<?xml version="1.0" encoding="UTF-8"?>
<device schemaVersion="1.1" xmlns:xs="http://www.w3.org/2001/XMLSchema-instance" xs:noNamespaceSchemaLocation="CMSIS-SVD_Schema_1_1.xsd">
  <vendor>Freescale Semiconductor, Inc.</vendor>
  <vendorID>Freescale</vendorID>
  <series>Kinetis_L</series>
  <name>MKL46Z4</name>
  <version>1.6</version>
  <description>MKL46Z4 Freescale Microcontroller</description>
  <licenseText>Redistribution and use in source and binary forms, with or without modification,\nare permitted provided that the following conditions are met:\n o Redistributions of source code must retain the above copyright notice, this list\n   of conditions and the following disclaimer.\n o Redistributions in binary form must reproduce the above copyright notice, this\n   list of conditions and the following disclaimer in the documentation and/or\n   other materials provided with the distribution.\n o Neither the name of Freescale Semiconductor, Inc. nor the names of its\n   contributors may be used to endorse or promote products derived from this\n   software without specific prior written permission.\n THIS SOFTWARE IS PROVIDED BY THE COPYRIGHT HOLDERS AND CONTRIBUTORS &quot;AS IS&quot; AND\n ANY EXPRESS OR IMPLIED WARRANTIES, INCLUDING, BUT NOT LIMITED TO, THE IMPLIED\n WARRANTIES OF MERCHANTABILITY AND FITNESS FOR A PARTICULAR PURPOSE ARE\n DISCLAIMED. IN NO EVENT SHALL THE COPYRIGHT HOLDER OR CONTRIBUTORS BE LIABLE FOR\n ANY DIRECT, INDIRECT, INCIDENTAL, SPECIAL, EXEMPLARY, OR CONSEQUENTIAL DAMAGES\n (INCLUDING, BUT NOT LIMITED TO, PROCUREMENT OF SUBSTITUTE GOODS OR SERVICES;\n LOSS OF USE, DATA, OR PROFITS; OR BUSINESS INTERRUPTION) HOWEVER CAUSED AND ON\n ANY THEORY OF LIABILITY, WHETHER IN CONTRACT, STRICT LIABILITY, OR TORT\n (INCLUDING NEGLIGENCE OR OTHERWISE) ARISING IN ANY WAY OUT OF THE USE OF THIS\n SOFTWARE, EVEN IF ADVISED OF THE POSSIBILITY OF SUCH DAMAGE.</licenseText>
  <cpu>
    <name>CM0PLUS</name>
    <revision>r0p0</revision>
    <endian>little</endian>
    <mpuPresent>false</mpuPresent>
    <fpuPresent>false</fpuPresent>
    <mpuPresent>false</mpuPresent>
    <vtorPresent>true</vtorPresent>
    <nvicPrioBits>2</nvicPrioBits>
    <vendorSystickConfig>false</vendorSystickConfig>
  </cpu>
  <addressUnitBits>8</addressUnitBits>
  <width>32</width>
  <peripherals>
    <peripheral>
      <name>FTFA_FlashConfig</name>
      <description>Flash configuration field</description>
      <prependToName>NV_</prependToName>
      <baseAddress>0x400</baseAddress>
      <addressBlock>
        <offset>0</offset>
        <size>0xE</size>
        <usage>registers</usage>
      </addressBlock>
      <registers>
        <register>
          <name>BACKKEY3</name>
          <description>Backdoor Comparison Key 3.</description>
          <addressOffset>0</addressOffset>
          <size>8</size>
          <access>read-only</access>
          <resetValue>0xFF</resetValue>
          <resetMask>0xFF</resetMask>
          <fields>
            <field>
              <name>KEY</name>
              <description>Backdoor Comparison Key.</description>
              <bitOffset>0</bitOffset>
              <bitWidth>8</bitWidth>
              <access>read-only</access>
            </field>
          </fields>
        </register>
        <register>
          <name>BACKKEY2</name>
          <description>Backdoor Comparison Key 2.</description>
          <addressOffset>0x1</addressOffset>
          <size>8</size>
          <access>read-only</access>
          <resetValue>0xFF</resetValue>
          <resetMask>0xFF</resetMask>
          <fields>
            <field>
              <name>KEY</name>
              <description>Backdoor Comparison Key.</description>
              <bitOffset>0</bitOffset>
              <bitWidth>8</bitWidth>
              <access>read-only</access>
            </field>
          </fields>
        </register>
        <register>
          <name>BACKKEY1</name>
          <description>Backdoor Comparison Key 1.</description>
          <addressOffset>0x2</addressOffset>
          <size>8</size>
          <access>read-only</access>
          <resetValue>0xFF</resetValue>
          <resetMask>0xFF</resetMask>
          <fields>
            <field>
              <name>KEY</name>
              <description>Backdoor Comparison Key.</description>
              <bitOffset>0</bitOffset>
              <bitWidth>8</bitWidth>
              <access>read-only</access>
            </field>
          </fields>
        </register>
        <register>
          <name>BACKKEY0</name>
          <description>Backdoor Comparison Key 0.</description>
          <addressOffset>0x3</addressOffset>
          <size>8</size>
          <access>read-only</access>
          <resetValue>0xFF</resetValue>
          <resetMask>0xFF</resetMask>
          <fields>
            <field>
              <name>KEY</name>
              <description>Backdoor Comparison Key.</description>
              <bitOffset>0</bitOffset>
              <bitWidth>8</bitWidth>
              <access>read-only</access>
            </field>
          </fields>
        </register>
        <register>
          <name>BACKKEY7</name>
          <description>Backdoor Comparison Key 7.</description>
          <addressOffset>0x4</addressOffset>
          <size>8</size>
          <access>read-only</access>
          <resetValue>0xFF</resetValue>
          <resetMask>0xFF</resetMask>
          <fields>
            <field>
              <name>KEY</name>
              <description>Backdoor Comparison Key.</description>
              <bitOffset>0</bitOffset>
              <bitWidth>8</bitWidth>
              <access>read-only</access>
            </field>
          </fields>
        </register>
        <register>
          <name>BACKKEY6</name>
          <description>Backdoor Comparison Key 6.</description>
          <addressOffset>0x5</addressOffset>
          <size>8</size>
          <access>read-only</access>
          <resetValue>0xFF</resetValue>
          <resetMask>0xFF</resetMask>
          <fields>
            <field>
              <name>KEY</name>
              <description>Backdoor Comparison Key.</description>
              <bitOffset>0</bitOffset>
              <bitWidth>8</bitWidth>
              <access>read-only</access>
            </field>
          </fields>
        </register>
        <register>
          <name>BACKKEY5</name>
          <description>Backdoor Comparison Key 5.</description>
          <addressOffset>0x6</addressOffset>
          <size>8</size>
          <access>read-only</access>
          <resetValue>0xFF</resetValue>
          <resetMask>0xFF</resetMask>
          <fields>
            <field>
              <name>KEY</name>
              <description>Backdoor Comparison Key.</description>
              <bitOffset>0</bitOffset>
              <bitWidth>8</bitWidth>
              <access>read-only</access>
            </field>
          </fields>
        </register>
        <register>
          <name>BACKKEY4</name>
          <description>Backdoor Comparison Key 4.</description>
          <addressOffset>0x7</addressOffset>
          <size>8</size>
          <access>read-only</access>
          <resetValue>0xFF</resetValue>
          <resetMask>0xFF</resetMask>
          <fields>
            <field>
              <name>KEY</name>
              <description>Backdoor Comparison Key.</description>
              <bitOffset>0</bitOffset>
              <bitWidth>8</bitWidth>
              <access>read-only</access>
            </field>
          </fields>
        </register>
        <register>
          <name>FPROT3</name>
          <description>Non-volatile P-Flash Protection 1 - Low Register</description>
          <addressOffset>0x8</addressOffset>
          <size>8</size>
          <access>read-only</access>
          <resetValue>0xFF</resetValue>
          <resetMask>0xFF</resetMask>
          <fields>
            <field>
              <name>PROT</name>
              <description>P-Flash Region Protect</description>
              <bitOffset>0</bitOffset>
              <bitWidth>8</bitWidth>
              <access>read-only</access>
            </field>
          </fields>
        </register>
        <register>
          <name>FPROT2</name>
          <description>Non-volatile P-Flash Protection 1 - High Register</description>
          <addressOffset>0x9</addressOffset>
          <size>8</size>
          <access>read-only</access>
          <resetValue>0xFF</resetValue>
          <resetMask>0xFF</resetMask>
          <fields>
            <field>
              <name>PROT</name>
              <description>P-Flash Region Protect</description>
              <bitOffset>0</bitOffset>
              <bitWidth>8</bitWidth>
              <access>read-only</access>
            </field>
          </fields>
        </register>
        <register>
          <name>FPROT1</name>
          <description>Non-volatile P-Flash Protection 0 - Low Register</description>
          <addressOffset>0xA</addressOffset>
          <size>8</size>
          <access>read-only</access>
          <resetValue>0xFF</resetValue>
          <resetMask>0xFF</resetMask>
          <fields>
            <field>
              <name>PROT</name>
              <description>P-Flash Region Protect</description>
              <bitOffset>0</bitOffset>
              <bitWidth>8</bitWidth>
              <access>read-only</access>
            </field>
          </fields>
        </register>
        <register>
          <name>FPROT0</name>
          <description>Non-volatile P-Flash Protection 0 - High Register</description>
          <addressOffset>0xB</addressOffset>
          <size>8</size>
          <access>read-only</access>
          <resetValue>0xFF</resetValue>
          <resetMask>0xFF</resetMask>
          <fields>
            <field>
              <name>PROT</name>
              <description>P-Flash Region Protect</description>
              <bitOffset>0</bitOffset>
              <bitWidth>8</bitWidth>
              <access>read-only</access>
            </field>
          </fields>
        </register>
        <register>
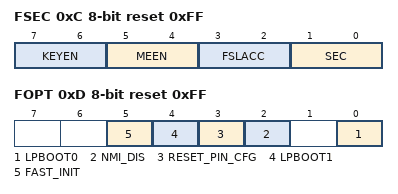
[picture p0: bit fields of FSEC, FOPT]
          <name>FSEC</name>
          <description>Non-volatile Flash Security Register</description>
          <addressOffset>0xC</addressOffset>
          <size>8</size>
          <access>read-only</access>
          <resetValue>0xFF</resetValue>
          <resetMask>0xFF</resetMask>
          <fields>
            <field>
              <name>SEC</name>
              <description>Flash Security</description>
              <bitOffset>0</bitOffset>
              <bitWidth>2</bitWidth>
              <access>read-only</access>
              <enumeratedValues>
                <enumeratedValue>
                  <name>10</name>
                  <description>MCU security status is unsecure</description>
                  <value>#10</value>
                </enumeratedValue>
                <enumeratedValue>
                  <name>11</name>
                  <description>MCU security status is secure</description>
                  <value>#11</value>
                </enumeratedValue>
              </enumeratedValues>
            </field>
            <field>
              <name>FSLACC</name>
              <description>Freescale Failure Analysis Access Code</description>
              <bitOffset>2</bitOffset>
              <bitWidth>2</bitWidth>
              <access>read-only</access>
              <enumeratedValues>
                <enumeratedValue>
                  <name>10</name>
                  <description>Freescale factory access denied</description>
                  <value>#10</value>
                </enumeratedValue>
                <enumeratedValue>
                  <name>11</name>
                  <description>Freescale factory access granted</description>
                  <value>#11</value>
                </enumeratedValue>
              </enumeratedValues>
            </field>
            <field>
              <name>MEEN</name>
              <description>no description available</description>
              <bitOffset>4</bitOffset>
              <bitWidth>2</bitWidth>
              <access>read-only</access>
              <enumeratedValues>
                <enumeratedValue>
                  <name>10</name>
                  <description>Mass erase is disabled</description>
                  <value>#10</value>
                </enumeratedValue>
                <enumeratedValue>
                  <name>11</name>
                  <description>Mass erase is enabled</description>
                  <value>#11</value>
                </enumeratedValue>
              </enumeratedValues>
            </field>
            <field>
              <name>KEYEN</name>
              <description>Backdoor Key Security Enable</description>
              <bitOffset>6</bitOffset>
              <bitWidth>2</bitWidth>
              <access>read-only</access>
              <enumeratedValues>
                <enumeratedValue>
                  <name>10</name>
                  <description>Backdoor key access enabled</description>
                  <value>#10</value>
                </enumeratedValue>
                <enumeratedValue>
                  <name>11</name>
                  <description>Backdoor key access disabled</description>
                  <value>#11</value>
                </enumeratedValue>
              </enumeratedValues>
            </field>
          </fields>
        </register>
        <register>
          <name>FOPT</name>
          <description>Non-volatile Flash Option Register</description>
          <addressOffset>0xD</addressOffset>
          <size>8</size>
          <access>read-only</access>
          <resetValue>0xFF</resetValue>
          <resetMask>0xFF</resetMask>
          <fields>
            <field>
              <name>LPBOOT0</name>
              <description>no description available</description>
              <bitOffset>0</bitOffset>
              <bitWidth>1</bitWidth>
              <access>read-only</access>
              <enumeratedValues>
                <enumeratedValue>
                  <name>00</name>
                  <description>Core and system clock divider (OUTDIV1) is 0x7 (divide by 8) when LPBOOT1=0 or 0x1 (divide by 2) when LPBOOT1=1.</description>
                  <value>#0</value>
                </enumeratedValue>
                <enumeratedValue>
                  <name>01</name>
                  <description>Core and system clock divider (OUTDIV1) is 0x3 (divide by 4) when LPBOOT1=0 or 0x0 (divide by 1) when LPBOOT1=1.</description>
                  <value>#1</value>
                </enumeratedValue>
              </enumeratedValues>
            </field>
            <field>
              <name>NMI_DIS</name>
              <description>no description available</description>
              <bitOffset>2</bitOffset>
              <bitWidth>1</bitWidth>
              <access>read-only</access>
              <enumeratedValues>
                <enumeratedValue>
                  <name>00</name>
                  <description>NMI interrupts are always blocked</description>
                  <value>#0</value>
                </enumeratedValue>
                <enumeratedValue>
                  <name>01</name>
                  <description>NMI_b pin/interrupts reset default to enabled</description>
                  <value>#1</value>
                </enumeratedValue>
              </enumeratedValues>
            </field>
            <field>
              <name>RESET_PIN_CFG</name>
              <description>no description available</description>
              <bitOffset>3</bitOffset>
              <bitWidth>1</bitWidth>
              <access>read-only</access>
              <enumeratedValues>
                <enumeratedValue>
                  <name>00</name>
                  <description>RESET pin is disabled following a POR and cannot be enabled as reset function</description>
                  <value>#0</value>
                </enumeratedValue>
                <enumeratedValue>
                  <name>01</name>
                  <description>RESET_b pin is dedicated</description>
                  <value>#1</value>
                </enumeratedValue>
              </enumeratedValues>
            </field>
            <field>
              <name>LPBOOT1</name>
              <description>no description available</description>
              <bitOffset>4</bitOffset>
              <bitWidth>1</bitWidth>
              <access>read-only</access>
              <enumeratedValues>
                <enumeratedValue>
                  <name>00</name>
                  <description>Core and system clock divider (OUTDIV1) is 0x7 (divide by 8) when LPBOOT0=0 or 0x3 (divide by 4) when LPBOOT0=1.</description>
                  <value>#0</value>
                </enumeratedValue>
                <enumeratedValue>
                  <name>01</name>
                  <description>Core and system clock divider (OUTDIV1) is 0x1 (divide by 2) when LPBOOT0=0 or 0x0 (divide by 1) when LPBOOT0=1.</description>
                  <value>#1</value>
                </enumeratedValue>
              </enumeratedValues>
            </field>
            <field>
              <name>FAST_INIT</name>
              <description>no description available</description>
              <bitOffset>5</bitOffset>
              <bitWidth>1</bitWidth>
              <access>read-only</access>
              <enumeratedValues>
                <enumeratedValue>
                  <name>00</name>
                  <description>Slower initialization</description>
                  <value>#0</value>
                </enumeratedValue>
                <enumeratedValue>
                  <name>01</name>
                  <description>Fast Initialization</description>
                  <value>#1</value>
                </enumeratedValue>
              </enumeratedValues>
            </field>
          </fields>
        </register>
      </registers>
    </peripheral>
    <peripheral>
      <name>DMA</name>
      <description>DMA Controller</description>
      <prependToName>DMA_</prependToName>
      <baseAddress>0x40008000</baseAddress>
      <addressBlock>
        <offset>0x100</offset>
        <size>0x40</size>
        <usage>registers</usage>
      </addressBlock>
      <interrupt>
        <name>DMA0</name>
        <value>0</value>
      </interrupt>
      <interrupt>
        <name>DMA1</name>
        <value>1</value>
      </interrupt>
      <interrupt>
        <name>DMA2</name>
        <value>2</value>
      </interrupt>
      <interrupt>
        <name>DMA3</name>
        <value>3</value>
      </interrupt>
      <registers>
        <register>
          <name>SAR0</name>
          <description>Source Address Register</description>
          <addressOffset>0x100</addressOffset>
          <size>32</size>
          <access>read-write</access>
          <resetValue>0</resetValue>
          <resetMask>0xFFFFFFFF</resetMask>
          <fields>
            <field>
              <name>SAR</name>
              <description>Each SAR contains the byte address used by the DMA controller to read data</description>
              <bitOffset>0</bitOffset>
              <bitWidth>32</bitWidth>
              <access>read-write</access>
            </field>
          </fields>
        </register>
        <register>
          <name>DAR0</name>
          <description>Destination Address Register</description>
          <addressOffset>0x104</addressOffset>
          <size>32</size>
          <access>read-write</access>
          <resetValue>0</resetValue>
          <resetMask>0xFFFFFFFF</resetMask>
          <fields>
            <field>
              <name>DAR</name>
              <description>Each DAR contains the byte address used by the DMA controller to write data</description>
              <bitOffset>0</bitOffset>
              <bitWidth>32</bitWidth>
              <access>read-write</access>
            </field>
          </fields>
        </register>
        <register>
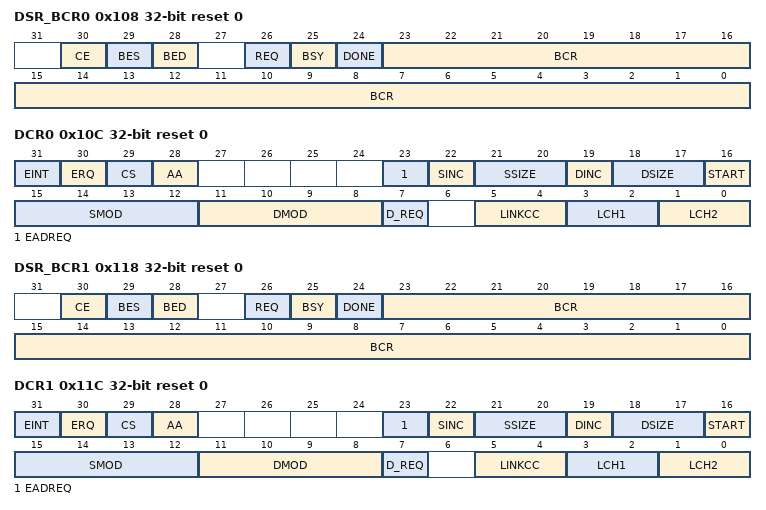
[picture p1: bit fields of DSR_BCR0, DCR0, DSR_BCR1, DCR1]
          <name>DSR_BCR0</name>
          <description>DMA Status Register / Byte Count Register</description>
          <addressOffset>0x108</addressOffset>
          <size>32</size>
          <access>read-write</access>
          <resetValue>0</resetValue>
          <resetMask>0xFFFFFFFF</resetMask>
          <fields>
            <field>
              <name>BCR</name>
              <description>This field contains the number of bytes yet to be transferred for a given block</description>
              <bitOffset>0</bitOffset>
              <bitWidth>24</bitWidth>
              <access>read-write</access>
            </field>
            <field>
              <name>DONE</name>
              <description>Transactions Done</description>
              <bitOffset>24</bitOffset>
              <bitWidth>1</bitWidth>
              <access>read-write</access>
              <enumeratedValues>
                <enumeratedValue>
                  <name>0</name>
                  <description>DMA transfer is not yet complete. Writing a 0 has no effect.</description>
                  <value>#0</value>
                </enumeratedValue>
                <enumeratedValue>
                  <name>1</name>
                  <description>DMA transfer completed. Writing a 1 to this bit clears all DMA status bits and should be used in an interrupt service routine to clear the DMA interrupt and error bits.</description>
                  <value>#1</value>
                </enumeratedValue>
              </enumeratedValues>
            </field>
            <field>
              <name>BSY</name>
              <description>Busy</description>
              <bitOffset>25</bitOffset>
              <bitWidth>1</bitWidth>
              <access>read-only</access>
              <enumeratedValues>
                <enumeratedValue>
                  <name>0</name>
                  <description>DMA channel is inactive. Cleared when the DMA has finished the last transaction.</description>
                  <value>#0</value>
                </enumeratedValue>
                <enumeratedValue>
                  <name>1</name>
                  <description>BSY is set the first time the channel is enabled after a transfer is initiated.</description>
                  <value>#1</value>
                </enumeratedValue>
              </enumeratedValues>
            </field>
            <field>
              <name>REQ</name>
              <description>Request</description>
              <bitOffset>26</bitOffset>
              <bitWidth>1</bitWidth>
              <access>read-only</access>
              <enumeratedValues>
                <enumeratedValue>
                  <name>0</name>
                  <description>No request is pending or the channel is currently active. Cleared when the channel is selected.</description>
                  <value>#0</value>
                </enumeratedValue>
                <enumeratedValue>
                  <name>1</name>
                  <description>The DMA channel has a transfer remaining and the channel is not selected.</description>
                  <value>#1</value>
                </enumeratedValue>
              </enumeratedValues>
            </field>
            <field>
              <name>BED</name>
              <description>Bus Error on Destination</description>
              <bitOffset>28</bitOffset>
              <bitWidth>1</bitWidth>
              <access>read-only</access>
              <enumeratedValues>
                <enumeratedValue>
                  <name>0</name>
                  <description>No bus error occurred.</description>
                  <value>#0</value>
                </enumeratedValue>
                <enumeratedValue>
                  <name>1</name>
                  <description>The DMA channel terminated with a bus error during the write portion of a transfer.</description>
                  <value>#1</value>
                </enumeratedValue>
              </enumeratedValues>
            </field>
            <field>
              <name>BES</name>
              <description>Bus Error on Source</description>
              <bitOffset>29</bitOffset>
              <bitWidth>1</bitWidth>
              <access>read-only</access>
              <enumeratedValues>
                <enumeratedValue>
                  <name>0</name>
                  <description>No bus error occurred.</description>
                  <value>#0</value>
                </enumeratedValue>
                <enumeratedValue>
                  <name>1</name>
                  <description>The DMA channel terminated with a bus error during the read portion of a transfer.</description>
                  <value>#1</value>
                </enumeratedValue>
              </enumeratedValues>
            </field>
            <field>
              <name>CE</name>
              <description>Configuration Error</description>
              <bitOffset>30</bitOffset>
              <bitWidth>1</bitWidth>
              <access>read-only</access>
              <enumeratedValues>
                <enumeratedValue>
                  <name>0</name>
                  <description>No configuration error exists.</description>
                  <value>#0</value>
                </enumeratedValue>
                <enumeratedValue>
                  <name>1</name>
                  <description>A configuration error has occurred.</description>
                  <value>#1</value>
                </enumeratedValue>
              </enumeratedValues>
            </field>
          </fields>
        </register>
        <register>
          <name>DSR0</name>
          <description>DMA_DSR0 register.</description>
          <addressOffset>0x10B</addressOffset>
          <size>8</size>
          <access>read-write</access>
          <resetValue>0</resetValue>
          <resetMask>0xFF</resetMask>
        </register>
        <register>
          <name>DCR0</name>
          <description>DMA Control Register</description>
          <addressOffset>0x10C</addressOffset>
          <size>32</size>
          <access>read-write</access>
          <resetValue>0</resetValue>
          <resetMask>0xFFFFFFFF</resetMask>
          <fields>
            <field>
              <name>LCH2</name>
              <description>Link Channel 2</description>
              <bitOffset>0</bitOffset>
              <bitWidth>2</bitWidth>
              <access>read-write</access>
              <enumeratedValues>
                <enumeratedValue>
                  <name>00</name>
                  <description>DMA Channel 0</description>
                  <value>#00</value>
                </enumeratedValue>
                <enumeratedValue>
                  <name>01</name>
                  <description>DMA Channel 1</description>
                  <value>#01</value>
                </enumeratedValue>
                <enumeratedValue>
                  <name>10</name>
                  <description>DMA Channel 2</description>
                  <value>#10</value>
                </enumeratedValue>
                <enumeratedValue>
                  <name>11</name>
                  <description>DMA Channel 3</description>
                  <value>#11</value>
                </enumeratedValue>
              </enumeratedValues>
            </field>
            <field>
              <name>LCH1</name>
              <description>Link Channel 1</description>
              <bitOffset>2</bitOffset>
              <bitWidth>2</bitWidth>
              <access>read-write</access>
              <enumeratedValues>
                <enumeratedValue>
                  <name>00</name>
                  <description>DMA Channel 0</description>
                  <value>#00</value>
                </enumeratedValue>
                <enumeratedValue>
                  <name>01</name>
                  <description>DMA Channel 1</description>
                  <value>#01</value>
                </enumeratedValue>
                <enumeratedValue>
                  <name>10</name>
                  <description>DMA Channel 2</description>
                  <value>#10</value>
                </enumeratedValue>
                <enumeratedValue>
                  <name>11</name>
                  <description>DMA Channel 3</description>
                  <value>#11</value>
                </enumeratedValue>
              </enumeratedValues>
            </field>
            <field>
              <name>LINKCC</name>
              <description>Link Channel Control</description>
              <bitOffset>4</bitOffset>
              <bitWidth>2</bitWidth>
              <access>read-write</access>
              <enumeratedValues>
                <enumeratedValue>
                  <name>00</name>
                  <description>No channel-to-channel linking</description>
                  <value>#00</value>
                </enumeratedValue>
                <enumeratedValue>
                  <name>01</name>
                  <description>Perform a link to channel LCH1 after each cycle-steal transfer followed by a link to LCH2 after the BCR decrements to 0.</description>
                  <value>#01</value>
                </enumeratedValue>
                <enumeratedValue>
                  <name>10</name>
                  <description>Perform a link to channel LCH1 after each cycle-steal transfer</description>
                  <value>#10</value>
                </enumeratedValue>
                <enumeratedValue>
                  <name>11</name>
                  <description>Perform a link to channel LCH1 after the BCR decrements to 0.</description>
                  <value>#11</value>
                </enumeratedValue>
              </enumeratedValues>
            </field>
            <field>
              <name>D_REQ</name>
              <description>Disable Request</description>
              <bitOffset>7</bitOffset>
              <bitWidth>1</bitWidth>
              <access>read-write</access>
              <enumeratedValues>
                <enumeratedValue>
                  <name>0</name>
                  <description>ERQ bit is not affected.</description>
                  <value>#0</value>
                </enumeratedValue>
                <enumeratedValue>
                  <name>1</name>
                  <description>ERQ bit is cleared when the BCR is exhausted.</description>
                  <value>#1</value>
                </enumeratedValue>
              </enumeratedValues>
            </field>
            <field>
              <name>DMOD</name>
              <description>Destination Address Modulo</description>
              <bitOffset>8</bitOffset>
              <bitWidth>4</bitWidth>
              <access>read-write</access>
              <enumeratedValues>
                <enumeratedValue>
                  <name>0000</name>
                  <description>Buffer disabled</description>
                  <value>#0000</value>
                </enumeratedValue>
                <enumeratedValue>
                  <name>0001</name>
                  <description>Circular buffer size is 16 bytes</description>
                  <value>#0001</value>
                </enumeratedValue>
                <enumeratedValue>
                  <name>0010</name>
                  <description>Circular buffer size is 32 bytes</description>
                  <value>#0010</value>
                </enumeratedValue>
                <enumeratedValue>
                  <name>0011</name>
                  <description>Circular buffer size is 64 bytes</description>
                  <value>#0011</value>
                </enumeratedValue>
                <enumeratedValue>
                  <name>0100</name>
                  <description>Circular buffer size is 128 bytes</description>
                  <value>#0100</value>
                </enumeratedValue>
                <enumeratedValue>
                  <name>0101</name>
                  <description>Circular buffer size is 256 bytes</description>
                  <value>#0101</value>
                </enumeratedValue>
                <enumeratedValue>
                  <name>0110</name>
                  <description>Circular buffer size is 512 bytes</description>
                  <value>#0110</value>
                </enumeratedValue>
                <enumeratedValue>
                  <name>0111</name>
                  <description>Circular buffer size is 1 KB</description>
                  <value>#0111</value>
                </enumeratedValue>
                <enumeratedValue>
                  <name>1000</name>
                  <description>Circular buffer size is 2 KB</description>
                  <value>#1000</value>
                </enumeratedValue>
                <enumeratedValue>
                  <name>1001</name>
                  <description>Circular buffer size is 4 KB</description>
                  <value>#1001</value>
                </enumeratedValue>
                <enumeratedValue>
                  <name>1010</name>
                  <description>Circular buffer size is 8 KB</description>
                  <value>#1010</value>
                </enumeratedValue>
                <enumeratedValue>
                  <name>1011</name>
                  <description>Circular buffer size is 16 KB</description>
                  <value>#1011</value>
                </enumeratedValue>
                <enumeratedValue>
                  <name>1100</name>
                  <description>Circular buffer size is 32 KB</description>
                  <value>#1100</value>
                </enumeratedValue>
                <enumeratedValue>
                  <name>1101</name>
                  <description>Circular buffer size is 64 KB</description>
                  <value>#1101</value>
                </enumeratedValue>
                <enumeratedValue>
                  <name>1110</name>
                  <description>Circular buffer size is 128 KB</description>
                  <value>#1110</value>
                </enumeratedValue>
                <enumeratedValue>
                  <name>1111</name>
                  <description>Circular buffer size is 256 KB</description>
                  <value>#1111</value>
                </enumeratedValue>
              </enumeratedValues>
            </field>
            <field>
              <name>SMOD</name>
              <description>Source Address Modulo</description>
              <bitOffset>12</bitOffset>
              <bitWidth>4</bitWidth>
              <access>read-write</access>
              <enumeratedValues>
                <enumeratedValue>
                  <name>0000</name>
                  <description>Buffer disabled</description>
                  <value>#0000</value>
                </enumeratedValue>
                <enumeratedValue>
                  <name>0001</name>
                  <description>Circular buffer size is 16 bytes.</description>
                  <value>#0001</value>
                </enumeratedValue>
                <enumeratedValue>
                  <name>0010</name>
                  <description>Circular buffer size is 32 bytes.</description>
                  <value>#0010</value>
                </enumeratedValue>
                <enumeratedValue>
                  <name>0011</name>
                  <description>Circular buffer size is 64 bytes.</description>
                  <value>#0011</value>
                </enumeratedValue>
                <enumeratedValue>
                  <name>0100</name>
                  <description>Circular buffer size is 128 bytes.</description>
                  <value>#0100</value>
                </enumeratedValue>
                <enumeratedValue>
                  <name>0101</name>
                  <description>Circular buffer size is 256 bytes.</description>
                  <value>#0101</value>
                </enumeratedValue>
                <enumeratedValue>
                  <name>0110</name>
                  <description>Circular buffer size is 512 bytes.</description>
                  <value>#0110</value>
                </enumeratedValue>
                <enumeratedValue>
                  <name>0111</name>
                  <description>Circular buffer size is 1 KB.</description>
                  <value>#0111</value>
                </enumeratedValue>
                <enumeratedValue>
                  <name>1000</name>
                  <description>Circular buffer size is 2 KB.</description>
                  <value>#1000</value>
                </enumeratedValue>
                <enumeratedValue>
                  <name>1001</name>
                  <description>Circular buffer size is 4 KB.</description>
                  <value>#1001</value>
                </enumeratedValue>
                <enumeratedValue>
                  <name>1010</name>
                  <description>Circular buffer size is 8 KB.</description>
                  <value>#1010</value>
                </enumeratedValue>
                <enumeratedValue>
                  <name>1011</name>
                  <description>Circular buffer size is 16 KB.</description>
                  <value>#1011</value>
                </enumeratedValue>
                <enumeratedValue>
                  <name>1100</name>
                  <description>Circular buffer size is 32 KB.</description>
                  <value>#1100</value>
                </enumeratedValue>
                <enumeratedValue>
                  <name>1101</name>
                  <description>Circular buffer size is 64 KB.</description>
                  <value>#1101</value>
                </enumeratedValue>
                <enumeratedValue>
                  <name>1110</name>
                  <description>Circular buffer size is 128 KB.</description>
                  <value>#1110</value>
                </enumeratedValue>
                <enumeratedValue>
                  <name>1111</name>
                  <description>Circular buffer size is 256 KB.</description>
                  <value>#1111</value>
                </enumeratedValue>
              </enumeratedValues>
            </field>
            <field>
              <name>START</name>
              <description>Start Transfer</description>
              <bitOffset>16</bitOffset>
              <bitWidth>1</bitWidth>
              <access>write-only</access>
              <enumeratedValues>
                <enumeratedValue>
                  <name>0</name>
                  <description>DMA inactive</description>
                  <value>#0</value>
                </enumeratedValue>
                <enumeratedValue>
                  <name>1</name>
                  <description>The DMA begins the transfer in accordance to the values in the TCDn. START is cleared automatically after one module clock and always reads as logic 0.</description>
                  <value>#1</value>
                </enumeratedValue>
              </enumeratedValues>
            </field>
            <field>
              <name>DSIZE</name>
              <description>Destination Size</description>
              <bitOffset>17</bitOffset>
              <bitWidth>2</bitWidth>
              <access>read-write</access>
              <enumeratedValues>
                <enumeratedValue>
                  <name>00</name>
                  <description>32-bit</description>
                  <value>#00</value>
                </enumeratedValue>
                <enumeratedValue>
                  <name>01</name>
                  <description>8-bit</description>
                  <value>#01</value>
                </enumeratedValue>
                <enumeratedValue>
                  <name>10</name>
                  <description>16-bit</description>
                  <value>#10</value>
                </enumeratedValue>
                <enumeratedValue>
                  <name>11</name>
                  <description>Reserved (generates a configuration error (DSRn[CE]) if incorrectly specified at time of channel activation)</description>
                  <value>#11</value>
                </enumeratedValue>
              </enumeratedValues>
            </field>
            <field>
              <name>DINC</name>
              <description>Destination Increment</description>
              <bitOffset>19</bitOffset>
              <bitWidth>1</bitWidth>
              <access>read-write</access>
              <enumeratedValues>
                <enumeratedValue>
                  <name>0</name>
                  <description>No change to the DAR after a successful transfer.</description>
                  <value>#0</value>
                </enumeratedValue>
                <enumeratedValue>
                  <name>1</name>
                  <description>The DAR increments by 1, 2, 4 depending upon the size of the transfer.</description>
                  <value>#1</value>
                </enumeratedValue>
              </enumeratedValues>
            </field>
            <field>
              <name>SSIZE</name>
              <description>Source Size</description>
              <bitOffset>20</bitOffset>
              <bitWidth>2</bitWidth>
              <access>read-write</access>
              <enumeratedValues>
                <enumeratedValue>
                  <name>00</name>
                  <description>32-bit</description>
                  <value>#00</value>
                </enumeratedValue>
                <enumeratedValue>
                  <name>01</name>
                  <description>8-bit</description>
                  <value>#01</value>
                </enumeratedValue>
                <enumeratedValue>
                  <name>10</name>
                  <description>16-bit</description>
                  <value>#10</value>
                </enumeratedValue>
                <enumeratedValue>
                  <name>11</name>
                  <description>Reserved (generates a configuration error (DSRn[CE]) if incorrectly specified at time of channel activation)</description>
                  <value>#11</value>
                </enumeratedValue>
              </enumeratedValues>
            </field>
            <field>
              <name>SINC</name>
              <description>Source Increment</description>
              <bitOffset>22</bitOffset>
              <bitWidth>1</bitWidth>
              <access>read-write</access>
              <enumeratedValues>
                <enumeratedValue>
                  <name>0</name>
                  <description>No change to SAR after a successful transfer.</description>
                  <value>#0</value>
                </enumeratedValue>
                <enumeratedValue>
                  <name>1</name>
                  <description>The SAR increments by 1, 2, 4 as determined by the transfer size.</description>
                  <value>#1</value>
                </enumeratedValue>
              </enumeratedValues>
            </field>
            <field>
              <name>EADREQ</name>
              <description>Enable asynchronous DMA requests</description>
              <bitOffset>23</bitOffset>
              <bitWidth>1</bitWidth>
              <access>read-write</access>
              <enumeratedValues>
                <enumeratedValue>
                  <name>0</name>
                  <description>Disabled</description>
                  <value>#0</value>
                </enumeratedValue>
                <enumeratedValue>
                  <name>1</name>
                  <description>Enabled</description>
                  <value>#1</value>
                </enumeratedValue>
              </enumeratedValues>
            </field>
            <field>
              <name>AA</name>
              <description>Auto-align</description>
              <bitOffset>28</bitOffset>
              <bitWidth>1</bitWidth>
              <access>read-write</access>
              <enumeratedValues>
                <enumeratedValue>
                  <name>0</name>
                  <description>Auto-align disabled</description>
                  <value>#0</value>
                </enumeratedValue>
                <enumeratedValue>
                  <name>1</name>
                  <description>If SSIZE indicates a transfer no smaller than DSIZE, source accesses are auto-aligned; otherwise, destination accesses are auto-aligned. Source alignment takes precedence over destination alignment. If auto-alignment is enabled, the appropriate address register increments, regardless of DINC or SINC.</description>
                  <value>#1</value>
                </enumeratedValue>
              </enumeratedValues>
            </field>
            <field>
              <name>CS</name>
              <description>Cycle Steal</description>
              <bitOffset>29</bitOffset>
              <bitWidth>1</bitWidth>
              <access>read-write</access>
              <enumeratedValues>
                <enumeratedValue>
                  <name>0</name>
                  <description>DMA continuously makes read/write transfers until the BCR decrements to 0.</description>
                  <value>#0</value>
                </enumeratedValue>
                <enumeratedValue>
                  <name>1</name>
                  <description>Forces a single read/write transfer per request.</description>
                  <value>#1</value>
                </enumeratedValue>
              </enumeratedValues>
            </field>
            <field>
              <name>ERQ</name>
              <description>Enable Peripheral Request</description>
              <bitOffset>30</bitOffset>
              <bitWidth>1</bitWidth>
              <access>read-write</access>
              <enumeratedValues>
                <enumeratedValue>
                  <name>0</name>
                  <description>Peripheral request is ignored.</description>
                  <value>#0</value>
                </enumeratedValue>
                <enumeratedValue>
                  <name>1</name>
                  <description>Enables peripheral request to initiate transfer. A software-initiated request (setting START) is always enabled.</description>
                  <value>#1</value>
                </enumeratedValue>
              </enumeratedValues>
            </field>
            <field>
              <name>EINT</name>
              <description>Enable Interrupt on Completion of Transfer</description>
              <bitOffset>31</bitOffset>
              <bitWidth>1</bitWidth>
              <access>read-write</access>
              <enumeratedValues>
                <enumeratedValue>
                  <name>0</name>
                  <description>No interrupt is generated.</description>
                  <value>#0</value>
                </enumeratedValue>
                <enumeratedValue>
                  <name>1</name>
                  <description>Interrupt signal is enabled.</description>
                  <value>#1</value>
                </enumeratedValue>
              </enumeratedValues>
            </field>
          </fields>
        </register>
        <register>
          <name>SAR1</name>
          <description>Source Address Register</description>
          <addressOffset>0x110</addressOffset>
          <size>32</size>
          <access>read-write</access>
          <resetValue>0</resetValue>
          <resetMask>0xFFFFFFFF</resetMask>
          <fields>
            <field>
              <name>SAR</name>
              <description>Each SAR contains the byte address used by the DMA controller to read data</description>
              <bitOffset>0</bitOffset>
              <bitWidth>32</bitWidth>
              <access>read-write</access>
            </field>
          </fields>
        </register>
        <register>
          <name>DAR1</name>
          <description>Destination Address Register</description>
          <addressOffset>0x114</addressOffset>
          <size>32</size>
          <access>read-write</access>
          <resetValue>0</resetValue>
          <resetMask>0xFFFFFFFF</resetMask>
          <fields>
            <field>
              <name>DAR</name>
              <description>Each DAR contains the byte address used by the DMA controller to write data</description>
              <bitOffset>0</bitOffset>
              <bitWidth>32</bitWidth>
              <access>read-write</access>
            </field>
          </fields>
        </register>
        <register>
          <name>DSR_BCR1</name>
          <description>DMA Status Register / Byte Count Register</description>
          <addressOffset>0x118</addressOffset>
          <size>32</size>
          <access>read-write</access>
          <resetValue>0</resetValue>
          <resetMask>0xFFFFFFFF</resetMask>
          <fields>
            <field>
              <name>BCR</name>
              <description>This field contains the number of bytes yet to be transferred for a given block</description>
              <bitOffset>0</bitOffset>
              <bitWidth>24</bitWidth>
              <access>read-write</access>
            </field>
            <field>
              <name>DONE</name>
              <description>Transactions Done</description>
              <bitOffset>24</bitOffset>
              <bitWidth>1</bitWidth>
              <access>read-write</access>
              <enumeratedValues>
                <enumeratedValue>
                  <name>0</name>
                  <description>DMA transfer is not yet complete. Writing a 0 has no effect.</description>
                  <value>#0</value>
                </enumeratedValue>
                <enumeratedValue>
                  <name>1</name>
                  <description>DMA transfer completed. Writing a 1 to this bit clears all DMA status bits and should be used in an interrupt service routine to clear the DMA interrupt and error bits.</description>
                  <value>#1</value>
                </enumeratedValue>
              </enumeratedValues>
            </field>
            <field>
              <name>BSY</name>
              <description>Busy</description>
              <bitOffset>25</bitOffset>
              <bitWidth>1</bitWidth>
              <access>read-only</access>
              <enumeratedValues>
                <enumeratedValue>
                  <name>0</name>
                  <description>DMA channel is inactive. Cleared when the DMA has finished the last transaction.</description>
                  <value>#0</value>
                </enumeratedValue>
                <enumeratedValue>
                  <name>1</name>
                  <description>BSY is set the first time the channel is enabled after a transfer is initiated.</description>
                  <value>#1</value>
                </enumeratedValue>
              </enumeratedValues>
            </field>
            <field>
              <name>REQ</name>
              <description>Request</description>
              <bitOffset>26</bitOffset>
              <bitWidth>1</bitWidth>
              <access>read-only</access>
              <enumeratedValues>
                <enumeratedValue>
                  <name>0</name>
                  <description>No request is pending or the channel is currently active. Cleared when the channel is selected.</description>
                  <value>#0</value>
                </enumeratedValue>
                <enumeratedValue>
                  <name>1</name>
                  <description>The DMA channel has a transfer remaining and the channel is not selected.</description>
                  <value>#1</value>
                </enumeratedValue>
              </enumeratedValues>
            </field>
            <field>
              <name>BED</name>
              <description>Bus Error on Destination</description>
              <bitOffset>28</bitOffset>
              <bitWidth>1</bitWidth>
              <access>read-only</access>
              <enumeratedValues>
                <enumeratedValue>
                  <name>0</name>
                  <description>No bus error occurred.</description>
                  <value>#0</value>
                </enumeratedValue>
                <enumeratedValue>
                  <name>1</name>
                  <description>The DMA channel terminated with a bus error during the write portion of a transfer.</description>
                  <value>#1</value>
                </enumeratedValue>
              </enumeratedValues>
            </field>
            <field>
              <name>BES</name>
              <description>Bus Error on Source</description>
              <bitOffset>29</bitOffset>
              <bitWidth>1</bitWidth>
              <access>read-only</access>
              <enumeratedValues>
                <enumeratedValue>
                  <name>0</name>
                  <description>No bus error occurred.</description>
                  <value>#0</value>
                </enumeratedValue>
                <enumeratedValue>
                  <name>1</name>
                  <description>The DMA channel terminated with a bus error during the read portion of a transfer.</description>
                  <value>#1</value>
                </enumeratedValue>
              </enumeratedValues>
            </field>
            <field>
              <name>CE</name>
              <description>Configuration Error</description>
              <bitOffset>30</bitOffset>
              <bitWidth>1</bitWidth>
              <access>read-only</access>
              <enumeratedValues>
                <enumeratedValue>
                  <name>0</name>
                  <description>No configuration error exists.</description>
                  <value>#0</value>
                </enumeratedValue>
                <enumeratedValue>
                  <name>1</name>
                  <description>A configuration error has occurred.</description>
                  <value>#1</value>
                </enumeratedValue>
              </enumeratedValues>
            </field>
          </fields>
        </register>
        <register>
          <name>DSR1</name>
          <description>DMA_DSR1 register.</description>
          <addressOffset>0x11B</addressOffset>
          <size>8</size>
          <access>read-write</access>
          <resetValue>0</resetValue>
          <resetMask>0xFF</resetMask>
        </register>
        <register>
          <name>DCR1</name>
          <description>DMA Control Register</description>
          <addressOffset>0x11C</addressOffset>
          <size>32</size>
          <access>read-write</access>
          <resetValue>0</resetValue>
          <resetMask>0xFFFFFFFF</resetMask>
          <fields>
            <field>
              <name>LCH2</name>
              <description>Link Channel 2</description>
              <bitOffset>0</bitOffset>
              <bitWidth>2</bitWidth>
              <access>read-write</access>
              <enumeratedValues>
                <enumeratedValue>
                  <name>00</name>
                  <description>DMA Channel 0</description>
                  <value>#00</value>
                </enumeratedValue>
                <enumeratedValue>
                  <name>01</name>
                  <description>DMA Channel 1</description>
                  <value>#01</value>
                </enumeratedValue>
                <enumeratedValue>
                  <name>10</name>
                  <description>DMA Channel 2</description>
                  <value>#10</value>
                </enumeratedValue>
                <enumeratedValue>
                  <name>11</name>
                  <description>DMA Channel 3</description>
                  <value>#11</value>
                </enumeratedValue>
              </enumeratedValues>
            </field>
            <field>
              <name>LCH1</name>
              <description>Link Channel 1</description>
              <bitOffset>2</bitOffset>
              <bitWidth>2</bitWidth>
              <access>read-write</access>
              <enumeratedValues>
                <enumeratedValue>
                  <name>00</name>
                  <description>DMA Channel 0</description>
                  <value>#00</value>
                </enumeratedValue>
                <enumeratedValue>
                  <name>01</name>
                  <description>DMA Channel 1</description>
                  <value>#01</value>
                </enumeratedValue>
                <enumeratedValue>
                  <name>10</name>
                  <description>DMA Channel 2</description>
                  <value>#10</value>
                </enumeratedValue>
                <enumeratedValue>
                  <name>11</name>
                  <description>DMA Channel 3</description>
                  <value>#11</value>
                </enumeratedValue>
              </enumeratedValues>
            </field>
            <field>
              <name>LINKCC</name>
              <description>Link Channel Control</description>
              <bitOffset>4</bitOffset>
              <bitWidth>2</bitWidth>
              <access>read-write</access>
              <enumeratedValues>
                <enumeratedValue>
                  <name>00</name>
                  <description>No channel-to-channel linking</description>
                  <value>#00</value>
                </enumeratedValue>
                <enumeratedValue>
                  <name>01</name>
                  <description>Perform a link to channel LCH1 after each cycle-steal transfer followed by a link to LCH2 after the BCR decrements to 0.</description>
                  <value>#01</value>
                </enumeratedValue>
                <enumeratedValue>
                  <name>10</name>
                  <description>Perform a link to channel LCH1 after each cycle-steal transfer</description>
                  <value>#10</value>
                </enumeratedValue>
                <enumeratedValue>
                  <name>11</name>
                  <description>Perform a link to channel LCH1 after the BCR decrements to 0.</description>
                  <value>#11</value>
                </enumeratedValue>
              </enumeratedValues>
            </field>
            <field>
              <name>D_REQ</name>
              <description>Disable Request</description>
              <bitOffset>7</bitOffset>
              <bitWidth>1</bitWidth>
              <access>read-write</access>
              <enumeratedValues>
                <enumeratedValue>
                  <name>0</name>
                  <description>ERQ bit is not affected.</description>
                  <value>#0</value>
                </enumeratedValue>
                <enumeratedValue>
                  <name>1</name>
                  <description>ERQ bit is cleared when the BCR is exhausted.</description>
                  <value>#1</value>
                </enumeratedValue>
              </enumeratedValues>
            </field>
            <field>
              <name>DMOD</name>
              <description>Destination Address Modulo</description>
              <bitOffset>8</bitOffset>
              <bitWidth>4</bitWidth>
              <access>read-write</access>
              <enumeratedValues>
                <enumeratedValue>
                  <name>0000</name>
                  <description>Buffer disabled</description>
                  <value>#0000</value>
                </enumeratedValue>
                <enumeratedValue>
                  <name>0001</name>
                  <description>Circular buffer size is 16 bytes</description>
                  <value>#0001</value>
                </enumeratedValue>
                <enumeratedValue>
                  <name>0010</name>
                  <description>Circular buffer size is 32 bytes</description>
                  <value>#0010</value>
                </enumeratedValue>
                <enumeratedValue>
                  <name>0011</name>
                  <description>Circular buffer size is 64 bytes</description>
                  <value>#0011</value>
                </enumeratedValue>
                <enumeratedValue>
                  <name>0100</name>
                  <description>Circular buffer size is 128 bytes</description>
                  <value>#0100</value>
                </enumeratedValue>
                <enumeratedValue>
                  <name>0101</name>
                  <description>Circular buffer size is 256 bytes</description>
                  <value>#0101</value>
                </enumeratedValue>
                <enumeratedValue>
                  <name>0110</name>
                  <description>Circular buffer size is 512 bytes</description>
                  <value>#0110</value>
                </enumeratedValue>
                <enumeratedValue>
                  <name>0111</name>
                  <description>Circular buffer size is 1 KB</description>
                  <value>#0111</value>
                </enumeratedValue>
                <enumeratedValue>
                  <name>1000</name>
                  <description>Circular buffer size is 2 KB</description>
                  <value>#1000</value>
                </enumeratedValue>
                <enumeratedValue>
                  <name>1001</name>
                  <description>Circular buffer size is 4 KB</description>
                  <value>#1001</value>
                </enumeratedValue>
                <enumeratedValue>
                  <name>1010</name>
                  <description>Circular buffer size is 8 KB</description>
                  <value>#1010</value>
                </enumeratedValue>
                <enumeratedValue>
                  <name>1011</name>
                  <description>Circular buffer size is 16 KB</description>
                  <value>#1011</value>
                </enumeratedValue>
                <enumeratedValue>
                  <name>1100</name>
                  <description>Circular buffer size is 32 KB</description>
                  <value>#1100</value>
                </enumeratedValue>
                <enumeratedValue>
                  <name>1101</name>
                  <description>Circular buffer size is 64 KB</description>
                  <value>#1101</value>
                </enumeratedValue>
                <enumeratedValue>
                  <name>1110</name>
                  <description>Circular buffer size is 128 KB</description>
                  <value>#1110</value>
                </enumeratedValue>
                <enumeratedValue>
                  <name>1111</name>
                  <description>Circular buffer size is 256 KB</description>
                  <value>#1111</value>
                </enumeratedValue>
              </enumeratedValues>
            </field>
            <field>
              <name>SMOD</name>
              <description>Source Address Modulo</description>
              <bitOffset>12</bitOffset>
              <bitWidth>4</bitWidth>
              <access>read-write</access>
              <enumeratedValues>
                <enumeratedValue>
                  <name>0000</name>
                  <description>Buffer disabled</description>
                  <value>#0000</value>
                </enumeratedValue>
                <enumeratedValue>
                  <name>0001</name>
                  <description>Circular buffer size is 16 bytes.</description>
                  <value>#0001</value>
                </enumeratedValue>
                <enumeratedValue>
                  <name>0010</name>
                  <description>Circular buffer size is 32 bytes.</description>
                  <value>#0010</value>
                </enumeratedValue>
                <enumeratedValue>
                  <name>0011</name>
                  <description>Circular buffer size is 64 bytes.</description>
                  <value>#0011</value>
                </enumeratedValue>
                <enumeratedValue>
                  <name>0100</name>
                  <description>Circular buffer size is 128 bytes.</description>
                  <value>#0100</value>
                </enumeratedValue>
                <enumeratedValue>
                  <name>0101</name>
                  <description>Circular buffer size is 256 bytes.</description>
                  <value>#0101</value>
                </enumeratedValue>
                <enumeratedValue>
                  <name>0110</name>
                  <description>Circular buffer size is 512 bytes.</description>
                  <value>#0110</value>
                </enumeratedValue>
                <enumeratedValue>
                  <name>0111</name>
                  <description>Circular buffer size is 1 KB.</description>
                  <value>#0111</value>
                </enumeratedValue>
                <enumeratedValue>
                  <name>1000</name>
                  <description>Circular buffer size is 2 KB.</description>
                  <value>#1000</value>
                </enumeratedValue>
                <enumeratedValue>
                  <name>1001</name>
                  <description>Circular buffer size is 4 KB.</description>
                  <value>#1001</value>
                </enumeratedValue>
                <enumeratedValue>
                  <name>1010</name>
                  <description>Circular buffer size is 8 KB.</description>
                  <value>#1010</value>
                </enumeratedValue>
                <enumeratedValue>
                  <name>1011</name>
                  <description>Circular buffer size is 16 KB.</description>
                  <value>#1011</value>
                </enumeratedValue>
                <enumeratedValue>
                  <name>1100</name>
                  <description>Circular buffer size is 32 KB.</description>
                  <value>#1100</value>
                </enumeratedValue>
                <enumeratedValue>
                  <name>1101</name>
                  <description>Circular buffer size is 64 KB.</description>
                  <value>#1101</value>
                </enumeratedValue>
                <enumeratedValue>
                  <name>1110</name>
                  <description>Circular buffer size is 128 KB.</description>
                  <value>#1110</value>
                </enumeratedValue>
                <enumeratedValue>
                  <name>1111</name>
                  <description>Circular buffer size is 256 KB.</description>
                  <value>#1111</value>
                </enumeratedValue>
              </enumeratedValues>
            </field>
            <field>
              <name>START</name>
              <description>Start Transfer</description>
              <bitOffset>16</bitOffset>
              <bitWidth>1</bitWidth>
              <access>write-only</access>
              <enumeratedValues>
                <enumeratedValue>
                  <name>0</name>
                  <description>DMA inactive</description>
                  <value>#0</value>
                </enumeratedValue>
                <enumeratedValue>
                  <name>1</name>
                  <description>The DMA begins the transfer in accordance to the values in the TCDn. START is cleared automatically after one module clock and always reads as logic 0.</description>
                  <value>#1</value>
                </enumeratedValue>
              </enumeratedValues>
            </field>
            <field>
              <name>DSIZE</name>
              <description>Destination Size</description>
              <bitOffset>17</bitOffset>
              <bitWidth>2</bitWidth>
              <access>read-write</access>
              <enumeratedValues>
                <enumeratedValue>
                  <name>00</name>
                  <description>32-bit</description>
                  <value>#00</value>
                </enumeratedValue>
                <enumeratedValue>
                  <name>01</name>
                  <description>8-bit</description>
                  <value>#01</value>
                </enumeratedValue>
                <enumeratedValue>
                  <name>10</name>
                  <description>16-bit</description>
                  <value>#10</value>
                </enumeratedValue>
                <enumeratedValue>
                  <name>11</name>
                  <description>Reserved (generates a configuration error (DSRn[CE]) if incorrectly specified at time of channel activation)</description>
                  <value>#11</value>
                </enumeratedValue>
              </enumeratedValues>
            </field>
            <field>
              <name>DINC</name>
              <description>Destination Increment</description>
              <bitOffset>19</bitOffset>
              <bitWidth>1</bitWidth>
              <access>read-write</access>
              <enumeratedValues>
                <enumeratedValue>
                  <name>0</name>
                  <description>No change to the DAR after a successful transfer.</description>
                  <value>#0</value>
                </enumeratedValue>
                <enumeratedValue>
                  <name>1</name>
                  <description>The DAR increments by 1, 2, 4 depending upon the size of the transfer.</description>
                  <value>#1</value>
                </enumeratedValue>
              </enumeratedValues>
            </field>
            <field>
              <name>SSIZE</name>
              <description>Source Size</description>
              <bitOffset>20</bitOffset>
              <bitWidth>2</bitWidth>
              <access>read-write</access>
              <enumeratedValues>
                <enumeratedValue>
                  <name>00</name>
                  <description>32-bit</description>
                  <value>#00</value>
                </enumeratedValue>
                <enumeratedValue>
                  <name>01</name>
                  <description>8-bit</description>
                  <value>#01</value>
                </enumeratedValue>
                <enumeratedValue>
                  <name>10</name>
                  <description>16-bit</description>
                  <value>#10</value>
                </enumeratedValue>
                <enumeratedValue>
                  <name>11</name>
                  <description>Reserved (generates a configuration error (DSRn[CE]) if incorrectly specified at time of channel activation)</description>
                  <value>#11</value>
                </enumeratedValue>
              </enumeratedValues>
            </field>
            <field>
              <name>SINC</name>
              <description>Source Increment</description>
              <bitOffset>22</bitOffset>
              <bitWidth>1</bitWidth>
              <access>read-write</access>
              <enumeratedValues>
                <enumeratedValue>
                  <name>0</name>
                  <description>No change to SAR after a successful transfer.</description>
                  <value>#0</value>
                </enumeratedValue>
                <enumeratedValue>
                  <name>1</name>
                  <description>The SAR increments by 1, 2, 4 as determined by the transfer size.</description>
                  <value>#1</value>
                </enumeratedValue>
              </enumeratedValues>
            </field>
            <field>
              <name>EADREQ</name>
              <description>Enable asynchronous DMA requests</description>
              <bitOffset>23</bitOffset>
              <bitWidth>1</bitWidth>
              <access>read-write</access>
              <enumeratedValues>
                <enumeratedValue>
                  <name>0</name>
                  <description>Disabled</description>
                  <value>#0</value>
                </enumeratedValue>
                <enumeratedValue>
                  <name>1</name>
                  <description>Enabled</description>
                  <value>#1</value>
                </enumeratedValue>
              </enumeratedValues>
            </field>
            <field>
              <name>AA</name>
              <description>Auto-align</description>
              <bitOffset>28</bitOffset>
              <bitWidth>1</bitWidth>
              <access>read-write</access>
              <enumeratedValues>
                <enumeratedValue>
                  <name>0</name>
                  <description>Auto-align disabled</description>
                  <value>#0</value>
                </enumeratedValue>
                <enumeratedValue>
                  <name>1</name>
                  <description>If SSIZE indicates a transfer no smaller than DSIZE, source accesses are auto-aligned; otherwise, destination accesses are auto-aligned. Source alignment takes precedence over destination alignment. If auto-alignment is enabled, the appropriate address register increments, regardless of DINC or SINC.</description>
                  <value>#1</value>
                </enumeratedValue>
              </enumeratedValues>
            </field>
            <field>
              <name>CS</name>
              <description>Cycle Steal</description>
              <bitOffset>29</bitOffset>
              <bitWidth>1</bitWidth>
              <access>read-write</access>
              <enumeratedValues>
                <enumeratedValue>
                  <name>0</name>
                  <description>DMA continuously makes read/write transfers until the BCR decrements to 0.</description>
                  <value>#0</value>
                </enumeratedValue>
                <enumeratedValue>
                  <name>1</name>
                  <description>Forces a single read/write transfer per request.</description>
                  <value>#1</value>
                </enumeratedValue>
              </enumeratedValues>
            </field>
            <field>
              <name>ERQ</name>
              <description>Enable Peripheral Request</description>
              <bitOffset>30</bitOffset>
              <bitWidth>1</bitWidth>
              <access>read-write</access>
              <enumeratedValues>
                <enumeratedValue>
                  <name>0</name>
                  <description>Peripheral request is ignored.</description>
                  <value>#0</value>
                </enumeratedValue>
                <enumeratedValue>
                  <name>1</name>
                  <description>Enables peripheral request to initiate transfer. A software-initiated request (setting START) is always enabled.</description>
                  <value>#1</value>
                </enumeratedValue>
              </enumeratedValues>
            </field>
            <field>
              <name>EINT</name>
              <description>Enable Interrupt on Completion of Transfer</description>
              <bitOffset>31</bitOffset>
              <bitWidth>1</bitWidth>
              <access>read-write</access>
              <enumeratedValues>
                <enumeratedValue>
                  <name>0</name>
                  <description>No interrupt is generated.</description>
                  <value>#0</value>
                </enumeratedValue>
                <enumeratedValue>
                  <name>1</name>
                  <description>Interrupt signal is enabled.</description>
                  <value>#1</value>
                </enumeratedValue>
              </enumeratedValues>
            </field>
          </fields>
        </register>
        <register>
          <name>SAR2</name>
          <description>Source Address Register</description>
          <addressOffset>0x120</addressOffset>
          <size>32</size>
          <access>read-write</access>
          <resetValue>0</resetValue>
          <resetMask>0xFFFFFFFF</resetMask>
          <fields>
            <field>
              <name>SAR</name>
              <description>Each SAR contains the byte address used by the DMA controller to read data</description>
              <bitOffset>0</bitOffset>
              <bitWidth>32</bitWidth>
              <access>read-write</access>
            </field>
          </fields>
        </register>
        <register>
          <name>DAR2</name>
          <description>Destination Address Register</description>
          <addressOffset>0x124</addressOffset>
          <size>32</size>
          <access>read-write</access>
          <resetValue>0</resetValue>
          <resetMask>0xFFFFFFFF</resetMask>
          <fields>
            <field>
              <name>DAR</name>
              <description>Each DAR contains the byte address used by the DMA controller to write data</description>
              <bitOffset>0</bitOffset>
              <bitWidth>32</bitWidth>
              <access>read-write</access>
            </field>
          </fields>
        </register>
        <register>
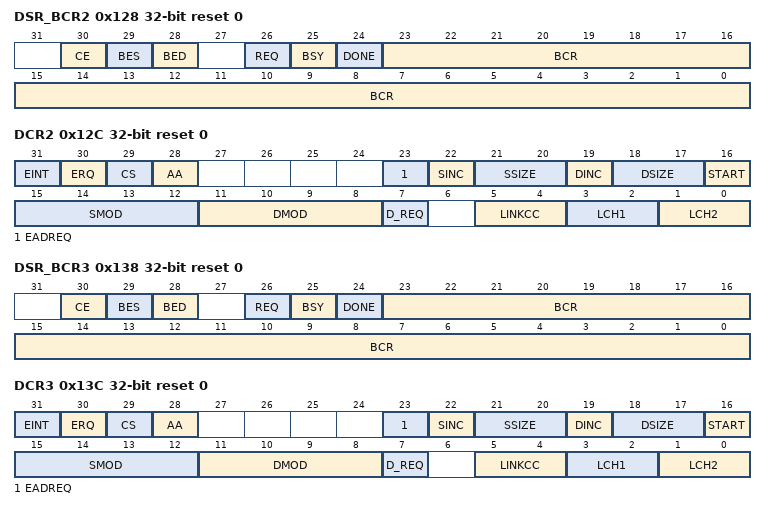
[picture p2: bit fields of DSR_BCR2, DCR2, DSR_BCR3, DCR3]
          <name>DSR_BCR2</name>
          <description>DMA Status Register / Byte Count Register</description>
          <addressOffset>0x128</addressOffset>
          <size>32</size>
          <access>read-write</access>
          <resetValue>0</resetValue>
          <resetMask>0xFFFFFFFF</resetMask>
          <fields>
            <field>
              <name>BCR</name>
              <description>This field contains the number of bytes yet to be transferred for a given block</description>
              <bitOffset>0</bitOffset>
              <bitWidth>24</bitWidth>
              <access>read-write</access>
            </field>
            <field>
              <name>DONE</name>
              <description>Transactions Done</description>
              <bitOffset>24</bitOffset>
              <bitWidth>1</bitWidth>
              <access>read-write</access>
              <enumeratedValues>
                <enumeratedValue>
                  <name>0</name>
                  <description>DMA transfer is not yet complete. Writing a 0 has no effect.</description>
                  <value>#0</value>
                </enumeratedValue>
                <enumeratedValue>
                  <name>1</name>
                  <description>DMA transfer completed. Writing a 1 to this bit clears all DMA status bits and should be used in an interrupt service routine to clear the DMA interrupt and error bits.</description>
                  <value>#1</value>
                </enumeratedValue>
              </enumeratedValues>
            </field>
            <field>
              <name>BSY</name>
              <description>Busy</description>
              <bitOffset>25</bitOffset>
              <bitWidth>1</bitWidth>
              <access>read-only</access>
              <enumeratedValues>
                <enumeratedValue>
                  <name>0</name>
                  <description>DMA channel is inactive. Cleared when the DMA has finished the last transaction.</description>
                  <value>#0</value>
                </enumeratedValue>
                <enumeratedValue>
                  <name>1</name>
                  <description>BSY is set the first time the channel is enabled after a transfer is initiated.</description>
                  <value>#1</value>
                </enumeratedValue>
              </enumeratedValues>
            </field>
            <field>
              <name>REQ</name>
              <description>Request</description>
              <bitOffset>26</bitOffset>
              <bitWidth>1</bitWidth>
              <access>read-only</access>
              <enumeratedValues>
                <enumeratedValue>
                  <name>0</name>
                  <description>No request is pending or the channel is currently active. Cleared when the channel is selected.</description>
                  <value>#0</value>
                </enumeratedValue>
                <enumeratedValue>
                  <name>1</name>
                  <description>The DMA channel has a transfer remaining and the channel is not selected.</description>
                  <value>#1</value>
                </enumeratedValue>
              </enumeratedValues>
            </field>
            <field>
              <name>BED</name>
              <description>Bus Error on Destination</description>
              <bitOffset>28</bitOffset>
              <bitWidth>1</bitWidth>
              <access>read-only</access>
              <enumeratedValues>
                <enumeratedValue>
                  <name>0</name>
                  <description>No bus error occurred.</description>
                  <value>#0</value>
                </enumeratedValue>
                <enumeratedValue>
                  <name>1</name>
                  <description>The DMA channel terminated with a bus error during the write portion of a transfer.</description>
                  <value>#1</value>
                </enumeratedValue>
              </enumeratedValues>
            </field>
            <field>
              <name>BES</name>
              <description>Bus Error on Source</description>
              <bitOffset>29</bitOffset>
              <bitWidth>1</bitWidth>
              <access>read-only</access>
              <enumeratedValues>
                <enumeratedValue>
                  <name>0</name>
                  <description>No bus error occurred.</description>
                  <value>#0</value>
                </enumeratedValue>
                <enumeratedValue>
                  <name>1</name>
                  <description>The DMA channel terminated with a bus error during the read portion of a transfer.</description>
                  <value>#1</value>
                </enumeratedValue>
              </enumeratedValues>
            </field>
            <field>
              <name>CE</name>
              <description>Configuration Error</description>
              <bitOffset>30</bitOffset>
              <bitWidth>1</bitWidth>
              <access>read-only</access>
              <enumeratedValues>
                <enumeratedValue>
                  <name>0</name>
                  <description>No configuration error exists.</description>
                  <value>#0</value>
                </enumeratedValue>
                <enumeratedValue>
                  <name>1</name>
                  <description>A configuration error has occurred.</description>
                  <value>#1</value>
                </enumeratedValue>
              </enumeratedValues>
            </field>
          </fields>
        </register>
        <register>
          <name>DSR2</name>
          <description>DMA_DSR2 register.</description>
          <addressOffset>0x12B</addressOffset>
          <size>8</size>
          <access>read-write</access>
          <resetValue>0</resetValue>
          <resetMask>0xFF</resetMask>
        </register>
        <register>
          <name>DCR2</name>
          <description>DMA Control Register</description>
          <addressOffset>0x12C</addressOffset>
          <size>32</size>
          <access>read-write</access>
          <resetValue>0</resetValue>
          <resetMask>0xFFFFFFFF</resetMask>
          <fields>
            <field>
              <name>LCH2</name>
              <description>Link Channel 2</description>
              <bitOffset>0</bitOffset>
              <bitWidth>2</bitWidth>
              <access>read-write</access>
              <enumeratedValues>
                <enumeratedValue>
                  <name>00</name>
                  <description>DMA Channel 0</description>
                  <value>#00</value>
                </enumeratedValue>
                <enumeratedValue>
                  <name>01</name>
                  <description>DMA Channel 1</description>
                  <value>#01</value>
                </enumeratedValue>
                <enumeratedValue>
                  <name>10</name>
                  <description>DMA Channel 2</description>
                  <value>#10</value>
                </enumeratedValue>
                <enumeratedValue>
                  <name>11</name>
                  <description>DMA Channel 3</description>
                  <value>#11</value>
                </enumeratedValue>
              </enumeratedValues>
            </field>
            <field>
              <name>LCH1</name>
              <description>Link Channel 1</description>
              <bitOffset>2</bitOffset>
              <bitWidth>2</bitWidth>
              <access>read-write</access>
              <enumeratedValues>
                <enumeratedValue>
                  <name>00</name>
                  <description>DMA Channel 0</description>
                  <value>#00</value>
                </enumeratedValue>
                <enumeratedValue>
                  <name>01</name>
                  <description>DMA Channel 1</description>
                  <value>#01</value>
                </enumeratedValue>
                <enumeratedValue>
                  <name>10</name>
                  <description>DMA Channel 2</description>
                  <value>#10</value>
                </enumeratedValue>
                <enumeratedValue>
                  <name>11</name>
                  <description>DMA Channel 3</description>
                  <value>#11</value>
                </enumeratedValue>
              </enumeratedValues>
            </field>
            <field>
              <name>LINKCC</name>
              <description>Link Channel Control</description>
              <bitOffset>4</bitOffset>
              <bitWidth>2</bitWidth>
              <access>read-write</access>
              <enumeratedValues>
                <enumeratedValue>
                  <name>00</name>
                  <description>No channel-to-channel linking</description>
                  <value>#00</value>
                </enumeratedValue>
                <enumeratedValue>
                  <name>01</name>
                  <description>Perform a link to channel LCH1 after each cycle-steal transfer followed by a link to LCH2 after the BCR decrements to 0.</description>
                  <value>#01</value>
                </enumeratedValue>
                <enumeratedValue>
                  <name>10</name>
                  <description>Perform a link to channel LCH1 after each cycle-steal transfer</description>
                  <value>#10</value>
                </enumeratedValue>
                <enumeratedValue>
                  <name>11</name>
                  <description>Perform a link to channel LCH1 after the BCR decrements to 0.</description>
                  <value>#11</value>
                </enumeratedValue>
              </enumeratedValues>
            </field>
            <field>
              <name>D_REQ</name>
              <description>Disable Request</description>
              <bitOffset>7</bitOffset>
              <bitWidth>1</bitWidth>
              <access>read-write</access>
              <enumeratedValues>
                <enumeratedValue>
                  <name>0</name>
                  <description>ERQ bit is not affected.</description>
                  <value>#0</value>
                </enumeratedValue>
                <enumeratedValue>
                  <name>1</name>
                  <description>ERQ bit is cleared when the BCR is exhausted.</description>
                  <value>#1</value>
                </enumeratedValue>
              </enumeratedValues>
            </field>
            <field>
              <name>DMOD</name>
              <description>Destination Address Modulo</description>
              <bitOffset>8</bitOffset>
              <bitWidth>4</bitWidth>
              <access>read-write</access>
              <enumeratedValues>
                <enumeratedValue>
                  <name>0000</name>
                  <description>Buffer disabled</description>
                  <value>#0000</value>
                </enumeratedValue>
                <enumeratedValue>
                  <name>0001</name>
                  <description>Circular buffer size is 16 bytes</description>
                  <value>#0001</value>
                </enumeratedValue>
                <enumeratedValue>
                  <name>0010</name>
                  <description>Circular buffer size is 32 bytes</description>
                  <value>#0010</value>
                </enumeratedValue>
                <enumeratedValue>
                  <name>0011</name>
                  <description>Circular buffer size is 64 bytes</description>
                  <value>#0011</value>
                </enumeratedValue>
                <enumeratedValue>
                  <name>0100</name>
                  <description>Circular buffer size is 128 bytes</description>
                  <value>#0100</value>
                </enumeratedValue>
                <enumeratedValue>
                  <name>0101</name>
                  <description>Circular buffer size is 256 bytes</description>
                  <value>#0101</value>
                </enumeratedValue>
                <enumeratedValue>
                  <name>0110</name>
                  <description>Circular buffer size is 512 bytes</description>
                  <value>#0110</value>
                </enumeratedValue>
                <enumeratedValue>
                  <name>0111</name>
                  <description>Circular buffer size is 1 KB</description>
                  <value>#0111</value>
                </enumeratedValue>
                <enumeratedValue>
                  <name>1000</name>
                  <description>Circular buffer size is 2 KB</description>
                  <value>#1000</value>
                </enumeratedValue>
                <enumeratedValue>
                  <name>1001</name>
                  <description>Circular buffer size is 4 KB</description>
                  <value>#1001</value>
                </enumeratedValue>
                <enumeratedValue>
                  <name>1010</name>
                  <description>Circular buffer size is 8 KB</description>
                  <value>#1010</value>
                </enumeratedValue>
                <enumeratedValue>
                  <name>1011</name>
                  <description>Circular buffer size is 16 KB</description>
                  <value>#1011</value>
                </enumeratedValue>
                <enumeratedValue>
                  <name>1100</name>
                  <description>Circular buffer size is 32 KB</description>
                  <value>#1100</value>
                </enumeratedValue>
                <enumeratedValue>
                  <name>1101</name>
                  <description>Circular buffer size is 64 KB</description>
                  <value>#1101</value>
                </enumeratedValue>
                <enumeratedValue>
                  <name>1110</name>
                  <description>Circular buffer size is 128 KB</description>
                  <value>#1110</value>
                </enumeratedValue>
                <enumeratedValue>
                  <name>1111</name>
                  <description>Circular buffer size is 256 KB</description>
                  <value>#1111</value>
                </enumeratedValue>
              </enumeratedValues>
            </field>
            <field>
              <name>SMOD</name>
              <description>Source Address Modulo</description>
              <bitOffset>12</bitOffset>
              <bitWidth>4</bitWidth>
              <access>read-write</access>
              <enumeratedValues>
                <enumeratedValue>
                  <name>0000</name>
                  <description>Buffer disabled</description>
                  <value>#0000</value>
                </enumeratedValue>
                <enumeratedValue>
                  <name>0001</name>
                  <description>Circular buffer size is 16 bytes.</description>
                  <value>#0001</value>
                </enumeratedValue>
                <enumeratedValue>
                  <name>0010</name>
                  <description>Circular buffer size is 32 bytes.</description>
                  <value>#0010</value>
                </enumeratedValue>
                <enumeratedValue>
                  <name>0011</name>
                  <description>Circular buffer size is 64 bytes.</description>
                  <value>#0011</value>
                </enumeratedValue>
                <enumeratedValue>
                  <name>0100</name>
                  <description>Circular buffer size is 128 bytes.</description>
                  <value>#0100</value>
                </enumeratedValue>
                <enumeratedValue>
                  <name>0101</name>
                  <description>Circular buffer size is 256 bytes.</description>
                  <value>#0101</value>
                </enumeratedValue>
                <enumeratedValue>
                  <name>0110</name>
                  <description>Circular buffer size is 512 bytes.</description>
                  <value>#0110</value>
                </enumeratedValue>
                <enumeratedValue>
                  <name>0111</name>
                  <description>Circular buffer size is 1 KB.</description>
                  <value>#0111</value>
                </enumeratedValue>
                <enumeratedValue>
                  <name>1000</name>
                  <description>Circular buffer size is 2 KB.</description>
                  <value>#1000</value>
                </enumeratedValue>
                <enumeratedValue>
                  <name>1001</name>
                  <description>Circular buffer size is 4 KB.</description>
                  <value>#1001</value>
                </enumeratedValue>
                <enumeratedValue>
                  <name>1010</name>
                  <description>Circular buffer size is 8 KB.</description>
                  <value>#1010</value>
                </enumeratedValue>
                <enumeratedValue>
                  <name>1011</name>
                  <description>Circular buffer size is 16 KB.</description>
                  <value>#1011</value>
                </enumeratedValue>
                <enumeratedValue>
                  <name>1100</name>
                  <description>Circular buffer size is 32 KB.</description>
                  <value>#1100</value>
                </enumeratedValue>
                <enumeratedValue>
                  <name>1101</name>
                  <description>Circular buffer size is 64 KB.</description>
                  <value>#1101</value>
                </enumeratedValue>
                <enumeratedValue>
                  <name>1110</name>
                  <description>Circular buffer size is 128 KB.</description>
                  <value>#1110</value>
                </enumeratedValue>
                <enumeratedValue>
                  <name>1111</name>
                  <description>Circular buffer size is 256 KB.</description>
                  <value>#1111</value>
                </enumeratedValue>
              </enumeratedValues>
            </field>
            <field>
              <name>START</name>
              <description>Start Transfer</description>
              <bitOffset>16</bitOffset>
              <bitWidth>1</bitWidth>
              <access>write-only</access>
              <enumeratedValues>
                <enumeratedValue>
                  <name>0</name>
                  <description>DMA inactive</description>
                  <value>#0</value>
                </enumeratedValue>
                <enumeratedValue>
                  <name>1</name>
                  <description>The DMA begins the transfer in accordance to the values in the TCDn. START is cleared automatically after one module clock and always reads as logic 0.</description>
                  <value>#1</value>
                </enumeratedValue>
              </enumeratedValues>
            </field>
            <field>
              <name>DSIZE</name>
              <description>Destination Size</description>
              <bitOffset>17</bitOffset>
              <bitWidth>2</bitWidth>
              <access>read-write</access>
              <enumeratedValues>
                <enumeratedValue>
                  <name>00</name>
                  <description>32-bit</description>
                  <value>#00</value>
                </enumeratedValue>
                <enumeratedValue>
                  <name>01</name>
                  <description>8-bit</description>
                  <value>#01</value>
                </enumeratedValue>
                <enumeratedValue>
                  <name>10</name>
                  <description>16-bit</description>
                  <value>#10</value>
                </enumeratedValue>
                <enumeratedValue>
                  <name>11</name>
                  <description>Reserved (generates a configuration error (DSRn[CE]) if incorrectly specified at time of channel activation)</description>
                  <value>#11</value>
                </enumeratedValue>
              </enumeratedValues>
            </field>
            <field>
              <name>DINC</name>
              <description>Destination Increment</description>
              <bitOffset>19</bitOffset>
              <bitWidth>1</bitWidth>
              <access>read-write</access>
              <enumeratedValues>
                <enumeratedValue>
                  <name>0</name>
                  <description>No change to the DAR after a successful transfer.</description>
                  <value>#0</value>
                </enumeratedValue>
                <enumeratedValue>
                  <name>1</name>
                  <description>The DAR increments by 1, 2, 4 depending upon the size of the transfer.</description>
                  <value>#1</value>
                </enumeratedValue>
              </enumeratedValues>
            </field>
            <field>
              <name>SSIZE</name>
              <description>Source Size</description>
              <bitOffset>20</bitOffset>
              <bitWidth>2</bitWidth>
              <access>read-write</access>
              <enumeratedValues>
                <enumeratedValue>
                  <name>00</name>
                  <description>32-bit</description>
                  <value>#00</value>
                </enumeratedValue>
                <enumeratedValue>
                  <name>01</name>
                  <description>8-bit</description>
                  <value>#01</value>
                </enumeratedValue>
                <enumeratedValue>
                  <name>10</name>
                  <description>16-bit</description>
                  <value>#10</value>
                </enumeratedValue>
                <enumeratedValue>
                  <name>11</name>
                  <description>Reserved (generates a configuration error (DSRn[CE]) if incorrectly specified at time of channel activation)</description>
                  <value>#11</value>
                </enumeratedValue>
              </enumeratedValues>
            </field>
            <field>
              <name>SINC</name>
              <description>Source Increment</description>
              <bitOffset>22</bitOffset>
              <bitWidth>1</bitWidth>
              <access>read-write</access>
              <enumeratedValues>
                <enumeratedValue>
                  <name>0</name>
                  <description>No change to SAR after a successful transfer.</description>
                  <value>#0</value>
                </enumeratedValue>
                <enumeratedValue>
                  <name>1</name>
                  <description>The SAR increments by 1, 2, 4 as determined by the transfer size.</description>
                  <value>#1</value>
                </enumeratedValue>
              </enumeratedValues>
            </field>
            <field>
              <name>EADREQ</name>
              <description>Enable asynchronous DMA requests</description>
              <bitOffset>23</bitOffset>
              <bitWidth>1</bitWidth>
              <access>read-write</access>
              <enumeratedValues>
                <enumeratedValue>
                  <name>0</name>
                  <description>Disabled</description>
                  <value>#0</value>
                </enumeratedValue>
                <enumeratedValue>
                  <name>1</name>
                  <description>Enabled</description>
                  <value>#1</value>
                </enumeratedValue>
              </enumeratedValues>
            </field>
            <field>
              <name>AA</name>
              <description>Auto-align</description>
              <bitOffset>28</bitOffset>
              <bitWidth>1</bitWidth>
              <access>read-write</access>
              <enumeratedValues>
                <enumeratedValue>
                  <name>0</name>
                  <description>Auto-align disabled</description>
                  <value>#0</value>
                </enumeratedValue>
                <enumeratedValue>
                  <name>1</name>
                  <description>If SSIZE indicates a transfer no smaller than DSIZE, source accesses are auto-aligned; otherwise, destination accesses are auto-aligned. Source alignment takes precedence over destination alignment. If auto-alignment is enabled, the appropriate address register increments, regardless of DINC or SINC.</description>
                  <value>#1</value>
                </enumeratedValue>
              </enumeratedValues>
            </field>
            <field>
              <name>CS</name>
              <description>Cycle Steal</description>
              <bitOffset>29</bitOffset>
              <bitWidth>1</bitWidth>
              <access>read-write</access>
              <enumeratedValues>
                <enumeratedValue>
                  <name>0</name>
                  <description>DMA continuously makes read/write transfers until the BCR decrements to 0.</description>
                  <value>#0</value>
                </enumeratedValue>
                <enumeratedValue>
                  <name>1</name>
                  <description>Forces a single read/write transfer per request.</description>
                  <value>#1</value>
                </enumeratedValue>
              </enumeratedValues>
            </field>
            <field>
              <name>ERQ</name>
              <description>Enable Peripheral Request</description>
              <bitOffset>30</bitOffset>
              <bitWidth>1</bitWidth>
              <access>read-write</access>
              <enumeratedValues>
                <enumeratedValue>
                  <name>0</name>
                  <description>Peripheral request is ignored.</description>
                  <value>#0</value>
                </enumeratedValue>
                <enumeratedValue>
                  <name>1</name>
                  <description>Enables peripheral request to initiate transfer. A software-initiated request (setting START) is always enabled.</description>
                  <value>#1</value>
                </enumeratedValue>
              </enumeratedValues>
            </field>
            <field>
              <name>EINT</name>
              <description>Enable Interrupt on Completion of Transfer</description>
              <bitOffset>31</bitOffset>
              <bitWidth>1</bitWidth>
              <access>read-write</access>
              <enumeratedValues>
                <enumeratedValue>
                  <name>0</name>
                  <description>No interrupt is generated.</description>
                  <value>#0</value>
                </enumeratedValue>
                <enumeratedValue>
                  <name>1</name>
                  <description>Interrupt signal is enabled.</description>
                  <value>#1</value>
                </enumeratedValue>
              </enumeratedValues>
            </field>
          </fields>
        </register>
        <register>
          <name>SAR3</name>
          <description>Source Address Register</description>
          <addressOffset>0x130</addressOffset>
          <size>32</size>
          <access>read-write</access>
          <resetValue>0</resetValue>
          <resetMask>0xFFFFFFFF</resetMask>
          <fields>
            <field>
              <name>SAR</name>
              <description>Each SAR contains the byte address used by the DMA controller to read data</description>
              <bitOffset>0</bitOffset>
              <bitWidth>32</bitWidth>
              <access>read-write</access>
            </field>
          </fields>
        </register>
        <register>
          <name>DAR3</name>
          <description>Destination Address Register</description>
          <addressOffset>0x134</addressOffset>
          <size>32</size>
          <access>read-write</access>
          <resetValue>0</resetValue>
          <resetMask>0xFFFFFFFF</resetMask>
          <fields>
            <field>
              <name>DAR</name>
              <description>Each DAR contains the byte address used by the DMA controller to write data</description>
              <bitOffset>0</bitOffset>
              <bitWidth>32</bitWidth>
              <access>read-write</access>
            </field>
          </fields>
        </register>
        <register>
          <name>DSR_BCR3</name>
          <description>DMA Status Register / Byte Count Register</description>
          <addressOffset>0x138</addressOffset>
          <size>32</size>
          <access>read-write</access>
          <resetValue>0</resetValue>
          <resetMask>0xFFFFFFFF</resetMask>
          <fields>
            <field>
              <name>BCR</name>
              <description>This field contains the number of bytes yet to be transferred for a given block</description>
              <bitOffset>0</bitOffset>
              <bitWidth>24</bitWidth>
              <access>read-write</access>
            </field>
            <field>
              <name>DONE</name>
              <description>Transactions Done</description>
              <bitOffset>24</bitOffset>
              <bitWidth>1</bitWidth>
              <access>read-write</access>
              <enumeratedValues>
                <enumeratedValue>
                  <name>0</name>
                  <description>DMA transfer is not yet complete. Writing a 0 has no effect.</description>
                  <value>#0</value>
                </enumeratedValue>
                <enumeratedValue>
                  <name>1</name>
                  <description>DMA transfer completed. Writing a 1 to this bit clears all DMA status bits and should be used in an interrupt service routine to clear the DMA interrupt and error bits.</description>
                  <value>#1</value>
                </enumeratedValue>
              </enumeratedValues>
            </field>
            <field>
              <name>BSY</name>
              <description>Busy</description>
              <bitOffset>25</bitOffset>
              <bitWidth>1</bitWidth>
              <access>read-only</access>
              <enumeratedValues>
                <enumeratedValue>
                  <name>0</name>
                  <description>DMA channel is inactive. Cleared when the DMA has finished the last transaction.</description>
                  <value>#0</value>
                </enumeratedValue>
                <enumeratedValue>
                  <name>1</name>
                  <description>BSY is set the first time the channel is enabled after a transfer is initiated.</description>
                  <value>#1</value>
                </enumeratedValue>
              </enumeratedValues>
            </field>
            <field>
              <name>REQ</name>
              <description>Request</description>
              <bitOffset>26</bitOffset>
              <bitWidth>1</bitWidth>
              <access>read-only</access>
              <enumeratedValues>
                <enumeratedValue>
                  <name>0</name>
                  <description>No request is pending or the channel is currently active. Cleared when the channel is selected.</description>
                  <value>#0</value>
                </enumeratedValue>
                <enumeratedValue>
                  <name>1</name>
                  <description>The DMA channel has a transfer remaining and the channel is not selected.</description>
                  <value>#1</value>
                </enumeratedValue>
              </enumeratedValues>
            </field>
            <field>
              <name>BED</name>
              <description>Bus Error on Destination</description>
              <bitOffset>28</bitOffset>
              <bitWidth>1</bitWidth>
              <access>read-only</access>
              <enumeratedValues>
                <enumeratedValue>
                  <name>0</name>
                  <description>No bus error occurred.</description>
                  <value>#0</value>
                </enumeratedValue>
                <enumeratedValue>
                  <name>1</name>
                  <description>The DMA channel terminated with a bus error during the write portion of a transfer.</description>
                  <value>#1</value>
                </enumeratedValue>
              </enumeratedValues>
            </field>
            <field>
              <name>BES</name>
              <description>Bus Error on Source</description>
              <bitOffset>29</bitOffset>
              <bitWidth>1</bitWidth>
              <access>read-only</access>
              <enumeratedValues>
                <enumeratedValue>
                  <name>0</name>
                  <description>No bus error occurred.</description>
                  <value>#0</value>
                </enumeratedValue>
                <enumeratedValue>
                  <name>1</name>
                  <description>The DMA channel terminated with a bus error during the read portion of a transfer.</description>
                  <value>#1</value>
                </enumeratedValue>
              </enumeratedValues>
            </field>
            <field>
              <name>CE</name>
              <description>Configuration Error</description>
              <bitOffset>30</bitOffset>
              <bitWidth>1</bitWidth>
              <access>read-only</access>
              <enumeratedValues>
                <enumeratedValue>
                  <name>0</name>
                  <description>No configuration error exists.</description>
                  <value>#0</value>
                </enumeratedValue>
                <enumeratedValue>
                  <name>1</name>
                  <description>A configuration error has occurred.</description>
                  <value>#1</value>
                </enumeratedValue>
              </enumeratedValues>
            </field>
          </fields>
        </register>
        <register>
          <name>DSR3</name>
          <description>DMA_DSR3 register.</description>
          <addressOffset>0x13B</addressOffset>
          <size>8</size>
          <access>read-write</access>
          <resetValue>0</resetValue>
          <resetMask>0xFF</resetMask>
        </register>
        <register>
          <name>DCR3</name>
          <description>DMA Control Register</description>
          <addressOffset>0x13C</addressOffset>
          <size>32</size>
          <access>read-write</access>
          <resetValue>0</resetValue>
          <resetMask>0xFFFFFFFF</resetMask>
          <fields>
            <field>
              <name>LCH2</name>
              <description>Link Channel 2</description>
              <bitOffset>0</bitOffset>
              <bitWidth>2</bitWidth>
              <access>read-write</access>
              <enumeratedValues>
                <enumeratedValue>
                  <name>00</name>
                  <description>DMA Channel 0</description>
                  <value>#00</value>
                </enumeratedValue>
                <enumeratedValue>
                  <name>01</name>
                  <description>DMA Channel 1</description>
                  <value>#01</value>
                </enumeratedValue>
                <enumeratedValue>
                  <name>10</name>
                  <description>DMA Channel 2</description>
                  <value>#10</value>
                </enumeratedValue>
                <enumeratedValue>
                  <name>11</name>
                  <description>DMA Channel 3</description>
                  <value>#11</value>
                </enumeratedValue>
              </enumeratedValues>
            </field>
            <field>
              <name>LCH1</name>
              <description>Link Channel 1</description>
              <bitOffset>2</bitOffset>
              <bitWidth>2</bitWidth>
              <access>read-write</access>
              <enumeratedValues>
                <enumeratedValue>
                  <name>00</name>
                  <description>DMA Channel 0</description>
                  <value>#00</value>
                </enumeratedValue>
                <enumeratedValue>
                  <name>01</name>
                  <description>DMA Channel 1</description>
                  <value>#01</value>
                </enumeratedValue>
                <enumeratedValue>
                  <name>10</name>
                  <description>DMA Channel 2</description>
                  <value>#10</value>
                </enumeratedValue>
                <enumeratedValue>
                  <name>11</name>
                  <description>DMA Channel 3</description>
                  <value>#11</value>
                </enumeratedValue>
              </enumeratedValues>
            </field>
            <field>
              <name>LINKCC</name>
              <description>Link Channel Control</description>
              <bitOffset>4</bitOffset>
              <bitWidth>2</bitWidth>
              <access>read-write</access>
              <enumeratedValues>
                <enumeratedValue>
                  <name>00</name>
                  <description>No channel-to-channel linking</description>
                  <value>#00</value>
                </enumeratedValue>
                <enumeratedValue>
                  <name>01</name>
                  <description>Perform a link to channel LCH1 after each cycle-steal transfer followed by a link to LCH2 after the BCR decrements to 0.</description>
                  <value>#01</value>
                </enumeratedValue>
                <enumeratedValue>
                  <name>10</name>
                  <description>Perform a link to channel LCH1 after each cycle-steal transfer</description>
                  <value>#10</value>
                </enumeratedValue>
                <enumeratedValue>
                  <name>11</name>
                  <description>Perform a link to channel LCH1 after the BCR decrements to 0.</description>
                  <value>#11</value>
                </enumeratedValue>
              </enumeratedValues>
            </field>
            <field>
              <name>D_REQ</name>
              <description>Disable Request</description>
              <bitOffset>7</bitOffset>
              <bitWidth>1</bitWidth>
              <access>read-write</access>
              <enumeratedValues>
                <enumeratedValue>
                  <name>0</name>
                  <description>ERQ bit is not affected.</description>
                  <value>#0</value>
                </enumeratedValue>
                <enumeratedValue>
                  <name>1</name>
                  <description>ERQ bit is cleared when the BCR is exhausted.</description>
                  <value>#1</value>
                </enumeratedValue>
              </enumeratedValues>
            </field>
            <field>
              <name>DMOD</name>
              <description>Destination Address Modulo</description>
              <bitOffset>8</bitOffset>
              <bitWidth>4</bitWidth>
              <access>read-write</access>
              <enumeratedValues>
                <enumeratedValue>
                  <name>0000</name>
                  <description>Buffer disabled</description>
                  <value>#0000</value>
                </enumeratedValue>
                <enumeratedValue>
                  <name>0001</name>
                  <description>Circular buffer size is 16 bytes</description>
                  <value>#0001</value>
                </enumeratedValue>
                <enumeratedValue>
                  <name>0010</name>
                  <description>Circular buffer size is 32 bytes</description>
                  <value>#0010</value>
                </enumeratedValue>
                <enumeratedValue>
                  <name>0011</name>
                  <description>Circular buffer size is 64 bytes</description>
                  <value>#0011</value>
                </enumeratedValue>
                <enumeratedValue>
                  <name>0100</name>
                  <description>Circular buffer size is 128 bytes</description>
                  <value>#0100</value>
                </enumeratedValue>
                <enumeratedValue>
                  <name>0101</name>
                  <description>Circular buffer size is 256 bytes</description>
                  <value>#0101</value>
                </enumeratedValue>
                <enumeratedValue>
                  <name>0110</name>
                  <description>Circular buffer size is 512 bytes</description>
                  <value>#0110</value>
                </enumeratedValue>
                <enumeratedValue>
                  <name>0111</name>
                  <description>Circular buffer size is 1 KB</description>
                  <value>#0111</value>
                </enumeratedValue>
                <enumeratedValue>
                  <name>1000</name>
                  <description>Circular buffer size is 2 KB</description>
                  <value>#1000</value>
                </enumeratedValue>
                <enumeratedValue>
                  <name>1001</name>
                  <description>Circular buffer size is 4 KB</description>
                  <value>#1001</value>
                </enumeratedValue>
                <enumeratedValue>
                  <name>1010</name>
                  <description>Circular buffer size is 8 KB</description>
                  <value>#1010</value>
                </enumeratedValue>
                <enumeratedValue>
                  <name>1011</name>
                  <description>Circular buffer size is 16 KB</description>
                  <value>#1011</value>
                </enumeratedValue>
                <enumeratedValue>
                  <name>1100</name>
                  <description>Circular buffer size is 32 KB</description>
                  <value>#1100</value>
                </enumeratedValue>
                <enumeratedValue>
                  <name>1101</name>
                  <description>Circular buffer size is 64 KB</description>
                  <value>#1101</value>
                </enumeratedValue>
                <enumeratedValue>
                  <name>1110</name>
                  <description>Circular buffer size is 128 KB</description>
                  <value>#1110</value>
                </enumeratedValue>
                <enumeratedValue>
                  <name>1111</name>
                  <description>Circular buffer size is 256 KB</description>
                  <value>#1111</value>
                </enumeratedValue>
              </enumeratedValues>
            </field>
            <field>
              <name>SMOD</name>
              <description>Source Address Modulo</description>
              <bitOffset>12</bitOffset>
              <bitWidth>4</bitWidth>
              <access>read-write</access>
              <enumeratedValues>
                <enumeratedValue>
                  <name>0000</name>
                  <description>Buffer disabled</description>
                  <value>#0000</value>
                </enumeratedValue>
                <enumeratedValue>
                  <name>0001</name>
                  <description>Circular buffer size is 16 bytes.</description>
                  <value>#0001</value>
                </enumeratedValue>
                <enumeratedValue>
                  <name>0010</name>
                  <description>Circular buffer size is 32 bytes.</description>
                  <value>#0010</value>
                </enumeratedValue>
                <enumeratedValue>
                  <name>0011</name>
                  <description>Circular buffer size is 64 bytes.</description>
                  <value>#0011</value>
                </enumeratedValue>
                <enumeratedValue>
                  <name>0100</name>
                  <description>Circular buffer size is 128 bytes.</description>
                  <value>#0100</value>
                </enumeratedValue>
                <enumeratedValue>
                  <name>0101</name>
                  <description>Circular buffer size is 256 bytes.</description>
                  <value>#0101</value>
                </enumeratedValue>
                <enumeratedValue>
                  <name>0110</name>
                  <description>Circular buffer size is 512 bytes.</description>
                  <value>#0110</value>
                </enumeratedValue>
                <enumeratedValue>
                  <name>0111</name>
                  <description>Circular buffer size is 1 KB.</description>
                  <value>#0111</value>
                </enumeratedValue>
                <enumeratedValue>
                  <name>1000</name>
                  <description>Circular buffer size is 2 KB.</description>
                  <value>#1000</value>
                </enumeratedValue>
                <enumeratedValue>
                  <name>1001</name>
                  <description>Circular buffer size is 4 KB.</description>
                  <value>#1001</value>
                </enumeratedValue>
                <enumeratedValue>
                  <name>1010</name>
                  <description>Circular buffer size is 8 KB.</description>
                  <value>#1010</value>
                </enumeratedValue>
                <enumeratedValue>
                  <name>1011</name>
                  <description>Circular buffer size is 16 KB.</description>
                  <value>#1011</value>
                </enumeratedValue>
                <enumeratedValue>
                  <name>1100</name>
                  <description>Circular buffer size is 32 KB.</description>
                  <value>#1100</value>
                </enumeratedValue>
                <enumeratedValue>
                  <name>1101</name>
                  <description>Circular buffer size is 64 KB.</description>
                  <value>#1101</value>
                </enumeratedValue>
                <enumeratedValue>
                  <name>1110</name>
                  <description>Circular buffer size is 128 KB.</description>
                  <value>#1110</value>
                </enumeratedValue>
                <enumeratedValue>
                  <name>1111</name>
                  <description>Circular buffer size is 256 KB.</description>
                  <value>#1111</value>
                </enumeratedValue>
              </enumeratedValues>
            </field>
            <field>
              <name>START</name>
              <description>Start Transfer</description>
              <bitOffset>16</bitOffset>
              <bitWidth>1</bitWidth>
              <access>write-only</access>
              <enumeratedValues>
                <enumeratedValue>
                  <name>0</name>
                  <description>DMA inactive</description>
                  <value>#0</value>
                </enumeratedValue>
                <enumeratedValue>
                  <name>1</name>
                  <description>The DMA begins the transfer in accordance to the values in the TCDn. START is cleared automatically after one module clock and always reads as logic 0.</description>
                  <value>#1</value>
                </enumeratedValue>
              </enumeratedValues>
            </field>
            <field>
              <name>DSIZE</name>
              <description>Destination Size</description>
              <bitOffset>17</bitOffset>
              <bitWidth>2</bitWidth>
              <access>read-write</access>
              <enumeratedValues>
                <enumeratedValue>
                  <name>00</name>
                  <description>32-bit</description>
                  <value>#00</value>
                </enumeratedValue>
                <enumeratedValue>
                  <name>01</name>
                  <description>8-bit</description>
                  <value>#01</value>
                </enumeratedValue>
                <enumeratedValue>
                  <name>10</name>
                  <description>16-bit</description>
                  <value>#10</value>
                </enumeratedValue>
                <enumeratedValue>
                  <name>11</name>
                  <description>Reserved (generates a configuration error (DSRn[CE]) if incorrectly specified at time of channel activation)</description>
                  <value>#11</value>
                </enumeratedValue>
              </enumeratedValues>
            </field>
            <field>
              <name>DINC</name>
              <description>Destination Increment</description>
              <bitOffset>19</bitOffset>
              <bitWidth>1</bitWidth>
              <access>read-write</access>
              <enumeratedValues>
                <enumeratedValue>
                  <name>0</name>
                  <description>No change to the DAR after a successful transfer.</description>
                  <value>#0</value>
                </enumeratedValue>
                <enumeratedValue>
                  <name>1</name>
                  <description>The DAR increments by 1, 2, 4 depending upon the size of the transfer.</description>
                  <value>#1</value>
                </enumeratedValue>
              </enumeratedValues>
            </field>
            <field>
              <name>SSIZE</name>
              <description>Source Size</description>
              <bitOffset>20</bitOffset>
              <bitWidth>2</bitWidth>
              <access>read-write</access>
              <enumeratedValues>
                <enumeratedValue>
                  <name>00</name>
                  <description>32-bit</description>
                  <value>#00</value>
                </enumeratedValue>
                <enumeratedValue>
                  <name>01</name>
                  <description>8-bit</description>
                  <value>#01</value>
                </enumeratedValue>
                <enumeratedValue>
                  <name>10</name>
                  <description>16-bit</description>
                  <value>#10</value>
                </enumeratedValue>
                <enumeratedValue>
                  <name>11</name>
                  <description>Reserved (generates a configuration error (DSRn[CE]) if incorrectly specified at time of channel activation)</description>
                  <value>#11</value>
                </enumeratedValue>
              </enumeratedValues>
            </field>
            <field>
              <name>SINC</name>
              <description>Source Increment</description>
              <bitOffset>22</bitOffset>
              <bitWidth>1</bitWidth>
              <access>read-write</access>
              <enumeratedValues>
                <enumeratedValue>
                  <name>0</name>
                  <description>No change to SAR after a successful transfer.</description>
                  <value>#0</value>
                </enumeratedValue>
                <enumeratedValue>
                  <name>1</name>
                  <description>The SAR increments by 1, 2, 4 as determined by the transfer size.</description>
                  <value>#1</value>
                </enumeratedValue>
              </enumeratedValues>
            </field>
            <field>
              <name>EADREQ</name>
              <description>Enable asynchronous DMA requests</description>
              <bitOffset>23</bitOffset>
              <bitWidth>1</bitWidth>
              <access>read-write</access>
              <enumeratedValues>
                <enumeratedValue>
                  <name>0</name>
                  <description>Disabled</description>
                  <value>#0</value>
                </enumeratedValue>
                <enumeratedValue>
                  <name>1</name>
                  <description>Enabled</description>
                  <value>#1</value>
                </enumeratedValue>
              </enumeratedValues>
            </field>
            <field>
              <name>AA</name>
              <description>Auto-align</description>
              <bitOffset>28</bitOffset>
              <bitWidth>1</bitWidth>
              <access>read-write</access>
              <enumeratedValues>
                <enumeratedValue>
                  <name>0</name>
                  <description>Auto-align disabled</description>
                  <value>#0</value>
                </enumeratedValue>
                <enumeratedValue>
                  <name>1</name>
                  <description>If SSIZE indicates a transfer no smaller than DSIZE, source accesses are auto-aligned; otherwise, destination accesses are auto-aligned. Source alignment takes precedence over destination alignment. If auto-alignment is enabled, the appropriate address register increments, regardless of DINC or SINC.</description>
                  <value>#1</value>
                </enumeratedValue>
              </enumeratedValues>
            </field>
            <field>
              <name>CS</name>
              <description>Cycle Steal</description>
              <bitOffset>29</bitOffset>
              <bitWidth>1</bitWidth>
              <access>read-write</access>
              <enumeratedValues>
                <enumeratedValue>
                  <name>0</name>
                  <description>DMA continuously makes read/write transfers until the BCR decrements to 0.</description>
                  <value>#0</value>
                </enumeratedValue>
                <enumeratedValue>
                  <name>1</name>
                  <description>Forces a single read/write transfer per request.</description>
                  <value>#1</value>
                </enumeratedValue>
              </enumeratedValues>
            </field>
            <field>
              <name>ERQ</name>
              <description>Enable Peripheral Request</description>
              <bitOffset>30</bitOffset>
              <bitWidth>1</bitWidth>
              <access>read-write</access>
              <enumeratedValues>
                <enumeratedValue>
                  <name>0</name>
                  <description>Peripheral request is ignored.</description>
                  <value>#0</value>
                </enumeratedValue>
                <enumeratedValue>
                  <name>1</name>
                  <description>Enables peripheral request to initiate transfer. A software-initiated request (setting START) is always enabled.</description>
                  <value>#1</value>
                </enumeratedValue>
              </enumeratedValues>
            </field>
            <field>
              <name>EINT</name>
              <description>Enable Interrupt on Completion of Transfer</description>
              <bitOffset>31</bitOffset>
              <bitWidth>1</bitWidth>
              <access>read-write</access>
              <enumeratedValues>
                <enumeratedValue>
                  <name>0</name>
                  <description>No interrupt is generated.</description>
                  <value>#0</value>
                </enumeratedValue>
                <enumeratedValue>
                  <name>1</name>
                  <description>Interrupt signal is enabled.</description>
                  <value>#1</value>
                </enumeratedValue>
              </enumeratedValues>
            </field>
          </fields>
        </register>
      </registers>
    </peripheral>
    <peripheral>
      <name>FTFA</name>
      <description>Flash Memory Interface</description>
      <prependToName>FTFA_</prependToName>
      <baseAddress>0x40020000</baseAddress>
      <addressBlock>
        <offset>0</offset>
        <size>0x14</size>
        <usage>registers</usage>
      </addressBlock>
      <interrupt>
        <name>FTFA</name>
        <value>5</value>
      </interrupt>
      <registers>
        <register>
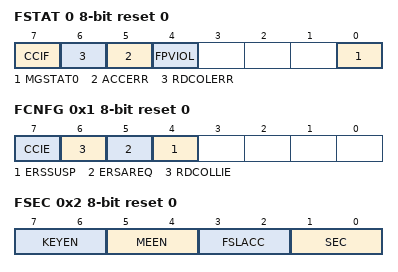
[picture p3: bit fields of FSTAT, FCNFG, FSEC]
          <name>FSTAT</name>
          <description>Flash Status Register</description>
          <addressOffset>0</addressOffset>
          <size>8</size>
          <access>read-write</access>
          <resetValue>0</resetValue>
          <resetMask>0xFF</resetMask>
          <fields>
            <field>
              <name>MGSTAT0</name>
              <description>Memory Controller Command Completion Status Flag</description>
              <bitOffset>0</bitOffset>
              <bitWidth>1</bitWidth>
              <access>read-only</access>
            </field>
            <field>
              <name>FPVIOL</name>
              <description>Flash Protection Violation Flag</description>
              <bitOffset>4</bitOffset>
              <bitWidth>1</bitWidth>
              <access>read-write</access>
              <enumeratedValues>
                <enumeratedValue>
                  <name>0</name>
                  <description>No protection violation detected</description>
                  <value>#0</value>
                </enumeratedValue>
                <enumeratedValue>
                  <name>1</name>
                  <description>Protection violation detected</description>
                  <value>#1</value>
                </enumeratedValue>
              </enumeratedValues>
            </field>
            <field>
              <name>ACCERR</name>
              <description>Flash Access Error Flag</description>
              <bitOffset>5</bitOffset>
              <bitWidth>1</bitWidth>
              <access>read-write</access>
              <enumeratedValues>
                <enumeratedValue>
                  <name>0</name>
                  <description>No access error detected</description>
                  <value>#0</value>
                </enumeratedValue>
                <enumeratedValue>
                  <name>1</name>
                  <description>Access error detected</description>
                  <value>#1</value>
                </enumeratedValue>
              </enumeratedValues>
            </field>
            <field>
              <name>RDCOLERR</name>
              <description>Flash Read Collision Error Flag</description>
              <bitOffset>6</bitOffset>
              <bitWidth>1</bitWidth>
              <access>read-write</access>
              <enumeratedValues>
                <enumeratedValue>
                  <name>0</name>
                  <description>No collision error detected</description>
                  <value>#0</value>
                </enumeratedValue>
                <enumeratedValue>
                  <name>1</name>
                  <description>Collision error detected</description>
                  <value>#1</value>
                </enumeratedValue>
              </enumeratedValues>
            </field>
            <field>
              <name>CCIF</name>
              <description>Command Complete Interrupt Flag</description>
              <bitOffset>7</bitOffset>
              <bitWidth>1</bitWidth>
              <access>read-write</access>
              <enumeratedValues>
                <enumeratedValue>
                  <name>0</name>
                  <description>Flash command in progress</description>
                  <value>#0</value>
                </enumeratedValue>
                <enumeratedValue>
                  <name>1</name>
                  <description>Flash command has completed</description>
                  <value>#1</value>
                </enumeratedValue>
              </enumeratedValues>
            </field>
          </fields>
        </register>
        <register>
          <name>FCNFG</name>
          <description>Flash Configuration Register</description>
          <addressOffset>0x1</addressOffset>
          <size>8</size>
          <access>read-write</access>
          <resetValue>0</resetValue>
          <resetMask>0xFF</resetMask>
          <fields>
            <field>
              <name>ERSSUSP</name>
              <description>Erase Suspend</description>
              <bitOffset>4</bitOffset>
              <bitWidth>1</bitWidth>
              <access>read-write</access>
              <enumeratedValues>
                <enumeratedValue>
                  <name>0</name>
                  <description>No suspend requested</description>
                  <value>#0</value>
                </enumeratedValue>
                <enumeratedValue>
                  <name>1</name>
                  <description>Suspend the current Erase Flash Sector command execution.</description>
                  <value>#1</value>
                </enumeratedValue>
              </enumeratedValues>
            </field>
            <field>
              <name>ERSAREQ</name>
              <description>Erase All Request</description>
              <bitOffset>5</bitOffset>
              <bitWidth>1</bitWidth>
              <access>read-only</access>
              <enumeratedValues>
                <enumeratedValue>
                  <name>0</name>
                  <description>No request or request complete</description>
                  <value>#0</value>
                </enumeratedValue>
                <enumeratedValue>
                  <name>1</name>
                  <description>Request to: run the Erase All Blocks command, verify the erased state, program the security byte in the Flash Configuration Field to the unsecure state, and release MCU security by setting the FSEC[SEC] field to the unsecure state.</description>
                  <value>#1</value>
                </enumeratedValue>
              </enumeratedValues>
            </field>
            <field>
              <name>RDCOLLIE</name>
              <description>Read Collision Error Interrupt Enable</description>
              <bitOffset>6</bitOffset>
              <bitWidth>1</bitWidth>
              <access>read-write</access>
              <enumeratedValues>
                <enumeratedValue>
                  <name>0</name>
                  <description>Read collision error interrupt disabled</description>
                  <value>#0</value>
                </enumeratedValue>
                <enumeratedValue>
                  <name>1</name>
                  <description>Read collision error interrupt enabled. An interrupt request is generated whenever a flash memory read collision error is detected (see the description of FSTAT[RDCOLERR]).</description>
                  <value>#1</value>
                </enumeratedValue>
              </enumeratedValues>
            </field>
            <field>
              <name>CCIE</name>
              <description>Command Complete Interrupt Enable</description>
              <bitOffset>7</bitOffset>
              <bitWidth>1</bitWidth>
              <access>read-write</access>
              <enumeratedValues>
                <enumeratedValue>
                  <name>0</name>
                  <description>Command complete interrupt disabled</description>
                  <value>#0</value>
                </enumeratedValue>
                <enumeratedValue>
                  <name>1</name>
                  <description>Command complete interrupt enabled. An interrupt request is generated whenever the FSTAT[CCIF] flag is set.</description>
                  <value>#1</value>
                </enumeratedValue>
              </enumeratedValues>
            </field>
          </fields>
        </register>
        <register>
          <name>FSEC</name>
          <description>Flash Security Register</description>
          <addressOffset>0x2</addressOffset>
          <size>8</size>
          <access>read-only</access>
          <resetValue>0</resetValue>
          <resetMask>0</resetMask>
          <fields>
            <field>
              <name>SEC</name>
              <description>Flash Security</description>
              <bitOffset>0</bitOffset>
              <bitWidth>2</bitWidth>
              <access>read-only</access>
              <enumeratedValues>
                <enumeratedValue>
                  <name>00</name>
                  <description>MCU security status is secure.</description>
                  <value>#00</value>
                </enumeratedValue>
                <enumeratedValue>
                  <name>01</name>
                  <description>MCU security status is secure.</description>
                  <value>#01</value>
                </enumeratedValue>
                <enumeratedValue>
                  <name>10</name>
                  <description>MCU security status is unsecure. (The standard shipping condition of the flash memory module is unsecure.)</description>
                  <value>#10</value>
                </enumeratedValue>
                <enumeratedValue>
                  <name>11</name>
                  <description>MCU security status is secure.</description>
                  <value>#11</value>
                </enumeratedValue>
              </enumeratedValues>
            </field>
            <field>
              <name>FSLACC</name>
              <description>Freescale Failure Analysis Access Code</description>
              <bitOffset>2</bitOffset>
              <bitWidth>2</bitWidth>
              <access>read-only</access>
              <enumeratedValues>
                <enumeratedValue>
                  <name>00</name>
                  <description>Freescale factory access granted</description>
                  <value>#00</value>
                </enumeratedValue>
                <enumeratedValue>
                  <name>01</name>
                  <description>Freescale factory access denied</description>
                  <value>#01</value>
                </enumeratedValue>
                <enumeratedValue>
                  <name>10</name>
                  <description>Freescale factory access denied</description>
                  <value>#10</value>
                </enumeratedValue>
                <enumeratedValue>
                  <name>11</name>
                  <description>Freescale factory access granted</description>
                  <value>#11</value>
                </enumeratedValue>
              </enumeratedValues>
            </field>
            <field>
              <name>MEEN</name>
              <description>Mass Erase Enable Bits</description>
              <bitOffset>4</bitOffset>
              <bitWidth>2</bitWidth>
              <access>read-only</access>
              <enumeratedValues>
                <enumeratedValue>
                  <name>00</name>
                  <description>Mass erase is enabled</description>
                  <value>#00</value>
                </enumeratedValue>
                <enumeratedValue>
                  <name>01</name>
                  <description>Mass erase is enabled</description>
                  <value>#01</value>
                </enumeratedValue>
                <enumeratedValue>
                  <name>10</name>
                  <description>Mass erase is disabled</description>
                  <value>#10</value>
                </enumeratedValue>
                <enumeratedValue>
                  <name>11</name>
                  <description>Mass erase is enabled</description>
                  <value>#11</value>
                </enumeratedValue>
              </enumeratedValues>
            </field>
            <field>
              <name>KEYEN</name>
              <description>Backdoor Key Security Enable</description>
              <bitOffset>6</bitOffset>
              <bitWidth>2</bitWidth>
              <access>read-only</access>
              <enumeratedValues>
                <enumeratedValue>
                  <name>00</name>
                  <description>Backdoor key access disabled</description>
                  <value>#00</value>
                </enumeratedValue>
                <enumeratedValue>
                  <name>01</name>
                  <description>Backdoor key access disabled (preferred KEYEN state to disable backdoor key access)</description>
                  <value>#01</value>
                </enumeratedValue>
                <enumeratedValue>
                  <name>10</name>
                  <description>Backdoor key access enabled</description>
                  <value>#10</value>
                </enumeratedValue>
                <enumeratedValue>
                  <name>11</name>
                  <description>Backdoor key access disabled</description>
                  <value>#11</value>
                </enumeratedValue>
              </enumeratedValues>
            </field>
          </fields>
        </register>
        <register>
          <name>FOPT</name>
          <description>Flash Option Register</description>
          <addressOffset>0x3</addressOffset>
          <size>8</size>
          <access>read-only</access>
          <resetValue>0</resetValue>
          <resetMask>0</resetMask>
          <fields>
            <field>
              <name>OPT</name>
              <description>Nonvolatile Option</description>
              <bitOffset>0</bitOffset>
              <bitWidth>8</bitWidth>
              <access>read-only</access>
            </field>
          </fields>
        </register>
        <register>
          <dim>12</dim>
          <dimIncrement>0x1</dimIncrement>
          <dimIndex>3,2,1,0,7,6,5,4,B,A,9,8</dimIndex>
          <name>FCCOB%s</name>
          <description>Flash Common Command Object Registers</description>
          <addressOffset>0x4</addressOffset>
          <size>8</size>
          <access>read-write</access>
          <resetValue>0</resetValue>
          <resetMask>0xFF</resetMask>
          <fields>
            <field>
              <name>CCOBn</name>
              <description>The FCCOB register provides a command code and relevant parameters to the memory controller</description>
              <bitOffset>0</bitOffset>
              <bitWidth>8</bitWidth>
              <access>read-write</access>
            </field>
          </fields>
        </register>
        <register>
          <dim>4</dim>
          <dimIncrement>0x1</dimIncrement>
          <dimIndex>3,2,1,0</dimIndex>
          <name>FPROT%s</name>
          <description>Program Flash Protection Registers</description>
          <addressOffset>0x10</addressOffset>
          <size>8</size>
          <access>read-write</access>
          <resetValue>0</resetValue>
          <resetMask>0</resetMask>
          <fields>
            <field>
              <name>PROT</name>
              <description>Program Flash Region Protect</description>
              <bitOffset>0</bitOffset>
              <bitWidth>8</bitWidth>
              <access>read-write</access>
              <enumeratedValues>
                <enumeratedValue>
                  <name>0</name>
                  <description>Program flash region is protected.</description>
                  <value>#0</value>
                </enumeratedValue>
                <enumeratedValue>
                  <name>1</name>
                  <description>Program flash region is not protected</description>
                  <value>#1</value>
                </enumeratedValue>
              </enumeratedValues>
            </field>
          </fields>
        </register>
      </registers>
    </peripheral>
    <peripheral>
      <name>DMAMUX0</name>
      <description>DMA channel multiplexor</description>
      <prependToName>DMAMUX0_</prependToName>
      <baseAddress>0x40021000</baseAddress>
      <addressBlock>
        <offset>0</offset>
        <size>0x4</size>
        <usage>registers</usage>
      </addressBlock>
      <registers>
        <register>
          <dim>4</dim>
          <dimIncrement>0x1</dimIncrement>
          <dimIndex>0,1,2,3</dimIndex>
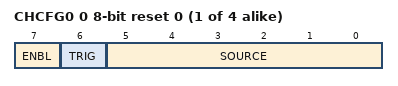
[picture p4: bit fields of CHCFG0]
          <name>CHCFG%s</name>
          <description>Channel Configuration register</description>
          <addressOffset>0</addressOffset>
          <size>8</size>
          <access>read-write</access>
          <resetValue>0</resetValue>
          <resetMask>0xFF</resetMask>
          <fields>
            <field>
              <name>SOURCE</name>
              <description>DMA Channel Source (Slot)</description>
              <bitOffset>0</bitOffset>
              <bitWidth>6</bitWidth>
              <access>read-write</access>
            </field>
            <field>
              <name>TRIG</name>
              <description>DMA Channel Trigger Enable</description>
              <bitOffset>6</bitOffset>
              <bitWidth>1</bitWidth>
              <access>read-write</access>
              <enumeratedValues>
                <enumeratedValue>
                  <name>0</name>
                  <description>Triggering is disabled. If triggering is disabled and ENBL is set, the DMA Channel will simply route the specified source to the DMA channel. (Normal mode)</description>
                  <value>#0</value>
                </enumeratedValue>
                <enumeratedValue>
                  <name>1</name>
                  <description>Triggering is enabled. If triggering is enabled and ENBL is set, the DMAMUX is in Periodic Trigger mode.</description>
                  <value>#1</value>
                </enumeratedValue>
              </enumeratedValues>
            </field>
            <field>
              <name>ENBL</name>
              <description>DMA Channel Enable</description>
              <bitOffset>7</bitOffset>
              <bitWidth>1</bitWidth>
              <access>read-write</access>
              <enumeratedValues>
                <enumeratedValue>
                  <name>0</name>
                  <description>DMA channel is disabled. This mode is primarily used during configuration of the DMAMux. The DMA has separate channel enables/disables, which should be used to disable or reconfigure a DMA channel.</description>
                  <value>#0</value>
                </enumeratedValue>
                <enumeratedValue>
                  <name>1</name>
                  <description>DMA channel is enabled</description>
                  <value>#1</value>
                </enumeratedValue>
              </enumeratedValues>
            </field>
          </fields>
        </register>
      </registers>
    </peripheral>
    <peripheral>
      <name>I2S0</name>
      <description>Inter-IC Sound / Synchronous Audio Interface</description>
      <prependToName>I2S0_</prependToName>
      <baseAddress>0x4002F000</baseAddress>
      <addressBlock>
        <offset>0</offset>
        <size>0x108</size>
        <usage>registers</usage>
      </addressBlock>
      <interrupt>
        <name>I2S0</name>
        <value>23</value>
      </interrupt>
      <registers>
        <register>
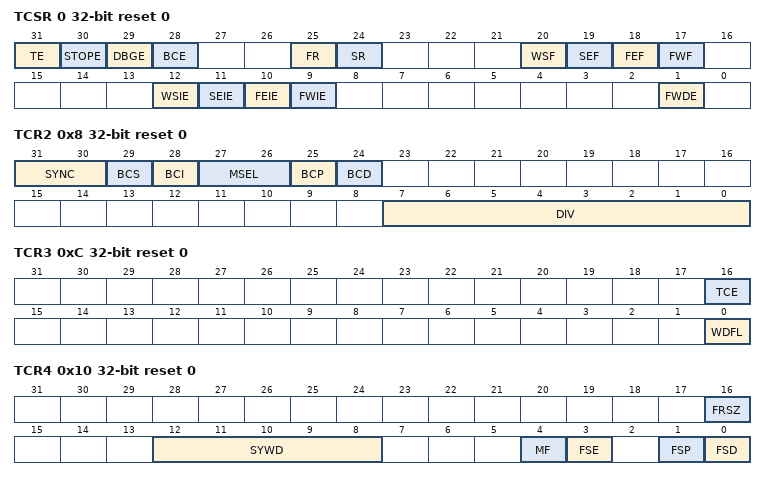
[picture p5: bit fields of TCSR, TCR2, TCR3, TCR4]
          <name>TCSR</name>
          <description>SAI Transmit Control Register</description>
          <addressOffset>0</addressOffset>
          <size>32</size>
          <access>read-write</access>
          <resetValue>0</resetValue>
          <resetMask>0xFFFFFFFF</resetMask>
          <fields>
            <field>
              <name>FWDE</name>
              <description>FIFO Warning DMA Enable</description>
              <bitOffset>1</bitOffset>
              <bitWidth>1</bitWidth>
              <access>read-write</access>
              <enumeratedValues>
                <enumeratedValue>
                  <name>0</name>
                  <description>Disables the DMA request.</description>
                  <value>#0</value>
                </enumeratedValue>
                <enumeratedValue>
                  <name>1</name>
                  <description>Enables the DMA request.</description>
                  <value>#1</value>
                </enumeratedValue>
              </enumeratedValues>
            </field>
            <field>
              <name>FWIE</name>
              <description>FIFO Warning Interrupt Enable</description>
              <bitOffset>9</bitOffset>
              <bitWidth>1</bitWidth>
              <access>read-write</access>
              <enumeratedValues>
                <enumeratedValue>
                  <name>0</name>
                  <description>Disables the interrupt.</description>
                  <value>#0</value>
                </enumeratedValue>
                <enumeratedValue>
                  <name>1</name>
                  <description>Enables the interrupt.</description>
                  <value>#1</value>
                </enumeratedValue>
              </enumeratedValues>
            </field>
            <field>
              <name>FEIE</name>
              <description>FIFO Error Interrupt Enable</description>
              <bitOffset>10</bitOffset>
              <bitWidth>1</bitWidth>
              <access>read-write</access>
              <enumeratedValues>
                <enumeratedValue>
                  <name>0</name>
                  <description>Disables the interrupt.</description>
                  <value>#0</value>
                </enumeratedValue>
                <enumeratedValue>
                  <name>1</name>
                  <description>Enables the interrupt.</description>
                  <value>#1</value>
                </enumeratedValue>
              </enumeratedValues>
            </field>
            <field>
              <name>SEIE</name>
              <description>Sync Error Interrupt Enable</description>
              <bitOffset>11</bitOffset>
              <bitWidth>1</bitWidth>
              <access>read-write</access>
              <enumeratedValues>
                <enumeratedValue>
                  <name>0</name>
                  <description>Disables interrupt.</description>
                  <value>#0</value>
                </enumeratedValue>
                <enumeratedValue>
                  <name>1</name>
                  <description>Enables interrupt.</description>
                  <value>#1</value>
                </enumeratedValue>
              </enumeratedValues>
            </field>
            <field>
              <name>WSIE</name>
              <description>Word Start Interrupt Enable</description>
              <bitOffset>12</bitOffset>
              <bitWidth>1</bitWidth>
              <access>read-write</access>
              <enumeratedValues>
                <enumeratedValue>
                  <name>0</name>
                  <description>Disables interrupt.</description>
                  <value>#0</value>
                </enumeratedValue>
                <enumeratedValue>
                  <name>1</name>
                  <description>Enables interrupt.</description>
                  <value>#1</value>
                </enumeratedValue>
              </enumeratedValues>
            </field>
            <field>
              <name>FWF</name>
              <description>FIFO Warning Flag</description>
              <bitOffset>17</bitOffset>
              <bitWidth>1</bitWidth>
              <access>read-only</access>
              <enumeratedValues>
                <enumeratedValue>
                  <name>0</name>
                  <description>No enabled transmit FIFO is empty.</description>
                  <value>#0</value>
                </enumeratedValue>
                <enumeratedValue>
                  <name>1</name>
                  <description>Enabled transmit FIFO is empty.</description>
                  <value>#1</value>
                </enumeratedValue>
              </enumeratedValues>
            </field>
            <field>
              <name>FEF</name>
              <description>FIFO Error Flag</description>
              <bitOffset>18</bitOffset>
              <bitWidth>1</bitWidth>
              <access>read-write</access>
              <enumeratedValues>
                <enumeratedValue>
                  <name>0</name>
                  <description>Transmit underrun not detected.</description>
                  <value>#0</value>
                </enumeratedValue>
                <enumeratedValue>
                  <name>1</name>
                  <description>Transmit underrun detected.</description>
                  <value>#1</value>
                </enumeratedValue>
              </enumeratedValues>
            </field>
            <field>
              <name>SEF</name>
              <description>Sync Error Flag</description>
              <bitOffset>19</bitOffset>
              <bitWidth>1</bitWidth>
              <access>read-write</access>
              <enumeratedValues>
                <enumeratedValue>
                  <name>0</name>
                  <description>Sync error not detected.</description>
                  <value>#0</value>
                </enumeratedValue>
                <enumeratedValue>
                  <name>1</name>
                  <description>Frame sync error detected.</description>
                  <value>#1</value>
                </enumeratedValue>
              </enumeratedValues>
            </field>
            <field>
              <name>WSF</name>
              <description>Word Start Flag</description>
              <bitOffset>20</bitOffset>
              <bitWidth>1</bitWidth>
              <access>read-write</access>
              <enumeratedValues>
                <enumeratedValue>
                  <name>0</name>
                  <description>Start of word not detected.</description>
                  <value>#0</value>
                </enumeratedValue>
                <enumeratedValue>
                  <name>1</name>
                  <description>Start of word detected.</description>
                  <value>#1</value>
                </enumeratedValue>
              </enumeratedValues>
            </field>
            <field>
              <name>SR</name>
              <description>Software Reset</description>
              <bitOffset>24</bitOffset>
              <bitWidth>1</bitWidth>
              <access>read-write</access>
              <enumeratedValues>
                <enumeratedValue>
                  <name>0</name>
                  <description>No effect.</description>
                  <value>#0</value>
                </enumeratedValue>
                <enumeratedValue>
                  <name>1</name>
                  <description>Software reset.</description>
                  <value>#1</value>
                </enumeratedValue>
              </enumeratedValues>
            </field>
            <field>
              <name>FR</name>
              <description>FIFO Reset</description>
              <bitOffset>25</bitOffset>
              <bitWidth>1</bitWidth>
              <access>write-only</access>
              <enumeratedValues>
                <enumeratedValue>
                  <name>0</name>
                  <description>No effect.</description>
                  <value>#0</value>
                </enumeratedValue>
                <enumeratedValue>
                  <name>1</name>
                  <description>FIFO reset.</description>
                  <value>#1</value>
                </enumeratedValue>
              </enumeratedValues>
            </field>
            <field>
              <name>BCE</name>
              <description>Bit Clock Enable</description>
              <bitOffset>28</bitOffset>
              <bitWidth>1</bitWidth>
              <access>read-write</access>
              <enumeratedValues>
                <enumeratedValue>
                  <name>0</name>
                  <description>Transmit bit clock is disabled.</description>
                  <value>#0</value>
                </enumeratedValue>
                <enumeratedValue>
                  <name>1</name>
                  <description>Transmit bit clock is enabled.</description>
                  <value>#1</value>
                </enumeratedValue>
              </enumeratedValues>
            </field>
            <field>
              <name>DBGE</name>
              <description>Debug Enable</description>
              <bitOffset>29</bitOffset>
              <bitWidth>1</bitWidth>
              <access>read-write</access>
              <enumeratedValues>
                <enumeratedValue>
                  <name>0</name>
                  <description>Transmitter is disabled in Debug mode, after completing the current frame.</description>
                  <value>#0</value>
                </enumeratedValue>
                <enumeratedValue>
                  <name>1</name>
                  <description>Transmitter is enabled in Debug mode.</description>
                  <value>#1</value>
                </enumeratedValue>
              </enumeratedValues>
            </field>
            <field>
              <name>STOPE</name>
              <description>Stop Enable</description>
              <bitOffset>30</bitOffset>
              <bitWidth>1</bitWidth>
              <access>read-write</access>
              <enumeratedValues>
                <enumeratedValue>
                  <name>0</name>
                  <description>Transmitter disabled in Stop mode.</description>
                  <value>#0</value>
                </enumeratedValue>
                <enumeratedValue>
                  <name>1</name>
                  <description>Transmitter enabled in Stop mode.</description>
                  <value>#1</value>
                </enumeratedValue>
              </enumeratedValues>
            </field>
            <field>
              <name>TE</name>
              <description>Transmitter Enable</description>
              <bitOffset>31</bitOffset>
              <bitWidth>1</bitWidth>
              <access>read-write</access>
              <enumeratedValues>
                <enumeratedValue>
                  <name>0</name>
                  <description>Transmitter is disabled.</description>
                  <value>#0</value>
                </enumeratedValue>
                <enumeratedValue>
                  <name>1</name>
                  <description>Transmitter is enabled, or transmitter has been disabled and has not yet reached end of frame.</description>
                  <value>#1</value>
                </enumeratedValue>
              </enumeratedValues>
            </field>
          </fields>
        </register>
        <register>
          <name>TCR2</name>
          <description>SAI Transmit Configuration 2 Register</description>
          <addressOffset>0x8</addressOffset>
          <size>32</size>
          <access>read-write</access>
          <resetValue>0</resetValue>
          <resetMask>0xFFFFFFFF</resetMask>
          <fields>
            <field>
              <name>DIV</name>
              <description>Bit Clock Divide</description>
              <bitOffset>0</bitOffset>
              <bitWidth>8</bitWidth>
              <access>read-write</access>
            </field>
            <field>
              <name>BCD</name>
              <description>Bit Clock Direction</description>
              <bitOffset>24</bitOffset>
              <bitWidth>1</bitWidth>
              <access>read-write</access>
              <enumeratedValues>
                <enumeratedValue>
                  <name>0</name>
                  <description>Bit clock is generated externally in Slave mode.</description>
                  <value>#0</value>
                </enumeratedValue>
                <enumeratedValue>
                  <name>1</name>
                  <description>Bit clock is generated internally in Master mode.</description>
                  <value>#1</value>
                </enumeratedValue>
              </enumeratedValues>
            </field>
            <field>
              <name>BCP</name>
              <description>Bit Clock Polarity</description>
              <bitOffset>25</bitOffset>
              <bitWidth>1</bitWidth>
              <access>read-write</access>
              <enumeratedValues>
                <enumeratedValue>
                  <name>0</name>
                  <description>Bit clock is active high with drive outputs on rising edge and sample inputs on falling edge.</description>
                  <value>#0</value>
                </enumeratedValue>
                <enumeratedValue>
                  <name>1</name>
                  <description>Bit clock is active low with drive outputs on falling edge and sample inputs on rising edge.</description>
                  <value>#1</value>
                </enumeratedValue>
              </enumeratedValues>
            </field>
            <field>
              <name>MSEL</name>
              <description>MCLK Select</description>
              <bitOffset>26</bitOffset>
              <bitWidth>2</bitWidth>
              <access>read-write</access>
              <enumeratedValues>
                <enumeratedValue>
                  <name>00</name>
                  <description>Bus Clock selected.</description>
                  <value>#00</value>
                </enumeratedValue>
                <enumeratedValue>
                  <name>01</name>
                  <description>Master Clock (MCLK) 1 option selected.</description>
                  <value>#01</value>
                </enumeratedValue>
                <enumeratedValue>
                  <name>10</name>
                  <description>Master Clock (MCLK) 2 option selected.</description>
                  <value>#10</value>
                </enumeratedValue>
                <enumeratedValue>
                  <name>11</name>
                  <description>Master Clock (MCLK) 3 option selected.</description>
                  <value>#11</value>
                </enumeratedValue>
              </enumeratedValues>
            </field>
            <field>
              <name>BCI</name>
              <description>Bit Clock Input</description>
              <bitOffset>28</bitOffset>
              <bitWidth>1</bitWidth>
              <access>read-write</access>
              <enumeratedValues>
                <enumeratedValue>
                  <name>0</name>
                  <description>No effect.</description>
                  <value>#0</value>
                </enumeratedValue>
                <enumeratedValue>
                  <name>1</name>
                  <description>Internal logic is clocked as if bit clock was externally generated.</description>
                  <value>#1</value>
                </enumeratedValue>
              </enumeratedValues>
            </field>
            <field>
              <name>BCS</name>
              <description>Bit Clock Swap</description>
              <bitOffset>29</bitOffset>
              <bitWidth>1</bitWidth>
              <access>read-write</access>
              <enumeratedValues>
                <enumeratedValue>
                  <name>0</name>
                  <description>Use the normal bit clock source.</description>
                  <value>#0</value>
                </enumeratedValue>
                <enumeratedValue>
                  <name>1</name>
                  <description>Swap the bit clock source.</description>
                  <value>#1</value>
                </enumeratedValue>
              </enumeratedValues>
            </field>
            <field>
              <name>SYNC</name>
              <description>Synchronous Mode</description>
              <bitOffset>30</bitOffset>
              <bitWidth>2</bitWidth>
              <access>read-write</access>
              <enumeratedValues>
                <enumeratedValue>
                  <name>00</name>
                  <description>Asynchronous mode.</description>
                  <value>#00</value>
                </enumeratedValue>
                <enumeratedValue>
                  <name>01</name>
                  <description>Synchronous with receiver.</description>
                  <value>#01</value>
                </enumeratedValue>
                <enumeratedValue>
                  <name>10</name>
                  <description>Synchronous with another SAI transmitter.</description>
                  <value>#10</value>
                </enumeratedValue>
                <enumeratedValue>
                  <name>11</name>
                  <description>Synchronous with another SAI receiver.</description>
                  <value>#11</value>
                </enumeratedValue>
              </enumeratedValues>
            </field>
          </fields>
        </register>
        <register>
          <name>TCR3</name>
          <description>SAI Transmit Configuration 3 Register</description>
          <addressOffset>0xC</addressOffset>
          <size>32</size>
          <access>read-write</access>
          <resetValue>0</resetValue>
          <resetMask>0xFFFFFFFF</resetMask>
          <fields>
            <field>
              <name>WDFL</name>
              <description>Word Flag Configuration</description>
              <bitOffset>0</bitOffset>
              <bitWidth>1</bitWidth>
              <access>read-write</access>
            </field>
            <field>
              <name>TCE</name>
              <description>Transmit Channel Enable</description>
              <bitOffset>16</bitOffset>
              <bitWidth>1</bitWidth>
              <access>read-write</access>
              <enumeratedValues>
                <enumeratedValue>
                  <name>0</name>
                  <description>Transmit data channel N is disabled.</description>
                  <value>#0</value>
                </enumeratedValue>
                <enumeratedValue>
                  <name>1</name>
                  <description>Transmit data channel N is enabled.</description>
                  <value>#1</value>
                </enumeratedValue>
              </enumeratedValues>
            </field>
          </fields>
        </register>
        <register>
          <name>TCR4</name>
          <description>SAI Transmit Configuration 4 Register</description>
          <addressOffset>0x10</addressOffset>
          <size>32</size>
          <access>read-write</access>
          <resetValue>0</resetValue>
          <resetMask>0xFFFFFFFF</resetMask>
          <fields>
            <field>
              <name>FSD</name>
              <description>Frame Sync Direction</description>
              <bitOffset>0</bitOffset>
              <bitWidth>1</bitWidth>
              <access>read-write</access>
              <enumeratedValues>
                <enumeratedValue>
                  <name>0</name>
                  <description>Frame sync is generated externally in Slave mode.</description>
                  <value>#0</value>
                </enumeratedValue>
                <enumeratedValue>
                  <name>1</name>
                  <description>Frame sync is generated internally in Master mode.</description>
                  <value>#1</value>
                </enumeratedValue>
              </enumeratedValues>
            </field>
            <field>
              <name>FSP</name>
              <description>Frame Sync Polarity</description>
              <bitOffset>1</bitOffset>
              <bitWidth>1</bitWidth>
              <access>read-write</access>
              <enumeratedValues>
                <enumeratedValue>
                  <name>0</name>
                  <description>Frame sync is active high.</description>
                  <value>#0</value>
                </enumeratedValue>
                <enumeratedValue>
                  <name>1</name>
                  <description>Frame sync is active low.</description>
                  <value>#1</value>
                </enumeratedValue>
              </enumeratedValues>
            </field>
            <field>
              <name>FSE</name>
              <description>Frame Sync Early</description>
              <bitOffset>3</bitOffset>
              <bitWidth>1</bitWidth>
              <access>read-write</access>
              <enumeratedValues>
                <enumeratedValue>
                  <name>0</name>
                  <description>Frame sync asserts with the first bit of the frame.</description>
                  <value>#0</value>
                </enumeratedValue>
                <enumeratedValue>
                  <name>1</name>
                  <description>Frame sync asserts one bit before the first bit of the frame.</description>
                  <value>#1</value>
                </enumeratedValue>
              </enumeratedValues>
            </field>
            <field>
              <name>MF</name>
              <description>MSB First</description>
              <bitOffset>4</bitOffset>
              <bitWidth>1</bitWidth>
              <access>read-write</access>
              <enumeratedValues>
                <enumeratedValue>
                  <name>0</name>
                  <description>LSB is transmitted first.</description>
                  <value>#0</value>
                </enumeratedValue>
                <enumeratedValue>
                  <name>1</name>
                  <description>MSB is transmitted first.</description>
                  <value>#1</value>
                </enumeratedValue>
              </enumeratedValues>
            </field>
            <field>
              <name>SYWD</name>
              <description>Sync Width</description>
              <bitOffset>8</bitOffset>
              <bitWidth>5</bitWidth>
              <access>read-write</access>
            </field>
            <field>
              <name>FRSZ</name>
              <description>Frame size</description>
              <bitOffset>16</bitOffset>
              <bitWidth>1</bitWidth>
              <access>read-write</access>
            </field>
          </fields>
        </register>
        <register>
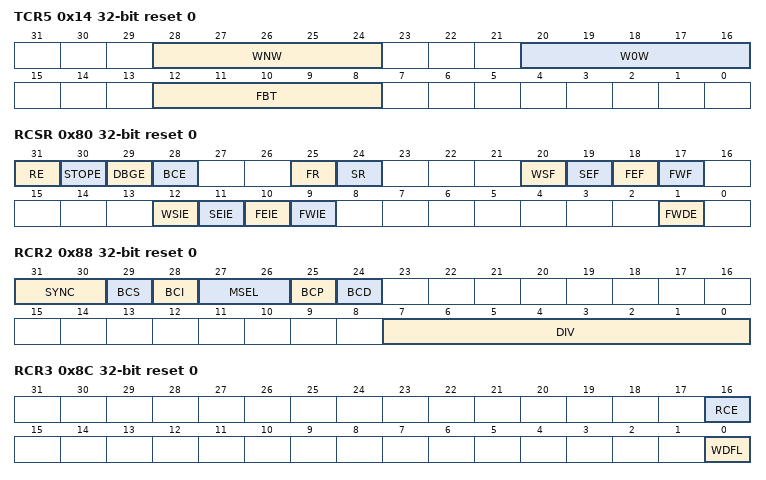
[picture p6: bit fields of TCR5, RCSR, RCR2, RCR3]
          <name>TCR5</name>
          <description>SAI Transmit Configuration 5 Register</description>
          <addressOffset>0x14</addressOffset>
          <size>32</size>
          <access>read-write</access>
          <resetValue>0</resetValue>
          <resetMask>0xFFFFFFFF</resetMask>
          <fields>
            <field>
              <name>FBT</name>
              <description>First Bit Shifted</description>
              <bitOffset>8</bitOffset>
              <bitWidth>5</bitWidth>
              <access>read-write</access>
            </field>
            <field>
              <name>W0W</name>
              <description>Word 0 Width</description>
              <bitOffset>16</bitOffset>
              <bitWidth>5</bitWidth>
              <access>read-write</access>
            </field>
            <field>
              <name>WNW</name>
              <description>Word N Width</description>
              <bitOffset>24</bitOffset>
              <bitWidth>5</bitWidth>
              <access>read-write</access>
            </field>
          </fields>
        </register>
        <register>
          <name>TDR</name>
          <description>SAI Transmit Data Register</description>
          <addressOffset>0x20</addressOffset>
          <size>32</size>
          <access>write-only</access>
          <resetValue>0</resetValue>
          <resetMask>0xFFFFFFFF</resetMask>
          <fields>
            <field>
              <name>TDR</name>
              <description>Transmit Data Register</description>
              <bitOffset>0</bitOffset>
              <bitWidth>32</bitWidth>
              <access>write-only</access>
            </field>
          </fields>
        </register>
        <register>
          <name>TMR</name>
          <description>SAI Transmit Mask Register</description>
          <addressOffset>0x60</addressOffset>
          <size>32</size>
          <access>read-write</access>
          <resetValue>0</resetValue>
          <resetMask>0xFFFFFFFF</resetMask>
          <fields>
            <field>
              <name>TWM</name>
              <description>Transmit Word Mask</description>
              <bitOffset>0</bitOffset>
              <bitWidth>2</bitWidth>
              <access>read-write</access>
              <enumeratedValues>
                <enumeratedValue>
                  <name>0</name>
                  <description>Word N is enabled.</description>
                  <value>#00</value>
                </enumeratedValue>
                <enumeratedValue>
                  <name>1</name>
                  <description>Word N is masked. The transmit data pins are tri-stated when masked.</description>
                  <value>#01</value>
                </enumeratedValue>
              </enumeratedValues>
            </field>
          </fields>
        </register>
        <register>
          <name>RCSR</name>
          <description>SAI Receive Control Register</description>
          <addressOffset>0x80</addressOffset>
          <size>32</size>
          <access>read-write</access>
          <resetValue>0</resetValue>
          <resetMask>0xFFFFFFFF</resetMask>
          <fields>
            <field>
              <name>FWDE</name>
              <description>FIFO Warning DMA Enable</description>
              <bitOffset>1</bitOffset>
              <bitWidth>1</bitWidth>
              <access>read-write</access>
              <enumeratedValues>
                <enumeratedValue>
                  <name>0</name>
                  <description>Disables the DMA request.</description>
                  <value>#0</value>
                </enumeratedValue>
                <enumeratedValue>
                  <name>1</name>
                  <description>Enables the DMA request.</description>
                  <value>#1</value>
                </enumeratedValue>
              </enumeratedValues>
            </field>
            <field>
              <name>FWIE</name>
              <description>FIFO Warning Interrupt Enable</description>
              <bitOffset>9</bitOffset>
              <bitWidth>1</bitWidth>
              <access>read-write</access>
              <enumeratedValues>
                <enumeratedValue>
                  <name>0</name>
                  <description>Disables the interrupt.</description>
                  <value>#0</value>
                </enumeratedValue>
                <enumeratedValue>
                  <name>1</name>
                  <description>Enables the interrupt.</description>
                  <value>#1</value>
                </enumeratedValue>
              </enumeratedValues>
            </field>
            <field>
              <name>FEIE</name>
              <description>FIFO Error Interrupt Enable</description>
              <bitOffset>10</bitOffset>
              <bitWidth>1</bitWidth>
              <access>read-write</access>
              <enumeratedValues>
                <enumeratedValue>
                  <name>0</name>
                  <description>Disables the interrupt.</description>
                  <value>#0</value>
                </enumeratedValue>
                <enumeratedValue>
                  <name>1</name>
                  <description>Enables the interrupt.</description>
                  <value>#1</value>
                </enumeratedValue>
              </enumeratedValues>
            </field>
            <field>
              <name>SEIE</name>
              <description>Sync Error Interrupt Enable</description>
              <bitOffset>11</bitOffset>
              <bitWidth>1</bitWidth>
              <access>read-write</access>
              <enumeratedValues>
                <enumeratedValue>
                  <name>0</name>
                  <description>Disables interrupt.</description>
                  <value>#0</value>
                </enumeratedValue>
                <enumeratedValue>
                  <name>1</name>
                  <description>Enables interrupt.</description>
                  <value>#1</value>
                </enumeratedValue>
              </enumeratedValues>
            </field>
            <field>
              <name>WSIE</name>
              <description>Word Start Interrupt Enable</description>
              <bitOffset>12</bitOffset>
              <bitWidth>1</bitWidth>
              <access>read-write</access>
              <enumeratedValues>
                <enumeratedValue>
                  <name>0</name>
                  <description>Disables interrupt.</description>
                  <value>#0</value>
                </enumeratedValue>
                <enumeratedValue>
                  <name>1</name>
                  <description>Enables interrupt.</description>
                  <value>#1</value>
                </enumeratedValue>
              </enumeratedValues>
            </field>
            <field>
              <name>FWF</name>
              <description>FIFO Warning Flag</description>
              <bitOffset>17</bitOffset>
              <bitWidth>1</bitWidth>
              <access>read-only</access>
              <enumeratedValues>
                <enumeratedValue>
                  <name>0</name>
                  <description>No enabled receive FIFO is full.</description>
                  <value>#0</value>
                </enumeratedValue>
                <enumeratedValue>
                  <name>1</name>
                  <description>Enabled receive FIFO is full.</description>
                  <value>#1</value>
                </enumeratedValue>
              </enumeratedValues>
            </field>
            <field>
              <name>FEF</name>
              <description>FIFO Error Flag</description>
              <bitOffset>18</bitOffset>
              <bitWidth>1</bitWidth>
              <access>read-write</access>
              <enumeratedValues>
                <enumeratedValue>
                  <name>0</name>
                  <description>Receive overflow not detected.</description>
                  <value>#0</value>
                </enumeratedValue>
                <enumeratedValue>
                  <name>1</name>
                  <description>Receive overflow detected.</description>
                  <value>#1</value>
                </enumeratedValue>
              </enumeratedValues>
            </field>
            <field>
              <name>SEF</name>
              <description>Sync Error Flag</description>
              <bitOffset>19</bitOffset>
              <bitWidth>1</bitWidth>
              <access>read-write</access>
              <enumeratedValues>
                <enumeratedValue>
                  <name>0</name>
                  <description>Sync error not detected.</description>
                  <value>#0</value>
                </enumeratedValue>
                <enumeratedValue>
                  <name>1</name>
                  <description>Frame sync error detected.</description>
                  <value>#1</value>
                </enumeratedValue>
              </enumeratedValues>
            </field>
            <field>
              <name>WSF</name>
              <description>Word Start Flag</description>
              <bitOffset>20</bitOffset>
              <bitWidth>1</bitWidth>
              <access>read-write</access>
              <enumeratedValues>
                <enumeratedValue>
                  <name>0</name>
                  <description>Start of word not detected.</description>
                  <value>#0</value>
                </enumeratedValue>
                <enumeratedValue>
                  <name>1</name>
                  <description>Start of word detected.</description>
                  <value>#1</value>
                </enumeratedValue>
              </enumeratedValues>
            </field>
            <field>
              <name>SR</name>
              <description>Software Reset</description>
              <bitOffset>24</bitOffset>
              <bitWidth>1</bitWidth>
              <access>read-write</access>
              <enumeratedValues>
                <enumeratedValue>
                  <name>0</name>
                  <description>No effect.</description>
                  <value>#0</value>
                </enumeratedValue>
                <enumeratedValue>
                  <name>1</name>
                  <description>Software reset.</description>
                  <value>#1</value>
                </enumeratedValue>
              </enumeratedValues>
            </field>
            <field>
              <name>FR</name>
              <description>FIFO Reset</description>
              <bitOffset>25</bitOffset>
              <bitWidth>1</bitWidth>
              <access>write-only</access>
              <enumeratedValues>
                <enumeratedValue>
                  <name>0</name>
                  <description>No effect.</description>
                  <value>#0</value>
                </enumeratedValue>
                <enumeratedValue>
                  <name>1</name>
                  <description>FIFO reset.</description>
                  <value>#1</value>
                </enumeratedValue>
              </enumeratedValues>
            </field>
            <field>
              <name>BCE</name>
              <description>Bit Clock Enable</description>
              <bitOffset>28</bitOffset>
              <bitWidth>1</bitWidth>
              <access>read-write</access>
              <enumeratedValues>
                <enumeratedValue>
                  <name>0</name>
                  <description>Receive bit clock is disabled.</description>
                  <value>#0</value>
                </enumeratedValue>
                <enumeratedValue>
                  <name>1</name>
                  <description>Receive bit clock is enabled.</description>
                  <value>#1</value>
                </enumeratedValue>
              </enumeratedValues>
            </field>
            <field>
              <name>DBGE</name>
              <description>Debug Enable</description>
              <bitOffset>29</bitOffset>
              <bitWidth>1</bitWidth>
              <access>read-write</access>
              <enumeratedValues>
                <enumeratedValue>
                  <name>0</name>
                  <description>Receiver is disabled in Debug mode, after completing the current frame.</description>
                  <value>#0</value>
                </enumeratedValue>
                <enumeratedValue>
                  <name>1</name>
                  <description>Receiver is enabled in Debug mode.</description>
                  <value>#1</value>
                </enumeratedValue>
              </enumeratedValues>
            </field>
            <field>
              <name>STOPE</name>
              <description>Stop Enable</description>
              <bitOffset>30</bitOffset>
              <bitWidth>1</bitWidth>
              <access>read-write</access>
              <enumeratedValues>
                <enumeratedValue>
                  <name>0</name>
                  <description>Receiver disabled in Stop mode.</description>
                  <value>#0</value>
                </enumeratedValue>
                <enumeratedValue>
                  <name>1</name>
                  <description>Receiver enabled in Stop mode.</description>
                  <value>#1</value>
                </enumeratedValue>
              </enumeratedValues>
            </field>
            <field>
              <name>RE</name>
              <description>Receiver Enable</description>
              <bitOffset>31</bitOffset>
              <bitWidth>1</bitWidth>
              <access>read-write</access>
              <enumeratedValues>
                <enumeratedValue>
                  <name>0</name>
                  <description>Receiver is disabled.</description>
                  <value>#0</value>
                </enumeratedValue>
                <enumeratedValue>
                  <name>1</name>
                  <description>Receiver is enabled, or receiver has been disabled and has not yet reached end of frame.</description>
                  <value>#1</value>
                </enumeratedValue>
              </enumeratedValues>
            </field>
          </fields>
        </register>
        <register>
          <name>RCR2</name>
          <description>SAI Receive Configuration 2 Register</description>
          <addressOffset>0x88</addressOffset>
          <size>32</size>
          <access>read-write</access>
          <resetValue>0</resetValue>
          <resetMask>0xFFFFFFFF</resetMask>
          <fields>
            <field>
              <name>DIV</name>
              <description>Bit Clock Divide</description>
              <bitOffset>0</bitOffset>
              <bitWidth>8</bitWidth>
              <access>read-write</access>
            </field>
            <field>
              <name>BCD</name>
              <description>Bit Clock Direction</description>
              <bitOffset>24</bitOffset>
              <bitWidth>1</bitWidth>
              <access>read-write</access>
              <enumeratedValues>
                <enumeratedValue>
                  <name>0</name>
                  <description>Bit clock is generated externally in Slave mode.</description>
                  <value>#0</value>
                </enumeratedValue>
                <enumeratedValue>
                  <name>1</name>
                  <description>Bit clock is generated internally in Master mode.</description>
                  <value>#1</value>
                </enumeratedValue>
              </enumeratedValues>
            </field>
            <field>
              <name>BCP</name>
              <description>Bit Clock Polarity</description>
              <bitOffset>25</bitOffset>
              <bitWidth>1</bitWidth>
              <access>read-write</access>
              <enumeratedValues>
                <enumeratedValue>
                  <name>0</name>
                  <description>Bit Clock is active high with drive outputs on rising edge and sample inputs on falling edge.</description>
                  <value>#0</value>
                </enumeratedValue>
                <enumeratedValue>
                  <name>1</name>
                  <description>Bit Clock is active low with drive outputs on falling edge and sample inputs on rising edge.</description>
                  <value>#1</value>
                </enumeratedValue>
              </enumeratedValues>
            </field>
            <field>
              <name>MSEL</name>
              <description>MCLK Select</description>
              <bitOffset>26</bitOffset>
              <bitWidth>2</bitWidth>
              <access>read-write</access>
              <enumeratedValues>
                <enumeratedValue>
                  <name>00</name>
                  <description>Bus Clock selected.</description>
                  <value>#00</value>
                </enumeratedValue>
                <enumeratedValue>
                  <name>01</name>
                  <description>Master Clock (MCLK) 1 option selected.</description>
                  <value>#01</value>
                </enumeratedValue>
                <enumeratedValue>
                  <name>10</name>
                  <description>Master Clock (MCLK) 2 option selected.</description>
                  <value>#10</value>
                </enumeratedValue>
                <enumeratedValue>
                  <name>11</name>
                  <description>Master Clock (MCLK) 3 option selected.</description>
                  <value>#11</value>
                </enumeratedValue>
              </enumeratedValues>
            </field>
            <field>
              <name>BCI</name>
              <description>Bit Clock Input</description>
              <bitOffset>28</bitOffset>
              <bitWidth>1</bitWidth>
              <access>read-write</access>
              <enumeratedValues>
                <enumeratedValue>
                  <name>0</name>
                  <description>No effect.</description>
                  <value>#0</value>
                </enumeratedValue>
                <enumeratedValue>
                  <name>1</name>
                  <description>Internal logic is clocked as if bit clock was externally generated.</description>
                  <value>#1</value>
                </enumeratedValue>
              </enumeratedValues>
            </field>
            <field>
              <name>BCS</name>
              <description>Bit Clock Swap</description>
              <bitOffset>29</bitOffset>
              <bitWidth>1</bitWidth>
              <access>read-write</access>
              <enumeratedValues>
                <enumeratedValue>
                  <name>0</name>
                  <description>Use the normal bit clock source.</description>
                  <value>#0</value>
                </enumeratedValue>
                <enumeratedValue>
                  <name>1</name>
                  <description>Swap the bit clock source.</description>
                  <value>#1</value>
                </enumeratedValue>
              </enumeratedValues>
            </field>
            <field>
              <name>SYNC</name>
              <description>Synchronous Mode</description>
              <bitOffset>30</bitOffset>
              <bitWidth>2</bitWidth>
              <access>read-write</access>
              <enumeratedValues>
                <enumeratedValue>
                  <name>00</name>
                  <description>Asynchronous mode.</description>
                  <value>#00</value>
                </enumeratedValue>
                <enumeratedValue>
                  <name>01</name>
                  <description>Synchronous with transmitter.</description>
                  <value>#01</value>
                </enumeratedValue>
                <enumeratedValue>
                  <name>10</name>
                  <description>Synchronous with another SAI receiver.</description>
                  <value>#10</value>
                </enumeratedValue>
                <enumeratedValue>
                  <name>11</name>
                  <description>Synchronous with another SAI transmitter.</description>
                  <value>#11</value>
                </enumeratedValue>
              </enumeratedValues>
            </field>
          </fields>
        </register>
        <register>
          <name>RCR3</name>
          <description>SAI Receive Configuration 3 Register</description>
          <addressOffset>0x8C</addressOffset>
          <size>32</size>
          <access>read-write</access>
          <resetValue>0</resetValue>
          <resetMask>0xFFFFFFFF</resetMask>
          <fields>
            <field>
              <name>WDFL</name>
              <description>Word Flag Configuration</description>
              <bitOffset>0</bitOffset>
              <bitWidth>1</bitWidth>
              <access>read-write</access>
            </field>
            <field>
              <name>RCE</name>
              <description>Receive Channel Enable</description>
              <bitOffset>16</bitOffset>
              <bitWidth>1</bitWidth>
              <access>read-write</access>
              <enumeratedValues>
                <enumeratedValue>
                  <name>0</name>
                  <description>Receive data channel N is disabled.</description>
                  <value>#0</value>
                </enumeratedValue>
                <enumeratedValue>
                  <name>1</name>
                  <description>Receive data channel N is enabled.</description>
                  <value>#1</value>
                </enumeratedValue>
              </enumeratedValues>
            </field>
          </fields>
        </register>
        <register>
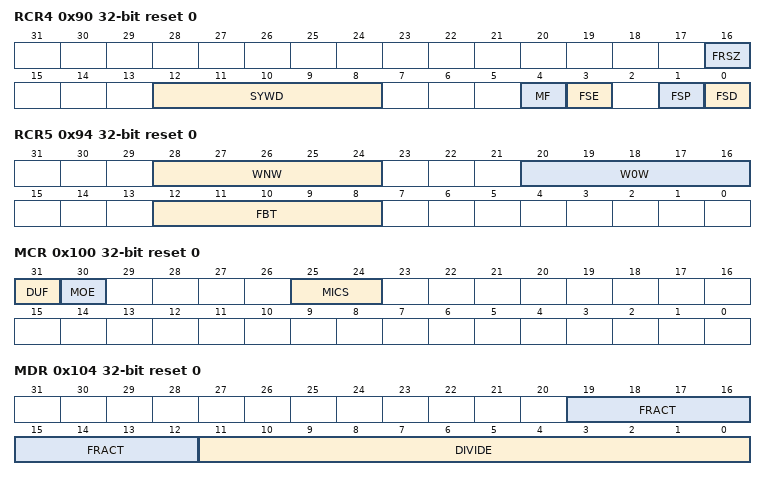
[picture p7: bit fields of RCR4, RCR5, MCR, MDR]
          <name>RCR4</name>
          <description>SAI Receive Configuration 4 Register</description>
          <addressOffset>0x90</addressOffset>
          <size>32</size>
          <access>read-write</access>
          <resetValue>0</resetValue>
          <resetMask>0xFFFFFFFF</resetMask>
          <fields>
            <field>
              <name>FSD</name>
              <description>Frame Sync Direction</description>
              <bitOffset>0</bitOffset>
              <bitWidth>1</bitWidth>
              <access>read-write</access>
              <enumeratedValues>
                <enumeratedValue>
                  <name>0</name>
                  <description>Frame Sync is generated externally in Slave mode.</description>
                  <value>#0</value>
                </enumeratedValue>
                <enumeratedValue>
                  <name>1</name>
                  <description>Frame Sync is generated internally in Master mode.</description>
                  <value>#1</value>
                </enumeratedValue>
              </enumeratedValues>
            </field>
            <field>
              <name>FSP</name>
              <description>Frame Sync Polarity</description>
              <bitOffset>1</bitOffset>
              <bitWidth>1</bitWidth>
              <access>read-write</access>
              <enumeratedValues>
                <enumeratedValue>
                  <name>0</name>
                  <description>Frame sync is active high.</description>
                  <value>#0</value>
                </enumeratedValue>
                <enumeratedValue>
                  <name>1</name>
                  <description>Frame sync is active low.</description>
                  <value>#1</value>
                </enumeratedValue>
              </enumeratedValues>
            </field>
            <field>
              <name>FSE</name>
              <description>Frame Sync Early</description>
              <bitOffset>3</bitOffset>
              <bitWidth>1</bitWidth>
              <access>read-write</access>
              <enumeratedValues>
                <enumeratedValue>
                  <name>0</name>
                  <description>Frame sync asserts with the first bit of the frame.</description>
                  <value>#0</value>
                </enumeratedValue>
                <enumeratedValue>
                  <name>1</name>
                  <description>Frame sync asserts one bit before the first bit of the frame.</description>
                  <value>#1</value>
                </enumeratedValue>
              </enumeratedValues>
            </field>
            <field>
              <name>MF</name>
              <description>MSB First</description>
              <bitOffset>4</bitOffset>
              <bitWidth>1</bitWidth>
              <access>read-write</access>
              <enumeratedValues>
                <enumeratedValue>
                  <name>0</name>
                  <description>LSB is received first.</description>
                  <value>#0</value>
                </enumeratedValue>
                <enumeratedValue>
                  <name>1</name>
                  <description>MSB is received first.</description>
                  <value>#1</value>
                </enumeratedValue>
              </enumeratedValues>
            </field>
            <field>
              <name>SYWD</name>
              <description>Sync Width</description>
              <bitOffset>8</bitOffset>
              <bitWidth>5</bitWidth>
              <access>read-write</access>
            </field>
            <field>
              <name>FRSZ</name>
              <description>Frame Size</description>
              <bitOffset>16</bitOffset>
              <bitWidth>1</bitWidth>
              <access>read-write</access>
            </field>
          </fields>
        </register>
        <register>
          <name>RCR5</name>
          <description>SAI Receive Configuration 5 Register</description>
          <addressOffset>0x94</addressOffset>
          <size>32</size>
          <access>read-write</access>
          <resetValue>0</resetValue>
          <resetMask>0xFFFFFFFF</resetMask>
          <fields>
            <field>
              <name>FBT</name>
              <description>First Bit Shifted</description>
              <bitOffset>8</bitOffset>
              <bitWidth>5</bitWidth>
              <access>read-write</access>
            </field>
            <field>
              <name>W0W</name>
              <description>Word 0 Width</description>
              <bitOffset>16</bitOffset>
              <bitWidth>5</bitWidth>
              <access>read-write</access>
            </field>
            <field>
              <name>WNW</name>
              <description>Word N Width</description>
              <bitOffset>24</bitOffset>
              <bitWidth>5</bitWidth>
              <access>read-write</access>
            </field>
          </fields>
        </register>
        <register>
          <name>RDR</name>
          <description>SAI Receive Data Register</description>
          <addressOffset>0xA0</addressOffset>
          <size>32</size>
          <access>read-only</access>
          <resetValue>0</resetValue>
          <resetMask>0xFFFFFFFF</resetMask>
          <fields>
            <field>
              <name>RDR</name>
              <description>Receive Data Register</description>
              <bitOffset>0</bitOffset>
              <bitWidth>32</bitWidth>
              <access>read-only</access>
            </field>
          </fields>
        </register>
        <register>
          <name>RMR</name>
          <description>SAI Receive Mask Register</description>
          <addressOffset>0xE0</addressOffset>
          <size>32</size>
          <access>read-write</access>
          <resetValue>0</resetValue>
          <resetMask>0xFFFFFFFF</resetMask>
          <fields>
            <field>
              <name>RWM</name>
              <description>Receive Word Mask</description>
              <bitOffset>0</bitOffset>
              <bitWidth>2</bitWidth>
              <access>read-write</access>
              <enumeratedValues>
                <enumeratedValue>
                  <name>0</name>
                  <description>Word N is enabled.</description>
                  <value>#00</value>
                </enumeratedValue>
                <enumeratedValue>
                  <name>1</name>
                  <description>Word N is masked.</description>
                  <value>#01</value>
                </enumeratedValue>
              </enumeratedValues>
            </field>
          </fields>
        </register>
        <register>
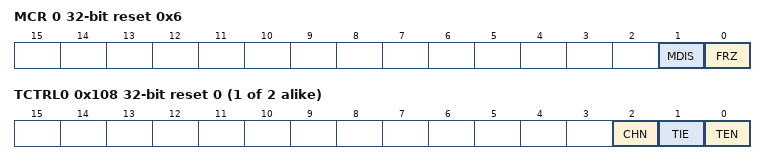
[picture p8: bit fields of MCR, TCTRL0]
          <name>MCR</name>
          <description>SAI MCLK Control Register</description>
          <addressOffset>0x100</addressOffset>
          <size>32</size>
          <access>read-write</access>
          <resetValue>0</resetValue>
          <resetMask>0xFFFFFFFF</resetMask>
          <fields>
            <field>
              <name>MICS</name>
              <description>MCLK Input Clock Select</description>
              <bitOffset>24</bitOffset>
              <bitWidth>2</bitWidth>
              <access>read-write</access>
              <enumeratedValues>
                <enumeratedValue>
                  <name>00</name>
                  <description>MCLK divider input clock 0 selected.</description>
                  <value>#00</value>
                </enumeratedValue>
                <enumeratedValue>
                  <name>01</name>
                  <description>MCLK divider input clock 1 selected.</description>
                  <value>#01</value>
                </enumeratedValue>
                <enumeratedValue>
                  <name>10</name>
                  <description>MCLK divider input clock 2 selected.</description>
                  <value>#10</value>
                </enumeratedValue>
                <enumeratedValue>
                  <name>11</name>
                  <description>MCLK divider input clock 3 selected.</description>
                  <value>#11</value>
                </enumeratedValue>
              </enumeratedValues>
            </field>
            <field>
              <name>MOE</name>
              <description>MCLK Output Enable</description>
              <bitOffset>30</bitOffset>
              <bitWidth>1</bitWidth>
              <access>read-write</access>
              <enumeratedValues>
                <enumeratedValue>
                  <name>0</name>
                  <description>MCLK signal pin is configured as an input that bypasses the MCLK divider.</description>
                  <value>#0</value>
                </enumeratedValue>
                <enumeratedValue>
                  <name>1</name>
                  <description>MCLK signal pin is configured as an output from the MCLK divider and the MCLK divider is enabled.</description>
                  <value>#1</value>
                </enumeratedValue>
              </enumeratedValues>
            </field>
            <field>
              <name>DUF</name>
              <description>Divider Update Flag</description>
              <bitOffset>31</bitOffset>
              <bitWidth>1</bitWidth>
              <access>read-only</access>
              <enumeratedValues>
                <enumeratedValue>
                  <name>0</name>
                  <description>MCLK divider ratio is not being updated currently.</description>
                  <value>#0</value>
                </enumeratedValue>
                <enumeratedValue>
                  <name>1</name>
                  <description>MCLK divider ratio is updating on-the-fly. Further updates to the MCLK divider ratio are blocked while this flag remains set.</description>
                  <value>#1</value>
                </enumeratedValue>
              </enumeratedValues>
            </field>
          </fields>
        </register>
        <register>
          <name>MDR</name>
          <description>SAI MCLK Divide Register</description>
          <addressOffset>0x104</addressOffset>
          <size>32</size>
          <access>read-write</access>
          <resetValue>0</resetValue>
          <resetMask>0xFFFFFFFF</resetMask>
          <fields>
            <field>
              <name>DIVIDE</name>
              <description>MCLK Divide</description>
              <bitOffset>0</bitOffset>
              <bitWidth>12</bitWidth>
              <access>read-write</access>
            </field>
            <field>
              <name>FRACT</name>
              <description>MCLK Fraction</description>
              <bitOffset>12</bitOffset>
              <bitWidth>8</bitWidth>
              <access>read-write</access>
            </field>
          </fields>
        </register>
      </registers>
    </peripheral>
    <peripheral>
      <name>PIT</name>
      <description>Periodic Interrupt Timer</description>
      <prependToName>PIT_</prependToName>
      <baseAddress>0x40037000</baseAddress>
      <addressBlock>
        <offset>0</offset>
        <size>0x120</size>
        <usage>registers</usage>
      </addressBlock>
      <interrupt>
        <name>PIT</name>
        <value>22</value>
      </interrupt>
      <registers>
        <register>
          <name>MCR</name>
          <description>PIT Module Control Register</description>
          <addressOffset>0</addressOffset>
          <size>32</size>
          <access>read-write</access>
          <resetValue>0x6</resetValue>
          <resetMask>0xFFFFFFFF</resetMask>
          <fields>
            <field>
              <name>FRZ</name>
              <description>Freeze</description>
              <bitOffset>0</bitOffset>
              <bitWidth>1</bitWidth>
              <access>read-write</access>
              <enumeratedValues>
                <enumeratedValue>
                  <name>0</name>
                  <description>Timers continue to run in Debug mode.</description>
                  <value>#0</value>
                </enumeratedValue>
                <enumeratedValue>
                  <name>1</name>
                  <description>Timers are stopped in Debug mode.</description>
                  <value>#1</value>
                </enumeratedValue>
              </enumeratedValues>
            </field>
            <field>
              <name>MDIS</name>
              <description>Module Disable - (PIT section)</description>
              <bitOffset>1</bitOffset>
              <bitWidth>1</bitWidth>
              <access>read-write</access>
              <enumeratedValues>
                <enumeratedValue>
                  <name>0</name>
                  <description>Clock for standard PIT timers is enabled.</description>
                  <value>#0</value>
                </enumeratedValue>
                <enumeratedValue>
                  <name>1</name>
                  <description>Clock for standard PIT timers is disabled.</description>
                  <value>#1</value>
                </enumeratedValue>
              </enumeratedValues>
            </field>
          </fields>
        </register>
        <register>
          <name>LTMR64H</name>
          <description>PIT Upper Lifetime Timer Register</description>
          <addressOffset>0xE0</addressOffset>
          <size>32</size>
          <access>read-only</access>
          <resetValue>0</resetValue>
          <resetMask>0xFFFFFFFF</resetMask>
          <fields>
            <field>
              <name>LTH</name>
              <description>Life Timer value</description>
              <bitOffset>0</bitOffset>
              <bitWidth>32</bitWidth>
              <access>read-only</access>
            </field>
          </fields>
        </register>
        <register>
          <name>LTMR64L</name>
          <description>PIT Lower Lifetime Timer Register</description>
          <addressOffset>0xE4</addressOffset>
          <size>32</size>
          <access>read-only</access>
          <resetValue>0</resetValue>
          <resetMask>0xFFFFFFFF</resetMask>
          <fields>
            <field>
              <name>LTL</name>
              <description>Life Timer value</description>
              <bitOffset>0</bitOffset>
              <bitWidth>32</bitWidth>
              <access>read-only</access>
            </field>
          </fields>
        </register>
        <register>
          <dim>2</dim>
          <dimIncrement>0x10</dimIncrement>
          <dimIndex>0,1</dimIndex>
          <name>LDVAL%s</name>
          <description>Timer Load Value Register</description>
          <addressOffset>0x100</addressOffset>
          <size>32</size>
          <access>read-write</access>
          <resetValue>0</resetValue>
          <resetMask>0xFFFFFFFF</resetMask>
          <fields>
            <field>
              <name>TSV</name>
              <description>Timer Start Value</description>
              <bitOffset>0</bitOffset>
              <bitWidth>32</bitWidth>
              <access>read-write</access>
            </field>
          </fields>
        </register>
        <register>
          <dim>2</dim>
          <dimIncrement>0x10</dimIncrement>
          <dimIndex>0,1</dimIndex>
          <name>CVAL%s</name>
          <description>Current Timer Value Register</description>
          <addressOffset>0x104</addressOffset>
          <size>32</size>
          <access>read-only</access>
          <resetValue>0</resetValue>
          <resetMask>0xFFFFFFFF</resetMask>
          <fields>
            <field>
              <name>TVL</name>
              <description>Current Timer Value</description>
              <bitOffset>0</bitOffset>
              <bitWidth>32</bitWidth>
              <access>read-only</access>
            </field>
          </fields>
        </register>
        <register>
          <dim>2</dim>
          <dimIncrement>0x10</dimIncrement>
          <dimIndex>0,1</dimIndex>
          <name>TCTRL%s</name>
          <description>Timer Control Register</description>
          <addressOffset>0x108</addressOffset>
          <size>32</size>
          <access>read-write</access>
          <resetValue>0</resetValue>
          <resetMask>0xFFFFFFFF</resetMask>
          <fields>
            <field>
              <name>TEN</name>
              <description>Timer Enable</description>
              <bitOffset>0</bitOffset>
              <bitWidth>1</bitWidth>
              <access>read-write</access>
              <enumeratedValues>
                <enumeratedValue>
                  <name>0</name>
                  <description>Timer n is disabled.</description>
                  <value>#0</value>
                </enumeratedValue>
                <enumeratedValue>
                  <name>1</name>
                  <description>Timer n is enabled.</description>
                  <value>#1</value>
                </enumeratedValue>
              </enumeratedValues>
            </field>
            <field>
              <name>TIE</name>
              <description>Timer Interrupt Enable</description>
              <bitOffset>1</bitOffset>
              <bitWidth>1</bitWidth>
              <access>read-write</access>
              <enumeratedValues>
                <enumeratedValue>
                  <name>0</name>
                  <description>Interrupt requests from Timer n are disabled.</description>
                  <value>#0</value>
                </enumeratedValue>
                <enumeratedValue>
                  <name>1</name>
                  <description>Interrupt will be requested whenever TIF is set.</description>
                  <value>#1</value>
                </enumeratedValue>
              </enumeratedValues>
            </field>
            <field>
              <name>CHN</name>
              <description>Chain Mode</description>
              <bitOffset>2</bitOffset>
              <bitWidth>1</bitWidth>
              <access>read-write</access>
              <enumeratedValues>
                <enumeratedValue>
                  <name>0</name>
                  <description>Timer is not chained.</description>
                  <value>#0</value>
                </enumeratedValue>
                <enumeratedValue>
                  <name>1</name>
                  <description>Timer is chained to previous timer. For example, for Channel 2, if this field is set, Timer 2 is chained to Timer 1.</description>
                  <value>#1</value>
                </enumeratedValue>
              </enumeratedValues>
            </field>
          </fields>
        </register>
        <register>
          <dim>2</dim>
          <dimIncrement>0x10</dimIncrement>
          <dimIndex>0,1</dimIndex>
          <name>TFLG%s</name>
          <description>Timer Flag Register</description>
          <addressOffset>0x10C</addressOffset>
          <size>32</size>
          <access>read-write</access>
          <resetValue>0</resetValue>
          <resetMask>0xFFFFFFFF</resetMask>
          <fields>
            <field>
              <name>TIF</name>
              <description>Timer Interrupt Flag</description>
              <bitOffset>0</bitOffset>
              <bitWidth>1</bitWidth>
              <access>read-write</access>
              <enumeratedValues>
                <enumeratedValue>
                  <name>0</name>
                  <description>Timeout has not yet occurred.</description>
                  <value>#0</value>
                </enumeratedValue>
                <enumeratedValue>
                  <name>1</name>
                  <description>Timeout has occurred.</description>
                  <value>#1</value>
                </enumeratedValue>
              </enumeratedValues>
            </field>
          </fields>
        </register>
      </registers>
    </peripheral>
    <peripheral>
      <name>TPM0</name>
      <description>Timer/PWM Module</description>
      <groupName>TPM</groupName>
      <prependToName>TPM0_</prependToName>
      <baseAddress>0x40038000</baseAddress>
      <addressBlock>
        <offset>0</offset>
        <size>0x88</size>
        <usage>registers</usage>
      </addressBlock>
      <interrupt>
        <name>TPM0</name>
        <value>17</value>
      </interrupt>
      <registers>
        <register>
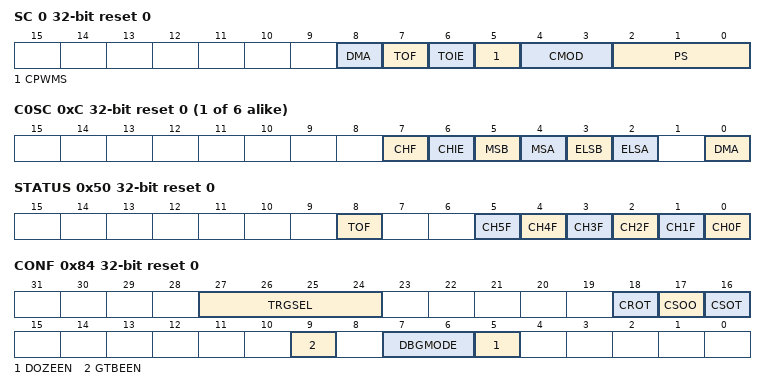
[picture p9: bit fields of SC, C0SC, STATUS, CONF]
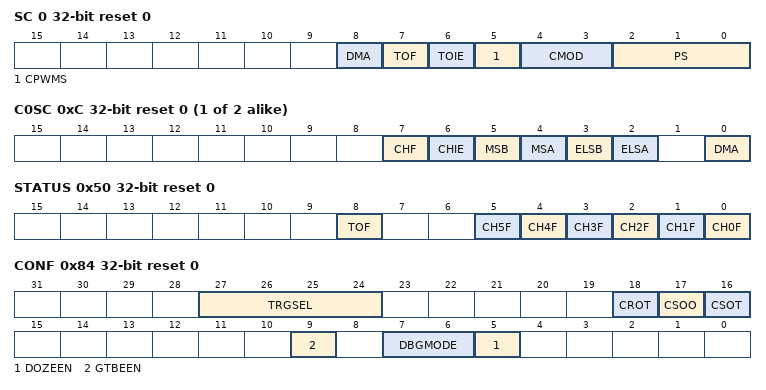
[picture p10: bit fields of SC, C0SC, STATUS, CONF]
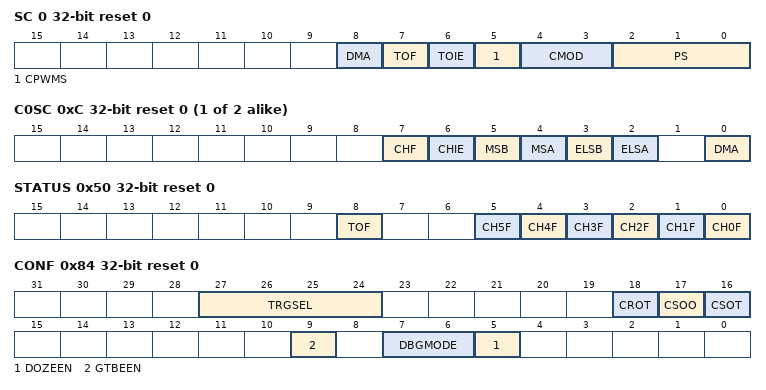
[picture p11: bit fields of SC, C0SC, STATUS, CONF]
          <name>SC</name>
          <description>Status and Control</description>
          <addressOffset>0</addressOffset>
          <size>32</size>
          <access>read-write</access>
          <resetValue>0</resetValue>
          <resetMask>0xFFFFFFFF</resetMask>
          <fields>
            <field>
              <name>PS</name>
              <description>Prescale Factor Selection</description>
              <bitOffset>0</bitOffset>
              <bitWidth>3</bitWidth>
              <access>read-write</access>
              <enumeratedValues>
                <enumeratedValue>
                  <name>000</name>
                  <description>Divide by 1</description>
                  <value>#000</value>
                </enumeratedValue>
                <enumeratedValue>
                  <name>001</name>
                  <description>Divide by 2</description>
                  <value>#001</value>
                </enumeratedValue>
                <enumeratedValue>
                  <name>010</name>
                  <description>Divide by 4</description>
                  <value>#010</value>
                </enumeratedValue>
                <enumeratedValue>
                  <name>011</name>
                  <description>Divide by 8</description>
                  <value>#011</value>
                </enumeratedValue>
                <enumeratedValue>
                  <name>100</name>
                  <description>Divide by 16</description>
                  <value>#100</value>
                </enumeratedValue>
                <enumeratedValue>
                  <name>101</name>
                  <description>Divide by 32</description>
                  <value>#101</value>
                </enumeratedValue>
                <enumeratedValue>
                  <name>110</name>
                  <description>Divide by 64</description>
                  <value>#110</value>
                </enumeratedValue>
                <enumeratedValue>
                  <name>111</name>
                  <description>Divide by 128</description>
                  <value>#111</value>
                </enumeratedValue>
              </enumeratedValues>
            </field>
            <field>
              <name>CMOD</name>
              <description>Clock Mode Selection</description>
              <bitOffset>3</bitOffset>
              <bitWidth>2</bitWidth>
              <access>read-write</access>
              <enumeratedValues>
                <enumeratedValue>
                  <name>00</name>
                  <description>TPM counter is disabled</description>
                  <value>#00</value>
                </enumeratedValue>
                <enumeratedValue>
                  <name>01</name>
                  <description>TPM counter increments on every TPM counter clock</description>
                  <value>#01</value>
                </enumeratedValue>
                <enumeratedValue>
                  <name>10</name>
                  <description>TPM counter increments on rising edge of TPM_EXTCLK synchronized to the TPM counter clock</description>
                  <value>#10</value>
                </enumeratedValue>
              </enumeratedValues>
            </field>
            <field>
              <name>CPWMS</name>
              <description>Center-Aligned PWM Select</description>
              <bitOffset>5</bitOffset>
              <bitWidth>1</bitWidth>
              <access>read-write</access>
              <enumeratedValues>
                <enumeratedValue>
                  <name>0</name>
                  <description>TPM counter operates in up counting mode.</description>
                  <value>#0</value>
                </enumeratedValue>
                <enumeratedValue>
                  <name>1</name>
                  <description>TPM counter operates in up-down counting mode.</description>
                  <value>#1</value>
                </enumeratedValue>
              </enumeratedValues>
            </field>
            <field>
              <name>TOIE</name>
              <description>Timer Overflow Interrupt Enable</description>
              <bitOffset>6</bitOffset>
              <bitWidth>1</bitWidth>
              <access>read-write</access>
              <enumeratedValues>
                <enumeratedValue>
                  <name>0</name>
                  <description>Disable TOF interrupts. Use software polling or DMA request.</description>
                  <value>#0</value>
                </enumeratedValue>
                <enumeratedValue>
                  <name>1</name>
                  <description>Enable TOF interrupts. An interrupt is generated when TOF equals one.</description>
                  <value>#1</value>
                </enumeratedValue>
              </enumeratedValues>
            </field>
            <field>
              <name>TOF</name>
              <description>Timer Overflow Flag</description>
              <bitOffset>7</bitOffset>
              <bitWidth>1</bitWidth>
              <access>read-write</access>
              <enumeratedValues>
                <enumeratedValue>
                  <name>0</name>
                  <description>TPM counter has not overflowed.</description>
                  <value>#0</value>
                </enumeratedValue>
                <enumeratedValue>
                  <name>1</name>
                  <description>TPM counter has overflowed.</description>
                  <value>#1</value>
                </enumeratedValue>
              </enumeratedValues>
            </field>
            <field>
              <name>DMA</name>
              <description>DMA Enable</description>
              <bitOffset>8</bitOffset>
              <bitWidth>1</bitWidth>
              <access>read-write</access>
              <enumeratedValues>
                <enumeratedValue>
                  <name>0</name>
                  <description>Disables DMA transfers.</description>
                  <value>#0</value>
                </enumeratedValue>
                <enumeratedValue>
                  <name>1</name>
                  <description>Enables DMA transfers.</description>
                  <value>#1</value>
                </enumeratedValue>
              </enumeratedValues>
            </field>
          </fields>
        </register>
        <register>
          <name>CNT</name>
          <description>Counter</description>
          <addressOffset>0x4</addressOffset>
          <size>32</size>
          <access>read-write</access>
          <resetValue>0</resetValue>
          <resetMask>0xFFFFFFFF</resetMask>
          <fields>
            <field>
              <name>COUNT</name>
              <description>Counter value</description>
              <bitOffset>0</bitOffset>
              <bitWidth>16</bitWidth>
              <access>read-write</access>
            </field>
          </fields>
        </register>
        <register>
          <name>MOD</name>
          <description>Modulo</description>
          <addressOffset>0x8</addressOffset>
          <size>32</size>
          <access>read-write</access>
          <resetValue>0xFFFF</resetValue>
          <resetMask>0xFFFFFFFF</resetMask>
          <fields>
            <field>
              <name>MOD</name>
              <description>Modulo value</description>
              <bitOffset>0</bitOffset>
              <bitWidth>16</bitWidth>
              <access>read-write</access>
            </field>
          </fields>
        </register>
        <register>
          <dim>6</dim>
          <dimIncrement>0x8</dimIncrement>
          <dimIndex>0,1,2,3,4,5</dimIndex>
          <name>C%sSC</name>
          <description>Channel (n) Status and Control</description>
          <addressOffset>0xC</addressOffset>
          <size>32</size>
          <access>read-write</access>
          <resetValue>0</resetValue>
          <resetMask>0xFFFFFFFF</resetMask>
          <fields>
            <field>
              <name>DMA</name>
              <description>DMA Enable</description>
              <bitOffset>0</bitOffset>
              <bitWidth>1</bitWidth>
              <access>read-write</access>
              <enumeratedValues>
                <enumeratedValue>
                  <name>0</name>
                  <description>Disable DMA transfers.</description>
                  <value>#0</value>
                </enumeratedValue>
                <enumeratedValue>
                  <name>1</name>
                  <description>Enable DMA transfers.</description>
                  <value>#1</value>
                </enumeratedValue>
              </enumeratedValues>
            </field>
            <field>
              <name>ELSA</name>
              <description>Edge or Level Select</description>
              <bitOffset>2</bitOffset>
              <bitWidth>1</bitWidth>
              <access>read-write</access>
            </field>
            <field>
              <name>ELSB</name>
              <description>Edge or Level Select</description>
              <bitOffset>3</bitOffset>
              <bitWidth>1</bitWidth>
              <access>read-write</access>
            </field>
            <field>
              <name>MSA</name>
              <description>Channel Mode Select</description>
              <bitOffset>4</bitOffset>
              <bitWidth>1</bitWidth>
              <access>read-write</access>
            </field>
            <field>
              <name>MSB</name>
              <description>Channel Mode Select</description>
              <bitOffset>5</bitOffset>
              <bitWidth>1</bitWidth>
              <access>read-write</access>
            </field>
            <field>
              <name>CHIE</name>
              <description>Channel Interrupt Enable</description>
              <bitOffset>6</bitOffset>
              <bitWidth>1</bitWidth>
              <access>read-write</access>
              <enumeratedValues>
                <enumeratedValue>
                  <name>0</name>
                  <description>Disable channel interrupts.</description>
                  <value>#0</value>
                </enumeratedValue>
                <enumeratedValue>
                  <name>1</name>
                  <description>Enable channel interrupts.</description>
                  <value>#1</value>
                </enumeratedValue>
              </enumeratedValues>
            </field>
            <field>
              <name>CHF</name>
              <description>Channel Flag</description>
              <bitOffset>7</bitOffset>
              <bitWidth>1</bitWidth>
              <access>read-write</access>
              <enumeratedValues>
                <enumeratedValue>
                  <name>0</name>
                  <description>No channel event has occurred.</description>
                  <value>#0</value>
                </enumeratedValue>
                <enumeratedValue>
                  <name>1</name>
                  <description>A channel event has occurred.</description>
                  <value>#1</value>
                </enumeratedValue>
              </enumeratedValues>
            </field>
          </fields>
        </register>
        <register>
          <dim>6</dim>
          <dimIncrement>0x8</dimIncrement>
          <dimIndex>0,1,2,3,4,5</dimIndex>
          <name>C%sV</name>
          <description>Channel (n) Value</description>
          <addressOffset>0x10</addressOffset>
          <size>32</size>
          <access>read-write</access>
          <resetValue>0</resetValue>
          <resetMask>0xFFFFFFFF</resetMask>
          <fields>
            <field>
              <name>VAL</name>
              <description>Channel Value</description>
              <bitOffset>0</bitOffset>
              <bitWidth>16</bitWidth>
              <access>read-write</access>
            </field>
          </fields>
        </register>
        <register>
          <name>STATUS</name>
          <description>Capture and Compare Status</description>
          <addressOffset>0x50</addressOffset>
          <size>32</size>
          <access>read-write</access>
          <resetValue>0</resetValue>
          <resetMask>0xFFFFFFFF</resetMask>
          <fields>
            <field>
              <name>CH0F</name>
              <description>Channel 0 Flag</description>
              <bitOffset>0</bitOffset>
              <bitWidth>1</bitWidth>
              <access>read-write</access>
              <enumeratedValues>
                <enumeratedValue>
                  <name>0</name>
                  <description>No channel event has occurred.</description>
                  <value>#0</value>
                </enumeratedValue>
                <enumeratedValue>
                  <name>1</name>
                  <description>A channel event has occurred.</description>
                  <value>#1</value>
                </enumeratedValue>
              </enumeratedValues>
            </field>
            <field>
              <name>CH1F</name>
              <description>Channel 1 Flag</description>
              <bitOffset>1</bitOffset>
              <bitWidth>1</bitWidth>
              <access>read-write</access>
              <enumeratedValues>
                <enumeratedValue>
                  <name>0</name>
                  <description>No channel event has occurred.</description>
                  <value>#0</value>
                </enumeratedValue>
                <enumeratedValue>
                  <name>1</name>
                  <description>A channel event has occurred.</description>
                  <value>#1</value>
                </enumeratedValue>
              </enumeratedValues>
            </field>
            <field>
              <name>CH2F</name>
              <description>Channel 2 Flag</description>
              <bitOffset>2</bitOffset>
              <bitWidth>1</bitWidth>
              <access>read-write</access>
              <enumeratedValues>
                <enumeratedValue>
                  <name>0</name>
                  <description>No channel event has occurred.</description>
                  <value>#0</value>
                </enumeratedValue>
                <enumeratedValue>
                  <name>1</name>
                  <description>A channel event has occurred.</description>
                  <value>#1</value>
                </enumeratedValue>
              </enumeratedValues>
            </field>
            <field>
              <name>CH3F</name>
              <description>Channel 3 Flag</description>
              <bitOffset>3</bitOffset>
              <bitWidth>1</bitWidth>
              <access>read-write</access>
              <enumeratedValues>
                <enumeratedValue>
                  <name>0</name>
                  <description>No channel event has occurred.</description>
                  <value>#0</value>
                </enumeratedValue>
                <enumeratedValue>
                  <name>1</name>
                  <description>A channel event has occurred.</description>
                  <value>#1</value>
                </enumeratedValue>
              </enumeratedValues>
            </field>
            <field>
              <name>CH4F</name>
              <description>Channel 4 Flag</description>
              <bitOffset>4</bitOffset>
              <bitWidth>1</bitWidth>
              <access>read-write</access>
              <enumeratedValues>
                <enumeratedValue>
                  <name>0</name>
                  <description>No channel event has occurred.</description>
                  <value>#0</value>
                </enumeratedValue>
                <enumeratedValue>
                  <name>1</name>
                  <description>A channel event has occurred.</description>
                  <value>#1</value>
                </enumeratedValue>
              </enumeratedValues>
            </field>
            <field>
              <name>CH5F</name>
              <description>Channel 5 Flag</description>
              <bitOffset>5</bitOffset>
              <bitWidth>1</bitWidth>
              <access>read-write</access>
              <enumeratedValues>
                <enumeratedValue>
                  <name>0</name>
                  <description>No channel event has occurred.</description>
                  <value>#0</value>
                </enumeratedValue>
                <enumeratedValue>
                  <name>1</name>
                  <description>A channel event has occurred.</description>
                  <value>#1</value>
                </enumeratedValue>
              </enumeratedValues>
            </field>
            <field>
              <name>TOF</name>
              <description>Timer Overflow Flag</description>
              <bitOffset>8</bitOffset>
              <bitWidth>1</bitWidth>
              <access>read-write</access>
              <enumeratedValues>
                <enumeratedValue>
                  <name>0</name>
                  <description>TPM counter has not overflowed.</description>
                  <value>#0</value>
                </enumeratedValue>
                <enumeratedValue>
                  <name>1</name>
                  <description>TPM counter has overflowed.</description>
                  <value>#1</value>
                </enumeratedValue>
              </enumeratedValues>
            </field>
          </fields>
        </register>
        <register>
          <name>CONF</name>
          <description>Configuration</description>
          <addressOffset>0x84</addressOffset>
          <size>32</size>
          <access>read-write</access>
          <resetValue>0</resetValue>
          <resetMask>0xFFFFFFFF</resetMask>
          <fields>
            <field>
              <name>DOZEEN</name>
              <description>Doze Enable</description>
              <bitOffset>5</bitOffset>
              <bitWidth>1</bitWidth>
              <access>read-write</access>
              <enumeratedValues>
                <enumeratedValue>
                  <name>0</name>
                  <description>Internal TPM counter continues in Doze mode.</description>
                  <value>#0</value>
                </enumeratedValue>
                <enumeratedValue>
                  <name>1</name>
                  <description>Internal TPM counter is paused and does not increment during Doze mode. Trigger inputs and input capture events are also ignored.</description>
                  <value>#1</value>
                </enumeratedValue>
              </enumeratedValues>
            </field>
            <field>
              <name>DBGMODE</name>
              <description>Debug Mode</description>
              <bitOffset>6</bitOffset>
              <bitWidth>2</bitWidth>
              <access>read-write</access>
              <enumeratedValues>
                <enumeratedValue>
                  <name>00</name>
                  <description>TPM counter is paused and does not increment during debug mode. Trigger inputs and input capture events are also ignored.</description>
                  <value>#00</value>
                </enumeratedValue>
                <enumeratedValue>
                  <name>11</name>
                  <description>TPM counter continues in debug mode.</description>
                  <value>#11</value>
                </enumeratedValue>
              </enumeratedValues>
            </field>
            <field>
              <name>GTBEEN</name>
              <description>Global time base enable</description>
              <bitOffset>9</bitOffset>
              <bitWidth>1</bitWidth>
              <access>read-write</access>
              <enumeratedValues>
                <enumeratedValue>
                  <name>0</name>
                  <description>All channels use the internally generated TPM counter as their timebase</description>
                  <value>#0</value>
                </enumeratedValue>
                <enumeratedValue>
                  <name>1</name>
                  <description>All channels use an externally generated global timebase as their timebase</description>
                  <value>#1</value>
                </enumeratedValue>
              </enumeratedValues>
            </field>
            <field>
              <name>CSOT</name>
              <description>Counter Start on Trigger</description>
              <bitOffset>16</bitOffset>
              <bitWidth>1</bitWidth>
              <access>read-write</access>
              <enumeratedValues>
                <enumeratedValue>
                  <name>0</name>
                  <description>TPM counter starts to increment immediately, once it is enabled.</description>
                  <value>#0</value>
                </enumeratedValue>
                <enumeratedValue>
                  <name>1</name>
                  <description>TPM counter only starts to increment when it a rising edge on the selected input trigger is detected, after it has been enabled or after it has stopped due to overflow.</description>
                  <value>#1</value>
                </enumeratedValue>
              </enumeratedValues>
            </field>
            <field>
              <name>CSOO</name>
              <description>Counter Stop On Overflow</description>
              <bitOffset>17</bitOffset>
              <bitWidth>1</bitWidth>
              <access>read-write</access>
              <enumeratedValues>
                <enumeratedValue>
                  <name>0</name>
                  <description>TPM counter continues incrementing or decrementing after overflow</description>
                  <value>#0</value>
                </enumeratedValue>
                <enumeratedValue>
                  <name>1</name>
                  <description>TPM counter stops incrementing or decrementing after overflow.</description>
                  <value>#1</value>
                </enumeratedValue>
              </enumeratedValues>
            </field>
            <field>
              <name>CROT</name>
              <description>Counter Reload On Trigger</description>
              <bitOffset>18</bitOffset>
              <bitWidth>1</bitWidth>
              <access>read-write</access>
              <enumeratedValues>
                <enumeratedValue>
                  <name>0</name>
                  <description>Counter is not reloaded due to a rising edge on the selected input trigger</description>
                  <value>#0</value>
                </enumeratedValue>
                <enumeratedValue>
                  <name>1</name>
                  <description>Counter is reloaded when a rising edge is detected on the selected input trigger</description>
                  <value>#1</value>
                </enumeratedValue>
              </enumeratedValues>
            </field>
            <field>
              <name>TRGSEL</name>
              <description>Trigger Select</description>
              <bitOffset>24</bitOffset>
              <bitWidth>4</bitWidth>
              <access>read-write</access>
            </field>
          </fields>
        </register>
      </registers>
    </peripheral>
    <peripheral>
      <name>TPM1</name>
      <description>Timer/PWM Module</description>
      <groupName>TPM</groupName>
      <prependToName>TPM1_</prependToName>
      <baseAddress>0x40039000</baseAddress>
      <addressBlock>
        <offset>0</offset>
        <size>0x88</size>
        <usage>registers</usage>
      </addressBlock>
      <interrupt>
        <name>TPM1</name>
        <value>18</value>
      </interrupt>
      <registers>
        <register>
          <name>SC</name>
          <description>Status and Control</description>
          <addressOffset>0</addressOffset>
          <size>32</size>
          <access>read-write</access>
          <resetValue>0</resetValue>
          <resetMask>0xFFFFFFFF</resetMask>
          <fields>
            <field>
              <name>PS</name>
              <description>Prescale Factor Selection</description>
              <bitOffset>0</bitOffset>
              <bitWidth>3</bitWidth>
              <access>read-write</access>
              <enumeratedValues>
                <enumeratedValue>
                  <name>000</name>
                  <description>Divide by 1</description>
                  <value>#000</value>
                </enumeratedValue>
                <enumeratedValue>
                  <name>001</name>
                  <description>Divide by 2</description>
                  <value>#001</value>
                </enumeratedValue>
                <enumeratedValue>
                  <name>010</name>
                  <description>Divide by 4</description>
                  <value>#010</value>
                </enumeratedValue>
                <enumeratedValue>
                  <name>011</name>
                  <description>Divide by 8</description>
                  <value>#011</value>
                </enumeratedValue>
                <enumeratedValue>
                  <name>100</name>
                  <description>Divide by 16</description>
                  <value>#100</value>
                </enumeratedValue>
                <enumeratedValue>
                  <name>101</name>
                  <description>Divide by 32</description>
                  <value>#101</value>
                </enumeratedValue>
                <enumeratedValue>
                  <name>110</name>
                  <description>Divide by 64</description>
                  <value>#110</value>
                </enumeratedValue>
                <enumeratedValue>
                  <name>111</name>
                  <description>Divide by 128</description>
                  <value>#111</value>
                </enumeratedValue>
              </enumeratedValues>
            </field>
            <field>
              <name>CMOD</name>
              <description>Clock Mode Selection</description>
              <bitOffset>3</bitOffset>
              <bitWidth>2</bitWidth>
              <access>read-write</access>
              <enumeratedValues>
                <enumeratedValue>
                  <name>00</name>
                  <description>TPM counter is disabled</description>
                  <value>#00</value>
                </enumeratedValue>
                <enumeratedValue>
                  <name>01</name>
                  <description>TPM counter increments on every TPM counter clock</description>
                  <value>#01</value>
                </enumeratedValue>
                <enumeratedValue>
                  <name>10</name>
                  <description>TPM counter increments on rising edge of TPM_EXTCLK synchronized to the TPM counter clock</description>
                  <value>#10</value>
                </enumeratedValue>
              </enumeratedValues>
            </field>
            <field>
              <name>CPWMS</name>
              <description>Center-Aligned PWM Select</description>
              <bitOffset>5</bitOffset>
              <bitWidth>1</bitWidth>
              <access>read-write</access>
              <enumeratedValues>
                <enumeratedValue>
                  <name>0</name>
                  <description>TPM counter operates in up counting mode.</description>
                  <value>#0</value>
                </enumeratedValue>
                <enumeratedValue>
                  <name>1</name>
                  <description>TPM counter operates in up-down counting mode.</description>
                  <value>#1</value>
                </enumeratedValue>
              </enumeratedValues>
            </field>
            <field>
              <name>TOIE</name>
              <description>Timer Overflow Interrupt Enable</description>
              <bitOffset>6</bitOffset>
              <bitWidth>1</bitWidth>
              <access>read-write</access>
              <enumeratedValues>
                <enumeratedValue>
                  <name>0</name>
                  <description>Disable TOF interrupts. Use software polling or DMA request.</description>
                  <value>#0</value>
                </enumeratedValue>
                <enumeratedValue>
                  <name>1</name>
                  <description>Enable TOF interrupts. An interrupt is generated when TOF equals one.</description>
                  <value>#1</value>
                </enumeratedValue>
              </enumeratedValues>
            </field>
            <field>
              <name>TOF</name>
              <description>Timer Overflow Flag</description>
              <bitOffset>7</bitOffset>
              <bitWidth>1</bitWidth>
              <access>read-write</access>
              <enumeratedValues>
                <enumeratedValue>
                  <name>0</name>
                  <description>TPM counter has not overflowed.</description>
                  <value>#0</value>
                </enumeratedValue>
                <enumeratedValue>
                  <name>1</name>
                  <description>TPM counter has overflowed.</description>
                  <value>#1</value>
                </enumeratedValue>
              </enumeratedValues>
            </field>
            <field>
              <name>DMA</name>
              <description>DMA Enable</description>
              <bitOffset>8</bitOffset>
              <bitWidth>1</bitWidth>
              <access>read-write</access>
              <enumeratedValues>
                <enumeratedValue>
                  <name>0</name>
                  <description>Disables DMA transfers.</description>
                  <value>#0</value>
                </enumeratedValue>
                <enumeratedValue>
                  <name>1</name>
                  <description>Enables DMA transfers.</description>
                  <value>#1</value>
                </enumeratedValue>
              </enumeratedValues>
            </field>
          </fields>
        </register>
        <register>
          <name>CNT</name>
          <description>Counter</description>
          <addressOffset>0x4</addressOffset>
          <size>32</size>
          <access>read-write</access>
          <resetValue>0</resetValue>
          <resetMask>0xFFFFFFFF</resetMask>
          <fields>
            <field>
              <name>COUNT</name>
              <description>Counter value</description>
              <bitOffset>0</bitOffset>
              <bitWidth>16</bitWidth>
              <access>read-write</access>
            </field>
          </fields>
        </register>
        <register>
          <name>MOD</name>
          <description>Modulo</description>
          <addressOffset>0x8</addressOffset>
          <size>32</size>
          <access>read-write</access>
          <resetValue>0xFFFF</resetValue>
          <resetMask>0xFFFFFFFF</resetMask>
          <fields>
            <field>
              <name>MOD</name>
              <description>Modulo value</description>
              <bitOffset>0</bitOffset>
              <bitWidth>16</bitWidth>
              <access>read-write</access>
            </field>
          </fields>
        </register>
        <register>
          <dim>2</dim>
          <dimIncrement>0x8</dimIncrement>
          <dimIndex>0,1</dimIndex>
          <name>C%sSC</name>
          <description>Channel (n) Status and Control</description>
          <addressOffset>0xC</addressOffset>
          <size>32</size>
          <access>read-write</access>
          <resetValue>0</resetValue>
          <resetMask>0xFFFFFFFF</resetMask>
          <fields>
            <field>
              <name>DMA</name>
              <description>DMA Enable</description>
              <bitOffset>0</bitOffset>
              <bitWidth>1</bitWidth>
              <access>read-write</access>
              <enumeratedValues>
                <enumeratedValue>
                  <name>0</name>
                  <description>Disable DMA transfers.</description>
                  <value>#0</value>
                </enumeratedValue>
                <enumeratedValue>
                  <name>1</name>
                  <description>Enable DMA transfers.</description>
                  <value>#1</value>
                </enumeratedValue>
              </enumeratedValues>
            </field>
            <field>
              <name>ELSA</name>
              <description>Edge or Level Select</description>
              <bitOffset>2</bitOffset>
              <bitWidth>1</bitWidth>
              <access>read-write</access>
            </field>
            <field>
              <name>ELSB</name>
              <description>Edge or Level Select</description>
              <bitOffset>3</bitOffset>
              <bitWidth>1</bitWidth>
              <access>read-write</access>
            </field>
            <field>
              <name>MSA</name>
              <description>Channel Mode Select</description>
              <bitOffset>4</bitOffset>
              <bitWidth>1</bitWidth>
              <access>read-write</access>
            </field>
            <field>
              <name>MSB</name>
              <description>Channel Mode Select</description>
              <bitOffset>5</bitOffset>
              <bitWidth>1</bitWidth>
              <access>read-write</access>
            </field>
            <field>
              <name>CHIE</name>
              <description>Channel Interrupt Enable</description>
              <bitOffset>6</bitOffset>
              <bitWidth>1</bitWidth>
              <access>read-write</access>
              <enumeratedValues>
                <enumeratedValue>
                  <name>0</name>
                  <description>Disable channel interrupts.</description>
                  <value>#0</value>
                </enumeratedValue>
                <enumeratedValue>
                  <name>1</name>
                  <description>Enable channel interrupts.</description>
                  <value>#1</value>
                </enumeratedValue>
              </enumeratedValues>
            </field>
            <field>
              <name>CHF</name>
              <description>Channel Flag</description>
              <bitOffset>7</bitOffset>
              <bitWidth>1</bitWidth>
              <access>read-write</access>
              <enumeratedValues>
                <enumeratedValue>
                  <name>0</name>
                  <description>No channel event has occurred.</description>
                  <value>#0</value>
                </enumeratedValue>
                <enumeratedValue>
                  <name>1</name>
                  <description>A channel event has occurred.</description>
                  <value>#1</value>
                </enumeratedValue>
              </enumeratedValues>
            </field>
          </fields>
        </register>
        <register>
          <dim>2</dim>
          <dimIncrement>0x8</dimIncrement>
          <dimIndex>0,1</dimIndex>
          <name>C%sV</name>
          <description>Channel (n) Value</description>
          <addressOffset>0x10</addressOffset>
          <size>32</size>
          <access>read-write</access>
          <resetValue>0</resetValue>
          <resetMask>0xFFFFFFFF</resetMask>
          <fields>
            <field>
              <name>VAL</name>
              <description>Channel Value</description>
              <bitOffset>0</bitOffset>
              <bitWidth>16</bitWidth>
              <access>read-write</access>
            </field>
          </fields>
        </register>
        <register>
          <name>STATUS</name>
          <description>Capture and Compare Status</description>
          <addressOffset>0x50</addressOffset>
          <size>32</size>
          <access>read-write</access>
          <resetValue>0</resetValue>
          <resetMask>0xFFFFFFFF</resetMask>
          <fields>
            <field>
              <name>CH0F</name>
              <description>Channel 0 Flag</description>
              <bitOffset>0</bitOffset>
              <bitWidth>1</bitWidth>
              <access>read-write</access>
              <enumeratedValues>
                <enumeratedValue>
                  <name>0</name>
                  <description>No channel event has occurred.</description>
                  <value>#0</value>
                </enumeratedValue>
                <enumeratedValue>
                  <name>1</name>
                  <description>A channel event has occurred.</description>
                  <value>#1</value>
                </enumeratedValue>
              </enumeratedValues>
            </field>
            <field>
              <name>CH1F</name>
              <description>Channel 1 Flag</description>
              <bitOffset>1</bitOffset>
              <bitWidth>1</bitWidth>
              <access>read-write</access>
              <enumeratedValues>
                <enumeratedValue>
                  <name>0</name>
                  <description>No channel event has occurred.</description>
                  <value>#0</value>
                </enumeratedValue>
                <enumeratedValue>
                  <name>1</name>
                  <description>A channel event has occurred.</description>
                  <value>#1</value>
                </enumeratedValue>
              </enumeratedValues>
            </field>
            <field>
              <name>CH2F</name>
              <description>Channel 2 Flag</description>
              <bitOffset>2</bitOffset>
              <bitWidth>1</bitWidth>
              <access>read-write</access>
              <enumeratedValues>
                <enumeratedValue>
                  <name>0</name>
                  <description>No channel event has occurred.</description>
                  <value>#0</value>
                </enumeratedValue>
                <enumeratedValue>
                  <name>1</name>
                  <description>A channel event has occurred.</description>
                  <value>#1</value>
                </enumeratedValue>
              </enumeratedValues>
            </field>
            <field>
              <name>CH3F</name>
              <description>Channel 3 Flag</description>
              <bitOffset>3</bitOffset>
              <bitWidth>1</bitWidth>
              <access>read-write</access>
              <enumeratedValues>
                <enumeratedValue>
                  <name>0</name>
                  <description>No channel event has occurred.</description>
                  <value>#0</value>
                </enumeratedValue>
                <enumeratedValue>
                  <name>1</name>
                  <description>A channel event has occurred.</description>
                  <value>#1</value>
                </enumeratedValue>
              </enumeratedValues>
            </field>
            <field>
              <name>CH4F</name>
              <description>Channel 4 Flag</description>
              <bitOffset>4</bitOffset>
              <bitWidth>1</bitWidth>
              <access>read-write</access>
              <enumeratedValues>
                <enumeratedValue>
                  <name>0</name>
                  <description>No channel event has occurred.</description>
                  <value>#0</value>
                </enumeratedValue>
                <enumeratedValue>
                  <name>1</name>
                  <description>A channel event has occurred.</description>
                  <value>#1</value>
                </enumeratedValue>
              </enumeratedValues>
            </field>
            <field>
              <name>CH5F</name>
              <description>Channel 5 Flag</description>
              <bitOffset>5</bitOffset>
              <bitWidth>1</bitWidth>
              <access>read-write</access>
              <enumeratedValues>
                <enumeratedValue>
                  <name>0</name>
                  <description>No channel event has occurred.</description>
                  <value>#0</value>
                </enumeratedValue>
                <enumeratedValue>
                  <name>1</name>
                  <description>A channel event has occurred.</description>
                  <value>#1</value>
                </enumeratedValue>
              </enumeratedValues>
            </field>
            <field>
              <name>TOF</name>
              <description>Timer Overflow Flag</description>
              <bitOffset>8</bitOffset>
              <bitWidth>1</bitWidth>
              <access>read-write</access>
              <enumeratedValues>
                <enumeratedValue>
                  <name>0</name>
                  <description>TPM counter has not overflowed.</description>
                  <value>#0</value>
                </enumeratedValue>
                <enumeratedValue>
                  <name>1</name>
                  <description>TPM counter has overflowed.</description>
                  <value>#1</value>
                </enumeratedValue>
              </enumeratedValues>
            </field>
          </fields>
        </register>
        <register>
          <name>CONF</name>
          <description>Configuration</description>
          <addressOffset>0x84</addressOffset>
          <size>32</size>
          <access>read-write</access>
          <resetValue>0</resetValue>
          <resetMask>0xFFFFFFFF</resetMask>
          <fields>
            <field>
              <name>DOZEEN</name>
              <description>Doze Enable</description>
              <bitOffset>5</bitOffset>
              <bitWidth>1</bitWidth>
              <access>read-write</access>
              <enumeratedValues>
                <enumeratedValue>
                  <name>0</name>
                  <description>Internal TPM counter continues in Doze mode.</description>
                  <value>#0</value>
                </enumeratedValue>
                <enumeratedValue>
                  <name>1</name>
                  <description>Internal TPM counter is paused and does not increment during Doze mode. Trigger inputs and input capture events are also ignored.</description>
                  <value>#1</value>
                </enumeratedValue>
              </enumeratedValues>
            </field>
            <field>
              <name>DBGMODE</name>
              <description>Debug Mode</description>
              <bitOffset>6</bitOffset>
              <bitWidth>2</bitWidth>
              <access>read-write</access>
              <enumeratedValues>
                <enumeratedValue>
                  <name>00</name>
                  <description>TPM counter is paused and does not increment during debug mode. Trigger inputs and input capture events are also ignored.</description>
                  <value>#00</value>
                </enumeratedValue>
                <enumeratedValue>
                  <name>11</name>
                  <description>TPM counter continues in debug mode.</description>
                  <value>#11</value>
                </enumeratedValue>
              </enumeratedValues>
            </field>
            <field>
              <name>GTBEEN</name>
              <description>Global time base enable</description>
              <bitOffset>9</bitOffset>
              <bitWidth>1</bitWidth>
              <access>read-write</access>
              <enumeratedValues>
                <enumeratedValue>
                  <name>0</name>
                  <description>All channels use the internally generated TPM counter as their timebase</description>
                  <value>#0</value>
                </enumeratedValue>
                <enumeratedValue>
                  <name>1</name>
                  <description>All channels use an externally generated global timebase as their timebase</description>
                  <value>#1</value>
                </enumeratedValue>
              </enumeratedValues>
            </field>
            <field>
              <name>CSOT</name>
              <description>Counter Start on Trigger</description>
              <bitOffset>16</bitOffset>
              <bitWidth>1</bitWidth>
              <access>read-write</access>
              <enumeratedValues>
                <enumeratedValue>
                  <name>0</name>
                  <description>TPM counter starts to increment immediately, once it is enabled.</description>
                  <value>#0</value>
                </enumeratedValue>
                <enumeratedValue>
                  <name>1</name>
                  <description>TPM counter only starts to increment when it a rising edge on the selected input trigger is detected, after it has been enabled or after it has stopped due to overflow.</description>
                  <value>#1</value>
                </enumeratedValue>
              </enumeratedValues>
            </field>
            <field>
              <name>CSOO</name>
              <description>Counter Stop On Overflow</description>
              <bitOffset>17</bitOffset>
              <bitWidth>1</bitWidth>
              <access>read-write</access>
              <enumeratedValues>
                <enumeratedValue>
                  <name>0</name>
                  <description>TPM counter continues incrementing or decrementing after overflow</description>
                  <value>#0</value>
                </enumeratedValue>
                <enumeratedValue>
                  <name>1</name>
                  <description>TPM counter stops incrementing or decrementing after overflow.</description>
                  <value>#1</value>
                </enumeratedValue>
              </enumeratedValues>
            </field>
            <field>
              <name>CROT</name>
              <description>Counter Reload On Trigger</description>
              <bitOffset>18</bitOffset>
              <bitWidth>1</bitWidth>
              <access>read-write</access>
              <enumeratedValues>
                <enumeratedValue>
                  <name>0</name>
                  <description>Counter is not reloaded due to a rising edge on the selected input trigger</description>
                  <value>#0</value>
                </enumeratedValue>
                <enumeratedValue>
                  <name>1</name>
                  <description>Counter is reloaded when a rising edge is detected on the selected input trigger</description>
                  <value>#1</value>
                </enumeratedValue>
              </enumeratedValues>
            </field>
            <field>
              <name>TRGSEL</name>
              <description>Trigger Select</description>
              <bitOffset>24</bitOffset>
              <bitWidth>4</bitWidth>
              <access>read-write</access>
            </field>
          </fields>
        </register>
      </registers>
    </peripheral>
    <peripheral>
      <name>TPM2</name>
      <description>Timer/PWM Module</description>
      <groupName>TPM</groupName>
      <prependToName>TPM2_</prependToName>
      <baseAddress>0x4003A000</baseAddress>
      <addressBlock>
        <offset>0</offset>
        <size>0x88</size>
        <usage>registers</usage>
      </addressBlock>
      <interrupt>
        <name>TPM2</name>
        <value>19</value>
      </interrupt>
      <registers>
        <register>
          <name>SC</name>
          <description>Status and Control</description>
          <addressOffset>0</addressOffset>
          <size>32</size>
          <access>read-write</access>
          <resetValue>0</resetValue>
          <resetMask>0xFFFFFFFF</resetMask>
          <fields>
            <field>
              <name>PS</name>
              <description>Prescale Factor Selection</description>
              <bitOffset>0</bitOffset>
              <bitWidth>3</bitWidth>
              <access>read-write</access>
              <enumeratedValues>
                <enumeratedValue>
                  <name>000</name>
                  <description>Divide by 1</description>
                  <value>#000</value>
                </enumeratedValue>
                <enumeratedValue>
                  <name>001</name>
                  <description>Divide by 2</description>
                  <value>#001</value>
                </enumeratedValue>
                <enumeratedValue>
                  <name>010</name>
                  <description>Divide by 4</description>
                  <value>#010</value>
                </enumeratedValue>
                <enumeratedValue>
                  <name>011</name>
                  <description>Divide by 8</description>
                  <value>#011</value>
                </enumeratedValue>
                <enumeratedValue>
                  <name>100</name>
                  <description>Divide by 16</description>
                  <value>#100</value>
                </enumeratedValue>
                <enumeratedValue>
                  <name>101</name>
                  <description>Divide by 32</description>
                  <value>#101</value>
                </enumeratedValue>
                <enumeratedValue>
                  <name>110</name>
                  <description>Divide by 64</description>
                  <value>#110</value>
                </enumeratedValue>
                <enumeratedValue>
                  <name>111</name>
                  <description>Divide by 128</description>
                  <value>#111</value>
                </enumeratedValue>
              </enumeratedValues>
            </field>
            <field>
              <name>CMOD</name>
              <description>Clock Mode Selection</description>
              <bitOffset>3</bitOffset>
              <bitWidth>2</bitWidth>
              <access>read-write</access>
              <enumeratedValues>
                <enumeratedValue>
                  <name>00</name>
                  <description>TPM counter is disabled</description>
                  <value>#00</value>
                </enumeratedValue>
                <enumeratedValue>
                  <name>01</name>
                  <description>TPM counter increments on every TPM counter clock</description>
                  <value>#01</value>
                </enumeratedValue>
                <enumeratedValue>
                  <name>10</name>
                  <description>TPM counter increments on rising edge of TPM_EXTCLK synchronized to the TPM counter clock</description>
                  <value>#10</value>
                </enumeratedValue>
              </enumeratedValues>
            </field>
            <field>
              <name>CPWMS</name>
              <description>Center-Aligned PWM Select</description>
              <bitOffset>5</bitOffset>
              <bitWidth>1</bitWidth>
              <access>read-write</access>
              <enumeratedValues>
                <enumeratedValue>
                  <name>0</name>
                  <description>TPM counter operates in up counting mode.</description>
                  <value>#0</value>
                </enumeratedValue>
                <enumeratedValue>
                  <name>1</name>
                  <description>TPM counter operates in up-down counting mode.</description>
                  <value>#1</value>
                </enumeratedValue>
              </enumeratedValues>
            </field>
            <field>
              <name>TOIE</name>
              <description>Timer Overflow Interrupt Enable</description>
              <bitOffset>6</bitOffset>
              <bitWidth>1</bitWidth>
              <access>read-write</access>
              <enumeratedValues>
                <enumeratedValue>
                  <name>0</name>
                  <description>Disable TOF interrupts. Use software polling or DMA request.</description>
                  <value>#0</value>
                </enumeratedValue>
                <enumeratedValue>
                  <name>1</name>
                  <description>Enable TOF interrupts. An interrupt is generated when TOF equals one.</description>
                  <value>#1</value>
                </enumeratedValue>
              </enumeratedValues>
            </field>
            <field>
              <name>TOF</name>
              <description>Timer Overflow Flag</description>
              <bitOffset>7</bitOffset>
              <bitWidth>1</bitWidth>
              <access>read-write</access>
              <enumeratedValues>
                <enumeratedValue>
                  <name>0</name>
                  <description>TPM counter has not overflowed.</description>
                  <value>#0</value>
                </enumeratedValue>
                <enumeratedValue>
                  <name>1</name>
                  <description>TPM counter has overflowed.</description>
                  <value>#1</value>
                </enumeratedValue>
              </enumeratedValues>
            </field>
            <field>
              <name>DMA</name>
              <description>DMA Enable</description>
              <bitOffset>8</bitOffset>
              <bitWidth>1</bitWidth>
              <access>read-write</access>
              <enumeratedValues>
                <enumeratedValue>
                  <name>0</name>
                  <description>Disables DMA transfers.</description>
                  <value>#0</value>
                </enumeratedValue>
                <enumeratedValue>
                  <name>1</name>
                  <description>Enables DMA transfers.</description>
                  <value>#1</value>
                </enumeratedValue>
              </enumeratedValues>
            </field>
          </fields>
        </register>
        <register>
          <name>CNT</name>
          <description>Counter</description>
          <addressOffset>0x4</addressOffset>
          <size>32</size>
          <access>read-write</access>
          <resetValue>0</resetValue>
          <resetMask>0xFFFFFFFF</resetMask>
          <fields>
            <field>
              <name>COUNT</name>
              <description>Counter value</description>
              <bitOffset>0</bitOffset>
              <bitWidth>16</bitWidth>
              <access>read-write</access>
            </field>
          </fields>
        </register>
        <register>
          <name>MOD</name>
          <description>Modulo</description>
          <addressOffset>0x8</addressOffset>
          <size>32</size>
          <access>read-write</access>
          <resetValue>0xFFFF</resetValue>
          <resetMask>0xFFFFFFFF</resetMask>
          <fields>
            <field>
              <name>MOD</name>
              <description>Modulo value</description>
              <bitOffset>0</bitOffset>
              <bitWidth>16</bitWidth>
              <access>read-write</access>
            </field>
          </fields>
        </register>
        <register>
          <dim>2</dim>
          <dimIncrement>0x8</dimIncrement>
          <dimIndex>0,1</dimIndex>
          <name>C%sSC</name>
          <description>Channel (n) Status and Control</description>
          <addressOffset>0xC</addressOffset>
          <size>32</size>
          <access>read-write</access>
          <resetValue>0</resetValue>
          <resetMask>0xFFFFFFFF</resetMask>
          <fields>
            <field>
              <name>DMA</name>
              <description>DMA Enable</description>
              <bitOffset>0</bitOffset>
              <bitWidth>1</bitWidth>
              <access>read-write</access>
              <enumeratedValues>
                <enumeratedValue>
                  <name>0</name>
                  <description>Disable DMA transfers.</description>
                  <value>#0</value>
                </enumeratedValue>
                <enumeratedValue>
                  <name>1</name>
                  <description>Enable DMA transfers.</description>
                  <value>#1</value>
                </enumeratedValue>
              </enumeratedValues>
            </field>
            <field>
              <name>ELSA</name>
              <description>Edge or Level Select</description>
              <bitOffset>2</bitOffset>
              <bitWidth>1</bitWidth>
              <access>read-write</access>
            </field>
            <field>
              <name>ELSB</name>
              <description>Edge or Level Select</description>
              <bitOffset>3</bitOffset>
              <bitWidth>1</bitWidth>
              <access>read-write</access>
            </field>
            <field>
              <name>MSA</name>
              <description>Channel Mode Select</description>
              <bitOffset>4</bitOffset>
              <bitWidth>1</bitWidth>
              <access>read-write</access>
            </field>
            <field>
              <name>MSB</name>
              <description>Channel Mode Select</description>
              <bitOffset>5</bitOffset>
              <bitWidth>1</bitWidth>
              <access>read-write</access>
            </field>
            <field>
              <name>CHIE</name>
              <description>Channel Interrupt Enable</description>
              <bitOffset>6</bitOffset>
              <bitWidth>1</bitWidth>
              <access>read-write</access>
              <enumeratedValues>
                <enumeratedValue>
                  <name>0</name>
                  <description>Disable channel interrupts.</description>
                  <value>#0</value>
                </enumeratedValue>
                <enumeratedValue>
                  <name>1</name>
                  <description>Enable channel interrupts.</description>
                  <value>#1</value>
                </enumeratedValue>
              </enumeratedValues>
            </field>
            <field>
              <name>CHF</name>
              <description>Channel Flag</description>
              <bitOffset>7</bitOffset>
              <bitWidth>1</bitWidth>
              <access>read-write</access>
              <enumeratedValues>
                <enumeratedValue>
                  <name>0</name>
                  <description>No channel event has occurred.</description>
                  <value>#0</value>
                </enumeratedValue>
                <enumeratedValue>
                  <name>1</name>
                  <description>A channel event has occurred.</description>
                  <value>#1</value>
                </enumeratedValue>
              </enumeratedValues>
            </field>
          </fields>
        </register>
        <register>
          <dim>2</dim>
          <dimIncrement>0x8</dimIncrement>
          <dimIndex>0,1</dimIndex>
          <name>C%sV</name>
          <description>Channel (n) Value</description>
          <addressOffset>0x10</addressOffset>
          <size>32</size>
          <access>read-write</access>
          <resetValue>0</resetValue>
          <resetMask>0xFFFFFFFF</resetMask>
          <fields>
            <field>
              <name>VAL</name>
              <description>Channel Value</description>
              <bitOffset>0</bitOffset>
              <bitWidth>16</bitWidth>
              <access>read-write</access>
            </field>
          </fields>
        </register>
        <register>
          <name>STATUS</name>
          <description>Capture and Compare Status</description>
          <addressOffset>0x50</addressOffset>
          <size>32</size>
          <access>read-write</access>
          <resetValue>0</resetValue>
          <resetMask>0xFFFFFFFF</resetMask>
          <fields>
            <field>
              <name>CH0F</name>
              <description>Channel 0 Flag</description>
              <bitOffset>0</bitOffset>
              <bitWidth>1</bitWidth>
              <access>read-write</access>
              <enumeratedValues>
                <enumeratedValue>
                  <name>0</name>
                  <description>No channel event has occurred.</description>
                  <value>#0</value>
                </enumeratedValue>
                <enumeratedValue>
                  <name>1</name>
                  <description>A channel event has occurred.</description>
                  <value>#1</value>
                </enumeratedValue>
              </enumeratedValues>
            </field>
            <field>
              <name>CH1F</name>
              <description>Channel 1 Flag</description>
              <bitOffset>1</bitOffset>
              <bitWidth>1</bitWidth>
              <access>read-write</access>
              <enumeratedValues>
                <enumeratedValue>
                  <name>0</name>
                  <description>No channel event has occurred.</description>
                  <value>#0</value>
                </enumeratedValue>
                <enumeratedValue>
                  <name>1</name>
                  <description>A channel event has occurred.</description>
                  <value>#1</value>
                </enumeratedValue>
              </enumeratedValues>
            </field>
            <field>
              <name>CH2F</name>
              <description>Channel 2 Flag</description>
              <bitOffset>2</bitOffset>
              <bitWidth>1</bitWidth>
              <access>read-write</access>
              <enumeratedValues>
                <enumeratedValue>
                  <name>0</name>
                  <description>No channel event has occurred.</description>
                  <value>#0</value>
                </enumeratedValue>
                <enumeratedValue>
                  <name>1</name>
                  <description>A channel event has occurred.</description>
                  <value>#1</value>
                </enumeratedValue>
              </enumeratedValues>
            </field>
            <field>
              <name>CH3F</name>
              <description>Channel 3 Flag</description>
              <bitOffset>3</bitOffset>
              <bitWidth>1</bitWidth>
              <access>read-write</access>
              <enumeratedValues>
                <enumeratedValue>
                  <name>0</name>
                  <description>No channel event has occurred.</description>
                  <value>#0</value>
                </enumeratedValue>
                <enumeratedValue>
                  <name>1</name>
                  <description>A channel event has occurred.</description>
                  <value>#1</value>
                </enumeratedValue>
              </enumeratedValues>
            </field>
            <field>
              <name>CH4F</name>
              <description>Channel 4 Flag</description>
              <bitOffset>4</bitOffset>
              <bitWidth>1</bitWidth>
              <access>read-write</access>
              <enumeratedValues>
                <enumeratedValue>
                  <name>0</name>
                  <description>No channel event has occurred.</description>
                  <value>#0</value>
                </enumeratedValue>
                <enumeratedValue>
                  <name>1</name>
                  <description>A channel event has occurred.</description>
                  <value>#1</value>
                </enumeratedValue>
              </enumeratedValues>
            </field>
            <field>
              <name>CH5F</name>
              <description>Channel 5 Flag</description>
              <bitOffset>5</bitOffset>
              <bitWidth>1</bitWidth>
              <access>read-write</access>
              <enumeratedValues>
                <enumeratedValue>
                  <name>0</name>
                  <description>No channel event has occurred.</description>
                  <value>#0</value>
                </enumeratedValue>
                <enumeratedValue>
                  <name>1</name>
                  <description>A channel event has occurred.</description>
                  <value>#1</value>
                </enumeratedValue>
              </enumeratedValues>
            </field>
            <field>
              <name>TOF</name>
              <description>Timer Overflow Flag</description>
              <bitOffset>8</bitOffset>
              <bitWidth>1</bitWidth>
              <access>read-write</access>
              <enumeratedValues>
                <enumeratedValue>
                  <name>0</name>
                  <description>TPM counter has not overflowed.</description>
                  <value>#0</value>
                </enumeratedValue>
                <enumeratedValue>
                  <name>1</name>
                  <description>TPM counter has overflowed.</description>
                  <value>#1</value>
                </enumeratedValue>
              </enumeratedValues>
            </field>
          </fields>
        </register>
        <register>
          <name>CONF</name>
          <description>Configuration</description>
          <addressOffset>0x84</addressOffset>
          <size>32</size>
          <access>read-write</access>
          <resetValue>0</resetValue>
          <resetMask>0xFFFFFFFF</resetMask>
          <fields>
            <field>
              <name>DOZEEN</name>
              <description>Doze Enable</description>
              <bitOffset>5</bitOffset>
              <bitWidth>1</bitWidth>
              <access>read-write</access>
              <enumeratedValues>
                <enumeratedValue>
                  <name>0</name>
                  <description>Internal TPM counter continues in Doze mode.</description>
                  <value>#0</value>
                </enumeratedValue>
                <enumeratedValue>
                  <name>1</name>
                  <description>Internal TPM counter is paused and does not increment during Doze mode. Trigger inputs and input capture events are also ignored.</description>
                  <value>#1</value>
                </enumeratedValue>
              </enumeratedValues>
            </field>
            <field>
              <name>DBGMODE</name>
              <description>Debug Mode</description>
              <bitOffset>6</bitOffset>
              <bitWidth>2</bitWidth>
              <access>read-write</access>
              <enumeratedValues>
                <enumeratedValue>
                  <name>00</name>
                  <description>TPM counter is paused and does not increment during debug mode. Trigger inputs and input capture events are also ignored.</description>
                  <value>#00</value>
                </enumeratedValue>
                <enumeratedValue>
                  <name>11</name>
                  <description>TPM counter continues in debug mode.</description>
                  <value>#11</value>
                </enumeratedValue>
              </enumeratedValues>
            </field>
            <field>
              <name>GTBEEN</name>
              <description>Global time base enable</description>
              <bitOffset>9</bitOffset>
              <bitWidth>1</bitWidth>
              <access>read-write</access>
              <enumeratedValues>
                <enumeratedValue>
                  <name>0</name>
                  <description>All channels use the internally generated TPM counter as their timebase</description>
                  <value>#0</value>
                </enumeratedValue>
                <enumeratedValue>
                  <name>1</name>
                  <description>All channels use an externally generated global timebase as their timebase</description>
                  <value>#1</value>
                </enumeratedValue>
              </enumeratedValues>
            </field>
            <field>
              <name>CSOT</name>
              <description>Counter Start on Trigger</description>
              <bitOffset>16</bitOffset>
              <bitWidth>1</bitWidth>
              <access>read-write</access>
              <enumeratedValues>
                <enumeratedValue>
                  <name>0</name>
                  <description>TPM counter starts to increment immediately, once it is enabled.</description>
                  <value>#0</value>
                </enumeratedValue>
                <enumeratedValue>
                  <name>1</name>
                  <description>TPM counter only starts to increment when it a rising edge on the selected input trigger is detected, after it has been enabled or after it has stopped due to overflow.</description>
                  <value>#1</value>
                </enumeratedValue>
              </enumeratedValues>
            </field>
            <field>
              <name>CSOO</name>
              <description>Counter Stop On Overflow</description>
              <bitOffset>17</bitOffset>
              <bitWidth>1</bitWidth>
              <access>read-write</access>
              <enumeratedValues>
                <enumeratedValue>
                  <name>0</name>
                  <description>TPM counter continues incrementing or decrementing after overflow</description>
                  <value>#0</value>
                </enumeratedValue>
                <enumeratedValue>
                  <name>1</name>
                  <description>TPM counter stops incrementing or decrementing after overflow.</description>
                  <value>#1</value>
                </enumeratedValue>
              </enumeratedValues>
            </field>
            <field>
              <name>CROT</name>
              <description>Counter Reload On Trigger</description>
              <bitOffset>18</bitOffset>
              <bitWidth>1</bitWidth>
              <access>read-write</access>
              <enumeratedValues>
                <enumeratedValue>
                  <name>0</name>
                  <description>Counter is not reloaded due to a rising edge on the selected input trigger</description>
                  <value>#0</value>
                </enumeratedValue>
                <enumeratedValue>
                  <name>1</name>
                  <description>Counter is reloaded when a rising edge is detected on the selected input trigger</description>
                  <value>#1</value>
                </enumeratedValue>
              </enumeratedValues>
            </field>
            <field>
              <name>TRGSEL</name>
              <description>Trigger Select</description>
              <bitOffset>24</bitOffset>
              <bitWidth>4</bitWidth>
              <access>read-write</access>
            </field>
          </fields>
        </register>
      </registers>
    </peripheral>
    <peripheral>
      <name>ADC0</name>
      <description>Analog-to-Digital Converter</description>
      <prependToName>ADC0_</prependToName>
      <baseAddress>0x4003B000</baseAddress>
      <addressBlock>
        <offset>0</offset>
        <size>0x70</size>
        <usage>registers</usage>
      </addressBlock>
      <interrupt>
        <name>ADC0</name>
        <value>15</value>
      </interrupt>
      <registers>
        <register>
          <dim>2</dim>
          <dimIncrement>0x4</dimIncrement>
          <dimIndex>A,B</dimIndex>
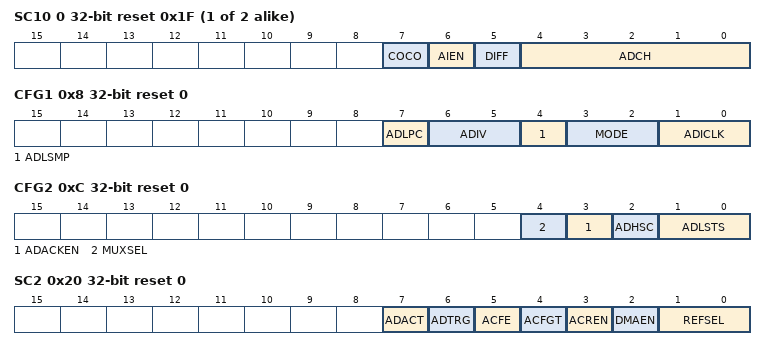
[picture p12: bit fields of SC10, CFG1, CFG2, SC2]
          <name>SC1%s</name>
          <description>ADC Status and Control Registers 1</description>
          <addressOffset>0</addressOffset>
          <size>32</size>
          <access>read-write</access>
          <resetValue>0x1F</resetValue>
          <resetMask>0xFFFFFFFF</resetMask>
          <fields>
            <field>
              <name>ADCH</name>
              <description>Input channel select</description>
              <bitOffset>0</bitOffset>
              <bitWidth>5</bitWidth>
              <access>read-write</access>
              <enumeratedValues>
                <enumeratedValue>
                  <name>00000</name>
                  <description>When DIFF=0, DADP0 is selected as input; when DIFF=1, DAD0 is selected as input.</description>
                  <value>#00000</value>
                </enumeratedValue>
                <enumeratedValue>
                  <name>00001</name>
                  <description>When DIFF=0, DADP1 is selected as input; when DIFF=1, DAD1 is selected as input.</description>
                  <value>#00001</value>
                </enumeratedValue>
                <enumeratedValue>
                  <name>00010</name>
                  <description>When DIFF=0, DADP2 is selected as input; when DIFF=1, DAD2 is selected as input.</description>
                  <value>#00010</value>
                </enumeratedValue>
                <enumeratedValue>
                  <name>00011</name>
                  <description>When DIFF=0, DADP3 is selected as input; when DIFF=1, DAD3 is selected as input.</description>
                  <value>#00011</value>
                </enumeratedValue>
                <enumeratedValue>
                  <name>00100</name>
                  <description>When DIFF=0, AD4 is selected as input; when DIFF=1, it is reserved.</description>
                  <value>#00100</value>
                </enumeratedValue>
                <enumeratedValue>
                  <name>00101</name>
                  <description>When DIFF=0, AD5 is selected as input; when DIFF=1, it is reserved.</description>
                  <value>#00101</value>
                </enumeratedValue>
                <enumeratedValue>
                  <name>00110</name>
                  <description>When DIFF=0, AD6 is selected as input; when DIFF=1, it is reserved.</description>
                  <value>#00110</value>
                </enumeratedValue>
                <enumeratedValue>
                  <name>00111</name>
                  <description>When DIFF=0, AD7 is selected as input; when DIFF=1, it is reserved.</description>
                  <value>#00111</value>
                </enumeratedValue>
                <enumeratedValue>
                  <name>01000</name>
                  <description>When DIFF=0, AD8 is selected as input; when DIFF=1, it is reserved.</description>
                  <value>#01000</value>
                </enumeratedValue>
                <enumeratedValue>
                  <name>01001</name>
                  <description>When DIFF=0, AD9 is selected as input; when DIFF=1, it is reserved.</description>
                  <value>#01001</value>
                </enumeratedValue>
                <enumeratedValue>
                  <name>01010</name>
                  <description>When DIFF=0, AD10 is selected as input; when DIFF=1, it is reserved.</description>
                  <value>#01010</value>
                </enumeratedValue>
                <enumeratedValue>
                  <name>01011</name>
                  <description>When DIFF=0, AD11 is selected as input; when DIFF=1, it is reserved.</description>
                  <value>#01011</value>
                </enumeratedValue>
                <enumeratedValue>
                  <name>01100</name>
                  <description>When DIFF=0, AD12 is selected as input; when DIFF=1, it is reserved.</description>
                  <value>#01100</value>
                </enumeratedValue>
                <enumeratedValue>
                  <name>01101</name>
                  <description>When DIFF=0, AD13 is selected as input; when DIFF=1, it is reserved.</description>
                  <value>#01101</value>
                </enumeratedValue>
                <enumeratedValue>
                  <name>01110</name>
                  <description>When DIFF=0, AD14 is selected as input; when DIFF=1, it is reserved.</description>
                  <value>#01110</value>
                </enumeratedValue>
                <enumeratedValue>
                  <name>01111</name>
                  <description>When DIFF=0, AD15 is selected as input; when DIFF=1, it is reserved.</description>
                  <value>#01111</value>
                </enumeratedValue>
                <enumeratedValue>
                  <name>10000</name>
                  <description>When DIFF=0, AD16 is selected as input; when DIFF=1, it is reserved.</description>
                  <value>#10000</value>
                </enumeratedValue>
                <enumeratedValue>
                  <name>10001</name>
                  <description>When DIFF=0, AD17 is selected as input; when DIFF=1, it is reserved.</description>
                  <value>#10001</value>
                </enumeratedValue>
                <enumeratedValue>
                  <name>10010</name>
                  <description>When DIFF=0, AD18 is selected as input; when DIFF=1, it is reserved.</description>
                  <value>#10010</value>
                </enumeratedValue>
                <enumeratedValue>
                  <name>10011</name>
                  <description>When DIFF=0, AD19 is selected as input; when DIFF=1, it is reserved.</description>
                  <value>#10011</value>
                </enumeratedValue>
                <enumeratedValue>
                  <name>10100</name>
                  <description>When DIFF=0, AD20 is selected as input; when DIFF=1, it is reserved.</description>
                  <value>#10100</value>
                </enumeratedValue>
                <enumeratedValue>
                  <name>10101</name>
                  <description>When DIFF=0, AD21 is selected as input; when DIFF=1, it is reserved.</description>
                  <value>#10101</value>
                </enumeratedValue>
                <enumeratedValue>
                  <name>10110</name>
                  <description>When DIFF=0, AD22 is selected as input; when DIFF=1, it is reserved.</description>
                  <value>#10110</value>
                </enumeratedValue>
                <enumeratedValue>
                  <name>10111</name>
                  <description>When DIFF=0, AD23 is selected as input; when DIFF=1, it is reserved.</description>
                  <value>#10111</value>
                </enumeratedValue>
                <enumeratedValue>
                  <name>11010</name>
                  <description>When DIFF=0, Temp Sensor (single-ended) is selected as input; when DIFF=1, Temp Sensor (differential) is selected as input.</description>
                  <value>#11010</value>
                </enumeratedValue>
                <enumeratedValue>
                  <name>11011</name>
                  <description>When DIFF=0, Bandgap (single-ended) is selected as input; when DIFF=1, Bandgap (differential) is selected as input.</description>
                  <value>#11011</value>
                </enumeratedValue>
                <enumeratedValue>
                  <name>11101</name>
                  <description>When DIFF=0,VREFSH is selected as input; when DIFF=1, -VREFSH (differential) is selected as input. Voltage reference selected is determined by SC2[REFSEL].</description>
                  <value>#11101</value>
                </enumeratedValue>
                <enumeratedValue>
                  <name>11110</name>
                  <description>When DIFF=0,VREFSL is selected as input; when DIFF=1, it is reserved. Voltage reference selected is determined by SC2[REFSEL].</description>
                  <value>#11110</value>
                </enumeratedValue>
                <enumeratedValue>
                  <name>11111</name>
                  <description>Module is disabled.</description>
                  <value>#11111</value>
                </enumeratedValue>
              </enumeratedValues>
            </field>
            <field>
              <name>DIFF</name>
              <description>Differential Mode Enable</description>
              <bitOffset>5</bitOffset>
              <bitWidth>1</bitWidth>
              <access>read-write</access>
              <enumeratedValues>
                <enumeratedValue>
                  <name>0</name>
                  <description>Single-ended conversions and input channels are selected.</description>
                  <value>#0</value>
                </enumeratedValue>
                <enumeratedValue>
                  <name>1</name>
                  <description>Differential conversions and input channels are selected.</description>
                  <value>#1</value>
                </enumeratedValue>
              </enumeratedValues>
            </field>
            <field>
              <name>AIEN</name>
              <description>Interrupt Enable</description>
              <bitOffset>6</bitOffset>
              <bitWidth>1</bitWidth>
              <access>read-write</access>
              <enumeratedValues>
                <enumeratedValue>
                  <name>0</name>
                  <description>Conversion complete interrupt is disabled.</description>
                  <value>#0</value>
                </enumeratedValue>
                <enumeratedValue>
                  <name>1</name>
                  <description>Conversion complete interrupt is enabled.</description>
                  <value>#1</value>
                </enumeratedValue>
              </enumeratedValues>
            </field>
            <field>
              <name>COCO</name>
              <description>Conversion Complete Flag</description>
              <bitOffset>7</bitOffset>
              <bitWidth>1</bitWidth>
              <access>read-only</access>
              <enumeratedValues>
                <enumeratedValue>
                  <name>0</name>
                  <description>Conversion is not completed.</description>
                  <value>#0</value>
                </enumeratedValue>
                <enumeratedValue>
                  <name>1</name>
                  <description>Conversion is completed.</description>
                  <value>#1</value>
                </enumeratedValue>
              </enumeratedValues>
            </field>
          </fields>
        </register>
        <register>
          <name>CFG1</name>
          <description>ADC Configuration Register 1</description>
          <addressOffset>0x8</addressOffset>
          <size>32</size>
          <access>read-write</access>
          <resetValue>0</resetValue>
          <resetMask>0xFFFFFFFF</resetMask>
          <fields>
            <field>
              <name>ADICLK</name>
              <description>Input Clock Select</description>
              <bitOffset>0</bitOffset>
              <bitWidth>2</bitWidth>
              <access>read-write</access>
              <enumeratedValues>
                <enumeratedValue>
                  <name>00</name>
                  <description>Bus clock</description>
                  <value>#00</value>
                </enumeratedValue>
                <enumeratedValue>
                  <name>01</name>
                  <description>Alternate clock 2 (ALTCLK2)</description>
                  <value>#01</value>
                </enumeratedValue>
                <enumeratedValue>
                  <name>10</name>
                  <description>Alternate clock (ALTCLK)</description>
                  <value>#10</value>
                </enumeratedValue>
                <enumeratedValue>
                  <name>11</name>
                  <description>Asynchronous clock (ADACK)</description>
                  <value>#11</value>
                </enumeratedValue>
              </enumeratedValues>
            </field>
            <field>
              <name>MODE</name>
              <description>Conversion mode selection</description>
              <bitOffset>2</bitOffset>
              <bitWidth>2</bitWidth>
              <access>read-write</access>
              <enumeratedValues>
                <enumeratedValue>
                  <name>00</name>
                  <description>When DIFF=0:It is single-ended 8-bit conversion; when DIFF=1, it is differential 9-bit conversion with 2&apos;s complement output.</description>
                  <value>#00</value>
                </enumeratedValue>
                <enumeratedValue>
                  <name>01</name>
                  <description>When DIFF=0:It is single-ended 12-bit conversion ; when DIFF=1, it is differential 13-bit conversion with 2&apos;s complement output.</description>
                  <value>#01</value>
                </enumeratedValue>
                <enumeratedValue>
                  <name>10</name>
                  <description>When DIFF=0:It is single-ended 10-bit conversion. ; when DIFF=1, it is differential 11-bit conversion with 2&apos;s complement output</description>
                  <value>#10</value>
                </enumeratedValue>
                <enumeratedValue>
                  <name>11</name>
                  <description>When DIFF=0:It is single-ended 16-bit conversion..; when DIFF=1, it is differential 16-bit conversion with 2&apos;s complement output</description>
                  <value>#11</value>
                </enumeratedValue>
              </enumeratedValues>
            </field>
            <field>
              <name>ADLSMP</name>
              <description>Sample Time Configuration</description>
              <bitOffset>4</bitOffset>
              <bitWidth>1</bitWidth>
              <access>read-write</access>
              <enumeratedValues>
                <enumeratedValue>
                  <name>0</name>
                  <description>Short sample time.</description>
                  <value>#0</value>
                </enumeratedValue>
                <enumeratedValue>
                  <name>1</name>
                  <description>Long sample time.</description>
                  <value>#1</value>
                </enumeratedValue>
              </enumeratedValues>
            </field>
            <field>
              <name>ADIV</name>
              <description>Clock Divide Select</description>
              <bitOffset>5</bitOffset>
              <bitWidth>2</bitWidth>
              <access>read-write</access>
              <enumeratedValues>
                <enumeratedValue>
                  <name>00</name>
                  <description>The divide ratio is 1 and the clock rate is input clock.</description>
                  <value>#00</value>
                </enumeratedValue>
                <enumeratedValue>
                  <name>01</name>
                  <description>The divide ratio is 2 and the clock rate is (input clock)/2.</description>
                  <value>#01</value>
                </enumeratedValue>
                <enumeratedValue>
                  <name>10</name>
                  <description>The divide ratio is 4 and the clock rate is (input clock)/4.</description>
                  <value>#10</value>
                </enumeratedValue>
                <enumeratedValue>
                  <name>11</name>
                  <description>The divide ratio is 8 and the clock rate is (input clock)/8.</description>
                  <value>#11</value>
                </enumeratedValue>
              </enumeratedValues>
            </field>
            <field>
              <name>ADLPC</name>
              <description>Low-Power Configuration</description>
              <bitOffset>7</bitOffset>
              <bitWidth>1</bitWidth>
              <access>read-write</access>
              <enumeratedValues>
                <enumeratedValue>
                  <name>0</name>
                  <description>Normal power configuration.</description>
                  <value>#0</value>
                </enumeratedValue>
                <enumeratedValue>
                  <name>1</name>
                  <description>Low-power configuration. The power is reduced at the expense of maximum clock speed.</description>
                  <value>#1</value>
                </enumeratedValue>
              </enumeratedValues>
            </field>
          </fields>
        </register>
        <register>
          <name>CFG2</name>
          <description>ADC Configuration Register 2</description>
          <addressOffset>0xC</addressOffset>
          <size>32</size>
          <access>read-write</access>
          <resetValue>0</resetValue>
          <resetMask>0xFFFFFFFF</resetMask>
          <fields>
            <field>
              <name>ADLSTS</name>
              <description>Long Sample Time Select</description>
              <bitOffset>0</bitOffset>
              <bitWidth>2</bitWidth>
              <access>read-write</access>
              <enumeratedValues>
                <enumeratedValue>
                  <name>00</name>
                  <description>Default longest sample time; 20 extra ADCK cycles; 24 ADCK cycles total.</description>
                  <value>#00</value>
                </enumeratedValue>
                <enumeratedValue>
                  <name>01</name>
                  <description>12 extra ADCK cycles; 16 ADCK cycles total sample time.</description>
                  <value>#01</value>
                </enumeratedValue>
                <enumeratedValue>
                  <name>10</name>
                  <description>6 extra ADCK cycles; 10 ADCK cycles total sample time.</description>
                  <value>#10</value>
                </enumeratedValue>
                <enumeratedValue>
                  <name>11</name>
                  <description>2 extra ADCK cycles; 6 ADCK cycles total sample time.</description>
                  <value>#11</value>
                </enumeratedValue>
              </enumeratedValues>
            </field>
            <field>
              <name>ADHSC</name>
              <description>High-Speed Configuration</description>
              <bitOffset>2</bitOffset>
              <bitWidth>1</bitWidth>
              <access>read-write</access>
              <enumeratedValues>
                <enumeratedValue>
                  <name>0</name>
                  <description>Normal conversion sequence selected.</description>
                  <value>#0</value>
                </enumeratedValue>
                <enumeratedValue>
                  <name>1</name>
                  <description>High-speed conversion sequence selected with 2 additional ADCK cycles to total conversion time.</description>
                  <value>#1</value>
                </enumeratedValue>
              </enumeratedValues>
            </field>
            <field>
              <name>ADACKEN</name>
              <description>Asynchronous Clock Output Enable</description>
              <bitOffset>3</bitOffset>
              <bitWidth>1</bitWidth>
              <access>read-write</access>
              <enumeratedValues>
                <enumeratedValue>
                  <name>0</name>
                  <description>Asynchronous clock output disabled; Asynchronous clock is enabled only if selected by ADICLK and a conversion is active.</description>
                  <value>#0</value>
                </enumeratedValue>
                <enumeratedValue>
                  <name>1</name>
                  <description>Asynchronous clock and clock output is enabled regardless of the state of the ADC.</description>
                  <value>#1</value>
                </enumeratedValue>
              </enumeratedValues>
            </field>
            <field>
              <name>MUXSEL</name>
              <description>ADC Mux Select</description>
              <bitOffset>4</bitOffset>
              <bitWidth>1</bitWidth>
              <access>read-write</access>
              <enumeratedValues>
                <enumeratedValue>
                  <name>0</name>
                  <description>ADxxa channels are selected.</description>
                  <value>#0</value>
                </enumeratedValue>
                <enumeratedValue>
                  <name>1</name>
                  <description>ADxxb channels are selected.</description>
                  <value>#1</value>
                </enumeratedValue>
              </enumeratedValues>
            </field>
          </fields>
        </register>
        <register>
          <dim>2</dim>
          <dimIncrement>0x4</dimIncrement>
          <dimIndex>A,B</dimIndex>
          <name>R%s</name>
          <description>ADC Data Result Register</description>
          <addressOffset>0x10</addressOffset>
          <size>32</size>
          <access>read-only</access>
          <resetValue>0</resetValue>
          <resetMask>0xFFFFFFFF</resetMask>
          <fields>
            <field>
              <name>D</name>
              <description>Data result</description>
              <bitOffset>0</bitOffset>
              <bitWidth>16</bitWidth>
              <access>read-only</access>
            </field>
          </fields>
        </register>
        <register>
          <dim>2</dim>
          <dimIncrement>0x4</dimIncrement>
          <dimIndex>1,2</dimIndex>
          <name>CV%s</name>
          <description>Compare Value Registers</description>
          <addressOffset>0x18</addressOffset>
          <size>32</size>
          <access>read-write</access>
          <resetValue>0</resetValue>
          <resetMask>0xFFFFFFFF</resetMask>
          <fields>
            <field>
              <name>CV</name>
              <description>Compare Value.</description>
              <bitOffset>0</bitOffset>
              <bitWidth>16</bitWidth>
              <access>read-write</access>
            </field>
          </fields>
        </register>
        <register>
          <name>SC2</name>
          <description>Status and Control Register 2</description>
          <addressOffset>0x20</addressOffset>
          <size>32</size>
          <access>read-write</access>
          <resetValue>0</resetValue>
          <resetMask>0xFFFFFFFF</resetMask>
          <fields>
            <field>
              <name>REFSEL</name>
              <description>Voltage Reference Selection</description>
              <bitOffset>0</bitOffset>
              <bitWidth>2</bitWidth>
              <access>read-write</access>
              <enumeratedValues>
                <enumeratedValue>
                  <name>00</name>
                  <description>Default voltage reference pin pair, that is, external pins VREFH and VREFL</description>
                  <value>#00</value>
                </enumeratedValue>
                <enumeratedValue>
                  <name>01</name>
                  <description>Alternate reference pair, that is, VALTH and VALTL . This pair may be additional external pins or internal sources depending on the MCU configuration. See the chip configuration information for details specific to this MCU</description>
                  <value>#01</value>
                </enumeratedValue>
              </enumeratedValues>
            </field>
            <field>
              <name>DMAEN</name>
              <description>DMA Enable</description>
              <bitOffset>2</bitOffset>
              <bitWidth>1</bitWidth>
              <access>read-write</access>
              <enumeratedValues>
                <enumeratedValue>
                  <name>0</name>
                  <description>DMA is disabled.</description>
                  <value>#0</value>
                </enumeratedValue>
                <enumeratedValue>
                  <name>1</name>
                  <description>DMA is enabled and will assert the ADC DMA request during an ADC conversion complete event noted when any of the SC1n[COCO] flags is asserted.</description>
                  <value>#1</value>
                </enumeratedValue>
              </enumeratedValues>
            </field>
            <field>
              <name>ACREN</name>
              <description>Compare Function Range Enable</description>
              <bitOffset>3</bitOffset>
              <bitWidth>1</bitWidth>
              <access>read-write</access>
              <enumeratedValues>
                <enumeratedValue>
                  <name>0</name>
                  <description>Range function disabled. Only CV1 is compared.</description>
                  <value>#0</value>
                </enumeratedValue>
                <enumeratedValue>
                  <name>1</name>
                  <description>Range function enabled. Both CV1 and CV2 are compared.</description>
                  <value>#1</value>
                </enumeratedValue>
              </enumeratedValues>
            </field>
            <field>
              <name>ACFGT</name>
              <description>Compare Function Greater Than Enable</description>
              <bitOffset>4</bitOffset>
              <bitWidth>1</bitWidth>
              <access>read-write</access>
              <enumeratedValues>
                <enumeratedValue>
                  <name>0</name>
                  <description>Configures less than threshold, outside range not inclusive and inside range not inclusive; functionality based on the values placed in CV1 and CV2.</description>
                  <value>#0</value>
                </enumeratedValue>
                <enumeratedValue>
                  <name>1</name>
                  <description>Configures greater than or equal to threshold, outside and inside ranges inclusive; functionality based on the values placed in CV1 and CV2.</description>
                  <value>#1</value>
                </enumeratedValue>
              </enumeratedValues>
            </field>
            <field>
              <name>ACFE</name>
              <description>Compare Function Enable</description>
              <bitOffset>5</bitOffset>
              <bitWidth>1</bitWidth>
              <access>read-write</access>
              <enumeratedValues>
                <enumeratedValue>
                  <name>0</name>
                  <description>Compare function disabled.</description>
                  <value>#0</value>
                </enumeratedValue>
                <enumeratedValue>
                  <name>1</name>
                  <description>Compare function enabled.</description>
                  <value>#1</value>
                </enumeratedValue>
              </enumeratedValues>
            </field>
            <field>
              <name>ADTRG</name>
              <description>Conversion Trigger Select</description>
              <bitOffset>6</bitOffset>
              <bitWidth>1</bitWidth>
              <access>read-write</access>
              <enumeratedValues>
                <enumeratedValue>
                  <name>0</name>
                  <description>Software trigger selected.</description>
                  <value>#0</value>
                </enumeratedValue>
                <enumeratedValue>
                  <name>1</name>
                  <description>Hardware trigger selected.</description>
                  <value>#1</value>
                </enumeratedValue>
              </enumeratedValues>
            </field>
            <field>
              <name>ADACT</name>
              <description>Conversion Active</description>
              <bitOffset>7</bitOffset>
              <bitWidth>1</bitWidth>
              <access>read-only</access>
              <enumeratedValues>
                <enumeratedValue>
                  <name>0</name>
                  <description>Conversion not in progress.</description>
                  <value>#0</value>
                </enumeratedValue>
                <enumeratedValue>
                  <name>1</name>
                  <description>Conversion in progress.</description>
                  <value>#1</value>
                </enumeratedValue>
              </enumeratedValues>
            </field>
          </fields>
        </register>
        <register>
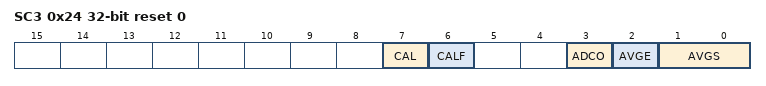
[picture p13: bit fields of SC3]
          <name>SC3</name>
          <description>Status and Control Register 3</description>
          <addressOffset>0x24</addressOffset>
          <size>32</size>
          <access>read-write</access>
          <resetValue>0</resetValue>
          <resetMask>0xFFFFFFFF</resetMask>
          <fields>
            <field>
              <name>AVGS</name>
              <description>Hardware Average Select</description>
              <bitOffset>0</bitOffset>
              <bitWidth>2</bitWidth>
              <access>read-write</access>
              <enumeratedValues>
                <enumeratedValue>
                  <name>00</name>
                  <description>4 samples averaged.</description>
                  <value>#00</value>
                </enumeratedValue>
                <enumeratedValue>
                  <name>01</name>
                  <description>8 samples averaged.</description>
                  <value>#01</value>
                </enumeratedValue>
                <enumeratedValue>
                  <name>10</name>
                  <description>16 samples averaged.</description>
                  <value>#10</value>
                </enumeratedValue>
                <enumeratedValue>
                  <name>11</name>
                  <description>32 samples averaged.</description>
                  <value>#11</value>
                </enumeratedValue>
              </enumeratedValues>
            </field>
            <field>
              <name>AVGE</name>
              <description>Hardware Average Enable</description>
              <bitOffset>2</bitOffset>
              <bitWidth>1</bitWidth>
              <access>read-write</access>
              <enumeratedValues>
                <enumeratedValue>
                  <name>0</name>
                  <description>Hardware average function disabled.</description>
                  <value>#0</value>
                </enumeratedValue>
                <enumeratedValue>
                  <name>1</name>
                  <description>Hardware average function enabled.</description>
                  <value>#1</value>
                </enumeratedValue>
              </enumeratedValues>
            </field>
            <field>
              <name>ADCO</name>
              <description>Continuous Conversion Enable</description>
              <bitOffset>3</bitOffset>
              <bitWidth>1</bitWidth>
              <access>read-write</access>
              <enumeratedValues>
                <enumeratedValue>
                  <name>0</name>
                  <description>One conversion or one set of conversions if the hardware average function is enabled, that is, AVGE=1, after initiating a conversion.</description>
                  <value>#0</value>
                </enumeratedValue>
                <enumeratedValue>
                  <name>1</name>
                  <description>Continuous conversions or sets of conversions if the hardware average function is enabled, that is, AVGE=1, after initiating a conversion.</description>
                  <value>#1</value>
                </enumeratedValue>
              </enumeratedValues>
            </field>
            <field>
              <name>CALF</name>
              <description>Calibration Failed Flag</description>
              <bitOffset>6</bitOffset>
              <bitWidth>1</bitWidth>
              <access>read-write</access>
              <enumeratedValues>
                <enumeratedValue>
                  <name>0</name>
                  <description>Calibration completed normally.</description>
                  <value>#0</value>
                </enumeratedValue>
                <enumeratedValue>
                  <name>1</name>
                  <description>Calibration failed. ADC accuracy specifications are not guaranteed.</description>
                  <value>#1</value>
                </enumeratedValue>
              </enumeratedValues>
            </field>
            <field>
              <name>CAL</name>
              <description>Calibration</description>
              <bitOffset>7</bitOffset>
              <bitWidth>1</bitWidth>
              <access>read-write</access>
            </field>
          </fields>
        </register>
        <register>
          <name>OFS</name>
          <description>ADC Offset Correction Register</description>
          <addressOffset>0x28</addressOffset>
          <size>32</size>
          <access>read-write</access>
          <resetValue>0x4</resetValue>
          <resetMask>0xFFFFFFFF</resetMask>
          <fields>
            <field>
              <name>OFS</name>
              <description>Offset Error Correction Value</description>
              <bitOffset>0</bitOffset>
              <bitWidth>16</bitWidth>
              <access>read-write</access>
            </field>
          </fields>
        </register>
        <register>
          <name>PG</name>
          <description>ADC Plus-Side Gain Register</description>
          <addressOffset>0x2C</addressOffset>
          <size>32</size>
          <access>read-write</access>
          <resetValue>0x8200</resetValue>
          <resetMask>0xFFFFFFFF</resetMask>
          <fields>
            <field>
              <name>PG</name>
              <description>Plus-Side Gain</description>
              <bitOffset>0</bitOffset>
              <bitWidth>16</bitWidth>
              <access>read-write</access>
            </field>
          </fields>
        </register>
        <register>
          <name>MG</name>
          <description>ADC Minus-Side Gain Register</description>
          <addressOffset>0x30</addressOffset>
          <size>32</size>
          <access>read-write</access>
          <resetValue>0x8200</resetValue>
          <resetMask>0xFFFFFFFF</resetMask>
          <fields>
            <field>
              <name>MG</name>
              <description>Minus-Side Gain</description>
              <bitOffset>0</bitOffset>
              <bitWidth>16</bitWidth>
              <access>read-write</access>
            </field>
          </fields>
        </register>
        <register>
          <name>CLPD</name>
          <description>ADC Plus-Side General Calibration Value Register</description>
          <addressOffset>0x34</addressOffset>
          <size>32</size>
          <access>read-write</access>
          <resetValue>0xA</resetValue>
          <resetMask>0xFFFFFFFF</resetMask>
          <fields>
            <field>
              <name>CLPD</name>
              <description>Calibration Value</description>
              <bitOffset>0</bitOffset>
              <bitWidth>6</bitWidth>
              <access>read-write</access>
            </field>
          </fields>
        </register>
        <register>
          <name>CLPS</name>
          <description>ADC Plus-Side General Calibration Value Register</description>
          <addressOffset>0x38</addressOffset>
          <size>32</size>
          <access>read-write</access>
          <resetValue>0x20</resetValue>
          <resetMask>0xFFFFFFFF</resetMask>
          <fields>
            <field>
              <name>CLPS</name>
              <description>Calibration Value</description>
              <bitOffset>0</bitOffset>
              <bitWidth>6</bitWidth>
              <access>read-write</access>
            </field>
          </fields>
        </register>
        <register>
          <name>CLP4</name>
          <description>ADC Plus-Side General Calibration Value Register</description>
          <addressOffset>0x3C</addressOffset>
          <size>32</size>
          <access>read-write</access>
          <resetValue>0x200</resetValue>
          <resetMask>0xFFFFFFFF</resetMask>
          <fields>
            <field>
              <name>CLP4</name>
              <description>Calibration Value</description>
              <bitOffset>0</bitOffset>
              <bitWidth>10</bitWidth>
              <access>read-write</access>
            </field>
          </fields>
        </register>
        <register>
          <name>CLP3</name>
          <description>ADC Plus-Side General Calibration Value Register</description>
          <addressOffset>0x40</addressOffset>
          <size>32</size>
          <access>read-write</access>
          <resetValue>0x100</resetValue>
          <resetMask>0xFFFFFFFF</resetMask>
          <fields>
            <field>
              <name>CLP3</name>
              <description>Calibration Value</description>
              <bitOffset>0</bitOffset>
              <bitWidth>9</bitWidth>
              <access>read-write</access>
            </field>
          </fields>
        </register>
        <register>
          <name>CLP2</name>
          <description>ADC Plus-Side General Calibration Value Register</description>
          <addressOffset>0x44</addressOffset>
          <size>32</size>
          <access>read-write</access>
          <resetValue>0x80</resetValue>
          <resetMask>0xFFFFFFFF</resetMask>
          <fields>
            <field>
              <name>CLP2</name>
              <description>Calibration Value</description>
              <bitOffset>0</bitOffset>
              <bitWidth>8</bitWidth>
              <access>read-write</access>
            </field>
          </fields>
        </register>
        <register>
          <name>CLP1</name>
          <description>ADC Plus-Side General Calibration Value Register</description>
          <addressOffset>0x48</addressOffset>
          <size>32</size>
          <access>read-write</access>
          <resetValue>0x40</resetValue>
          <resetMask>0xFFFFFFFF</resetMask>
          <fields>
            <field>
              <name>CLP1</name>
              <description>Calibration Value</description>
              <bitOffset>0</bitOffset>
              <bitWidth>7</bitWidth>
              <access>read-write</access>
            </field>
          </fields>
        </register>
        <register>
          <name>CLP0</name>
          <description>ADC Plus-Side General Calibration Value Register</description>
          <addressOffset>0x4C</addressOffset>
          <size>32</size>
          <access>read-write</access>
          <resetValue>0x20</resetValue>
          <resetMask>0xFFFFFFFF</resetMask>
          <fields>
            <field>
              <name>CLP0</name>
              <description>Calibration Value</description>
              <bitOffset>0</bitOffset>
              <bitWidth>6</bitWidth>
              <access>read-write</access>
            </field>
          </fields>
        </register>
        <register>
          <name>CLMD</name>
          <description>ADC Minus-Side General Calibration Value Register</description>
          <addressOffset>0x54</addressOffset>
          <size>32</size>
          <access>read-write</access>
          <resetValue>0xA</resetValue>
          <resetMask>0xFFFFFFFF</resetMask>
          <fields>
            <field>
              <name>CLMD</name>
              <description>Calibration Value</description>
              <bitOffset>0</bitOffset>
              <bitWidth>6</bitWidth>
              <access>read-write</access>
            </field>
          </fields>
        </register>
        <register>
          <name>CLMS</name>
          <description>ADC Minus-Side General Calibration Value Register</description>
          <addressOffset>0x58</addressOffset>
          <size>32</size>
          <access>read-write</access>
          <resetValue>0x20</resetValue>
          <resetMask>0xFFFFFFFF</resetMask>
          <fields>
            <field>
              <name>CLMS</name>
              <description>Calibration Value</description>
              <bitOffset>0</bitOffset>
              <bitWidth>6</bitWidth>
              <access>read-write</access>
            </field>
          </fields>
        </register>
        <register>
          <name>CLM4</name>
          <description>ADC Minus-Side General Calibration Value Register</description>
          <addressOffset>0x5C</addressOffset>
          <size>32</size>
          <access>read-write</access>
          <resetValue>0x200</resetValue>
          <resetMask>0xFFFFFFFF</resetMask>
          <fields>
            <field>
              <name>CLM4</name>
              <description>Calibration Value</description>
              <bitOffset>0</bitOffset>
              <bitWidth>10</bitWidth>
              <access>read-write</access>
            </field>
          </fields>
        </register>
        <register>
          <name>CLM3</name>
          <description>ADC Minus-Side General Calibration Value Register</description>
          <addressOffset>0x60</addressOffset>
          <size>32</size>
          <access>read-write</access>
          <resetValue>0x100</resetValue>
          <resetMask>0xFFFFFFFF</resetMask>
          <fields>
            <field>
              <name>CLM3</name>
              <description>Calibration Value</description>
              <bitOffset>0</bitOffset>
              <bitWidth>9</bitWidth>
              <access>read-write</access>
            </field>
          </fields>
        </register>
        <register>
          <name>CLM2</name>
          <description>ADC Minus-Side General Calibration Value Register</description>
          <addressOffset>0x64</addressOffset>
          <size>32</size>
          <access>read-write</access>
          <resetValue>0x80</resetValue>
          <resetMask>0xFFFFFFFF</resetMask>
          <fields>
            <field>
              <name>CLM2</name>
              <description>Calibration Value</description>
              <bitOffset>0</bitOffset>
              <bitWidth>8</bitWidth>
              <access>read-write</access>
            </field>
          </fields>
        </register>
        <register>
          <name>CLM1</name>
          <description>ADC Minus-Side General Calibration Value Register</description>
          <addressOffset>0x68</addressOffset>
          <size>32</size>
          <access>read-write</access>
          <resetValue>0x40</resetValue>
          <resetMask>0xFFFFFFFF</resetMask>
          <fields>
            <field>
              <name>CLM1</name>
              <description>Calibration Value</description>
              <bitOffset>0</bitOffset>
              <bitWidth>7</bitWidth>
              <access>read-write</access>
            </field>
          </fields>
        </register>
        <register>
          <name>CLM0</name>
          <description>ADC Minus-Side General Calibration Value Register</description>
          <addressOffset>0x6C</addressOffset>
          <size>32</size>
          <access>read-write</access>
          <resetValue>0x20</resetValue>
          <resetMask>0xFFFFFFFF</resetMask>
          <fields>
            <field>
              <name>CLM0</name>
              <description>Calibration Value</description>
              <bitOffset>0</bitOffset>
              <bitWidth>6</bitWidth>
              <access>read-write</access>
            </field>
          </fields>
        </register>
      </registers>
    </peripheral>
    <peripheral>
      <name>RTC</name>
      <description>Secure Real Time Clock</description>
      <prependToName>RTC_</prependToName>
      <baseAddress>0x4003D000</baseAddress>
      <addressBlock>
        <offset>0</offset>
        <size>0x20</size>
        <usage>registers</usage>
      </addressBlock>
      <interrupt>
        <name>RTC</name>
        <value>20</value>
      </interrupt>
      <interrupt>
        <name>RTC_Seconds</name>
        <value>21</value>
      </interrupt>
      <registers>
        <register>
          <name>TSR</name>
          <description>RTC Time Seconds Register</description>
          <addressOffset>0</addressOffset>
          <size>32</size>
          <access>read-write</access>
          <resetValue>0</resetValue>
          <resetMask>0xFFFFFFFF</resetMask>
          <fields>
            <field>
              <name>TSR</name>
              <description>Time Seconds Register</description>
              <bitOffset>0</bitOffset>
              <bitWidth>32</bitWidth>
              <access>read-write</access>
            </field>
          </fields>
        </register>
        <register>
          <name>TPR</name>
          <description>RTC Time Prescaler Register</description>
          <addressOffset>0x4</addressOffset>
          <size>32</size>
          <access>read-write</access>
          <resetValue>0</resetValue>
          <resetMask>0xFFFFFFFF</resetMask>
          <fields>
            <field>
              <name>TPR</name>
              <description>Time Prescaler Register</description>
              <bitOffset>0</bitOffset>
              <bitWidth>16</bitWidth>
              <access>read-write</access>
            </field>
          </fields>
        </register>
        <register>
          <name>TAR</name>
          <description>RTC Time Alarm Register</description>
          <addressOffset>0x8</addressOffset>
          <size>32</size>
          <access>read-write</access>
          <resetValue>0</resetValue>
          <resetMask>0xFFFFFFFF</resetMask>
          <fields>
            <field>
              <name>TAR</name>
              <description>Time Alarm Register</description>
              <bitOffset>0</bitOffset>
              <bitWidth>32</bitWidth>
              <access>read-write</access>
            </field>
          </fields>
        </register>
        <register>
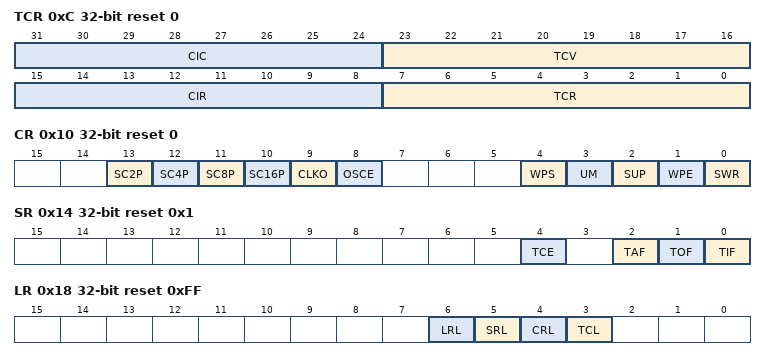
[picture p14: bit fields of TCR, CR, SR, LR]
          <name>TCR</name>
          <description>RTC Time Compensation Register</description>
          <addressOffset>0xC</addressOffset>
          <size>32</size>
          <access>read-write</access>
          <resetValue>0</resetValue>
          <resetMask>0xFFFFFFFF</resetMask>
          <fields>
            <field>
              <name>TCR</name>
              <description>Time Compensation Register</description>
              <bitOffset>0</bitOffset>
              <bitWidth>8</bitWidth>
              <access>read-write</access>
              <enumeratedValues>
                <enumeratedValue>
                  <name>10000000</name>
                  <description>Time Prescaler Register overflows every 32896 clock cycles.</description>
                  <value>#10000000</value>
                </enumeratedValue>
                <enumeratedValue>
                  <name>11111111</name>
                  <description>Time Prescaler Register overflows every 32769 clock cycles.</description>
                  <value>#11111111</value>
                </enumeratedValue>
                <enumeratedValue>
                  <name>0</name>
                  <description>Time Prescaler Register overflows every 32768 clock cycles.</description>
                  <value>#0</value>
                </enumeratedValue>
                <enumeratedValue>
                  <name>1</name>
                  <description>Time Prescaler Register overflows every 32767 clock cycles.</description>
                  <value>#1</value>
                </enumeratedValue>
                <enumeratedValue>
                  <name>1111111</name>
                  <description>Time Prescaler Register overflows every 32641 clock cycles.</description>
                  <value>#1111111</value>
                </enumeratedValue>
              </enumeratedValues>
            </field>
            <field>
              <name>CIR</name>
              <description>Compensation Interval Register</description>
              <bitOffset>8</bitOffset>
              <bitWidth>8</bitWidth>
              <access>read-write</access>
            </field>
            <field>
              <name>TCV</name>
              <description>Time Compensation Value</description>
              <bitOffset>16</bitOffset>
              <bitWidth>8</bitWidth>
              <access>read-only</access>
            </field>
            <field>
              <name>CIC</name>
              <description>Compensation Interval Counter</description>
              <bitOffset>24</bitOffset>
              <bitWidth>8</bitWidth>
              <access>read-only</access>
            </field>
          </fields>
        </register>
        <register>
          <name>CR</name>
          <description>RTC Control Register</description>
          <addressOffset>0x10</addressOffset>
          <size>32</size>
          <access>read-write</access>
          <resetValue>0</resetValue>
          <resetMask>0xFFFFFFFF</resetMask>
          <fields>
            <field>
              <name>SWR</name>
              <description>Software Reset</description>
              <bitOffset>0</bitOffset>
              <bitWidth>1</bitWidth>
              <access>read-write</access>
              <enumeratedValues>
                <enumeratedValue>
                  <name>0</name>
                  <description>No effect.</description>
                  <value>#0</value>
                </enumeratedValue>
                <enumeratedValue>
                  <name>1</name>
                  <description>Resets all RTC registers except for the SWR bit . The SWR bit is cleared by POR and by software explicitly clearing it.</description>
                  <value>#1</value>
                </enumeratedValue>
              </enumeratedValues>
            </field>
            <field>
              <name>WPE</name>
              <description>Wakeup Pin Enable</description>
              <bitOffset>1</bitOffset>
              <bitWidth>1</bitWidth>
              <access>read-write</access>
              <enumeratedValues>
                <enumeratedValue>
                  <name>0</name>
                  <description>Wakeup pin is disabled.</description>
                  <value>#0</value>
                </enumeratedValue>
                <enumeratedValue>
                  <name>1</name>
                  <description>Wakeup pin is enabled and wakeup pin asserts if the RTC interrupt asserts or the wakeup pin is turned on.</description>
                  <value>#1</value>
                </enumeratedValue>
              </enumeratedValues>
            </field>
            <field>
              <name>SUP</name>
              <description>Supervisor Access</description>
              <bitOffset>2</bitOffset>
              <bitWidth>1</bitWidth>
              <access>read-write</access>
              <enumeratedValues>
                <enumeratedValue>
                  <name>0</name>
                  <description>Non-supervisor mode write accesses are not supported and generate a bus error.</description>
                  <value>#0</value>
                </enumeratedValue>
                <enumeratedValue>
                  <name>1</name>
                  <description>Non-supervisor mode write accesses are supported.</description>
                  <value>#1</value>
                </enumeratedValue>
              </enumeratedValues>
            </field>
            <field>
              <name>UM</name>
              <description>Update Mode</description>
              <bitOffset>3</bitOffset>
              <bitWidth>1</bitWidth>
              <access>read-write</access>
              <enumeratedValues>
                <enumeratedValue>
                  <name>0</name>
                  <description>Registers cannot be written when locked.</description>
                  <value>#0</value>
                </enumeratedValue>
                <enumeratedValue>
                  <name>1</name>
                  <description>Registers can be written when locked under limited conditions.</description>
                  <value>#1</value>
                </enumeratedValue>
              </enumeratedValues>
            </field>
            <field>
              <name>WPS</name>
              <description>Wakeup Pin Select</description>
              <bitOffset>4</bitOffset>
              <bitWidth>1</bitWidth>
              <access>read-write</access>
              <enumeratedValues>
                <enumeratedValue>
                  <name>0</name>
                  <description>Wakeup pin asserts (active low, open drain) if the RTC interrupt asserts or the wakeup pin is turned on.</description>
                  <value>#0</value>
                </enumeratedValue>
                <enumeratedValue>
                  <name>1</name>
                  <description>Wakeup pin instead outputs the RTC 32kHz clock, provided the wakeup pin is turned on and the 32kHz clock is output to other peripherals.</description>
                  <value>#1</value>
                </enumeratedValue>
              </enumeratedValues>
            </field>
            <field>
              <name>OSCE</name>
              <description>Oscillator Enable</description>
              <bitOffset>8</bitOffset>
              <bitWidth>1</bitWidth>
              <access>read-write</access>
              <enumeratedValues>
                <enumeratedValue>
                  <name>0</name>
                  <description>32.768 kHz oscillator is disabled.</description>
                  <value>#0</value>
                </enumeratedValue>
                <enumeratedValue>
                  <name>1</name>
                  <description>32.768 kHz oscillator is enabled. After setting this bit, wait the oscillator startup time before enabling the time counter to allow the 32.768 kHz clock time to stabilize.</description>
                  <value>#1</value>
                </enumeratedValue>
              </enumeratedValues>
            </field>
            <field>
              <name>CLKO</name>
              <description>Clock Output</description>
              <bitOffset>9</bitOffset>
              <bitWidth>1</bitWidth>
              <access>read-write</access>
              <enumeratedValues>
                <enumeratedValue>
                  <name>0</name>
                  <description>The 32 kHz clock is output to other peripherals.</description>
                  <value>#0</value>
                </enumeratedValue>
                <enumeratedValue>
                  <name>1</name>
                  <description>The 32 kHz clock is not output to other peripherals.</description>
                  <value>#1</value>
                </enumeratedValue>
              </enumeratedValues>
            </field>
            <field>
              <name>SC16P</name>
              <description>Oscillator 16pF Load Configure</description>
              <bitOffset>10</bitOffset>
              <bitWidth>1</bitWidth>
              <access>read-write</access>
              <enumeratedValues>
                <enumeratedValue>
                  <name>0</name>
                  <description>Disable the load.</description>
                  <value>#0</value>
                </enumeratedValue>
                <enumeratedValue>
                  <name>1</name>
                  <description>Enable the additional load.</description>
                  <value>#1</value>
                </enumeratedValue>
              </enumeratedValues>
            </field>
            <field>
              <name>SC8P</name>
              <description>Oscillator 8pF Load Configure</description>
              <bitOffset>11</bitOffset>
              <bitWidth>1</bitWidth>
              <access>read-write</access>
              <enumeratedValues>
                <enumeratedValue>
                  <name>0</name>
                  <description>Disable the load.</description>
                  <value>#0</value>
                </enumeratedValue>
                <enumeratedValue>
                  <name>1</name>
                  <description>Enable the additional load.</description>
                  <value>#1</value>
                </enumeratedValue>
              </enumeratedValues>
            </field>
            <field>
              <name>SC4P</name>
              <description>Oscillator 4pF Load Configure</description>
              <bitOffset>12</bitOffset>
              <bitWidth>1</bitWidth>
              <access>read-write</access>
              <enumeratedValues>
                <enumeratedValue>
                  <name>0</name>
                  <description>Disable the load.</description>
                  <value>#0</value>
                </enumeratedValue>
                <enumeratedValue>
                  <name>1</name>
                  <description>Enable the additional load.</description>
                  <value>#1</value>
                </enumeratedValue>
              </enumeratedValues>
            </field>
            <field>
              <name>SC2P</name>
              <description>Oscillator 2pF Load Configure</description>
              <bitOffset>13</bitOffset>
              <bitWidth>1</bitWidth>
              <access>read-write</access>
              <enumeratedValues>
                <enumeratedValue>
                  <name>0</name>
                  <description>Disable the load.</description>
                  <value>#0</value>
                </enumeratedValue>
                <enumeratedValue>
                  <name>1</name>
                  <description>Enable the additional load.</description>
                  <value>#1</value>
                </enumeratedValue>
              </enumeratedValues>
            </field>
          </fields>
        </register>
        <register>
          <name>SR</name>
          <description>RTC Status Register</description>
          <addressOffset>0x14</addressOffset>
          <size>32</size>
          <access>read-write</access>
          <resetValue>0x1</resetValue>
          <resetMask>0xFFFFFFFF</resetMask>
          <fields>
            <field>
              <name>TIF</name>
              <description>Time Invalid Flag</description>
              <bitOffset>0</bitOffset>
              <bitWidth>1</bitWidth>
              <access>read-only</access>
              <enumeratedValues>
                <enumeratedValue>
                  <name>0</name>
                  <description>Time is valid.</description>
                  <value>#0</value>
                </enumeratedValue>
                <enumeratedValue>
                  <name>1</name>
                  <description>Time is invalid and time counter is read as zero.</description>
                  <value>#1</value>
                </enumeratedValue>
              </enumeratedValues>
            </field>
            <field>
              <name>TOF</name>
              <description>Time Overflow Flag</description>
              <bitOffset>1</bitOffset>
              <bitWidth>1</bitWidth>
              <access>read-only</access>
              <enumeratedValues>
                <enumeratedValue>
                  <name>0</name>
                  <description>Time overflow has not occurred.</description>
                  <value>#0</value>
                </enumeratedValue>
                <enumeratedValue>
                  <name>1</name>
                  <description>Time overflow has occurred and time counter is read as zero.</description>
                  <value>#1</value>
                </enumeratedValue>
              </enumeratedValues>
            </field>
            <field>
              <name>TAF</name>
              <description>Time Alarm Flag</description>
              <bitOffset>2</bitOffset>
              <bitWidth>1</bitWidth>
              <access>read-only</access>
              <enumeratedValues>
                <enumeratedValue>
                  <name>0</name>
                  <description>Time alarm has not occurred.</description>
                  <value>#0</value>
                </enumeratedValue>
                <enumeratedValue>
                  <name>1</name>
                  <description>Time alarm has occurred.</description>
                  <value>#1</value>
                </enumeratedValue>
              </enumeratedValues>
            </field>
            <field>
              <name>TCE</name>
              <description>Time Counter Enable</description>
              <bitOffset>4</bitOffset>
              <bitWidth>1</bitWidth>
              <access>read-write</access>
              <enumeratedValues>
                <enumeratedValue>
                  <name>0</name>
                  <description>Time counter is disabled.</description>
                  <value>#0</value>
                </enumeratedValue>
                <enumeratedValue>
                  <name>1</name>
                  <description>Time counter is enabled.</description>
                  <value>#1</value>
                </enumeratedValue>
              </enumeratedValues>
            </field>
          </fields>
        </register>
        <register>
          <name>LR</name>
          <description>RTC Lock Register</description>
          <addressOffset>0x18</addressOffset>
          <size>32</size>
          <access>read-write</access>
          <resetValue>0xFF</resetValue>
          <resetMask>0xFFFFFFFF</resetMask>
          <fields>
            <field>
              <name>TCL</name>
              <description>Time Compensation Lock</description>
              <bitOffset>3</bitOffset>
              <bitWidth>1</bitWidth>
              <access>read-write</access>
              <enumeratedValues>
                <enumeratedValue>
                  <name>0</name>
                  <description>Time Compensation Register is locked and writes are ignored.</description>
                  <value>#0</value>
                </enumeratedValue>
                <enumeratedValue>
                  <name>1</name>
                  <description>Time Compensation Register is not locked and writes complete as normal.</description>
                  <value>#1</value>
                </enumeratedValue>
              </enumeratedValues>
            </field>
            <field>
              <name>CRL</name>
              <description>Control Register Lock</description>
              <bitOffset>4</bitOffset>
              <bitWidth>1</bitWidth>
              <access>read-write</access>
              <enumeratedValues>
                <enumeratedValue>
                  <name>0</name>
                  <description>Control Register is locked and writes are ignored.</description>
                  <value>#0</value>
                </enumeratedValue>
                <enumeratedValue>
                  <name>1</name>
                  <description>Control Register is not locked and writes complete as normal.</description>
                  <value>#1</value>
                </enumeratedValue>
              </enumeratedValues>
            </field>
            <field>
              <name>SRL</name>
              <description>Status Register Lock</description>
              <bitOffset>5</bitOffset>
              <bitWidth>1</bitWidth>
              <access>read-write</access>
              <enumeratedValues>
                <enumeratedValue>
                  <name>0</name>
                  <description>Status Register is locked and writes are ignored.</description>
                  <value>#0</value>
                </enumeratedValue>
                <enumeratedValue>
                  <name>1</name>
                  <description>Status Register is not locked and writes complete as normal.</description>
                  <value>#1</value>
                </enumeratedValue>
              </enumeratedValues>
            </field>
            <field>
              <name>LRL</name>
              <description>Lock Register Lock</description>
              <bitOffset>6</bitOffset>
              <bitWidth>1</bitWidth>
              <access>read-write</access>
              <enumeratedValues>
                <enumeratedValue>
                  <name>0</name>
                  <description>Lock Register is locked and writes are ignored.</description>
                  <value>#0</value>
                </enumeratedValue>
                <enumeratedValue>
                  <name>1</name>
                  <description>Lock Register is not locked and writes complete as normal.</description>
                  <value>#1</value>
                </enumeratedValue>
              </enumeratedValues>
            </field>
          </fields>
        </register>
        <register>
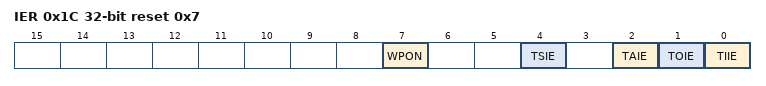
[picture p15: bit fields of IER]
          <name>IER</name>
          <description>RTC Interrupt Enable Register</description>
          <addressOffset>0x1C</addressOffset>
          <size>32</size>
          <access>read-write</access>
          <resetValue>0x7</resetValue>
          <resetMask>0xFFFFFFFF</resetMask>
          <fields>
            <field>
              <name>TIIE</name>
              <description>Time Invalid Interrupt Enable</description>
              <bitOffset>0</bitOffset>
              <bitWidth>1</bitWidth>
              <access>read-write</access>
              <enumeratedValues>
                <enumeratedValue>
                  <name>0</name>
                  <description>Time invalid flag does not generate an interrupt.</description>
                  <value>#0</value>
                </enumeratedValue>
                <enumeratedValue>
                  <name>1</name>
                  <description>Time invalid flag does generate an interrupt.</description>
                  <value>#1</value>
                </enumeratedValue>
              </enumeratedValues>
            </field>
            <field>
              <name>TOIE</name>
              <description>Time Overflow Interrupt Enable</description>
              <bitOffset>1</bitOffset>
              <bitWidth>1</bitWidth>
              <access>read-write</access>
              <enumeratedValues>
                <enumeratedValue>
                  <name>0</name>
                  <description>Time overflow flag does not generate an interrupt.</description>
                  <value>#0</value>
                </enumeratedValue>
                <enumeratedValue>
                  <name>1</name>
                  <description>Time overflow flag does generate an interrupt.</description>
                  <value>#1</value>
                </enumeratedValue>
              </enumeratedValues>
            </field>
            <field>
              <name>TAIE</name>
              <description>Time Alarm Interrupt Enable</description>
              <bitOffset>2</bitOffset>
              <bitWidth>1</bitWidth>
              <access>read-write</access>
              <enumeratedValues>
                <enumeratedValue>
                  <name>0</name>
                  <description>Time alarm flag does not generate an interrupt.</description>
                  <value>#0</value>
                </enumeratedValue>
                <enumeratedValue>
                  <name>1</name>
                  <description>Time alarm flag does generate an interrupt.</description>
                  <value>#1</value>
                </enumeratedValue>
              </enumeratedValues>
            </field>
            <field>
              <name>TSIE</name>
              <description>Time Seconds Interrupt Enable</description>
              <bitOffset>4</bitOffset>
              <bitWidth>1</bitWidth>
              <access>read-write</access>
              <enumeratedValues>
                <enumeratedValue>
                  <name>0</name>
                  <description>Seconds interrupt is disabled.</description>
                  <value>#0</value>
                </enumeratedValue>
                <enumeratedValue>
                  <name>1</name>
                  <description>Seconds interrupt is enabled.</description>
                  <value>#1</value>
                </enumeratedValue>
              </enumeratedValues>
            </field>
            <field>
              <name>WPON</name>
              <description>Wakeup Pin On</description>
              <bitOffset>7</bitOffset>
              <bitWidth>1</bitWidth>
              <access>read-write</access>
              <enumeratedValues>
                <enumeratedValue>
                  <name>0</name>
                  <description>No effect.</description>
                  <value>#0</value>
                </enumeratedValue>
                <enumeratedValue>
                  <name>1</name>
                  <description>If the wakeup pin is enabled, then the wakeup pin will assert.</description>
                  <value>#1</value>
                </enumeratedValue>
              </enumeratedValues>
            </field>
          </fields>
        </register>
      </registers>
    </peripheral>
    <peripheral>
      <name>DAC0</name>
      <description>12-Bit Digital-to-Analog Converter</description>
      <prependToName>DAC0_</prependToName>
      <baseAddress>0x4003F000</baseAddress>
      <addressBlock>
        <offset>0</offset>
        <size>0x24</size>
        <usage>registers</usage>
      </addressBlock>
      <interrupt>
        <name>DAC0</name>
        <value>25</value>
      </interrupt>
      <registers>
        <register>
          <dim>2</dim>
          <dimIncrement>0x2</dimIncrement>
          <dimIndex>0,1</dimIndex>
          <name>DAT%sL</name>
          <description>DAC Data Low Register</description>
          <addressOffset>0</addressOffset>
          <size>8</size>
          <access>read-write</access>
          <resetValue>0</resetValue>
          <resetMask>0xFF</resetMask>
          <fields>
            <field>
              <name>DATA0</name>
              <description>When the DAC buffer is not enabled, DATA[11:0] controls the output voltage based on the following formula: V out = V in * (1 + DACDAT0[11:0])/4096 When the DAC buffer is enabled, DATA is mapped to the 16-word buffer</description>
              <bitOffset>0</bitOffset>
              <bitWidth>8</bitWidth>
              <access>read-write</access>
            </field>
          </fields>
        </register>
        <register>
          <dim>2</dim>
          <dimIncrement>0x2</dimIncrement>
          <dimIndex>0,1</dimIndex>
          <name>DAT%sH</name>
          <description>DAC Data High Register</description>
          <addressOffset>0x1</addressOffset>
          <size>8</size>
          <access>read-write</access>
          <resetValue>0</resetValue>
          <resetMask>0xFF</resetMask>
          <fields>
            <field>
              <name>DATA1</name>
              <description>When the DAC Buffer is not enabled, DATA[11:0] controls the output voltage based on the following formula</description>
              <bitOffset>0</bitOffset>
              <bitWidth>4</bitWidth>
              <access>read-write</access>
            </field>
          </fields>
        </register>
        <register>
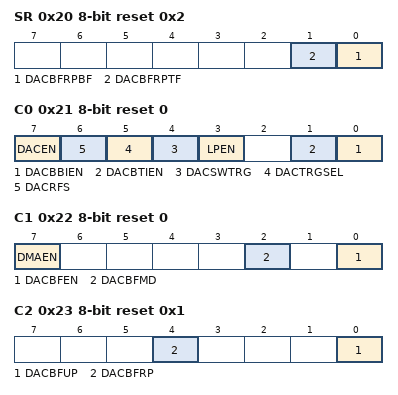
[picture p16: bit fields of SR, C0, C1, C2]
          <name>SR</name>
          <description>DAC Status Register</description>
          <addressOffset>0x20</addressOffset>
          <size>8</size>
          <access>read-write</access>
          <resetValue>0x2</resetValue>
          <resetMask>0xFF</resetMask>
          <fields>
            <field>
              <name>DACBFRPBF</name>
              <description>DAC Buffer Read Pointer Bottom Position Flag</description>
              <bitOffset>0</bitOffset>
              <bitWidth>1</bitWidth>
              <access>read-write</access>
              <enumeratedValues>
                <enumeratedValue>
                  <name>0</name>
                  <description>The DAC buffer read pointer is not equal to C2[DACBFUP].</description>
                  <value>#0</value>
                </enumeratedValue>
                <enumeratedValue>
                  <name>1</name>
                  <description>The DAC buffer read pointer is equal to C2[DACBFUP].</description>
                  <value>#1</value>
                </enumeratedValue>
              </enumeratedValues>
            </field>
            <field>
              <name>DACBFRPTF</name>
              <description>DAC Buffer Read Pointer Top Position Flag</description>
              <bitOffset>1</bitOffset>
              <bitWidth>1</bitWidth>
              <access>read-write</access>
              <enumeratedValues>
                <enumeratedValue>
                  <name>0</name>
                  <description>The DAC buffer read pointer is not zero.</description>
                  <value>#0</value>
                </enumeratedValue>
                <enumeratedValue>
                  <name>1</name>
                  <description>The DAC buffer read pointer is zero.</description>
                  <value>#1</value>
                </enumeratedValue>
              </enumeratedValues>
            </field>
          </fields>
        </register>
        <register>
          <name>C0</name>
          <description>DAC Control Register</description>
          <addressOffset>0x21</addressOffset>
          <size>8</size>
          <access>read-write</access>
          <resetValue>0</resetValue>
          <resetMask>0xFF</resetMask>
          <fields>
            <field>
              <name>DACBBIEN</name>
              <description>DAC Buffer Read Pointer Bottom Flag Interrupt Enable</description>
              <bitOffset>0</bitOffset>
              <bitWidth>1</bitWidth>
              <access>read-write</access>
              <enumeratedValues>
                <enumeratedValue>
                  <name>0</name>
                  <description>The DAC buffer read pointer bottom flag interrupt is disabled.</description>
                  <value>#0</value>
                </enumeratedValue>
                <enumeratedValue>
                  <name>1</name>
                  <description>The DAC buffer read pointer bottom flag interrupt is enabled.</description>
                  <value>#1</value>
                </enumeratedValue>
              </enumeratedValues>
            </field>
            <field>
              <name>DACBTIEN</name>
              <description>DAC Buffer Read Pointer Top Flag Interrupt Enable</description>
              <bitOffset>1</bitOffset>
              <bitWidth>1</bitWidth>
              <access>read-write</access>
              <enumeratedValues>
                <enumeratedValue>
                  <name>0</name>
                  <description>The DAC buffer read pointer top flag interrupt is disabled.</description>
                  <value>#0</value>
                </enumeratedValue>
                <enumeratedValue>
                  <name>1</name>
                  <description>The DAC buffer read pointer top flag interrupt is enabled.</description>
                  <value>#1</value>
                </enumeratedValue>
              </enumeratedValues>
            </field>
            <field>
              <name>LPEN</name>
              <description>DAC Low Power Control</description>
              <bitOffset>3</bitOffset>
              <bitWidth>1</bitWidth>
              <access>read-write</access>
              <enumeratedValues>
                <enumeratedValue>
                  <name>0</name>
                  <description>High-Power mode</description>
                  <value>#0</value>
                </enumeratedValue>
                <enumeratedValue>
                  <name>1</name>
                  <description>Low-Power mode</description>
                  <value>#1</value>
                </enumeratedValue>
              </enumeratedValues>
            </field>
            <field>
              <name>DACSWTRG</name>
              <description>DAC Software Trigger</description>
              <bitOffset>4</bitOffset>
              <bitWidth>1</bitWidth>
              <access>write-only</access>
              <enumeratedValues>
                <enumeratedValue>
                  <name>0</name>
                  <description>The DAC soft trigger is not valid.</description>
                  <value>#0</value>
                </enumeratedValue>
                <enumeratedValue>
                  <name>1</name>
                  <description>The DAC soft trigger is valid.</description>
                  <value>#1</value>
                </enumeratedValue>
              </enumeratedValues>
            </field>
            <field>
              <name>DACTRGSEL</name>
              <description>DAC Trigger Select</description>
              <bitOffset>5</bitOffset>
              <bitWidth>1</bitWidth>
              <access>read-write</access>
              <enumeratedValues>
                <enumeratedValue>
                  <name>0</name>
                  <description>The DAC hardware trigger is selected.</description>
                  <value>#0</value>
                </enumeratedValue>
                <enumeratedValue>
                  <name>1</name>
                  <description>The DAC software trigger is selected.</description>
                  <value>#1</value>
                </enumeratedValue>
              </enumeratedValues>
            </field>
            <field>
              <name>DACRFS</name>
              <description>DAC Reference Select</description>
              <bitOffset>6</bitOffset>
              <bitWidth>1</bitWidth>
              <access>read-write</access>
              <enumeratedValues>
                <enumeratedValue>
                  <name>0</name>
                  <description>The DAC selects DACREF_1 as the reference voltage.</description>
                  <value>#0</value>
                </enumeratedValue>
                <enumeratedValue>
                  <name>1</name>
                  <description>The DAC selects DACREF_2 as the reference voltage.</description>
                  <value>#1</value>
                </enumeratedValue>
              </enumeratedValues>
            </field>
            <field>
              <name>DACEN</name>
              <description>DAC Enable</description>
              <bitOffset>7</bitOffset>
              <bitWidth>1</bitWidth>
              <access>read-write</access>
              <enumeratedValues>
                <enumeratedValue>
                  <name>0</name>
                  <description>The DAC system is disabled.</description>
                  <value>#0</value>
                </enumeratedValue>
                <enumeratedValue>
                  <name>1</name>
                  <description>The DAC system is enabled.</description>
                  <value>#1</value>
                </enumeratedValue>
              </enumeratedValues>
            </field>
          </fields>
        </register>
        <register>
          <name>C1</name>
          <description>DAC Control Register 1</description>
          <addressOffset>0x22</addressOffset>
          <size>8</size>
          <access>read-write</access>
          <resetValue>0</resetValue>
          <resetMask>0xFF</resetMask>
          <fields>
            <field>
              <name>DACBFEN</name>
              <description>DAC Buffer Enable</description>
              <bitOffset>0</bitOffset>
              <bitWidth>1</bitWidth>
              <access>read-write</access>
              <enumeratedValues>
                <enumeratedValue>
                  <name>0</name>
                  <description>Buffer read pointer is disabled. The converted data is always the first word of the buffer.</description>
                  <value>#0</value>
                </enumeratedValue>
                <enumeratedValue>
                  <name>1</name>
                  <description>Buffer read pointer is enabled. The converted data is the word that the read pointer points to. It means converted data can be from any word of the buffer.</description>
                  <value>#1</value>
                </enumeratedValue>
              </enumeratedValues>
            </field>
            <field>
              <name>DACBFMD</name>
              <description>DAC Buffer Work Mode Select</description>
              <bitOffset>2</bitOffset>
              <bitWidth>1</bitWidth>
              <access>read-write</access>
              <enumeratedValues>
                <enumeratedValue>
                  <name>0</name>
                  <description>Normal mode</description>
                  <value>#0</value>
                </enumeratedValue>
                <enumeratedValue>
                  <name>1</name>
                  <description>One-Time Scan mode</description>
                  <value>#1</value>
                </enumeratedValue>
              </enumeratedValues>
            </field>
            <field>
              <name>DMAEN</name>
              <description>DMA Enable Select</description>
              <bitOffset>7</bitOffset>
              <bitWidth>1</bitWidth>
              <access>read-write</access>
              <enumeratedValues>
                <enumeratedValue>
                  <name>0</name>
                  <description>DMA is disabled.</description>
                  <value>#0</value>
                </enumeratedValue>
                <enumeratedValue>
                  <name>1</name>
                  <description>DMA is enabled. When DMA is enabled, the DMA request will be generated by original interrupts. The interrupts will not be presented on this module at the same time.</description>
                  <value>#1</value>
                </enumeratedValue>
              </enumeratedValues>
            </field>
          </fields>
        </register>
        <register>
          <name>C2</name>
          <description>DAC Control Register 2</description>
          <addressOffset>0x23</addressOffset>
          <size>8</size>
          <access>read-write</access>
          <resetValue>0x1</resetValue>
          <resetMask>0xFF</resetMask>
          <fields>
            <field>
              <name>DACBFUP</name>
              <description>DAC Buffer Upper Limit</description>
              <bitOffset>0</bitOffset>
              <bitWidth>1</bitWidth>
              <access>read-write</access>
            </field>
            <field>
              <name>DACBFRP</name>
              <description>DAC Buffer Read Pointer</description>
              <bitOffset>4</bitOffset>
              <bitWidth>1</bitWidth>
              <access>read-write</access>
            </field>
          </fields>
        </register>
      </registers>
    </peripheral>
    <peripheral>
      <name>LPTMR0</name>
      <description>Low Power Timer</description>
      <prependToName>LPTMR0_</prependToName>
      <baseAddress>0x40040000</baseAddress>
      <addressBlock>
        <offset>0</offset>
        <size>0x10</size>
        <usage>registers</usage>
      </addressBlock>
      <interrupt>
        <name>LPTMR0</name>
        <value>28</value>
      </interrupt>
      <registers>
        <register>
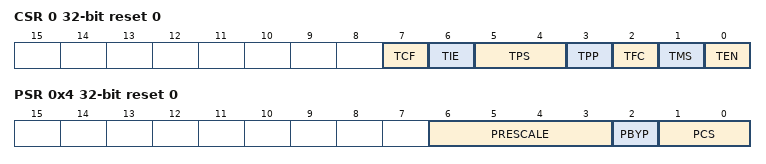
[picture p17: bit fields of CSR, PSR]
          <name>CSR</name>
          <description>Low Power Timer Control Status Register</description>
          <addressOffset>0</addressOffset>
          <size>32</size>
          <access>read-write</access>
          <resetValue>0</resetValue>
          <resetMask>0xFFFFFFFF</resetMask>
          <fields>
            <field>
              <name>TEN</name>
              <description>Timer Enable</description>
              <bitOffset>0</bitOffset>
              <bitWidth>1</bitWidth>
              <access>read-write</access>
              <enumeratedValues>
                <enumeratedValue>
                  <name>0</name>
                  <description>LPTMR is disabled and internal logic is reset.</description>
                  <value>#0</value>
                </enumeratedValue>
                <enumeratedValue>
                  <name>1</name>
                  <description>LPTMR is enabled.</description>
                  <value>#1</value>
                </enumeratedValue>
              </enumeratedValues>
            </field>
            <field>
              <name>TMS</name>
              <description>Timer Mode Select</description>
              <bitOffset>1</bitOffset>
              <bitWidth>1</bitWidth>
              <access>read-write</access>
              <enumeratedValues>
                <enumeratedValue>
                  <name>0</name>
                  <description>Time Counter mode.</description>
                  <value>#0</value>
                </enumeratedValue>
                <enumeratedValue>
                  <name>1</name>
                  <description>Pulse Counter mode.</description>
                  <value>#1</value>
                </enumeratedValue>
              </enumeratedValues>
            </field>
            <field>
              <name>TFC</name>
              <description>Timer Free-Running Counter</description>
              <bitOffset>2</bitOffset>
              <bitWidth>1</bitWidth>
              <access>read-write</access>
              <enumeratedValues>
                <enumeratedValue>
                  <name>0</name>
                  <description>CNR is reset whenever TCF is set.</description>
                  <value>#0</value>
                </enumeratedValue>
                <enumeratedValue>
                  <name>1</name>
                  <description>CNR is reset on overflow.</description>
                  <value>#1</value>
                </enumeratedValue>
              </enumeratedValues>
            </field>
            <field>
              <name>TPP</name>
              <description>Timer Pin Polarity</description>
              <bitOffset>3</bitOffset>
              <bitWidth>1</bitWidth>
              <access>read-write</access>
              <enumeratedValues>
                <enumeratedValue>
                  <name>0</name>
                  <description>Pulse Counter input source is active-high, and the CNR will increment on the rising-edge.</description>
                  <value>#0</value>
                </enumeratedValue>
                <enumeratedValue>
                  <name>1</name>
                  <description>Pulse Counter input source is active-low, and the CNR will increment on the falling-edge.</description>
                  <value>#1</value>
                </enumeratedValue>
              </enumeratedValues>
            </field>
            <field>
              <name>TPS</name>
              <description>Timer Pin Select</description>
              <bitOffset>4</bitOffset>
              <bitWidth>2</bitWidth>
              <access>read-write</access>
              <enumeratedValues>
                <enumeratedValue>
                  <name>00</name>
                  <description>Pulse counter input 0 is selected.</description>
                  <value>#00</value>
                </enumeratedValue>
                <enumeratedValue>
                  <name>01</name>
                  <description>Pulse counter input 1 is selected.</description>
                  <value>#01</value>
                </enumeratedValue>
                <enumeratedValue>
                  <name>10</name>
                  <description>Pulse counter input 2 is selected.</description>
                  <value>#10</value>
                </enumeratedValue>
                <enumeratedValue>
                  <name>11</name>
                  <description>Pulse counter input 3 is selected.</description>
                  <value>#11</value>
                </enumeratedValue>
              </enumeratedValues>
            </field>
            <field>
              <name>TIE</name>
              <description>Timer Interrupt Enable</description>
              <bitOffset>6</bitOffset>
              <bitWidth>1</bitWidth>
              <access>read-write</access>
              <enumeratedValues>
                <enumeratedValue>
                  <name>0</name>
                  <description>Timer interrupt disabled.</description>
                  <value>#0</value>
                </enumeratedValue>
                <enumeratedValue>
                  <name>1</name>
                  <description>Timer interrupt enabled.</description>
                  <value>#1</value>
                </enumeratedValue>
              </enumeratedValues>
            </field>
            <field>
              <name>TCF</name>
              <description>Timer Compare Flag</description>
              <bitOffset>7</bitOffset>
              <bitWidth>1</bitWidth>
              <access>read-write</access>
              <enumeratedValues>
                <enumeratedValue>
                  <name>0</name>
                  <description>The value of CNR is not equal to CMR and increments.</description>
                  <value>#0</value>
                </enumeratedValue>
                <enumeratedValue>
                  <name>1</name>
                  <description>The value of CNR is equal to CMR and increments.</description>
                  <value>#1</value>
                </enumeratedValue>
              </enumeratedValues>
            </field>
          </fields>
        </register>
        <register>
          <name>PSR</name>
          <description>Low Power Timer Prescale Register</description>
          <addressOffset>0x4</addressOffset>
          <size>32</size>
          <access>read-write</access>
          <resetValue>0</resetValue>
          <resetMask>0xFFFFFFFF</resetMask>
          <fields>
            <field>
              <name>PCS</name>
              <description>Prescaler Clock Select</description>
              <bitOffset>0</bitOffset>
              <bitWidth>2</bitWidth>
              <access>read-write</access>
              <enumeratedValues>
                <enumeratedValue>
                  <name>00</name>
                  <description>Prescaler/glitch filter clock 0 selected.</description>
                  <value>#00</value>
                </enumeratedValue>
                <enumeratedValue>
                  <name>01</name>
                  <description>Prescaler/glitch filter clock 1 selected.</description>
                  <value>#01</value>
                </enumeratedValue>
                <enumeratedValue>
                  <name>10</name>
                  <description>Prescaler/glitch filter clock 2 selected.</description>
                  <value>#10</value>
                </enumeratedValue>
                <enumeratedValue>
                  <name>11</name>
                  <description>Prescaler/glitch filter clock 3 selected.</description>
                  <value>#11</value>
                </enumeratedValue>
              </enumeratedValues>
            </field>
            <field>
              <name>PBYP</name>
              <description>Prescaler Bypass</description>
              <bitOffset>2</bitOffset>
              <bitWidth>1</bitWidth>
              <access>read-write</access>
              <enumeratedValues>
                <enumeratedValue>
                  <name>0</name>
                  <description>Prescaler/glitch filter is enabled.</description>
                  <value>#0</value>
                </enumeratedValue>
                <enumeratedValue>
                  <name>1</name>
                  <description>Prescaler/glitch filter is bypassed.</description>
                  <value>#1</value>
                </enumeratedValue>
              </enumeratedValues>
            </field>
            <field>
              <name>PRESCALE</name>
              <description>Prescale Value</description>
              <bitOffset>3</bitOffset>
              <bitWidth>4</bitWidth>
              <access>read-write</access>
              <enumeratedValues>
                <enumeratedValue>
                  <name>0000</name>
                  <description>Prescaler divides the prescaler clock by 2; glitch filter does not support this configuration.</description>
                  <value>#0000</value>
                </enumeratedValue>
                <enumeratedValue>
                  <name>0001</name>
                  <description>Prescaler divides the prescaler clock by 4; glitch filter recognizes change on input pin after 2 rising clock edges.</description>
                  <value>#0001</value>
                </enumeratedValue>
                <enumeratedValue>
                  <name>0010</name>
                  <description>Prescaler divides the prescaler clock by 8; glitch filter recognizes change on input pin after 4 rising clock edges.</description>
                  <value>#0010</value>
                </enumeratedValue>
                <enumeratedValue>
                  <name>0011</name>
                  <description>Prescaler divides the prescaler clock by 16; glitch filter recognizes change on input pin after 8 rising clock edges.</description>
                  <value>#0011</value>
                </enumeratedValue>
                <enumeratedValue>
                  <name>0100</name>
                  <description>Prescaler divides the prescaler clock by 32; glitch filter recognizes change on input pin after 16 rising clock edges.</description>
                  <value>#0100</value>
                </enumeratedValue>
                <enumeratedValue>
                  <name>0101</name>
                  <description>Prescaler divides the prescaler clock by 64; glitch filter recognizes change on input pin after 32 rising clock edges.</description>
                  <value>#0101</value>
                </enumeratedValue>
                <enumeratedValue>
                  <name>0110</name>
                  <description>Prescaler divides the prescaler clock by 128; glitch filter recognizes change on input pin after 64 rising clock edges.</description>
                  <value>#0110</value>
                </enumeratedValue>
                <enumeratedValue>
                  <name>0111</name>
                  <description>Prescaler divides the prescaler clock by 256; glitch filter recognizes change on input pin after 128 rising clock edges.</description>
                  <value>#0111</value>
                </enumeratedValue>
                <enumeratedValue>
                  <name>1000</name>
                  <description>Prescaler divides the prescaler clock by 512; glitch filter recognizes change on input pin after 256 rising clock edges.</description>
                  <value>#1000</value>
                </enumeratedValue>
                <enumeratedValue>
                  <name>1001</name>
                  <description>Prescaler divides the prescaler clock by 1024; glitch filter recognizes change on input pin after 512 rising clock edges.</description>
                  <value>#1001</value>
                </enumeratedValue>
                <enumeratedValue>
                  <name>1010</name>
                  <description>Prescaler divides the prescaler clock by 2048; glitch filter recognizes change on input pin after 1024 rising clock edges.</description>
                  <value>#1010</value>
                </enumeratedValue>
                <enumeratedValue>
                  <name>1011</name>
                  <description>Prescaler divides the prescaler clock by 4096; glitch filter recognizes change on input pin after 2048 rising clock edges.</description>
                  <value>#1011</value>
                </enumeratedValue>
                <enumeratedValue>
                  <name>1100</name>
                  <description>Prescaler divides the prescaler clock by 8192; glitch filter recognizes change on input pin after 4096 rising clock edges.</description>
                  <value>#1100</value>
                </enumeratedValue>
                <enumeratedValue>
                  <name>1101</name>
                  <description>Prescaler divides the prescaler clock by 16,384; glitch filter recognizes change on input pin after 8192 rising clock edges.</description>
                  <value>#1101</value>
                </enumeratedValue>
                <enumeratedValue>
                  <name>1110</name>
                  <description>Prescaler divides the prescaler clock by 32,768; glitch filter recognizes change on input pin after 16,384 rising clock edges.</description>
                  <value>#1110</value>
                </enumeratedValue>
                <enumeratedValue>
                  <name>1111</name>
                  <description>Prescaler divides the prescaler clock by 65,536; glitch filter recognizes change on input pin after 32,768 rising clock edges.</description>
                  <value>#1111</value>
                </enumeratedValue>
              </enumeratedValues>
            </field>
          </fields>
        </register>
        <register>
          <name>CMR</name>
          <description>Low Power Timer Compare Register</description>
          <addressOffset>0x8</addressOffset>
          <size>32</size>
          <access>read-write</access>
          <resetValue>0</resetValue>
          <resetMask>0xFFFFFFFF</resetMask>
          <fields>
            <field>
              <name>COMPARE</name>
              <description>Compare Value</description>
              <bitOffset>0</bitOffset>
              <bitWidth>16</bitWidth>
              <access>read-write</access>
            </field>
          </fields>
        </register>
        <register>
          <name>CNR</name>
          <description>Low Power Timer Counter Register</description>
          <addressOffset>0xC</addressOffset>
          <size>32</size>
          <access>read-write</access>
          <resetValue>0</resetValue>
          <resetMask>0xFFFFFFFF</resetMask>
          <fields>
            <field>
              <name>COUNTER</name>
              <description>Counter Value</description>
              <bitOffset>0</bitOffset>
              <bitWidth>16</bitWidth>
              <access>read-write</access>
            </field>
          </fields>
        </register>
      </registers>
    </peripheral>
    <peripheral>
      <name>TSI0</name>
      <description>Touch sense input</description>
      <prependToName>TSI0_</prependToName>
      <baseAddress>0x40045000</baseAddress>
      <addressBlock>
        <offset>0</offset>
        <size>0xC</size>
        <usage>registers</usage>
      </addressBlock>
      <interrupt>
        <name>TSI0</name>
        <value>26</value>
      </interrupt>
      <registers>
        <register>
          <name>GENCS</name>
          <description>TSI General Control and Status Register</description>
          <addressOffset>0</addressOffset>
          <size>32</size>
          <access>read-write</access>
          <resetValue>0</resetValue>
          <resetMask>0xFFFFFFFF</resetMask>
          <fields>
            <field>
              <name>CURSW</name>
              <description>CURSW</description>
              <bitOffset>1</bitOffset>
              <bitWidth>1</bitWidth>
              <access>read-write</access>
              <enumeratedValues>
                <enumeratedValue>
                  <name>0</name>
                  <description>The current source pair are not swapped.</description>
                  <value>#0</value>
                </enumeratedValue>
                <enumeratedValue>
                  <name>1</name>
                  <description>The current source pair are swapped.</description>
                  <value>#1</value>
                </enumeratedValue>
              </enumeratedValues>
            </field>
            <field>
              <name>EOSF</name>
              <description>End of Scan Flag</description>
              <bitOffset>2</bitOffset>
              <bitWidth>1</bitWidth>
              <access>read-write</access>
              <enumeratedValues>
                <enumeratedValue>
                  <name>0</name>
                  <description>Scan not complete.</description>
                  <value>#0</value>
                </enumeratedValue>
                <enumeratedValue>
                  <name>1</name>
                  <description>Scan complete.</description>
                  <value>#1</value>
                </enumeratedValue>
              </enumeratedValues>
            </field>
            <field>
              <name>SCNIP</name>
              <description>Scan In Progress Status</description>
              <bitOffset>3</bitOffset>
              <bitWidth>1</bitWidth>
              <access>read-only</access>
              <enumeratedValues>
                <enumeratedValue>
                  <name>0</name>
                  <description>No scan in progress.</description>
                  <value>#0</value>
                </enumeratedValue>
                <enumeratedValue>
                  <name>1</name>
                  <description>Scan in progress.</description>
                  <value>#1</value>
                </enumeratedValue>
              </enumeratedValues>
            </field>
            <field>
              <name>STM</name>
              <description>Scan Trigger Mode</description>
              <bitOffset>4</bitOffset>
              <bitWidth>1</bitWidth>
              <access>read-write</access>
              <enumeratedValues>
                <enumeratedValue>
                  <name>0</name>
                  <description>Software trigger scan.</description>
                  <value>#0</value>
                </enumeratedValue>
                <enumeratedValue>
                  <name>1</name>
                  <description>Hardware trigger scan.</description>
                  <value>#1</value>
                </enumeratedValue>
              </enumeratedValues>
            </field>
            <field>
              <name>STPE</name>
              <description>TSI STOP Enable</description>
              <bitOffset>5</bitOffset>
              <bitWidth>1</bitWidth>
              <access>read-write</access>
              <enumeratedValues>
                <enumeratedValue>
                  <name>0</name>
                  <description>TSI is disabled when MCU goes into low power mode.</description>
                  <value>#0</value>
                </enumeratedValue>
                <enumeratedValue>
                  <name>1</name>
                  <description>Allows TSI to continue running in all low power modes.</description>
                  <value>#1</value>
                </enumeratedValue>
              </enumeratedValues>
            </field>
            <field>
              <name>TSIIEN</name>
              <description>Touch Sensing Input Interrupt Enable</description>
              <bitOffset>6</bitOffset>
              <bitWidth>1</bitWidth>
              <access>read-write</access>
              <enumeratedValues>
                <enumeratedValue>
                  <name>0</name>
                  <description>TSI interrupt is disabled.</description>
                  <value>#0</value>
                </enumeratedValue>
                <enumeratedValue>
                  <name>1</name>
                  <description>TSI interrupt is enabled.</description>
                  <value>#1</value>
                </enumeratedValue>
              </enumeratedValues>
            </field>
            <field>
              <name>TSIEN</name>
              <description>Touch Sensing Input Module Enable</description>
              <bitOffset>7</bitOffset>
              <bitWidth>1</bitWidth>
              <access>read-write</access>
              <enumeratedValues>
                <enumeratedValue>
                  <name>0</name>
                  <description>TSI module disabled.</description>
                  <value>#0</value>
                </enumeratedValue>
                <enumeratedValue>
                  <name>1</name>
                  <description>TSI module enabled.</description>
                  <value>#1</value>
                </enumeratedValue>
              </enumeratedValues>
            </field>
            <field>
              <name>NSCN</name>
              <description>NSCN</description>
              <bitOffset>8</bitOffset>
              <bitWidth>5</bitWidth>
              <access>read-write</access>
              <enumeratedValues>
                <enumeratedValue>
                  <name>00000</name>
                  <description>Once per electrode</description>
                  <value>#00000</value>
                </enumeratedValue>
                <enumeratedValue>
                  <name>00001</name>
                  <description>Twice per electrode</description>
                  <value>#00001</value>
                </enumeratedValue>
                <enumeratedValue>
                  <name>00010</name>
                  <description>3 times per electrode</description>
                  <value>#00010</value>
                </enumeratedValue>
                <enumeratedValue>
                  <name>00011</name>
                  <description>4 times per electrode</description>
                  <value>#00011</value>
                </enumeratedValue>
                <enumeratedValue>
                  <name>00100</name>
                  <description>5 times per electrode</description>
                  <value>#00100</value>
                </enumeratedValue>
                <enumeratedValue>
                  <name>00101</name>
                  <description>6 times per electrode</description>
                  <value>#00101</value>
                </enumeratedValue>
                <enumeratedValue>
                  <name>00110</name>
                  <description>7 times per electrode</description>
                  <value>#00110</value>
                </enumeratedValue>
                <enumeratedValue>
                  <name>00111</name>
                  <description>8 times per electrode</description>
                  <value>#00111</value>
                </enumeratedValue>
                <enumeratedValue>
                  <name>01000</name>
                  <description>9 times per electrode</description>
                  <value>#01000</value>
                </enumeratedValue>
                <enumeratedValue>
                  <name>01001</name>
                  <description>10 times per electrode</description>
                  <value>#01001</value>
                </enumeratedValue>
                <enumeratedValue>
                  <name>01010</name>
                  <description>11 times per electrode</description>
                  <value>#01010</value>
                </enumeratedValue>
                <enumeratedValue>
                  <name>01011</name>
                  <description>12 times per electrode</description>
                  <value>#01011</value>
                </enumeratedValue>
                <enumeratedValue>
                  <name>01100</name>
                  <description>13 times per electrode</description>
                  <value>#01100</value>
                </enumeratedValue>
                <enumeratedValue>
                  <name>01101</name>
                  <description>14 times per electrode</description>
                  <value>#01101</value>
                </enumeratedValue>
                <enumeratedValue>
                  <name>01110</name>
                  <description>15 times per electrode</description>
                  <value>#01110</value>
                </enumeratedValue>
                <enumeratedValue>
                  <name>01111</name>
                  <description>16 times per electrode</description>
                  <value>#01111</value>
                </enumeratedValue>
                <enumeratedValue>
                  <name>10000</name>
                  <description>17 times per electrode</description>
                  <value>#10000</value>
                </enumeratedValue>
                <enumeratedValue>
                  <name>10001</name>
                  <description>18 times per electrode</description>
                  <value>#10001</value>
                </enumeratedValue>
                <enumeratedValue>
                  <name>10010</name>
                  <description>19 times per electrode</description>
                  <value>#10010</value>
                </enumeratedValue>
                <enumeratedValue>
                  <name>10011</name>
                  <description>20 times per electrode</description>
                  <value>#10011</value>
                </enumeratedValue>
                <enumeratedValue>
                  <name>10100</name>
                  <description>21 times per electrode</description>
                  <value>#10100</value>
                </enumeratedValue>
                <enumeratedValue>
                  <name>10101</name>
                  <description>22 times per electrode</description>
                  <value>#10101</value>
                </enumeratedValue>
                <enumeratedValue>
                  <name>10110</name>
                  <description>23 times per electrode</description>
                  <value>#10110</value>
                </enumeratedValue>
                <enumeratedValue>
                  <name>10111</name>
                  <description>24 times per electrode</description>
                  <value>#10111</value>
                </enumeratedValue>
                <enumeratedValue>
                  <name>11000</name>
                  <description>25 times per electrode</description>
                  <value>#11000</value>
                </enumeratedValue>
                <enumeratedValue>
                  <name>11001</name>
                  <description>26 times per electrode</description>
                  <value>#11001</value>
                </enumeratedValue>
                <enumeratedValue>
                  <name>11010</name>
                  <description>27 times per electrode</description>
                  <value>#11010</value>
                </enumeratedValue>
                <enumeratedValue>
                  <name>11011</name>
                  <description>28 times per electrode</description>
                  <value>#11011</value>
                </enumeratedValue>
                <enumeratedValue>
                  <name>11100</name>
                  <description>29 times per electrode</description>
                  <value>#11100</value>
                </enumeratedValue>
                <enumeratedValue>
                  <name>11101</name>
                  <description>30 times per electrode</description>
                  <value>#11101</value>
                </enumeratedValue>
                <enumeratedValue>
                  <name>11110</name>
                  <description>31 times per electrode</description>
                  <value>#11110</value>
                </enumeratedValue>
                <enumeratedValue>
                  <name>11111</name>
                  <description>32 times per electrode</description>
                  <value>#11111</value>
                </enumeratedValue>
              </enumeratedValues>
            </field>
            <field>
              <name>PS</name>
              <description>PS</description>
              <bitOffset>13</bitOffset>
              <bitWidth>3</bitWidth>
              <access>read-write</access>
              <enumeratedValues>
                <enumeratedValue>
                  <name>000</name>
                  <description>Electrode Oscillator Frequency divided by 1</description>
                  <value>#000</value>
                </enumeratedValue>
                <enumeratedValue>
                  <name>001</name>
                  <description>Electrode Oscillator Frequency divided by 2</description>
                  <value>#001</value>
                </enumeratedValue>
                <enumeratedValue>
                  <name>010</name>
                  <description>Electrode Oscillator Frequency divided by 4</description>
                  <value>#010</value>
                </enumeratedValue>
                <enumeratedValue>
                  <name>011</name>
                  <description>Electrode Oscillator Frequency divided by 8</description>
                  <value>#011</value>
                </enumeratedValue>
                <enumeratedValue>
                  <name>100</name>
                  <description>Electrode Oscillator Frequency divided by 16</description>
                  <value>#100</value>
                </enumeratedValue>
                <enumeratedValue>
                  <name>101</name>
                  <description>Electrode Oscillator Frequency divided by 32</description>
                  <value>#101</value>
                </enumeratedValue>
                <enumeratedValue>
                  <name>110</name>
                  <description>Electrode Oscillator Frequency divided by 64</description>
                  <value>#110</value>
                </enumeratedValue>
                <enumeratedValue>
                  <name>111</name>
                  <description>Electrode Oscillator Frequency divided by 128</description>
                  <value>#111</value>
                </enumeratedValue>
              </enumeratedValues>
            </field>
            <field>
              <name>EXTCHRG</name>
              <description>EXTCHRG</description>
              <bitOffset>16</bitOffset>
              <bitWidth>3</bitWidth>
              <access>read-write</access>
              <enumeratedValues>
                <enumeratedValue>
                  <name>000</name>
                  <description>500 nA.</description>
                  <value>#000</value>
                </enumeratedValue>
                <enumeratedValue>
                  <name>001</name>
                  <description>1 uA.</description>
                  <value>#001</value>
                </enumeratedValue>
                <enumeratedValue>
                  <name>010</name>
                  <description>2 uA.</description>
                  <value>#010</value>
                </enumeratedValue>
                <enumeratedValue>
                  <name>011</name>
                  <description>4 uA.</description>
                  <value>#011</value>
                </enumeratedValue>
                <enumeratedValue>
                  <name>100</name>
                  <description>8 uA.</description>
                  <value>#100</value>
                </enumeratedValue>
                <enumeratedValue>
                  <name>101</name>
                  <description>16 uA.</description>
                  <value>#101</value>
                </enumeratedValue>
                <enumeratedValue>
                  <name>110</name>
                  <description>32 uA.</description>
                  <value>#110</value>
                </enumeratedValue>
                <enumeratedValue>
                  <name>111</name>
                  <description>64 uA.</description>
                  <value>#111</value>
                </enumeratedValue>
              </enumeratedValues>
            </field>
            <field>
              <name>DVOLT</name>
              <description>DVOLT</description>
              <bitOffset>19</bitOffset>
              <bitWidth>2</bitWidth>
              <access>read-write</access>
              <enumeratedValues>
                <enumeratedValue>
                  <name>00</name>
                  <description>DV = 1.03 V; VP = 1.33 V; Vm = 0.30 V.</description>
                  <value>#00</value>
                </enumeratedValue>
                <enumeratedValue>
                  <name>01</name>
                  <description>DV = 0.73 V; VP = 1.18 V; Vm = 0.45 V.</description>
                  <value>#01</value>
                </enumeratedValue>
                <enumeratedValue>
                  <name>10</name>
                  <description>DV = 0.43 V; VP = 1.03 V; Vm = 0.60 V.</description>
                  <value>#10</value>
                </enumeratedValue>
                <enumeratedValue>
                  <name>11</name>
                  <description>DV = 0.29 V; VP = 0.95 V; Vm = 0.67 V.</description>
                  <value>#11</value>
                </enumeratedValue>
              </enumeratedValues>
            </field>
            <field>
              <name>REFCHRG</name>
              <description>REFCHRG</description>
              <bitOffset>21</bitOffset>
              <bitWidth>3</bitWidth>
              <access>read-write</access>
              <enumeratedValues>
                <enumeratedValue>
                  <name>000</name>
                  <description>500 nA.</description>
                  <value>#000</value>
                </enumeratedValue>
                <enumeratedValue>
                  <name>001</name>
                  <description>1 uA.</description>
                  <value>#001</value>
                </enumeratedValue>
                <enumeratedValue>
                  <name>010</name>
                  <description>2 uA.</description>
                  <value>#010</value>
                </enumeratedValue>
                <enumeratedValue>
                  <name>011</name>
                  <description>4 uA.</description>
                  <value>#011</value>
                </enumeratedValue>
                <enumeratedValue>
                  <name>100</name>
                  <description>8 uA.</description>
                  <value>#100</value>
                </enumeratedValue>
                <enumeratedValue>
                  <name>101</name>
                  <description>16 uA.</description>
                  <value>#101</value>
                </enumeratedValue>
                <enumeratedValue>
                  <name>110</name>
                  <description>32 uA.</description>
                  <value>#110</value>
                </enumeratedValue>
                <enumeratedValue>
                  <name>111</name>
                  <description>64 uA.</description>
                  <value>#111</value>
                </enumeratedValue>
              </enumeratedValues>
            </field>
            <field>
              <name>MODE</name>
              <description>TSI analog modes setup and status bits.</description>
              <bitOffset>24</bitOffset>
              <bitWidth>4</bitWidth>
              <access>read-write</access>
              <enumeratedValues>
                <enumeratedValue>
                  <name>0000</name>
                  <description>Set TSI in capacitive sensing(non-noise detection) mode.</description>
                  <value>#0000</value>
                </enumeratedValue>
                <enumeratedValue>
                  <name>0100</name>
                  <description>Set TSI analog to work in single threshold noise detection mode and the frequency limitation circuit is disabled.</description>
                  <value>#0100</value>
                </enumeratedValue>
                <enumeratedValue>
                  <name>1000</name>
                  <description>Set TSI analog to work in single threshold noise detection mode and the frequency limitation circuit is enabled to work in higher frequencies operations.</description>
                  <value>#1000</value>
                </enumeratedValue>
                <enumeratedValue>
                  <name>1100</name>
                  <description>Set TSI analog to work in automatic noise detection mode.</description>
                  <value>#1100</value>
                </enumeratedValue>
              </enumeratedValues>
            </field>
            <field>
              <name>ESOR</name>
              <description>End-of-scan or Out-of-Range Interrupt Selection</description>
              <bitOffset>28</bitOffset>
              <bitWidth>1</bitWidth>
              <access>read-write</access>
              <enumeratedValues>
                <enumeratedValue>
                  <name>0</name>
                  <description>Out-of-range interrupt is allowed.</description>
                  <value>#0</value>
                </enumeratedValue>
                <enumeratedValue>
                  <name>1</name>
                  <description>End-of-scan interrupt is allowed.</description>
                  <value>#1</value>
                </enumeratedValue>
              </enumeratedValues>
            </field>
            <field>
              <name>OUTRGF</name>
              <description>Out of Range Flag.</description>
              <bitOffset>31</bitOffset>
              <bitWidth>1</bitWidth>
              <access>read-write</access>
            </field>
          </fields>
        </register>
        <register>
          <name>DATA</name>
          <description>TSI DATA Register</description>
          <addressOffset>0x4</addressOffset>
          <size>32</size>
          <access>read-write</access>
          <resetValue>0</resetValue>
          <resetMask>0xFFFFFFFF</resetMask>
          <fields>
            <field>
              <name>TSICNT</name>
              <description>TSI Conversion Counter Value</description>
              <bitOffset>0</bitOffset>
              <bitWidth>16</bitWidth>
              <access>read-only</access>
            </field>
            <field>
              <name>SWTS</name>
              <description>Software Trigger Start</description>
              <bitOffset>22</bitOffset>
              <bitWidth>1</bitWidth>
              <access>write-only</access>
              <enumeratedValues>
                <enumeratedValue>
                  <name>0</name>
                  <description>No effect.</description>
                  <value>#0</value>
                </enumeratedValue>
                <enumeratedValue>
                  <name>1</name>
                  <description>Start a scan to determine which channel is specified by TSI_DATA[TSICH].</description>
                  <value>#1</value>
                </enumeratedValue>
              </enumeratedValues>
            </field>
            <field>
              <name>DMAEN</name>
              <description>DMA Transfer Enabled</description>
              <bitOffset>23</bitOffset>
              <bitWidth>1</bitWidth>
              <access>read-write</access>
              <enumeratedValues>
                <enumeratedValue>
                  <name>0</name>
                  <description>Interrupt is selected when the interrupt enable bit is set and the corresponding TSI events assert.</description>
                  <value>#0</value>
                </enumeratedValue>
                <enumeratedValue>
                  <name>1</name>
                  <description>DMA transfer request is selected when the interrupt enable bit is set and the corresponding TSI events assert.</description>
                  <value>#1</value>
                </enumeratedValue>
              </enumeratedValues>
            </field>
            <field>
              <name>TSICH</name>
              <description>TSICH</description>
              <bitOffset>28</bitOffset>
              <bitWidth>4</bitWidth>
              <access>read-write</access>
              <enumeratedValues>
                <enumeratedValue>
                  <name>0000</name>
                  <description>Channel 0.</description>
                  <value>#0000</value>
                </enumeratedValue>
                <enumeratedValue>
                  <name>0001</name>
                  <description>Channel 1.</description>
                  <value>#0001</value>
                </enumeratedValue>
                <enumeratedValue>
                  <name>0010</name>
                  <description>Channel 2.</description>
                  <value>#0010</value>
                </enumeratedValue>
                <enumeratedValue>
                  <name>0011</name>
                  <description>Channel 3.</description>
                  <value>#0011</value>
                </enumeratedValue>
                <enumeratedValue>
                  <name>0100</name>
                  <description>Channel 4.</description>
                  <value>#0100</value>
                </enumeratedValue>
                <enumeratedValue>
                  <name>0101</name>
                  <description>Channel 5.</description>
                  <value>#0101</value>
                </enumeratedValue>
                <enumeratedValue>
                  <name>0110</name>
                  <description>Channel 6.</description>
                  <value>#0110</value>
                </enumeratedValue>
                <enumeratedValue>
                  <name>0111</name>
                  <description>Channel 7.</description>
                  <value>#0111</value>
                </enumeratedValue>
                <enumeratedValue>
                  <name>1000</name>
                  <description>Channel 8.</description>
                  <value>#1000</value>
                </enumeratedValue>
                <enumeratedValue>
                  <name>1001</name>
                  <description>Channel 9.</description>
                  <value>#1001</value>
                </enumeratedValue>
                <enumeratedValue>
                  <name>1010</name>
                  <description>Channel 10.</description>
                  <value>#1010</value>
                </enumeratedValue>
                <enumeratedValue>
                  <name>1011</name>
                  <description>Channel 11.</description>
                  <value>#1011</value>
                </enumeratedValue>
                <enumeratedValue>
                  <name>1100</name>
                  <description>Channel 12.</description>
                  <value>#1100</value>
                </enumeratedValue>
                <enumeratedValue>
                  <name>1101</name>
                  <description>Channel 13.</description>
                  <value>#1101</value>
                </enumeratedValue>
                <enumeratedValue>
                  <name>1110</name>
                  <description>Channel 14.</description>
                  <value>#1110</value>
                </enumeratedValue>
                <enumeratedValue>
                  <name>1111</name>
                  <description>Channel 15.</description>
                  <value>#1111</value>
                </enumeratedValue>
              </enumeratedValues>
            </field>
          </fields>
        </register>
        <register>
          <name>TSHD</name>
          <description>TSI Threshold Register</description>
          <addressOffset>0x8</addressOffset>
          <size>32</size>
          <access>read-write</access>
          <resetValue>0</resetValue>
          <resetMask>0xFFFFFFFF</resetMask>
          <fields>
            <field>
              <name>THRESL</name>
              <description>TSI Wakeup Channel Low-threshold</description>
              <bitOffset>0</bitOffset>
              <bitWidth>16</bitWidth>
              <access>read-write</access>
            </field>
            <field>
              <name>THRESH</name>
              <description>TSI Wakeup Channel High-threshold</description>
              <bitOffset>16</bitOffset>
              <bitWidth>16</bitWidth>
              <access>read-write</access>
            </field>
          </fields>
        </register>
      </registers>
    </peripheral>
    <peripheral>
      <name>SIM</name>
      <description>System Integration Module</description>
      <prependToName>SIM_</prependToName>
      <baseAddress>0x40047000</baseAddress>
      <addressBlock>
        <offset>0</offset>
        <size>0x1108</size>
        <usage>registers</usage>
      </addressBlock>
      <registers>
        <register>
          <name>SOPT1</name>
          <description>System Options Register 1</description>
          <addressOffset>0</addressOffset>
          <size>32</size>
          <access>read-write</access>
          <resetValue>0x80000000</resetValue>
          <resetMask>0xFFFFFFFF</resetMask>
          <fields>
            <field>
              <name>OSC32KSEL</name>
              <description>32K Oscillator Clock Select</description>
              <bitOffset>18</bitOffset>
              <bitWidth>2</bitWidth>
              <access>read-write</access>
              <enumeratedValues>
                <enumeratedValue>
                  <name>00</name>
                  <description>System oscillator (OSC32KCLK)</description>
                  <value>#00</value>
                </enumeratedValue>
                <enumeratedValue>
                  <name>10</name>
                  <description>RTC_CLKIN</description>
                  <value>#10</value>
                </enumeratedValue>
                <enumeratedValue>
                  <name>11</name>
                  <description>LPO 1kHz</description>
                  <value>#11</value>
                </enumeratedValue>
              </enumeratedValues>
            </field>
            <field>
              <name>USBVSTBY</name>
              <description>USB voltage regulator in standby mode during VLPR and VLPW modes</description>
              <bitOffset>29</bitOffset>
              <bitWidth>1</bitWidth>
              <access>read-write</access>
              <enumeratedValues>
                <enumeratedValue>
                  <name>0</name>
                  <description>USB voltage regulator not in standby during VLPR and VLPW modes.</description>
                  <value>#0</value>
                </enumeratedValue>
                <enumeratedValue>
                  <name>1</name>
                  <description>USB voltage regulator in standby during VLPR and VLPW modes.</description>
                  <value>#1</value>
                </enumeratedValue>
              </enumeratedValues>
            </field>
            <field>
              <name>USBSSTBY</name>
              <description>USB voltage regulator in standby mode during Stop, VLPS, LLS and VLLS modes.</description>
              <bitOffset>30</bitOffset>
              <bitWidth>1</bitWidth>
              <access>read-write</access>
              <enumeratedValues>
                <enumeratedValue>
                  <name>0</name>
                  <description>USB voltage regulator not in standby during Stop, VLPS, LLS and VLLS modes.</description>
                  <value>#0</value>
                </enumeratedValue>
                <enumeratedValue>
                  <name>1</name>
                  <description>USB voltage regulator in standby during Stop, VLPS, LLS and VLLS modes.</description>
                  <value>#1</value>
                </enumeratedValue>
              </enumeratedValues>
            </field>
            <field>
              <name>USBREGEN</name>
              <description>USB voltage regulator enable</description>
              <bitOffset>31</bitOffset>
              <bitWidth>1</bitWidth>
              <access>read-write</access>
              <enumeratedValues>
                <enumeratedValue>
                  <name>0</name>
                  <description>USB voltage regulator is disabled.</description>
                  <value>#0</value>
                </enumeratedValue>
                <enumeratedValue>
                  <name>1</name>
                  <description>USB voltage regulator is enabled.</description>
                  <value>#1</value>
                </enumeratedValue>
              </enumeratedValues>
            </field>
          </fields>
        </register>
        <register>
          <name>SOPT1CFG</name>
          <description>SOPT1 Configuration Register</description>
          <addressOffset>0x4</addressOffset>
          <size>32</size>
          <access>read-write</access>
          <resetValue>0</resetValue>
          <resetMask>0xFFFFFFFF</resetMask>
          <fields>
            <field>
              <name>URWE</name>
              <description>USB voltage regulator enable write enable</description>
              <bitOffset>24</bitOffset>
              <bitWidth>1</bitWidth>
              <access>read-write</access>
              <enumeratedValues>
                <enumeratedValue>
                  <name>0</name>
                  <description>SOPT1 USBREGEN cannot be written.</description>
                  <value>#0</value>
                </enumeratedValue>
                <enumeratedValue>
                  <name>1</name>
                  <description>SOPT1 USBREGEN can be written.</description>
                  <value>#1</value>
                </enumeratedValue>
              </enumeratedValues>
            </field>
            <field>
              <name>UVSWE</name>
              <description>USB voltage regulator VLP standby write enable</description>
              <bitOffset>25</bitOffset>
              <bitWidth>1</bitWidth>
              <access>read-write</access>
              <enumeratedValues>
                <enumeratedValue>
                  <name>0</name>
                  <description>SOPT1 USBVSTB cannot be written.</description>
                  <value>#0</value>
                </enumeratedValue>
                <enumeratedValue>
                  <name>1</name>
                  <description>SOPT1 USBVSTB can be written.</description>
                  <value>#1</value>
                </enumeratedValue>
              </enumeratedValues>
            </field>
            <field>
              <name>USSWE</name>
              <description>USB voltage regulator stop standby write enable</description>
              <bitOffset>26</bitOffset>
              <bitWidth>1</bitWidth>
              <access>read-write</access>
              <enumeratedValues>
                <enumeratedValue>
                  <name>0</name>
                  <description>SOPT1 USBSSTB cannot be written.</description>
                  <value>#0</value>
                </enumeratedValue>
                <enumeratedValue>
                  <name>1</name>
                  <description>SOPT1 USBSSTB can be written.</description>
                  <value>#1</value>
                </enumeratedValue>
              </enumeratedValues>
            </field>
          </fields>
        </register>
        <register>
          <name>SOPT2</name>
          <description>System Options Register 2</description>
          <addressOffset>0x1004</addressOffset>
          <size>32</size>
          <access>read-write</access>
          <resetValue>0</resetValue>
          <resetMask>0xFFFFFFFF</resetMask>
          <fields>
            <field>
              <name>RTCCLKOUTSEL</name>
              <description>RTC Clock Out Select</description>
              <bitOffset>4</bitOffset>
              <bitWidth>1</bitWidth>
              <access>read-write</access>
              <enumeratedValues>
                <enumeratedValue>
                  <name>0</name>
                  <description>RTC 1 Hz clock is output on the RTC_CLKOUT pin.</description>
                  <value>#0</value>
                </enumeratedValue>
                <enumeratedValue>
                  <name>1</name>
                  <description>OSCERCLK clock is output on the RTC_CLKOUT pin.</description>
                  <value>#1</value>
                </enumeratedValue>
              </enumeratedValues>
            </field>
            <field>
              <name>CLKOUTSEL</name>
              <description>CLKOUT select</description>
              <bitOffset>5</bitOffset>
              <bitWidth>3</bitWidth>
              <access>read-write</access>
              <enumeratedValues>
                <enumeratedValue>
                  <name>010</name>
                  <description>Bus clock</description>
                  <value>#010</value>
                </enumeratedValue>
                <enumeratedValue>
                  <name>011</name>
                  <description>LPO clock (1 kHz)</description>
                  <value>#011</value>
                </enumeratedValue>
                <enumeratedValue>
                  <name>100</name>
                  <description>MCGIRCLK</description>
                  <value>#100</value>
                </enumeratedValue>
                <enumeratedValue>
                  <name>110</name>
                  <description>OSCERCLK</description>
                  <value>#110</value>
                </enumeratedValue>
              </enumeratedValues>
            </field>
            <field>
              <name>PLLFLLSEL</name>
              <description>PLL/FLL clock select</description>
              <bitOffset>16</bitOffset>
              <bitWidth>1</bitWidth>
              <access>read-write</access>
              <enumeratedValues>
                <enumeratedValue>
                  <name>0</name>
                  <description>MCGFLLCLK clock</description>
                  <value>#0</value>
                </enumeratedValue>
                <enumeratedValue>
                  <name>1</name>
                  <description>MCGPLLCLK clock with fixed divide by 2</description>
                  <value>#1</value>
                </enumeratedValue>
              </enumeratedValues>
            </field>
            <field>
              <name>USBSRC</name>
              <description>USB clock source select</description>
              <bitOffset>18</bitOffset>
              <bitWidth>1</bitWidth>
              <access>read-write</access>
              <enumeratedValues>
                <enumeratedValue>
                  <name>0</name>
                  <description>External bypass clock (USB_CLKIN).</description>
                  <value>#0</value>
                </enumeratedValue>
                <enumeratedValue>
                  <name>1</name>
                  <description>MCGFLLCLK clock , or MCGPLLCLK/2 clock</description>
                  <value>#1</value>
                </enumeratedValue>
              </enumeratedValues>
            </field>
            <field>
              <name>TPMSRC</name>
              <description>TPM Clock Source Select</description>
              <bitOffset>24</bitOffset>
              <bitWidth>2</bitWidth>
              <access>read-write</access>
              <enumeratedValues>
                <enumeratedValue>
                  <name>00</name>
                  <description>Clock disabled</description>
                  <value>#00</value>
                </enumeratedValue>
                <enumeratedValue>
                  <name>01</name>
                  <description>MCGFLLCLK clock , or MCGPLLCLK/2</description>
                  <value>#01</value>
                </enumeratedValue>
                <enumeratedValue>
                  <name>10</name>
                  <description>OSCERCLK clock</description>
                  <value>#10</value>
                </enumeratedValue>
                <enumeratedValue>
                  <name>11</name>
                  <description>MCGIRCLK clock</description>
                  <value>#11</value>
                </enumeratedValue>
              </enumeratedValues>
            </field>
            <field>
              <name>UART0SRC</name>
              <description>UART0 Clock Source Select</description>
              <bitOffset>26</bitOffset>
              <bitWidth>2</bitWidth>
              <access>read-write</access>
              <enumeratedValues>
                <enumeratedValue>
                  <name>00</name>
                  <description>Clock disabled</description>
                  <value>#00</value>
                </enumeratedValue>
                <enumeratedValue>
                  <name>01</name>
                  <description>MCGFLLCLK clock , or MCGPLLCLK/2</description>
                  <value>#01</value>
                </enumeratedValue>
                <enumeratedValue>
                  <name>10</name>
                  <description>OSCERCLK clock</description>
                  <value>#10</value>
                </enumeratedValue>
                <enumeratedValue>
                  <name>11</name>
                  <description>MCGIRCLK clock</description>
                  <value>#11</value>
                </enumeratedValue>
              </enumeratedValues>
            </field>
          </fields>
        </register>
        <register>
          <name>SOPT4</name>
          <description>System Options Register 4</description>
          <addressOffset>0x100C</addressOffset>
          <size>32</size>
          <access>read-write</access>
          <resetValue>0</resetValue>
          <resetMask>0xFFFFFFFF</resetMask>
          <fields>
            <field>
              <name>TPM1CH0SRC</name>
              <description>TPM1 channel 0 input capture source select</description>
              <bitOffset>18</bitOffset>
              <bitWidth>2</bitWidth>
              <access>read-write</access>
              <enumeratedValues>
                <enumeratedValue>
                  <name>00</name>
                  <description>TPM1_CH0 signal</description>
                  <value>#00</value>
                </enumeratedValue>
                <enumeratedValue>
                  <name>01</name>
                  <description>CMP0 output</description>
                  <value>#01</value>
                </enumeratedValue>
                <enumeratedValue>
                  <name>11</name>
                  <description>USB start of frame pulse</description>
                  <value>#11</value>
                </enumeratedValue>
              </enumeratedValues>
            </field>
            <field>
              <name>TPM2CH0SRC</name>
              <description>TPM2 Channel 0 Input Capture Source Select</description>
              <bitOffset>20</bitOffset>
              <bitWidth>1</bitWidth>
              <access>read-write</access>
              <enumeratedValues>
                <enumeratedValue>
                  <name>0</name>
                  <description>TPM2_CH0 signal</description>
                  <value>#0</value>
                </enumeratedValue>
                <enumeratedValue>
                  <name>1</name>
                  <description>CMP0 output</description>
                  <value>#1</value>
                </enumeratedValue>
              </enumeratedValues>
            </field>
            <field>
              <name>TPM0CLKSEL</name>
              <description>TPM0 External Clock Pin Select</description>
              <bitOffset>24</bitOffset>
              <bitWidth>1</bitWidth>
              <access>read-write</access>
              <enumeratedValues>
                <enumeratedValue>
                  <name>0</name>
                  <description>TPM0 external clock driven by TPM_CLKIN0 pin.</description>
                  <value>#0</value>
                </enumeratedValue>
                <enumeratedValue>
                  <name>1</name>
                  <description>TPM0 external clock driven by TPM_CLKIN1 pin.</description>
                  <value>#1</value>
                </enumeratedValue>
              </enumeratedValues>
            </field>
            <field>
              <name>TPM1CLKSEL</name>
              <description>TPM1 External Clock Pin Select</description>
              <bitOffset>25</bitOffset>
              <bitWidth>1</bitWidth>
              <access>read-write</access>
              <enumeratedValues>
                <enumeratedValue>
                  <name>0</name>
                  <description>TPM1 external clock driven by TPM_CLKIN0 pin.</description>
                  <value>#0</value>
                </enumeratedValue>
                <enumeratedValue>
                  <name>1</name>
                  <description>TPM1 external clock driven by TPM_CLKIN1 pin.</description>
                  <value>#1</value>
                </enumeratedValue>
              </enumeratedValues>
            </field>
            <field>
              <name>TPM2CLKSEL</name>
              <description>TPM2 External Clock Pin Select</description>
              <bitOffset>26</bitOffset>
              <bitWidth>1</bitWidth>
              <access>read-write</access>
              <enumeratedValues>
                <enumeratedValue>
                  <name>0</name>
                  <description>TPM2 external clock driven by TPM_CLKIN0 pin.</description>
                  <value>#0</value>
                </enumeratedValue>
                <enumeratedValue>
                  <name>1</name>
                  <description>TPM2 external clock driven by TPM_CLKIN1 pin.</description>
                  <value>#1</value>
                </enumeratedValue>
              </enumeratedValues>
            </field>
          </fields>
        </register>
        <register>
          <name>SOPT5</name>
          <description>System Options Register 5</description>
          <addressOffset>0x1010</addressOffset>
          <size>32</size>
          <access>read-write</access>
          <resetValue>0</resetValue>
          <resetMask>0xFFFFFFFF</resetMask>
          <fields>
            <field>
              <name>UART0TXSRC</name>
              <description>UART0 Transmit Data Source Select</description>
              <bitOffset>0</bitOffset>
              <bitWidth>2</bitWidth>
              <access>read-write</access>
              <enumeratedValues>
                <enumeratedValue>
                  <name>00</name>
                  <description>UART0_TX pin</description>
                  <value>#00</value>
                </enumeratedValue>
                <enumeratedValue>
                  <name>01</name>
                  <description>UART0_TX pin modulated with TPM1 channel 0 output</description>
                  <value>#01</value>
                </enumeratedValue>
                <enumeratedValue>
                  <name>10</name>
                  <description>UART0_TX pin modulated with TPM2 channel 0 output</description>
                  <value>#10</value>
                </enumeratedValue>
              </enumeratedValues>
            </field>
            <field>
              <name>UART0RXSRC</name>
              <description>UART0 Receive Data Source Select</description>
              <bitOffset>2</bitOffset>
              <bitWidth>1</bitWidth>
              <access>read-write</access>
              <enumeratedValues>
                <enumeratedValue>
                  <name>0</name>
                  <description>UART_RX pin</description>
                  <value>#0</value>
                </enumeratedValue>
                <enumeratedValue>
                  <name>1</name>
                  <description>CMP0 output</description>
                  <value>#1</value>
                </enumeratedValue>
              </enumeratedValues>
            </field>
            <field>
              <name>UART1TXSRC</name>
              <description>UART1 Transmit Data Source Select</description>
              <bitOffset>4</bitOffset>
              <bitWidth>2</bitWidth>
              <access>read-write</access>
              <enumeratedValues>
                <enumeratedValue>
                  <name>00</name>
                  <description>UART1_TX pin</description>
                  <value>#00</value>
                </enumeratedValue>
                <enumeratedValue>
                  <name>01</name>
                  <description>UART1_TX pin modulated with TPM1 channel 0 output</description>
                  <value>#01</value>
                </enumeratedValue>
                <enumeratedValue>
                  <name>10</name>
                  <description>UART1_TX pin modulated with TPM2 channel 0 output</description>
                  <value>#10</value>
                </enumeratedValue>
              </enumeratedValues>
            </field>
            <field>
              <name>UART1RXSRC</name>
              <description>UART1 Receive Data Source Select</description>
              <bitOffset>6</bitOffset>
              <bitWidth>1</bitWidth>
              <access>read-write</access>
              <enumeratedValues>
                <enumeratedValue>
                  <name>0</name>
                  <description>UART1_RX pin</description>
                  <value>#0</value>
                </enumeratedValue>
                <enumeratedValue>
                  <name>1</name>
                  <description>CMP0 output</description>
                  <value>#1</value>
                </enumeratedValue>
              </enumeratedValues>
            </field>
            <field>
              <name>UART0ODE</name>
              <description>UART0 Open Drain Enable</description>
              <bitOffset>16</bitOffset>
              <bitWidth>1</bitWidth>
              <access>read-write</access>
              <enumeratedValues>
                <enumeratedValue>
                  <name>0</name>
                  <description>Open drain is disabled on UART0.</description>
                  <value>#0</value>
                </enumeratedValue>
                <enumeratedValue>
                  <name>1</name>
                  <description>Open drain is enabled on UART0.</description>
                  <value>#1</value>
                </enumeratedValue>
              </enumeratedValues>
            </field>
            <field>
              <name>UART1ODE</name>
              <description>UART1 Open Drain Enable</description>
              <bitOffset>17</bitOffset>
              <bitWidth>1</bitWidth>
              <access>read-write</access>
              <enumeratedValues>
                <enumeratedValue>
                  <name>0</name>
                  <description>Open drain is disabled on UART1.</description>
                  <value>#0</value>
                </enumeratedValue>
                <enumeratedValue>
                  <name>1</name>
                  <description>Open drain is enabled on UART1</description>
                  <value>#1</value>
                </enumeratedValue>
              </enumeratedValues>
            </field>
            <field>
              <name>UART2ODE</name>
              <description>UART2 Open Drain Enable</description>
              <bitOffset>18</bitOffset>
              <bitWidth>1</bitWidth>
              <access>read-write</access>
              <enumeratedValues>
                <enumeratedValue>
                  <name>0</name>
                  <description>Open drain is disabled on UART2</description>
                  <value>#0</value>
                </enumeratedValue>
                <enumeratedValue>
                  <name>1</name>
                  <description>Open drain is enabled on UART2</description>
                  <value>#1</value>
                </enumeratedValue>
              </enumeratedValues>
            </field>
          </fields>
        </register>
        <register>
          <name>SOPT7</name>
          <description>System Options Register 7</description>
          <addressOffset>0x1018</addressOffset>
          <size>32</size>
          <access>read-write</access>
          <resetValue>0</resetValue>
          <resetMask>0xFFFFFFFF</resetMask>
          <fields>
            <field>
              <name>ADC0TRGSEL</name>
              <description>ADC0 Trigger Select</description>
              <bitOffset>0</bitOffset>
              <bitWidth>4</bitWidth>
              <access>read-write</access>
              <enumeratedValues>
                <enumeratedValue>
                  <name>0000</name>
                  <description>External trigger pin input (EXTRG_IN)</description>
                  <value>#0000</value>
                </enumeratedValue>
                <enumeratedValue>
                  <name>0001</name>
                  <description>CMP0 output</description>
                  <value>#0001</value>
                </enumeratedValue>
                <enumeratedValue>
                  <name>0100</name>
                  <description>PIT trigger 0</description>
                  <value>#0100</value>
                </enumeratedValue>
                <enumeratedValue>
                  <name>0101</name>
                  <description>PIT trigger 1</description>
                  <value>#0101</value>
                </enumeratedValue>
                <enumeratedValue>
                  <name>1000</name>
                  <description>TPM0 overflow</description>
                  <value>#1000</value>
                </enumeratedValue>
                <enumeratedValue>
                  <name>1001</name>
                  <description>TPM1 overflow</description>
                  <value>#1001</value>
                </enumeratedValue>
                <enumeratedValue>
                  <name>1010</name>
                  <description>TPM2 overflow</description>
                  <value>#1010</value>
                </enumeratedValue>
                <enumeratedValue>
                  <name>1100</name>
                  <description>RTC alarm</description>
                  <value>#1100</value>
                </enumeratedValue>
                <enumeratedValue>
                  <name>1101</name>
                  <description>RTC seconds</description>
                  <value>#1101</value>
                </enumeratedValue>
                <enumeratedValue>
                  <name>1110</name>
                  <description>LPTMR0 trigger</description>
                  <value>#1110</value>
                </enumeratedValue>
              </enumeratedValues>
            </field>
            <field>
              <name>ADC0PRETRGSEL</name>
              <description>ADC0 Pretrigger Select</description>
              <bitOffset>4</bitOffset>
              <bitWidth>1</bitWidth>
              <access>read-write</access>
              <enumeratedValues>
                <enumeratedValue>
                  <name>0</name>
                  <description>Pre-trigger A</description>
                  <value>#0</value>
                </enumeratedValue>
                <enumeratedValue>
                  <name>1</name>
                  <description>Pre-trigger B</description>
                  <value>#1</value>
                </enumeratedValue>
              </enumeratedValues>
            </field>
            <field>
              <name>ADC0ALTTRGEN</name>
              <description>ADC0 Alternate Trigger Enable</description>
              <bitOffset>7</bitOffset>
              <bitWidth>1</bitWidth>
              <access>read-write</access>
              <enumeratedValues>
                <enumeratedValue>
                  <name>0</name>
                  <description>TPM1 channel 0 (A) and channel 1 (B) triggers selected for ADC0.</description>
                  <value>#0</value>
                </enumeratedValue>
                <enumeratedValue>
                  <name>1</name>
                  <description>Alternate trigger selected for ADC0.</description>
                  <value>#1</value>
                </enumeratedValue>
              </enumeratedValues>
            </field>
          </fields>
        </register>
        <register>
          <name>SDID</name>
          <description>System Device Identification Register</description>
          <addressOffset>0x1024</addressOffset>
          <size>32</size>
          <access>read-only</access>
          <resetValue>0x100500</resetValue>
          <resetMask>0xFFFFFFFF</resetMask>
          <fields>
            <field>
              <name>PINID</name>
              <description>Pincount Identification</description>
              <bitOffset>0</bitOffset>
              <bitWidth>4</bitWidth>
              <access>read-only</access>
              <enumeratedValues>
                <enumeratedValue>
                  <name>0000</name>
                  <description>16-pin</description>
                  <value>#0000</value>
                </enumeratedValue>
                <enumeratedValue>
                  <name>0001</name>
                  <description>24-pin</description>
                  <value>#0001</value>
                </enumeratedValue>
                <enumeratedValue>
                  <name>0010</name>
                  <description>32-pin</description>
                  <value>#0010</value>
                </enumeratedValue>
                <enumeratedValue>
                  <name>0011</name>
                  <description>36-pin</description>
                  <value>#0011</value>
                </enumeratedValue>
                <enumeratedValue>
                  <name>0100</name>
                  <description>48-pin</description>
                  <value>#0100</value>
                </enumeratedValue>
                <enumeratedValue>
                  <name>0101</name>
                  <description>64-pin</description>
                  <value>#0101</value>
                </enumeratedValue>
                <enumeratedValue>
                  <name>0110</name>
                  <description>80-pin</description>
                  <value>#0110</value>
                </enumeratedValue>
                <enumeratedValue>
                  <name>1000</name>
                  <description>100-pin</description>
                  <value>#1000</value>
                </enumeratedValue>
                <enumeratedValue>
                  <name>1011</name>
                  <description>Custom pinout (WLCSP)</description>
                  <value>#1011</value>
                </enumeratedValue>
              </enumeratedValues>
            </field>
            <field>
              <name>DIEID</name>
              <description>Device Die Number</description>
              <bitOffset>7</bitOffset>
              <bitWidth>5</bitWidth>
              <access>read-only</access>
            </field>
            <field>
              <name>REVID</name>
              <description>Device Revision Number</description>
              <bitOffset>12</bitOffset>
              <bitWidth>4</bitWidth>
              <access>read-only</access>
            </field>
            <field>
              <name>SRAMSIZE</name>
              <description>System SRAM Size</description>
              <bitOffset>16</bitOffset>
              <bitWidth>4</bitWidth>
              <access>read-only</access>
              <enumeratedValues>
                <enumeratedValue>
                  <name>0000</name>
                  <description>0.5 KB</description>
                  <value>#0000</value>
                </enumeratedValue>
                <enumeratedValue>
                  <name>0001</name>
                  <description>1 KB</description>
                  <value>#0001</value>
                </enumeratedValue>
                <enumeratedValue>
                  <name>0010</name>
                  <description>2 KB</description>
                  <value>#0010</value>
                </enumeratedValue>
                <enumeratedValue>
                  <name>0011</name>
                  <description>4 KB</description>
                  <value>#0011</value>
                </enumeratedValue>
                <enumeratedValue>
                  <name>0100</name>
                  <description>8 KB</description>
                  <value>#0100</value>
                </enumeratedValue>
                <enumeratedValue>
                  <name>0101</name>
                  <description>16 KB</description>
                  <value>#0101</value>
                </enumeratedValue>
                <enumeratedValue>
                  <name>0110</name>
                  <description>32 KB</description>
                  <value>#0110</value>
                </enumeratedValue>
                <enumeratedValue>
                  <name>0111</name>
                  <description>64 KB</description>
                  <value>#0111</value>
                </enumeratedValue>
              </enumeratedValues>
            </field>
            <field>
              <name>SERIESID</name>
              <description>Kinetis Series ID</description>
              <bitOffset>20</bitOffset>
              <bitWidth>4</bitWidth>
              <access>read-only</access>
              <enumeratedValues>
                <enumeratedValue>
                  <name>0001</name>
                  <description>KL family</description>
                  <value>#0001</value>
                </enumeratedValue>
              </enumeratedValues>
            </field>
            <field>
              <name>SUBFAMID</name>
              <description>Kinetis Sub-Family ID</description>
              <bitOffset>24</bitOffset>
              <bitWidth>4</bitWidth>
              <access>read-only</access>
              <enumeratedValues>
                <enumeratedValue>
                  <name>0010</name>
                  <description>KLx2 Subfamily</description>
                  <value>#0010</value>
                </enumeratedValue>
                <enumeratedValue>
                  <name>0011</name>
                  <description>KLx3 Subfamily</description>
                  <value>#0011</value>
                </enumeratedValue>
                <enumeratedValue>
                  <name>0100</name>
                  <description>KLx4 Subfamily</description>
                  <value>#0100</value>
                </enumeratedValue>
                <enumeratedValue>
                  <name>0101</name>
                  <description>KLx5 Subfamily</description>
                  <value>#0101</value>
                </enumeratedValue>
                <enumeratedValue>
                  <name>0110</name>
                  <description>KLx6 Subfamily</description>
                  <value>#0110</value>
                </enumeratedValue>
                <enumeratedValue>
                  <name>0111</name>
                  <description>KLx7 Subfamily</description>
                  <value>#0111</value>
                </enumeratedValue>
              </enumeratedValues>
            </field>
            <field>
              <name>FAMID</name>
              <description>Kinetis family ID</description>
              <bitOffset>28</bitOffset>
              <bitWidth>4</bitWidth>
              <access>read-only</access>
              <enumeratedValues>
                <enumeratedValue>
                  <name>0000</name>
                  <description>KL0x Family (low end)</description>
                  <value>#0000</value>
                </enumeratedValue>
                <enumeratedValue>
                  <name>0001</name>
                  <description>KL1x Family (basic)</description>
                  <value>#0001</value>
                </enumeratedValue>
                <enumeratedValue>
                  <name>0010</name>
                  <description>KL2x Family (USB)</description>
                  <value>#0010</value>
                </enumeratedValue>
                <enumeratedValue>
                  <name>0011</name>
                  <description>KL3x Family (Segment LCD)</description>
                  <value>#0011</value>
                </enumeratedValue>
                <enumeratedValue>
                  <name>0100</name>
                  <description>KL4x Family (USB and Segment LCD)</description>
                  <value>#0100</value>
                </enumeratedValue>
              </enumeratedValues>
            </field>
          </fields>
        </register>
        <register>
          <name>SCGC4</name>
          <description>System Clock Gating Control Register 4</description>
          <addressOffset>0x1034</addressOffset>
          <size>32</size>
          <access>read-write</access>
          <resetValue>0xF0000030</resetValue>
          <resetMask>0xFFFFFFFF</resetMask>
          <fields>
            <field>
              <name>I2C0</name>
              <description>I2C0 Clock Gate Control</description>
              <bitOffset>6</bitOffset>
              <bitWidth>1</bitWidth>
              <access>read-write</access>
              <enumeratedValues>
                <enumeratedValue>
                  <name>0</name>
                  <description>Clock disabled</description>
                  <value>#0</value>
                </enumeratedValue>
                <enumeratedValue>
                  <name>1</name>
                  <description>Clock enabled</description>
                  <value>#1</value>
                </enumeratedValue>
              </enumeratedValues>
            </field>
            <field>
              <name>I2C1</name>
              <description>I2C1 Clock Gate Control</description>
              <bitOffset>7</bitOffset>
              <bitWidth>1</bitWidth>
              <access>read-write</access>
              <enumeratedValues>
                <enumeratedValue>
                  <name>0</name>
                  <description>Clock disabled</description>
                  <value>#0</value>
                </enumeratedValue>
                <enumeratedValue>
                  <name>1</name>
                  <description>Clock enabled</description>
                  <value>#1</value>
                </enumeratedValue>
              </enumeratedValues>
            </field>
            <field>
              <name>UART0</name>
              <description>UART0 Clock Gate Control</description>
              <bitOffset>10</bitOffset>
              <bitWidth>1</bitWidth>
              <access>read-write</access>
              <enumeratedValues>
                <enumeratedValue>
                  <name>0</name>
                  <description>Clock disabled</description>
                  <value>#0</value>
                </enumeratedValue>
                <enumeratedValue>
                  <name>1</name>
                  <description>Clock enabled</description>
                  <value>#1</value>
                </enumeratedValue>
              </enumeratedValues>
            </field>
            <field>
              <name>UART1</name>
              <description>UART1 Clock Gate Control</description>
              <bitOffset>11</bitOffset>
              <bitWidth>1</bitWidth>
              <access>read-write</access>
              <enumeratedValues>
                <enumeratedValue>
                  <name>0</name>
                  <description>Clock disabled</description>
                  <value>#0</value>
                </enumeratedValue>
                <enumeratedValue>
                  <name>1</name>
                  <description>Clock enabled</description>
                  <value>#1</value>
                </enumeratedValue>
              </enumeratedValues>
            </field>
            <field>
              <name>UART2</name>
              <description>UART2 Clock Gate Control</description>
              <bitOffset>12</bitOffset>
              <bitWidth>1</bitWidth>
              <access>read-write</access>
              <enumeratedValues>
                <enumeratedValue>
                  <name>0</name>
                  <description>Clock disabled</description>
                  <value>#0</value>
                </enumeratedValue>
                <enumeratedValue>
                  <name>1</name>
                  <description>Clock enabled</description>
                  <value>#1</value>
                </enumeratedValue>
              </enumeratedValues>
            </field>
            <field>
              <name>USBOTG</name>
              <description>USB Clock Gate Control</description>
              <bitOffset>18</bitOffset>
              <bitWidth>1</bitWidth>
              <access>read-write</access>
              <enumeratedValues>
                <enumeratedValue>
                  <name>0</name>
                  <description>Clock disabled</description>
                  <value>#0</value>
                </enumeratedValue>
                <enumeratedValue>
                  <name>1</name>
                  <description>Clock enabled</description>
                  <value>#1</value>
                </enumeratedValue>
              </enumeratedValues>
            </field>
            <field>
              <name>CMP</name>
              <description>Comparator Clock Gate Control</description>
              <bitOffset>19</bitOffset>
              <bitWidth>1</bitWidth>
              <access>read-write</access>
              <enumeratedValues>
                <enumeratedValue>
                  <name>0</name>
                  <description>Clock disabled</description>
                  <value>#0</value>
                </enumeratedValue>
                <enumeratedValue>
                  <name>1</name>
                  <description>Clock enabled</description>
                  <value>#1</value>
                </enumeratedValue>
              </enumeratedValues>
            </field>
            <field>
              <name>SPI0</name>
              <description>SPI0 Clock Gate Control</description>
              <bitOffset>22</bitOffset>
              <bitWidth>1</bitWidth>
              <access>read-write</access>
              <enumeratedValues>
                <enumeratedValue>
                  <name>0</name>
                  <description>Clock disabled</description>
                  <value>#0</value>
                </enumeratedValue>
                <enumeratedValue>
                  <name>1</name>
                  <description>Clock enabled</description>
                  <value>#1</value>
                </enumeratedValue>
              </enumeratedValues>
            </field>
            <field>
              <name>SPI1</name>
              <description>SPI1 Clock Gate Control</description>
              <bitOffset>23</bitOffset>
              <bitWidth>1</bitWidth>
              <access>read-write</access>
              <enumeratedValues>
                <enumeratedValue>
                  <name>0</name>
                  <description>Clock disabled</description>
                  <value>#0</value>
                </enumeratedValue>
                <enumeratedValue>
                  <name>1</name>
                  <description>Clock enabled</description>
                  <value>#1</value>
                </enumeratedValue>
              </enumeratedValues>
            </field>
          </fields>
        </register>
        <register>
          <name>SCGC5</name>
          <description>System Clock Gating Control Register 5</description>
          <addressOffset>0x1038</addressOffset>
          <size>32</size>
          <access>read-write</access>
          <resetValue>0x182</resetValue>
          <resetMask>0xFFFFFFFF</resetMask>
          <fields>
            <field>
              <name>LPTMR</name>
              <description>Low Power Timer Access Control</description>
              <bitOffset>0</bitOffset>
              <bitWidth>1</bitWidth>
              <access>read-write</access>
              <enumeratedValues>
                <enumeratedValue>
                  <name>0</name>
                  <description>Access disabled</description>
                  <value>#0</value>
                </enumeratedValue>
                <enumeratedValue>
                  <name>1</name>
                  <description>Access enabled</description>
                  <value>#1</value>
                </enumeratedValue>
              </enumeratedValues>
            </field>
            <field>
              <name>TSI</name>
              <description>TSI Access Control</description>
              <bitOffset>5</bitOffset>
              <bitWidth>1</bitWidth>
              <access>read-write</access>
              <enumeratedValues>
                <enumeratedValue>
                  <name>0</name>
                  <description>Access disabled</description>
                  <value>#0</value>
                </enumeratedValue>
                <enumeratedValue>
                  <name>1</name>
                  <description>Access enabled</description>
                  <value>#1</value>
                </enumeratedValue>
              </enumeratedValues>
            </field>
            <field>
              <name>PORTA</name>
              <description>Port A Clock Gate Control</description>
              <bitOffset>9</bitOffset>
              <bitWidth>1</bitWidth>
              <access>read-write</access>
              <enumeratedValues>
                <enumeratedValue>
                  <name>0</name>
                  <description>Clock disabled</description>
                  <value>#0</value>
                </enumeratedValue>
                <enumeratedValue>
                  <name>1</name>
                  <description>Clock enabled</description>
                  <value>#1</value>
                </enumeratedValue>
              </enumeratedValues>
            </field>
            <field>
              <name>PORTB</name>
              <description>Port B Clock Gate Control</description>
              <bitOffset>10</bitOffset>
              <bitWidth>1</bitWidth>
              <access>read-write</access>
              <enumeratedValues>
                <enumeratedValue>
                  <name>0</name>
                  <description>Clock disabled</description>
                  <value>#0</value>
                </enumeratedValue>
                <enumeratedValue>
                  <name>1</name>
                  <description>Clock enabled</description>
                  <value>#1</value>
                </enumeratedValue>
              </enumeratedValues>
            </field>
            <field>
              <name>PORTC</name>
              <description>Port C Clock Gate Control</description>
              <bitOffset>11</bitOffset>
              <bitWidth>1</bitWidth>
              <access>read-write</access>
              <enumeratedValues>
                <enumeratedValue>
                  <name>0</name>
                  <description>Clock disabled</description>
                  <value>#0</value>
                </enumeratedValue>
                <enumeratedValue>
                  <name>1</name>
                  <description>Clock enabled</description>
                  <value>#1</value>
                </enumeratedValue>
              </enumeratedValues>
            </field>
            <field>
              <name>PORTD</name>
              <description>Port D Clock Gate Control</description>
              <bitOffset>12</bitOffset>
              <bitWidth>1</bitWidth>
              <access>read-write</access>
              <enumeratedValues>
                <enumeratedValue>
                  <name>0</name>
                  <description>Clock disabled</description>
                  <value>#0</value>
                </enumeratedValue>
                <enumeratedValue>
                  <name>1</name>
                  <description>Clock enabled</description>
                  <value>#1</value>
                </enumeratedValue>
              </enumeratedValues>
            </field>
            <field>
              <name>PORTE</name>
              <description>Port E Clock Gate Control</description>
              <bitOffset>13</bitOffset>
              <bitWidth>1</bitWidth>
              <access>read-write</access>
              <enumeratedValues>
                <enumeratedValue>
                  <name>0</name>
                  <description>Clock disabled</description>
                  <value>#0</value>
                </enumeratedValue>
                <enumeratedValue>
                  <name>1</name>
                  <description>Clock enabled</description>
                  <value>#1</value>
                </enumeratedValue>
              </enumeratedValues>
            </field>
            <field>
              <name>SLCD</name>
              <description>Segment LCD Clock Gate Control</description>
              <bitOffset>19</bitOffset>
              <bitWidth>1</bitWidth>
              <access>read-write</access>
              <enumeratedValues>
                <enumeratedValue>
                  <name>0</name>
                  <description>Clock disabled</description>
                  <value>#0</value>
                </enumeratedValue>
                <enumeratedValue>
                  <name>1</name>
                  <description>Clock enabled</description>
                  <value>#1</value>
                </enumeratedValue>
              </enumeratedValues>
            </field>
          </fields>
        </register>
        <register>
          <name>SCGC6</name>
          <description>System Clock Gating Control Register 6</description>
          <addressOffset>0x103C</addressOffset>
          <size>32</size>
          <access>read-write</access>
          <resetValue>0x1</resetValue>
          <resetMask>0xFFFFFFFF</resetMask>
          <fields>
            <field>
              <name>FTF</name>
              <description>Flash Memory Clock Gate Control</description>
              <bitOffset>0</bitOffset>
              <bitWidth>1</bitWidth>
              <access>read-write</access>
              <enumeratedValues>
                <enumeratedValue>
                  <name>0</name>
                  <description>Clock disabled</description>
                  <value>#0</value>
                </enumeratedValue>
                <enumeratedValue>
                  <name>1</name>
                  <description>Clock enabled</description>
                  <value>#1</value>
                </enumeratedValue>
              </enumeratedValues>
            </field>
            <field>
              <name>DMAMUX</name>
              <description>DMA Mux Clock Gate Control</description>
              <bitOffset>1</bitOffset>
              <bitWidth>1</bitWidth>
              <access>read-write</access>
              <enumeratedValues>
                <enumeratedValue>
                  <name>0</name>
                  <description>Clock disabled</description>
                  <value>#0</value>
                </enumeratedValue>
                <enumeratedValue>
                  <name>1</name>
                  <description>Clock enabled</description>
                  <value>#1</value>
                </enumeratedValue>
              </enumeratedValues>
            </field>
            <field>
              <name>I2S</name>
              <description>I2S Clock Gate Control</description>
              <bitOffset>15</bitOffset>
              <bitWidth>1</bitWidth>
              <access>read-write</access>
              <enumeratedValues>
                <enumeratedValue>
                  <name>0</name>
                  <description>Clock disabled</description>
                  <value>#0</value>
                </enumeratedValue>
                <enumeratedValue>
                  <name>1</name>
                  <description>Clock enabled</description>
                  <value>#1</value>
                </enumeratedValue>
              </enumeratedValues>
            </field>
            <field>
              <name>PIT</name>
              <description>PIT Clock Gate Control</description>
              <bitOffset>23</bitOffset>
              <bitWidth>1</bitWidth>
              <access>read-write</access>
              <enumeratedValues>
                <enumeratedValue>
                  <name>0</name>
                  <description>Clock disabled</description>
                  <value>#0</value>
                </enumeratedValue>
                <enumeratedValue>
                  <name>1</name>
                  <description>Clock enabled</description>
                  <value>#1</value>
                </enumeratedValue>
              </enumeratedValues>
            </field>
            <field>
              <name>TPM0</name>
              <description>TPM0 Clock Gate Control</description>
              <bitOffset>24</bitOffset>
              <bitWidth>1</bitWidth>
              <access>read-write</access>
              <enumeratedValues>
                <enumeratedValue>
                  <name>0</name>
                  <description>Clock disabled</description>
                  <value>#0</value>
                </enumeratedValue>
                <enumeratedValue>
                  <name>1</name>
                  <description>Clock enabled</description>
                  <value>#1</value>
                </enumeratedValue>
              </enumeratedValues>
            </field>
            <field>
              <name>TPM1</name>
              <description>TPM1 Clock Gate Control</description>
              <bitOffset>25</bitOffset>
              <bitWidth>1</bitWidth>
              <access>read-write</access>
              <enumeratedValues>
                <enumeratedValue>
                  <name>0</name>
                  <description>Clock disabled</description>
                  <value>#0</value>
                </enumeratedValue>
                <enumeratedValue>
                  <name>1</name>
                  <description>Clock enabled</description>
                  <value>#1</value>
                </enumeratedValue>
              </enumeratedValues>
            </field>
            <field>
              <name>TPM2</name>
              <description>TPM2 Clock Gate Control</description>
              <bitOffset>26</bitOffset>
              <bitWidth>1</bitWidth>
              <access>read-write</access>
              <enumeratedValues>
                <enumeratedValue>
                  <name>0</name>
                  <description>Clock disabled</description>
                  <value>#0</value>
                </enumeratedValue>
                <enumeratedValue>
                  <name>1</name>
                  <description>Clock enabled</description>
                  <value>#1</value>
                </enumeratedValue>
              </enumeratedValues>
            </field>
            <field>
              <name>ADC0</name>
              <description>ADC0 Clock Gate Control</description>
              <bitOffset>27</bitOffset>
              <bitWidth>1</bitWidth>
              <access>read-write</access>
              <enumeratedValues>
                <enumeratedValue>
                  <name>0</name>
                  <description>Clock disabled</description>
                  <value>#0</value>
                </enumeratedValue>
                <enumeratedValue>
                  <name>1</name>
                  <description>Clock enabled</description>
                  <value>#1</value>
                </enumeratedValue>
              </enumeratedValues>
            </field>
            <field>
              <name>RTC</name>
              <description>RTC Access Control</description>
              <bitOffset>29</bitOffset>
              <bitWidth>1</bitWidth>
              <access>read-write</access>
              <enumeratedValues>
                <enumeratedValue>
                  <name>0</name>
                  <description>Access and interrupts disabled</description>
                  <value>#0</value>
                </enumeratedValue>
                <enumeratedValue>
                  <name>1</name>
                  <description>Access and interrupts enabled</description>
                  <value>#1</value>
                </enumeratedValue>
              </enumeratedValues>
            </field>
            <field>
              <name>DAC0</name>
              <description>DAC0 Clock Gate Control</description>
              <bitOffset>31</bitOffset>
              <bitWidth>1</bitWidth>
              <access>read-write</access>
              <enumeratedValues>
                <enumeratedValue>
                  <name>0</name>
                  <description>Clock disabled</description>
                  <value>#0</value>
                </enumeratedValue>
                <enumeratedValue>
                  <name>1</name>
                  <description>Clock enabled</description>
                  <value>#1</value>
                </enumeratedValue>
              </enumeratedValues>
            </field>
          </fields>
        </register>
        <register>
          <name>SCGC7</name>
          <description>System Clock Gating Control Register 7</description>
          <addressOffset>0x1040</addressOffset>
          <size>32</size>
          <access>read-write</access>
          <resetValue>0x100</resetValue>
          <resetMask>0xFFFFFFFF</resetMask>
          <fields>
            <field>
              <name>DMA</name>
              <description>DMA Clock Gate Control</description>
              <bitOffset>8</bitOffset>
              <bitWidth>1</bitWidth>
              <access>read-write</access>
              <enumeratedValues>
                <enumeratedValue>
                  <name>0</name>
                  <description>Clock disabled</description>
                  <value>#0</value>
                </enumeratedValue>
                <enumeratedValue>
                  <name>1</name>
                  <description>Clock enabled</description>
                  <value>#1</value>
                </enumeratedValue>
              </enumeratedValues>
            </field>
          </fields>
        </register>
        <register>
          <name>CLKDIV1</name>
          <description>System Clock Divider Register 1</description>
          <addressOffset>0x1044</addressOffset>
          <size>32</size>
          <access>read-write</access>
          <resetValue>0x10000</resetValue>
          <resetMask>0xFFFFFFFF</resetMask>
          <fields>
            <field>
              <name>OUTDIV4</name>
              <description>Clock 4 Output Divider value</description>
              <bitOffset>16</bitOffset>
              <bitWidth>3</bitWidth>
              <access>read-write</access>
              <enumeratedValues>
                <enumeratedValue>
                  <name>000</name>
                  <description>Divide-by-1.</description>
                  <value>#000</value>
                </enumeratedValue>
                <enumeratedValue>
                  <name>001</name>
                  <description>Divide-by-2.</description>
                  <value>#001</value>
                </enumeratedValue>
                <enumeratedValue>
                  <name>010</name>
                  <description>Divide-by-3.</description>
                  <value>#010</value>
                </enumeratedValue>
                <enumeratedValue>
                  <name>011</name>
                  <description>Divide-by-4.</description>
                  <value>#011</value>
                </enumeratedValue>
                <enumeratedValue>
                  <name>100</name>
                  <description>Divide-by-5.</description>
                  <value>#100</value>
                </enumeratedValue>
                <enumeratedValue>
                  <name>101</name>
                  <description>Divide-by-6.</description>
                  <value>#101</value>
                </enumeratedValue>
                <enumeratedValue>
                  <name>110</name>
                  <description>Divide-by-7.</description>
                  <value>#110</value>
                </enumeratedValue>
                <enumeratedValue>
                  <name>111</name>
                  <description>Divide-by-8.</description>
                  <value>#111</value>
                </enumeratedValue>
              </enumeratedValues>
            </field>
            <field>
              <name>OUTDIV1</name>
              <description>Clock 1 Output Divider value</description>
              <bitOffset>28</bitOffset>
              <bitWidth>4</bitWidth>
              <access>read-write</access>
              <enumeratedValues>
                <enumeratedValue>
                  <name>0000</name>
                  <description>Divide-by-1.</description>
                  <value>#0000</value>
                </enumeratedValue>
                <enumeratedValue>
                  <name>0001</name>
                  <description>Divide-by-2.</description>
                  <value>#0001</value>
                </enumeratedValue>
                <enumeratedValue>
                  <name>0010</name>
                  <description>Divide-by-3.</description>
                  <value>#0010</value>
                </enumeratedValue>
                <enumeratedValue>
                  <name>0011</name>
                  <description>Divide-by-4.</description>
                  <value>#0011</value>
                </enumeratedValue>
                <enumeratedValue>
                  <name>0100</name>
                  <description>Divide-by-5.</description>
                  <value>#0100</value>
                </enumeratedValue>
                <enumeratedValue>
                  <name>0101</name>
                  <description>Divide-by-6.</description>
                  <value>#0101</value>
                </enumeratedValue>
                <enumeratedValue>
                  <name>0110</name>
                  <description>Divide-by-7.</description>
                  <value>#0110</value>
                </enumeratedValue>
                <enumeratedValue>
                  <name>0111</name>
                  <description>Divide-by-8.</description>
                  <value>#0111</value>
                </enumeratedValue>
                <enumeratedValue>
                  <name>1000</name>
                  <description>Divide-by-9.</description>
                  <value>#1000</value>
                </enumeratedValue>
                <enumeratedValue>
                  <name>1001</name>
                  <description>Divide-by-10.</description>
                  <value>#1001</value>
                </enumeratedValue>
                <enumeratedValue>
                  <name>1010</name>
                  <description>Divide-by-11.</description>
                  <value>#1010</value>
                </enumeratedValue>
                <enumeratedValue>
                  <name>1011</name>
                  <description>Divide-by-12.</description>
                  <value>#1011</value>
                </enumeratedValue>
                <enumeratedValue>
                  <name>1100</name>
                  <description>Divide-by-13.</description>
                  <value>#1100</value>
                </enumeratedValue>
                <enumeratedValue>
                  <name>1101</name>
                  <description>Divide-by-14.</description>
                  <value>#1101</value>
                </enumeratedValue>
                <enumeratedValue>
                  <name>1110</name>
                  <description>Divide-by-15.</description>
                  <value>#1110</value>
                </enumeratedValue>
                <enumeratedValue>
                  <name>1111</name>
                  <description>Divide-by-16.</description>
                  <value>#1111</value>
                </enumeratedValue>
              </enumeratedValues>
            </field>
          </fields>
        </register>
        <register>
          <name>FCFG1</name>
          <description>Flash Configuration Register 1</description>
          <addressOffset>0x104C</addressOffset>
          <size>32</size>
          <access>read-write</access>
          <resetValue>0xF000000</resetValue>
          <resetMask>0xFFFFFFFF</resetMask>
          <fields>
            <field>
              <name>FLASHDIS</name>
              <description>Flash Disable</description>
              <bitOffset>0</bitOffset>
              <bitWidth>1</bitWidth>
              <access>read-write</access>
              <enumeratedValues>
                <enumeratedValue>
                  <name>0</name>
                  <description>Flash is enabled.</description>
                  <value>#0</value>
                </enumeratedValue>
                <enumeratedValue>
                  <name>1</name>
                  <description>Flash is disabled.</description>
                  <value>#1</value>
                </enumeratedValue>
              </enumeratedValues>
            </field>
            <field>
              <name>FLASHDOZE</name>
              <description>Flash Doze</description>
              <bitOffset>1</bitOffset>
              <bitWidth>1</bitWidth>
              <access>read-write</access>
              <enumeratedValues>
                <enumeratedValue>
                  <name>0</name>
                  <description>Flash remains enabled during Doze mode.</description>
                  <value>#0</value>
                </enumeratedValue>
                <enumeratedValue>
                  <name>1</name>
                  <description>Flash is disabled for the duration of Doze mode.</description>
                  <value>#1</value>
                </enumeratedValue>
              </enumeratedValues>
            </field>
            <field>
              <name>PFSIZE</name>
              <description>Program Flash Size</description>
              <bitOffset>24</bitOffset>
              <bitWidth>4</bitWidth>
              <access>read-only</access>
              <enumeratedValues>
                <enumeratedValue>
                  <name>0000</name>
                  <description>8 KB of program flash memory, 0.25 KB protection region</description>
                  <value>#0000</value>
                </enumeratedValue>
                <enumeratedValue>
                  <name>0001</name>
                  <description>16 KB of program flash memory, 0.5 KB protection region</description>
                  <value>#0001</value>
                </enumeratedValue>
                <enumeratedValue>
                  <name>0011</name>
                  <description>32 KB of program flash memory, 1 KB protection region</description>
                  <value>#0011</value>
                </enumeratedValue>
                <enumeratedValue>
                  <name>0101</name>
                  <description>64 KB of program flash memory, 2 KB protection region</description>
                  <value>#0101</value>
                </enumeratedValue>
                <enumeratedValue>
                  <name>0111</name>
                  <description>128 KB of program flash memory, 4 KB protection region</description>
                  <value>#0111</value>
                </enumeratedValue>
                <enumeratedValue>
                  <name>1001</name>
                  <description>256 KB of program flash memory, 8 KB protection region</description>
                  <value>#1001</value>
                </enumeratedValue>
                <enumeratedValue>
                  <name>1111</name>
                  <description>128 KB of program flash memory, 4 KB protection region 256 KB of program flash memory, 8 KB protection region</description>
                  <value>#1111</value>
                </enumeratedValue>
              </enumeratedValues>
            </field>
          </fields>
        </register>
        <register>
          <name>FCFG2</name>
          <description>Flash Configuration Register 2</description>
          <addressOffset>0x1050</addressOffset>
          <size>32</size>
          <access>read-only</access>
          <resetValue>0x7FFF0000</resetValue>
          <resetMask>0xFFFFFFFF</resetMask>
          <fields>
            <field>
              <name>MAXADDR1</name>
              <description>This field concatenated with leading zeros plus the value of the MAXADDR1 field indicates the first invalid address of the second program flash block (flash block 1)</description>
              <bitOffset>16</bitOffset>
              <bitWidth>7</bitWidth>
              <access>read-only</access>
            </field>
            <field>
              <name>MAXADDR0</name>
              <description>Max Address lock</description>
              <bitOffset>24</bitOffset>
              <bitWidth>7</bitWidth>
              <access>read-only</access>
            </field>
          </fields>
        </register>
        <register>
          <name>UIDMH</name>
          <description>Unique Identification Register Mid-High</description>
          <addressOffset>0x1058</addressOffset>
          <size>32</size>
          <access>read-only</access>
          <resetValue>0</resetValue>
          <resetMask>0xFFFFFFFF</resetMask>
          <fields>
            <field>
              <name>UID</name>
              <description>Unique Identification</description>
              <bitOffset>0</bitOffset>
              <bitWidth>16</bitWidth>
              <access>read-only</access>
            </field>
          </fields>
        </register>
        <register>
          <name>UIDML</name>
          <description>Unique Identification Register Mid Low</description>
          <addressOffset>0x105C</addressOffset>
          <size>32</size>
          <access>read-only</access>
          <resetValue>0</resetValue>
          <resetMask>0xFFFFFFFF</resetMask>
          <fields>
            <field>
              <name>UID</name>
              <description>Unique Identification</description>
              <bitOffset>0</bitOffset>
              <bitWidth>32</bitWidth>
              <access>read-only</access>
            </field>
          </fields>
        </register>
        <register>
          <name>UIDL</name>
          <description>Unique Identification Register Low</description>
          <addressOffset>0x1060</addressOffset>
          <size>32</size>
          <access>read-only</access>
          <resetValue>0</resetValue>
          <resetMask>0xFFFFFFFF</resetMask>
          <fields>
            <field>
              <name>UID</name>
              <description>Unique Identification</description>
              <bitOffset>0</bitOffset>
              <bitWidth>32</bitWidth>
              <access>read-only</access>
            </field>
          </fields>
        </register>
        <register>
          <name>COPC</name>
          <description>COP Control Register</description>
          <addressOffset>0x1100</addressOffset>
          <size>32</size>
          <access>read-write</access>
          <resetValue>0xC</resetValue>
          <resetMask>0xFFFFFFFF</resetMask>
          <fields>
            <field>
              <name>COPW</name>
              <description>COP Windowed Mode</description>
              <bitOffset>0</bitOffset>
              <bitWidth>1</bitWidth>
              <access>read-write</access>
              <enumeratedValues>
                <enumeratedValue>
                  <name>0</name>
                  <description>Normal mode</description>
                  <value>#0</value>
                </enumeratedValue>
                <enumeratedValue>
                  <name>1</name>
                  <description>Windowed mode</description>
                  <value>#1</value>
                </enumeratedValue>
              </enumeratedValues>
            </field>
            <field>
              <name>COPCLKS</name>
              <description>COP Clock Select</description>
              <bitOffset>1</bitOffset>
              <bitWidth>1</bitWidth>
              <access>read-write</access>
              <enumeratedValues>
                <enumeratedValue>
                  <name>0</name>
                  <description>Internal 1 kHz clock is source to COP.</description>
                  <value>#0</value>
                </enumeratedValue>
                <enumeratedValue>
                  <name>1</name>
                  <description>Bus clock is source to COP.</description>
                  <value>#1</value>
                </enumeratedValue>
              </enumeratedValues>
            </field>
            <field>
              <name>COPT</name>
              <description>COP Watchdog Timeout</description>
              <bitOffset>2</bitOffset>
              <bitWidth>2</bitWidth>
              <access>read-write</access>
              <enumeratedValues>
                <enumeratedValue>
                  <name>00</name>
                  <description>COP disabled</description>
                  <value>#00</value>
                </enumeratedValue>
                <enumeratedValue>
                  <name>01</name>
                  <description>COP timeout after 25 LPO cycles or 213 bus clock cycles</description>
                  <value>#01</value>
                </enumeratedValue>
                <enumeratedValue>
                  <name>10</name>
                  <description>COP timeout after 28 LPO cycles or 216 bus clock cycles</description>
                  <value>#10</value>
                </enumeratedValue>
                <enumeratedValue>
                  <name>11</name>
                  <description>COP timeout after 210 LPO cycles or 218 bus clock cycles</description>
                  <value>#11</value>
                </enumeratedValue>
              </enumeratedValues>
            </field>
          </fields>
        </register>
        <register>
          <name>SRVCOP</name>
          <description>Service COP</description>
          <addressOffset>0x1104</addressOffset>
          <size>32</size>
          <access>write-only</access>
          <resetValue>0</resetValue>
          <resetMask>0xFFFFFFFF</resetMask>
          <fields>
            <field>
              <name>SRVCOP</name>
              <description>Service COP Register</description>
              <bitOffset>0</bitOffset>
              <bitWidth>8</bitWidth>
              <access>write-only</access>
            </field>
          </fields>
        </register>
      </registers>
    </peripheral>
    <peripheral>
      <name>PORTA</name>
      <description>Pin Control and Interrupts</description>
      <groupName>PORT</groupName>
      <prependToName>PORTA_</prependToName>
      <baseAddress>0x40049000</baseAddress>
      <addressBlock>
        <offset>0</offset>
        <size>0xA4</size>
        <usage>registers</usage>
      </addressBlock>
      <interrupt>
        <name>PORTA</name>
        <value>30</value>
      </interrupt>
      <registers>
        <register>
          <dim>32</dim>
          <dimIncrement>0x4</dimIncrement>
          <dimIndex>0,1,2,3,4,5,6,7,8,9,10,11,12,13,14,15,16,17,18,19,20,21,22,23,24,25,26,27,28,29,30,31</dimIndex>
          <name>PCR%s</name>
          <description>Pin Control Register n</description>
          <addressOffset>0</addressOffset>
          <size>32</size>
          <access>read-write</access>
          <resetValue>0x706</resetValue>
          <resetMask>0xFFFFFFFF</resetMask>
          <fields>
            <field>
              <name>PS</name>
              <description>Pull Select</description>
              <bitOffset>0</bitOffset>
              <bitWidth>1</bitWidth>
              <access>read-write</access>
              <enumeratedValues>
                <enumeratedValue>
                  <name>0</name>
                  <description>Internal pulldown resistor is enabled on the corresponding pin, if the corresponding PE field is set.</description>
                  <value>#0</value>
                </enumeratedValue>
                <enumeratedValue>
                  <name>1</name>
                  <description>Internal pullup resistor is enabled on the corresponding pin, if the corresponding PE field is set.</description>
                  <value>#1</value>
                </enumeratedValue>
              </enumeratedValues>
            </field>
            <field>
              <name>PE</name>
              <description>Pull Enable</description>
              <bitOffset>1</bitOffset>
              <bitWidth>1</bitWidth>
              <access>read-write</access>
              <enumeratedValues>
                <enumeratedValue>
                  <name>0</name>
                  <description>Internal pullup or pulldown resistor is not enabled on the corresponding pin.</description>
                  <value>#0</value>
                </enumeratedValue>
                <enumeratedValue>
                  <name>1</name>
                  <description>Internal pullup or pulldown resistor is enabled on the corresponding pin, if the pin is configured as a digital input.</description>
                  <value>#1</value>
                </enumeratedValue>
              </enumeratedValues>
            </field>
            <field>
              <name>SRE</name>
              <description>Slew Rate Enable</description>
              <bitOffset>2</bitOffset>
              <bitWidth>1</bitWidth>
              <access>read-write</access>
              <enumeratedValues>
                <enumeratedValue>
                  <name>0</name>
                  <description>Fast slew rate is configured on the corresponding pin, if the pin is configured as a digital output.</description>
                  <value>#0</value>
                </enumeratedValue>
                <enumeratedValue>
                  <name>1</name>
                  <description>Slow slew rate is configured on the corresponding pin, if the pin is configured as a digital output.</description>
                  <value>#1</value>
                </enumeratedValue>
              </enumeratedValues>
            </field>
            <field>
              <name>PFE</name>
              <description>Passive Filter Enable</description>
              <bitOffset>4</bitOffset>
              <bitWidth>1</bitWidth>
              <access>read-write</access>
              <enumeratedValues>
                <enumeratedValue>
                  <name>0</name>
                  <description>Passive input filter is disabled on the corresponding pin.</description>
                  <value>#0</value>
                </enumeratedValue>
                <enumeratedValue>
                  <name>1</name>
                  <description>Passive input filter is enabled on the corresponding pin, if the pin is configured as a digital input. Refer to the device data sheet for filter characteristics.</description>
                  <value>#1</value>
                </enumeratedValue>
              </enumeratedValues>
            </field>
            <field>
              <name>DSE</name>
              <description>Drive Strength Enable</description>
              <bitOffset>6</bitOffset>
              <bitWidth>1</bitWidth>
              <access>read-write</access>
              <enumeratedValues>
                <enumeratedValue>
                  <name>0</name>
                  <description>Low drive strength is configured on the corresponding pin, if pin is configured as a digital output.</description>
                  <value>#0</value>
                </enumeratedValue>
                <enumeratedValue>
                  <name>1</name>
                  <description>High drive strength is configured on the corresponding pin, if pin is configured as a digital output.</description>
                  <value>#1</value>
                </enumeratedValue>
              </enumeratedValues>
            </field>
            <field>
              <name>MUX</name>
              <description>Pin Mux Control</description>
              <bitOffset>8</bitOffset>
              <bitWidth>3</bitWidth>
              <access>read-write</access>
              <enumeratedValues>
                <enumeratedValue>
                  <name>000</name>
                  <description>Pin disabled (analog).</description>
                  <value>#000</value>
                </enumeratedValue>
                <enumeratedValue>
                  <name>001</name>
                  <description>Alternative 1 (GPIO).</description>
                  <value>#001</value>
                </enumeratedValue>
                <enumeratedValue>
                  <name>010</name>
                  <description>Alternative 2 (chip-specific).</description>
                  <value>#010</value>
                </enumeratedValue>
                <enumeratedValue>
                  <name>011</name>
                  <description>Alternative 3 (chip-specific).</description>
                  <value>#011</value>
                </enumeratedValue>
                <enumeratedValue>
                  <name>100</name>
                  <description>Alternative 4 (chip-specific).</description>
                  <value>#100</value>
                </enumeratedValue>
                <enumeratedValue>
                  <name>101</name>
                  <description>Alternative 5 (chip-specific).</description>
                  <value>#101</value>
                </enumeratedValue>
                <enumeratedValue>
                  <name>110</name>
                  <description>Alternative 6 (chip-specific).</description>
                  <value>#110</value>
                </enumeratedValue>
                <enumeratedValue>
                  <name>111</name>
                  <description>Alternative 7 (chip-specific).</description>
                  <value>#111</value>
                </enumeratedValue>
              </enumeratedValues>
            </field>
            <field>
              <name>IRQC</name>
              <description>Interrupt Configuration</description>
              <bitOffset>16</bitOffset>
              <bitWidth>4</bitWidth>
              <access>read-write</access>
              <enumeratedValues>
                <enumeratedValue>
                  <name>0000</name>
                  <description>Interrupt/DMA request disabled.</description>
                  <value>#0000</value>
                </enumeratedValue>
                <enumeratedValue>
                  <name>0001</name>
                  <description>DMA request on rising edge.</description>
                  <value>#0001</value>
                </enumeratedValue>
                <enumeratedValue>
                  <name>0010</name>
                  <description>DMA request on falling edge.</description>
                  <value>#0010</value>
                </enumeratedValue>
                <enumeratedValue>
                  <name>0011</name>
                  <description>DMA request on either edge.</description>
                  <value>#0011</value>
                </enumeratedValue>
                <enumeratedValue>
                  <name>1000</name>
                  <description>Interrupt when logic 0.</description>
                  <value>#1000</value>
                </enumeratedValue>
                <enumeratedValue>
                  <name>1001</name>
                  <description>Interrupt on rising-edge.</description>
                  <value>#1001</value>
                </enumeratedValue>
                <enumeratedValue>
                  <name>1010</name>
                  <description>Interrupt on falling-edge.</description>
                  <value>#1010</value>
                </enumeratedValue>
                <enumeratedValue>
                  <name>1011</name>
                  <description>Interrupt on either edge.</description>
                  <value>#1011</value>
                </enumeratedValue>
                <enumeratedValue>
                  <name>1100</name>
                  <description>Interrupt when logic 1.</description>
                  <value>#1100</value>
                </enumeratedValue>
              </enumeratedValues>
            </field>
            <field>
              <name>ISF</name>
              <description>Interrupt Status Flag</description>
              <bitOffset>24</bitOffset>
              <bitWidth>1</bitWidth>
              <access>read-write</access>
              <enumeratedValues>
                <enumeratedValue>
                  <name>0</name>
                  <description>Configured interrupt is not detected.</description>
                  <value>#0</value>
                </enumeratedValue>
                <enumeratedValue>
                  <name>1</name>
                  <description>Configured interrupt is detected. If the pin is configured to generate a DMA request, then the corresponding flag will be cleared automatically at the completion of the requested DMA transfer. Otherwise, the flag remains set until a logic 1 is written to the flag. If the pin is configured for a level sensitive interrupt and the pin remains asserted, then the flag is set again immediately after it is cleared.</description>
                  <value>#1</value>
                </enumeratedValue>
              </enumeratedValues>
            </field>
          </fields>
        </register>
        <register>
          <name>GPCLR</name>
          <description>Global Pin Control Low Register</description>
          <addressOffset>0x80</addressOffset>
          <size>32</size>
          <access>write-only</access>
          <resetValue>0</resetValue>
          <resetMask>0xFFFFFFFF</resetMask>
          <fields>
            <field>
              <name>GPWD</name>
              <description>Global Pin Write Data</description>
              <bitOffset>0</bitOffset>
              <bitWidth>16</bitWidth>
              <access>write-only</access>
            </field>
            <field>
              <name>GPWE</name>
              <description>Global Pin Write Enable</description>
              <bitOffset>16</bitOffset>
              <bitWidth>16</bitWidth>
              <access>write-only</access>
              <enumeratedValues>
                <enumeratedValue>
                  <name>0</name>
                  <description>Corresponding Pin Control Register is not updated with the value in GPWD.</description>
                  <value>#0</value>
                </enumeratedValue>
                <enumeratedValue>
                  <name>1</name>
                  <description>Corresponding Pin Control Register is updated with the value in GPWD.</description>
                  <value>#1</value>
                </enumeratedValue>
              </enumeratedValues>
            </field>
          </fields>
        </register>
        <register>
          <name>GPCHR</name>
          <description>Global Pin Control High Register</description>
          <addressOffset>0x84</addressOffset>
          <size>32</size>
          <access>write-only</access>
          <resetValue>0</resetValue>
          <resetMask>0xFFFFFFFF</resetMask>
          <fields>
            <field>
              <name>GPWD</name>
              <description>Global Pin Write Data</description>
              <bitOffset>0</bitOffset>
              <bitWidth>16</bitWidth>
              <access>write-only</access>
            </field>
            <field>
              <name>GPWE</name>
              <description>Global Pin Write Enable</description>
              <bitOffset>16</bitOffset>
              <bitWidth>16</bitWidth>
              <access>write-only</access>
              <enumeratedValues>
                <enumeratedValue>
                  <name>0</name>
                  <description>Corresponding Pin Control Register is not updated with the value in GPWD.</description>
                  <value>#0</value>
                </enumeratedValue>
                <enumeratedValue>
                  <name>1</name>
                  <description>Corresponding Pin Control Register is updated with the value in GPWD.</description>
                  <value>#1</value>
                </enumeratedValue>
              </enumeratedValues>
            </field>
          </fields>
        </register>
        <register>
          <name>ISFR</name>
          <description>Interrupt Status Flag Register</description>
          <addressOffset>0xA0</addressOffset>
          <size>32</size>
          <access>read-write</access>
          <resetValue>0</resetValue>
          <resetMask>0xFFFFFFFF</resetMask>
          <fields>
            <field>
              <name>ISF</name>
              <description>Interrupt Status Flag</description>
              <bitOffset>0</bitOffset>
              <bitWidth>32</bitWidth>
              <access>read-write</access>
              <enumeratedValues>
                <enumeratedValue>
                  <name>0</name>
                  <description>Configured interrupt is not detected.</description>
                  <value>#0</value>
                </enumeratedValue>
                <enumeratedValue>
                  <name>1</name>
                  <description>Configured interrupt is detected. If the pin is configured to generate a DMA request, then the corresponding flag will be cleared automatically at the completion of the requested DMA transfer. Otherwise, the flag remains set until a logic 1 is written to the flag. If the pin is configured for a level sensitive interrupt and the pin remains asserted, then the flag is set again immediately after it is cleared.</description>
                  <value>#1</value>
                </enumeratedValue>
              </enumeratedValues>
            </field>
          </fields>
        </register>
      </registers>
    </peripheral>
    <peripheral>
      <name>PORTB</name>
      <description>Pin Control and Interrupts</description>
      <groupName>PORT</groupName>
      <prependToName>PORTB_</prependToName>
      <baseAddress>0x4004A000</baseAddress>
      <addressBlock>
        <offset>0</offset>
        <size>0xA4</size>
        <usage>registers</usage>
      </addressBlock>
      <registers>
        <register>
          <dim>32</dim>
          <dimIncrement>0x4</dimIncrement>
          <dimIndex>0,1,2,3,4,5,6,7,8,9,10,11,12,13,14,15,16,17,18,19,20,21,22,23,24,25,26,27,28,29,30,31</dimIndex>
          <name>PCR%s</name>
          <description>Pin Control Register n</description>
          <addressOffset>0</addressOffset>
          <size>32</size>
          <access>read-write</access>
          <resetValue>0x5</resetValue>
          <resetMask>0xFFFFFFFF</resetMask>
          <fields>
            <field>
              <name>PS</name>
              <description>Pull Select</description>
              <bitOffset>0</bitOffset>
              <bitWidth>1</bitWidth>
              <access>read-write</access>
              <enumeratedValues>
                <enumeratedValue>
                  <name>0</name>
                  <description>Internal pulldown resistor is enabled on the corresponding pin, if the corresponding PE field is set.</description>
                  <value>#0</value>
                </enumeratedValue>
                <enumeratedValue>
                  <name>1</name>
                  <description>Internal pullup resistor is enabled on the corresponding pin, if the corresponding PE field is set.</description>
                  <value>#1</value>
                </enumeratedValue>
              </enumeratedValues>
            </field>
            <field>
              <name>PE</name>
              <description>Pull Enable</description>
              <bitOffset>1</bitOffset>
              <bitWidth>1</bitWidth>
              <access>read-write</access>
              <enumeratedValues>
                <enumeratedValue>
                  <name>0</name>
                  <description>Internal pullup or pulldown resistor is not enabled on the corresponding pin.</description>
                  <value>#0</value>
                </enumeratedValue>
                <enumeratedValue>
                  <name>1</name>
                  <description>Internal pullup or pulldown resistor is enabled on the corresponding pin, if the pin is configured as a digital input.</description>
                  <value>#1</value>
                </enumeratedValue>
              </enumeratedValues>
            </field>
            <field>
              <name>SRE</name>
              <description>Slew Rate Enable</description>
              <bitOffset>2</bitOffset>
              <bitWidth>1</bitWidth>
              <access>read-write</access>
              <enumeratedValues>
                <enumeratedValue>
                  <name>0</name>
                  <description>Fast slew rate is configured on the corresponding pin, if the pin is configured as a digital output.</description>
                  <value>#0</value>
                </enumeratedValue>
                <enumeratedValue>
                  <name>1</name>
                  <description>Slow slew rate is configured on the corresponding pin, if the pin is configured as a digital output.</description>
                  <value>#1</value>
                </enumeratedValue>
              </enumeratedValues>
            </field>
            <field>
              <name>PFE</name>
              <description>Passive Filter Enable</description>
              <bitOffset>4</bitOffset>
              <bitWidth>1</bitWidth>
              <access>read-write</access>
              <enumeratedValues>
                <enumeratedValue>
                  <name>0</name>
                  <description>Passive input filter is disabled on the corresponding pin.</description>
                  <value>#0</value>
                </enumeratedValue>
                <enumeratedValue>
                  <name>1</name>
                  <description>Passive input filter is enabled on the corresponding pin, if the pin is configured as a digital input. Refer to the device data sheet for filter characteristics.</description>
                  <value>#1</value>
                </enumeratedValue>
              </enumeratedValues>
            </field>
            <field>
              <name>DSE</name>
              <description>Drive Strength Enable</description>
              <bitOffset>6</bitOffset>
              <bitWidth>1</bitWidth>
              <access>read-write</access>
              <enumeratedValues>
                <enumeratedValue>
                  <name>0</name>
                  <description>Low drive strength is configured on the corresponding pin, if pin is configured as a digital output.</description>
                  <value>#0</value>
                </enumeratedValue>
                <enumeratedValue>
                  <name>1</name>
                  <description>High drive strength is configured on the corresponding pin, if pin is configured as a digital output.</description>
                  <value>#1</value>
                </enumeratedValue>
              </enumeratedValues>
            </field>
            <field>
              <name>MUX</name>
              <description>Pin Mux Control</description>
              <bitOffset>8</bitOffset>
              <bitWidth>3</bitWidth>
              <access>read-write</access>
              <enumeratedValues>
                <enumeratedValue>
                  <name>000</name>
                  <description>Pin disabled (analog).</description>
                  <value>#000</value>
                </enumeratedValue>
                <enumeratedValue>
                  <name>001</name>
                  <description>Alternative 1 (GPIO).</description>
                  <value>#001</value>
                </enumeratedValue>
                <enumeratedValue>
                  <name>010</name>
                  <description>Alternative 2 (chip-specific).</description>
                  <value>#010</value>
                </enumeratedValue>
                <enumeratedValue>
                  <name>011</name>
                  <description>Alternative 3 (chip-specific).</description>
                  <value>#011</value>
                </enumeratedValue>
                <enumeratedValue>
                  <name>100</name>
                  <description>Alternative 4 (chip-specific).</description>
                  <value>#100</value>
                </enumeratedValue>
                <enumeratedValue>
                  <name>101</name>
                  <description>Alternative 5 (chip-specific).</description>
                  <value>#101</value>
                </enumeratedValue>
                <enumeratedValue>
                  <name>110</name>
                  <description>Alternative 6 (chip-specific).</description>
                  <value>#110</value>
                </enumeratedValue>
                <enumeratedValue>
                  <name>111</name>
                  <description>Alternative 7 (chip-specific).</description>
                  <value>#111</value>
                </enumeratedValue>
              </enumeratedValues>
            </field>
            <field>
              <name>IRQC</name>
              <description>Interrupt Configuration</description>
              <bitOffset>16</bitOffset>
              <bitWidth>4</bitWidth>
              <access>read-write</access>
              <enumeratedValues>
                <enumeratedValue>
                  <name>0000</name>
                  <description>Interrupt/DMA request disabled.</description>
                  <value>#0000</value>
                </enumeratedValue>
                <enumeratedValue>
                  <name>0001</name>
                  <description>DMA request on rising edge.</description>
                  <value>#0001</value>
                </enumeratedValue>
                <enumeratedValue>
                  <name>0010</name>
                  <description>DMA request on falling edge.</description>
                  <value>#0010</value>
                </enumeratedValue>
                <enumeratedValue>
                  <name>0011</name>
                  <description>DMA request on either edge.</description>
                  <value>#0011</value>
                </enumeratedValue>
                <enumeratedValue>
                  <name>1000</name>
                  <description>Interrupt when logic 0.</description>
                  <value>#1000</value>
                </enumeratedValue>
                <enumeratedValue>
                  <name>1001</name>
                  <description>Interrupt on rising-edge.</description>
                  <value>#1001</value>
                </enumeratedValue>
                <enumeratedValue>
                  <name>1010</name>
                  <description>Interrupt on falling-edge.</description>
                  <value>#1010</value>
                </enumeratedValue>
                <enumeratedValue>
                  <name>1011</name>
                  <description>Interrupt on either edge.</description>
                  <value>#1011</value>
                </enumeratedValue>
                <enumeratedValue>
                  <name>1100</name>
                  <description>Interrupt when logic 1.</description>
                  <value>#1100</value>
                </enumeratedValue>
              </enumeratedValues>
            </field>
            <field>
              <name>ISF</name>
              <description>Interrupt Status Flag</description>
              <bitOffset>24</bitOffset>
              <bitWidth>1</bitWidth>
              <access>read-write</access>
              <enumeratedValues>
                <enumeratedValue>
                  <name>0</name>
                  <description>Configured interrupt is not detected.</description>
                  <value>#0</value>
                </enumeratedValue>
                <enumeratedValue>
                  <name>1</name>
                  <description>Configured interrupt is detected. If the pin is configured to generate a DMA request, then the corresponding flag will be cleared automatically at the completion of the requested DMA transfer. Otherwise, the flag remains set until a logic 1 is written to the flag. If the pin is configured for a level sensitive interrupt and the pin remains asserted, then the flag is set again immediately after it is cleared.</description>
                  <value>#1</value>
                </enumeratedValue>
              </enumeratedValues>
            </field>
          </fields>
        </register>
        <register>
          <name>GPCLR</name>
          <description>Global Pin Control Low Register</description>
          <addressOffset>0x80</addressOffset>
          <size>32</size>
          <access>write-only</access>
          <resetValue>0</resetValue>
          <resetMask>0xFFFFFFFF</resetMask>
          <fields>
            <field>
              <name>GPWD</name>
              <description>Global Pin Write Data</description>
              <bitOffset>0</bitOffset>
              <bitWidth>16</bitWidth>
              <access>write-only</access>
            </field>
            <field>
              <name>GPWE</name>
              <description>Global Pin Write Enable</description>
              <bitOffset>16</bitOffset>
              <bitWidth>16</bitWidth>
              <access>write-only</access>
              <enumeratedValues>
                <enumeratedValue>
                  <name>0</name>
                  <description>Corresponding Pin Control Register is not updated with the value in GPWD.</description>
                  <value>#0</value>
                </enumeratedValue>
                <enumeratedValue>
                  <name>1</name>
                  <description>Corresponding Pin Control Register is updated with the value in GPWD.</description>
                  <value>#1</value>
                </enumeratedValue>
              </enumeratedValues>
            </field>
          </fields>
        </register>
        <register>
          <name>GPCHR</name>
          <description>Global Pin Control High Register</description>
          <addressOffset>0x84</addressOffset>
          <size>32</size>
          <access>write-only</access>
          <resetValue>0</resetValue>
          <resetMask>0xFFFFFFFF</resetMask>
          <fields>
            <field>
              <name>GPWD</name>
              <description>Global Pin Write Data</description>
              <bitOffset>0</bitOffset>
              <bitWidth>16</bitWidth>
              <access>write-only</access>
            </field>
            <field>
              <name>GPWE</name>
              <description>Global Pin Write Enable</description>
              <bitOffset>16</bitOffset>
              <bitWidth>16</bitWidth>
              <access>write-only</access>
              <enumeratedValues>
                <enumeratedValue>
                  <name>0</name>
                  <description>Corresponding Pin Control Register is not updated with the value in GPWD.</description>
                  <value>#0</value>
                </enumeratedValue>
                <enumeratedValue>
                  <name>1</name>
                  <description>Corresponding Pin Control Register is updated with the value in GPWD.</description>
                  <value>#1</value>
                </enumeratedValue>
              </enumeratedValues>
            </field>
          </fields>
        </register>
        <register>
          <name>ISFR</name>
          <description>Interrupt Status Flag Register</description>
          <addressOffset>0xA0</addressOffset>
          <size>32</size>
          <access>read-write</access>
          <resetValue>0</resetValue>
          <resetMask>0xFFFFFFFF</resetMask>
          <fields>
            <field>
              <name>ISF</name>
              <description>Interrupt Status Flag</description>
              <bitOffset>0</bitOffset>
              <bitWidth>32</bitWidth>
              <access>read-write</access>
              <enumeratedValues>
                <enumeratedValue>
                  <name>0</name>
                  <description>Configured interrupt is not detected.</description>
                  <value>#0</value>
                </enumeratedValue>
                <enumeratedValue>
                  <name>1</name>
                  <description>Configured interrupt is detected. If the pin is configured to generate a DMA request, then the corresponding flag will be cleared automatically at the completion of the requested DMA transfer. Otherwise, the flag remains set until a logic 1 is written to the flag. If the pin is configured for a level sensitive interrupt and the pin remains asserted, then the flag is set again immediately after it is cleared.</description>
                  <value>#1</value>
                </enumeratedValue>
              </enumeratedValues>
            </field>
          </fields>
        </register>
      </registers>
    </peripheral>
    <peripheral>
      <name>PORTC</name>
      <description>Pin Control and Interrupts</description>
      <groupName>PORT</groupName>
      <prependToName>PORTC_</prependToName>
      <baseAddress>0x4004B000</baseAddress>
      <addressBlock>
        <offset>0</offset>
        <size>0xA4</size>
        <usage>registers</usage>
      </addressBlock>
      <interrupt>
        <name>PORTC_PORTD</name>
        <value>31</value>
      </interrupt>
      <registers>
        <register>
          <dim>32</dim>
          <dimIncrement>0x4</dimIncrement>
          <dimIndex>0,1,2,3,4,5,6,7,8,9,10,11,12,13,14,15,16,17,18,19,20,21,22,23,24,25,26,27,28,29,30,31</dimIndex>
          <name>PCR%s</name>
          <description>Pin Control Register n</description>
          <addressOffset>0</addressOffset>
          <size>32</size>
          <access>read-write</access>
          <resetValue>0x5</resetValue>
          <resetMask>0xFFFFFFFF</resetMask>
          <fields>
            <field>
              <name>PS</name>
              <description>Pull Select</description>
              <bitOffset>0</bitOffset>
              <bitWidth>1</bitWidth>
              <access>read-write</access>
              <enumeratedValues>
                <enumeratedValue>
                  <name>0</name>
                  <description>Internal pulldown resistor is enabled on the corresponding pin, if the corresponding PE field is set.</description>
                  <value>#0</value>
                </enumeratedValue>
                <enumeratedValue>
                  <name>1</name>
                  <description>Internal pullup resistor is enabled on the corresponding pin, if the corresponding PE field is set.</description>
                  <value>#1</value>
                </enumeratedValue>
              </enumeratedValues>
            </field>
            <field>
              <name>PE</name>
              <description>Pull Enable</description>
              <bitOffset>1</bitOffset>
              <bitWidth>1</bitWidth>
              <access>read-write</access>
              <enumeratedValues>
                <enumeratedValue>
                  <name>0</name>
                  <description>Internal pullup or pulldown resistor is not enabled on the corresponding pin.</description>
                  <value>#0</value>
                </enumeratedValue>
                <enumeratedValue>
                  <name>1</name>
                  <description>Internal pullup or pulldown resistor is enabled on the corresponding pin, if the pin is configured as a digital input.</description>
                  <value>#1</value>
                </enumeratedValue>
              </enumeratedValues>
            </field>
            <field>
              <name>SRE</name>
              <description>Slew Rate Enable</description>
              <bitOffset>2</bitOffset>
              <bitWidth>1</bitWidth>
              <access>read-write</access>
              <enumeratedValues>
                <enumeratedValue>
                  <name>0</name>
                  <description>Fast slew rate is configured on the corresponding pin, if the pin is configured as a digital output.</description>
                  <value>#0</value>
                </enumeratedValue>
                <enumeratedValue>
                  <name>1</name>
                  <description>Slow slew rate is configured on the corresponding pin, if the pin is configured as a digital output.</description>
                  <value>#1</value>
                </enumeratedValue>
              </enumeratedValues>
            </field>
            <field>
              <name>PFE</name>
              <description>Passive Filter Enable</description>
              <bitOffset>4</bitOffset>
              <bitWidth>1</bitWidth>
              <access>read-write</access>
              <enumeratedValues>
                <enumeratedValue>
                  <name>0</name>
                  <description>Passive input filter is disabled on the corresponding pin.</description>
                  <value>#0</value>
                </enumeratedValue>
                <enumeratedValue>
                  <name>1</name>
                  <description>Passive input filter is enabled on the corresponding pin, if the pin is configured as a digital input. Refer to the device data sheet for filter characteristics.</description>
                  <value>#1</value>
                </enumeratedValue>
              </enumeratedValues>
            </field>
            <field>
              <name>DSE</name>
              <description>Drive Strength Enable</description>
              <bitOffset>6</bitOffset>
              <bitWidth>1</bitWidth>
              <access>read-write</access>
              <enumeratedValues>
                <enumeratedValue>
                  <name>0</name>
                  <description>Low drive strength is configured on the corresponding pin, if pin is configured as a digital output.</description>
                  <value>#0</value>
                </enumeratedValue>
                <enumeratedValue>
                  <name>1</name>
                  <description>High drive strength is configured on the corresponding pin, if pin is configured as a digital output.</description>
                  <value>#1</value>
                </enumeratedValue>
              </enumeratedValues>
            </field>
            <field>
              <name>MUX</name>
              <description>Pin Mux Control</description>
              <bitOffset>8</bitOffset>
              <bitWidth>3</bitWidth>
              <access>read-write</access>
              <enumeratedValues>
                <enumeratedValue>
                  <name>000</name>
                  <description>Pin disabled (analog).</description>
                  <value>#000</value>
                </enumeratedValue>
                <enumeratedValue>
                  <name>001</name>
                  <description>Alternative 1 (GPIO).</description>
                  <value>#001</value>
                </enumeratedValue>
                <enumeratedValue>
                  <name>010</name>
                  <description>Alternative 2 (chip-specific).</description>
                  <value>#010</value>
                </enumeratedValue>
                <enumeratedValue>
                  <name>011</name>
                  <description>Alternative 3 (chip-specific).</description>
                  <value>#011</value>
                </enumeratedValue>
                <enumeratedValue>
                  <name>100</name>
                  <description>Alternative 4 (chip-specific).</description>
                  <value>#100</value>
                </enumeratedValue>
                <enumeratedValue>
                  <name>101</name>
                  <description>Alternative 5 (chip-specific).</description>
                  <value>#101</value>
                </enumeratedValue>
                <enumeratedValue>
                  <name>110</name>
                  <description>Alternative 6 (chip-specific).</description>
                  <value>#110</value>
                </enumeratedValue>
                <enumeratedValue>
                  <name>111</name>
                  <description>Alternative 7 (chip-specific).</description>
                  <value>#111</value>
                </enumeratedValue>
              </enumeratedValues>
            </field>
            <field>
              <name>IRQC</name>
              <description>Interrupt Configuration</description>
              <bitOffset>16</bitOffset>
              <bitWidth>4</bitWidth>
              <access>read-write</access>
              <enumeratedValues>
                <enumeratedValue>
                  <name>0000</name>
                  <description>Interrupt/DMA request disabled.</description>
                  <value>#0000</value>
                </enumeratedValue>
                <enumeratedValue>
                  <name>0001</name>
                  <description>DMA request on rising edge.</description>
                  <value>#0001</value>
                </enumeratedValue>
                <enumeratedValue>
                  <name>0010</name>
                  <description>DMA request on falling edge.</description>
                  <value>#0010</value>
                </enumeratedValue>
                <enumeratedValue>
                  <name>0011</name>
                  <description>DMA request on either edge.</description>
                  <value>#0011</value>
                </enumeratedValue>
                <enumeratedValue>
                  <name>1000</name>
                  <description>Interrupt when logic 0.</description>
                  <value>#1000</value>
                </enumeratedValue>
                <enumeratedValue>
                  <name>1001</name>
                  <description>Interrupt on rising-edge.</description>
                  <value>#1001</value>
                </enumeratedValue>
                <enumeratedValue>
                  <name>1010</name>
                  <description>Interrupt on falling-edge.</description>
                  <value>#1010</value>
                </enumeratedValue>
                <enumeratedValue>
                  <name>1011</name>
                  <description>Interrupt on either edge.</description>
                  <value>#1011</value>
                </enumeratedValue>
                <enumeratedValue>
                  <name>1100</name>
                  <description>Interrupt when logic 1.</description>
                  <value>#1100</value>
                </enumeratedValue>
              </enumeratedValues>
            </field>
            <field>
              <name>ISF</name>
              <description>Interrupt Status Flag</description>
              <bitOffset>24</bitOffset>
              <bitWidth>1</bitWidth>
              <access>read-write</access>
              <enumeratedValues>
                <enumeratedValue>
                  <name>0</name>
                  <description>Configured interrupt is not detected.</description>
                  <value>#0</value>
                </enumeratedValue>
                <enumeratedValue>
                  <name>1</name>
                  <description>Configured interrupt is detected. If the pin is configured to generate a DMA request, then the corresponding flag will be cleared automatically at the completion of the requested DMA transfer. Otherwise, the flag remains set until a logic 1 is written to the flag. If the pin is configured for a level sensitive interrupt and the pin remains asserted, then the flag is set again immediately after it is cleared.</description>
                  <value>#1</value>
                </enumeratedValue>
              </enumeratedValues>
            </field>
          </fields>
        </register>
        <register>
          <name>GPCLR</name>
          <description>Global Pin Control Low Register</description>
          <addressOffset>0x80</addressOffset>
          <size>32</size>
          <access>write-only</access>
          <resetValue>0</resetValue>
          <resetMask>0xFFFFFFFF</resetMask>
          <fields>
            <field>
              <name>GPWD</name>
              <description>Global Pin Write Data</description>
              <bitOffset>0</bitOffset>
              <bitWidth>16</bitWidth>
              <access>write-only</access>
            </field>
            <field>
              <name>GPWE</name>
              <description>Global Pin Write Enable</description>
              <bitOffset>16</bitOffset>
              <bitWidth>16</bitWidth>
              <access>write-only</access>
              <enumeratedValues>
                <enumeratedValue>
                  <name>0</name>
                  <description>Corresponding Pin Control Register is not updated with the value in GPWD.</description>
                  <value>#0</value>
                </enumeratedValue>
                <enumeratedValue>
                  <name>1</name>
                  <description>Corresponding Pin Control Register is updated with the value in GPWD.</description>
                  <value>#1</value>
                </enumeratedValue>
              </enumeratedValues>
            </field>
          </fields>
        </register>
        <register>
          <name>GPCHR</name>
          <description>Global Pin Control High Register</description>
          <addressOffset>0x84</addressOffset>
          <size>32</size>
          <access>write-only</access>
          <resetValue>0</resetValue>
          <resetMask>0xFFFFFFFF</resetMask>
          <fields>
            <field>
              <name>GPWD</name>
              <description>Global Pin Write Data</description>
              <bitOffset>0</bitOffset>
              <bitWidth>16</bitWidth>
              <access>write-only</access>
            </field>
            <field>
              <name>GPWE</name>
              <description>Global Pin Write Enable</description>
              <bitOffset>16</bitOffset>
              <bitWidth>16</bitWidth>
              <access>write-only</access>
              <enumeratedValues>
                <enumeratedValue>
                  <name>0</name>
                  <description>Corresponding Pin Control Register is not updated with the value in GPWD.</description>
                  <value>#0</value>
                </enumeratedValue>
                <enumeratedValue>
                  <name>1</name>
                  <description>Corresponding Pin Control Register is updated with the value in GPWD.</description>
                  <value>#1</value>
                </enumeratedValue>
              </enumeratedValues>
            </field>
          </fields>
        </register>
        <register>
          <name>ISFR</name>
          <description>Interrupt Status Flag Register</description>
          <addressOffset>0xA0</addressOffset>
          <size>32</size>
          <access>read-write</access>
          <resetValue>0</resetValue>
          <resetMask>0xFFFFFFFF</resetMask>
          <fields>
            <field>
              <name>ISF</name>
              <description>Interrupt Status Flag</description>
              <bitOffset>0</bitOffset>
              <bitWidth>32</bitWidth>
              <access>read-write</access>
              <enumeratedValues>
                <enumeratedValue>
                  <name>0</name>
                  <description>Configured interrupt is not detected.</description>
                  <value>#0</value>
                </enumeratedValue>
                <enumeratedValue>
                  <name>1</name>
                  <description>Configured interrupt is detected. If the pin is configured to generate a DMA request, then the corresponding flag will be cleared automatically at the completion of the requested DMA transfer. Otherwise, the flag remains set until a logic 1 is written to the flag. If the pin is configured for a level sensitive interrupt and the pin remains asserted, then the flag is set again immediately after it is cleared.</description>
                  <value>#1</value>
                </enumeratedValue>
              </enumeratedValues>
            </field>
          </fields>
        </register>
      </registers>
    </peripheral>
    <peripheral>
      <name>PORTD</name>
      <description>Pin Control and Interrupts</description>
      <groupName>PORT</groupName>
      <prependToName>PORTD_</prependToName>
      <baseAddress>0x4004C000</baseAddress>
      <addressBlock>
        <offset>0</offset>
        <size>0xA4</size>
        <usage>registers</usage>
      </addressBlock>
      <interrupt>
        <name>PORTC_PORTD</name>
        <value>31</value>
      </interrupt>
      <registers>
        <register>
          <dim>32</dim>
          <dimIncrement>0x4</dimIncrement>
          <dimIndex>0,1,2,3,4,5,6,7,8,9,10,11,12,13,14,15,16,17,18,19,20,21,22,23,24,25,26,27,28,29,30,31</dimIndex>
          <name>PCR%s</name>
          <description>Pin Control Register n</description>
          <addressOffset>0</addressOffset>
          <size>32</size>
          <access>read-write</access>
          <resetValue>0x5</resetValue>
          <resetMask>0xFFFFFFFF</resetMask>
          <fields>
            <field>
              <name>PS</name>
              <description>Pull Select</description>
              <bitOffset>0</bitOffset>
              <bitWidth>1</bitWidth>
              <access>read-write</access>
              <enumeratedValues>
                <enumeratedValue>
                  <name>0</name>
                  <description>Internal pulldown resistor is enabled on the corresponding pin, if the corresponding PE field is set.</description>
                  <value>#0</value>
                </enumeratedValue>
                <enumeratedValue>
                  <name>1</name>
                  <description>Internal pullup resistor is enabled on the corresponding pin, if the corresponding PE field is set.</description>
                  <value>#1</value>
                </enumeratedValue>
              </enumeratedValues>
            </field>
            <field>
              <name>PE</name>
              <description>Pull Enable</description>
              <bitOffset>1</bitOffset>
              <bitWidth>1</bitWidth>
              <access>read-write</access>
              <enumeratedValues>
                <enumeratedValue>
                  <name>0</name>
                  <description>Internal pullup or pulldown resistor is not enabled on the corresponding pin.</description>
                  <value>#0</value>
                </enumeratedValue>
                <enumeratedValue>
                  <name>1</name>
                  <description>Internal pullup or pulldown resistor is enabled on the corresponding pin, if the pin is configured as a digital input.</description>
                  <value>#1</value>
                </enumeratedValue>
              </enumeratedValues>
            </field>
            <field>
              <name>SRE</name>
              <description>Slew Rate Enable</description>
              <bitOffset>2</bitOffset>
              <bitWidth>1</bitWidth>
              <access>read-write</access>
              <enumeratedValues>
                <enumeratedValue>
                  <name>0</name>
                  <description>Fast slew rate is configured on the corresponding pin, if the pin is configured as a digital output.</description>
                  <value>#0</value>
                </enumeratedValue>
                <enumeratedValue>
                  <name>1</name>
                  <description>Slow slew rate is configured on the corresponding pin, if the pin is configured as a digital output.</description>
                  <value>#1</value>
                </enumeratedValue>
              </enumeratedValues>
            </field>
            <field>
              <name>PFE</name>
              <description>Passive Filter Enable</description>
              <bitOffset>4</bitOffset>
              <bitWidth>1</bitWidth>
              <access>read-write</access>
              <enumeratedValues>
                <enumeratedValue>
                  <name>0</name>
                  <description>Passive input filter is disabled on the corresponding pin.</description>
                  <value>#0</value>
                </enumeratedValue>
                <enumeratedValue>
                  <name>1</name>
                  <description>Passive input filter is enabled on the corresponding pin, if the pin is configured as a digital input. Refer to the device data sheet for filter characteristics.</description>
                  <value>#1</value>
                </enumeratedValue>
              </enumeratedValues>
            </field>
            <field>
              <name>DSE</name>
              <description>Drive Strength Enable</description>
              <bitOffset>6</bitOffset>
              <bitWidth>1</bitWidth>
              <access>read-write</access>
              <enumeratedValues>
                <enumeratedValue>
                  <name>0</name>
                  <description>Low drive strength is configured on the corresponding pin, if pin is configured as a digital output.</description>
                  <value>#0</value>
                </enumeratedValue>
                <enumeratedValue>
                  <name>1</name>
                  <description>High drive strength is configured on the corresponding pin, if pin is configured as a digital output.</description>
                  <value>#1</value>
                </enumeratedValue>
              </enumeratedValues>
            </field>
            <field>
              <name>MUX</name>
              <description>Pin Mux Control</description>
              <bitOffset>8</bitOffset>
              <bitWidth>3</bitWidth>
              <access>read-write</access>
              <enumeratedValues>
                <enumeratedValue>
                  <name>000</name>
                  <description>Pin disabled (analog).</description>
                  <value>#000</value>
                </enumeratedValue>
                <enumeratedValue>
                  <name>001</name>
                  <description>Alternative 1 (GPIO).</description>
                  <value>#001</value>
                </enumeratedValue>
                <enumeratedValue>
                  <name>010</name>
                  <description>Alternative 2 (chip-specific).</description>
                  <value>#010</value>
                </enumeratedValue>
                <enumeratedValue>
                  <name>011</name>
                  <description>Alternative 3 (chip-specific).</description>
                  <value>#011</value>
                </enumeratedValue>
                <enumeratedValue>
                  <name>100</name>
                  <description>Alternative 4 (chip-specific).</description>
                  <value>#100</value>
                </enumeratedValue>
                <enumeratedValue>
                  <name>101</name>
                  <description>Alternative 5 (chip-specific).</description>
                  <value>#101</value>
                </enumeratedValue>
                <enumeratedValue>
                  <name>110</name>
                  <description>Alternative 6 (chip-specific).</description>
                  <value>#110</value>
                </enumeratedValue>
                <enumeratedValue>
                  <name>111</name>
                  <description>Alternative 7 (chip-specific).</description>
                  <value>#111</value>
                </enumeratedValue>
              </enumeratedValues>
            </field>
            <field>
              <name>IRQC</name>
              <description>Interrupt Configuration</description>
              <bitOffset>16</bitOffset>
              <bitWidth>4</bitWidth>
              <access>read-write</access>
              <enumeratedValues>
                <enumeratedValue>
                  <name>0000</name>
                  <description>Interrupt/DMA request disabled.</description>
                  <value>#0000</value>
                </enumeratedValue>
                <enumeratedValue>
                  <name>0001</name>
                  <description>DMA request on rising edge.</description>
                  <value>#0001</value>
                </enumeratedValue>
                <enumeratedValue>
                  <name>0010</name>
                  <description>DMA request on falling edge.</description>
                  <value>#0010</value>
                </enumeratedValue>
                <enumeratedValue>
                  <name>0011</name>
                  <description>DMA request on either edge.</description>
                  <value>#0011</value>
                </enumeratedValue>
                <enumeratedValue>
                  <name>1000</name>
                  <description>Interrupt when logic 0.</description>
                  <value>#1000</value>
                </enumeratedValue>
                <enumeratedValue>
                  <name>1001</name>
                  <description>Interrupt on rising-edge.</description>
                  <value>#1001</value>
                </enumeratedValue>
                <enumeratedValue>
                  <name>1010</name>
                  <description>Interrupt on falling-edge.</description>
                  <value>#1010</value>
                </enumeratedValue>
                <enumeratedValue>
                  <name>1011</name>
                  <description>Interrupt on either edge.</description>
                  <value>#1011</value>
                </enumeratedValue>
                <enumeratedValue>
                  <name>1100</name>
                  <description>Interrupt when logic 1.</description>
                  <value>#1100</value>
                </enumeratedValue>
              </enumeratedValues>
            </field>
            <field>
              <name>ISF</name>
              <description>Interrupt Status Flag</description>
              <bitOffset>24</bitOffset>
              <bitWidth>1</bitWidth>
              <access>read-write</access>
              <enumeratedValues>
                <enumeratedValue>
                  <name>0</name>
                  <description>Configured interrupt is not detected.</description>
                  <value>#0</value>
                </enumeratedValue>
                <enumeratedValue>
                  <name>1</name>
                  <description>Configured interrupt is detected. If the pin is configured to generate a DMA request, then the corresponding flag will be cleared automatically at the completion of the requested DMA transfer. Otherwise, the flag remains set until a logic 1 is written to the flag. If the pin is configured for a level sensitive interrupt and the pin remains asserted, then the flag is set again immediately after it is cleared.</description>
                  <value>#1</value>
                </enumeratedValue>
              </enumeratedValues>
            </field>
          </fields>
        </register>
        <register>
          <name>GPCLR</name>
          <description>Global Pin Control Low Register</description>
          <addressOffset>0x80</addressOffset>
          <size>32</size>
          <access>write-only</access>
          <resetValue>0</resetValue>
          <resetMask>0xFFFFFFFF</resetMask>
          <fields>
            <field>
              <name>GPWD</name>
              <description>Global Pin Write Data</description>
              <bitOffset>0</bitOffset>
              <bitWidth>16</bitWidth>
              <access>write-only</access>
            </field>
            <field>
              <name>GPWE</name>
              <description>Global Pin Write Enable</description>
              <bitOffset>16</bitOffset>
              <bitWidth>16</bitWidth>
              <access>write-only</access>
              <enumeratedValues>
                <enumeratedValue>
                  <name>0</name>
                  <description>Corresponding Pin Control Register is not updated with the value in GPWD.</description>
                  <value>#0</value>
                </enumeratedValue>
                <enumeratedValue>
                  <name>1</name>
                  <description>Corresponding Pin Control Register is updated with the value in GPWD.</description>
                  <value>#1</value>
                </enumeratedValue>
              </enumeratedValues>
            </field>
          </fields>
        </register>
        <register>
          <name>GPCHR</name>
          <description>Global Pin Control High Register</description>
          <addressOffset>0x84</addressOffset>
          <size>32</size>
          <access>write-only</access>
          <resetValue>0</resetValue>
          <resetMask>0xFFFFFFFF</resetMask>
          <fields>
            <field>
              <name>GPWD</name>
              <description>Global Pin Write Data</description>
              <bitOffset>0</bitOffset>
              <bitWidth>16</bitWidth>
              <access>write-only</access>
            </field>
            <field>
              <name>GPWE</name>
              <description>Global Pin Write Enable</description>
              <bitOffset>16</bitOffset>
              <bitWidth>16</bitWidth>
              <access>write-only</access>
              <enumeratedValues>
                <enumeratedValue>
                  <name>0</name>
                  <description>Corresponding Pin Control Register is not updated with the value in GPWD.</description>
                  <value>#0</value>
                </enumeratedValue>
                <enumeratedValue>
                  <name>1</name>
                  <description>Corresponding Pin Control Register is updated with the value in GPWD.</description>
                  <value>#1</value>
                </enumeratedValue>
              </enumeratedValues>
            </field>
          </fields>
        </register>
        <register>
          <name>ISFR</name>
          <description>Interrupt Status Flag Register</description>
          <addressOffset>0xA0</addressOffset>
          <size>32</size>
          <access>read-write</access>
          <resetValue>0</resetValue>
          <resetMask>0xFFFFFFFF</resetMask>
          <fields>
            <field>
              <name>ISF</name>
              <description>Interrupt Status Flag</description>
              <bitOffset>0</bitOffset>
              <bitWidth>32</bitWidth>
              <access>read-write</access>
              <enumeratedValues>
                <enumeratedValue>
                  <name>0</name>
                  <description>Configured interrupt is not detected.</description>
                  <value>#0</value>
                </enumeratedValue>
                <enumeratedValue>
                  <name>1</name>
                  <description>Configured interrupt is detected. If the pin is configured to generate a DMA request, then the corresponding flag will be cleared automatically at the completion of the requested DMA transfer. Otherwise, the flag remains set until a logic 1 is written to the flag. If the pin is configured for a level sensitive interrupt and the pin remains asserted, then the flag is set again immediately after it is cleared.</description>
                  <value>#1</value>
                </enumeratedValue>
              </enumeratedValues>
            </field>
          </fields>
        </register>
      </registers>
    </peripheral>
    <peripheral>
      <name>PORTE</name>
      <description>Pin Control and Interrupts</description>
      <groupName>PORT</groupName>
      <prependToName>PORTE_</prependToName>
      <baseAddress>0x4004D000</baseAddress>
      <addressBlock>
        <offset>0</offset>
        <size>0xA4</size>
        <usage>registers</usage>
      </addressBlock>
      <registers>
        <register>
          <dim>32</dim>
          <dimIncrement>0x4</dimIncrement>
          <dimIndex>0,1,2,3,4,5,6,7,8,9,10,11,12,13,14,15,16,17,18,19,20,21,22,23,24,25,26,27,28,29,30,31</dimIndex>
          <name>PCR%s</name>
          <description>Pin Control Register n</description>
          <addressOffset>0</addressOffset>
          <size>32</size>
          <access>read-write</access>
          <resetValue>0x5</resetValue>
          <resetMask>0xFFFFFFFF</resetMask>
          <fields>
            <field>
              <name>PS</name>
              <description>Pull Select</description>
              <bitOffset>0</bitOffset>
              <bitWidth>1</bitWidth>
              <access>read-write</access>
              <enumeratedValues>
                <enumeratedValue>
                  <name>0</name>
                  <description>Internal pulldown resistor is enabled on the corresponding pin, if the corresponding PE field is set.</description>
                  <value>#0</value>
                </enumeratedValue>
                <enumeratedValue>
                  <name>1</name>
                  <description>Internal pullup resistor is enabled on the corresponding pin, if the corresponding PE field is set.</description>
                  <value>#1</value>
                </enumeratedValue>
              </enumeratedValues>
            </field>
            <field>
              <name>PE</name>
              <description>Pull Enable</description>
              <bitOffset>1</bitOffset>
              <bitWidth>1</bitWidth>
              <access>read-write</access>
              <enumeratedValues>
                <enumeratedValue>
                  <name>0</name>
                  <description>Internal pullup or pulldown resistor is not enabled on the corresponding pin.</description>
                  <value>#0</value>
                </enumeratedValue>
                <enumeratedValue>
                  <name>1</name>
                  <description>Internal pullup or pulldown resistor is enabled on the corresponding pin, if the pin is configured as a digital input.</description>
                  <value>#1</value>
                </enumeratedValue>
              </enumeratedValues>
            </field>
            <field>
              <name>SRE</name>
              <description>Slew Rate Enable</description>
              <bitOffset>2</bitOffset>
              <bitWidth>1</bitWidth>
              <access>read-write</access>
              <enumeratedValues>
                <enumeratedValue>
                  <name>0</name>
                  <description>Fast slew rate is configured on the corresponding pin, if the pin is configured as a digital output.</description>
                  <value>#0</value>
                </enumeratedValue>
                <enumeratedValue>
                  <name>1</name>
                  <description>Slow slew rate is configured on the corresponding pin, if the pin is configured as a digital output.</description>
                  <value>#1</value>
                </enumeratedValue>
              </enumeratedValues>
            </field>
            <field>
              <name>PFE</name>
              <description>Passive Filter Enable</description>
              <bitOffset>4</bitOffset>
              <bitWidth>1</bitWidth>
              <access>read-write</access>
              <enumeratedValues>
                <enumeratedValue>
                  <name>0</name>
                  <description>Passive input filter is disabled on the corresponding pin.</description>
                  <value>#0</value>
                </enumeratedValue>
                <enumeratedValue>
                  <name>1</name>
                  <description>Passive input filter is enabled on the corresponding pin, if the pin is configured as a digital input. Refer to the device data sheet for filter characteristics.</description>
                  <value>#1</value>
                </enumeratedValue>
              </enumeratedValues>
            </field>
            <field>
              <name>DSE</name>
              <description>Drive Strength Enable</description>
              <bitOffset>6</bitOffset>
              <bitWidth>1</bitWidth>
              <access>read-write</access>
              <enumeratedValues>
                <enumeratedValue>
                  <name>0</name>
                  <description>Low drive strength is configured on the corresponding pin, if pin is configured as a digital output.</description>
                  <value>#0</value>
                </enumeratedValue>
                <enumeratedValue>
                  <name>1</name>
                  <description>High drive strength is configured on the corresponding pin, if pin is configured as a digital output.</description>
                  <value>#1</value>
                </enumeratedValue>
              </enumeratedValues>
            </field>
            <field>
              <name>MUX</name>
              <description>Pin Mux Control</description>
              <bitOffset>8</bitOffset>
              <bitWidth>3</bitWidth>
              <access>read-write</access>
              <enumeratedValues>
                <enumeratedValue>
                  <name>000</name>
                  <description>Pin disabled (analog).</description>
                  <value>#000</value>
                </enumeratedValue>
                <enumeratedValue>
                  <name>001</name>
                  <description>Alternative 1 (GPIO).</description>
                  <value>#001</value>
                </enumeratedValue>
                <enumeratedValue>
                  <name>010</name>
                  <description>Alternative 2 (chip-specific).</description>
                  <value>#010</value>
                </enumeratedValue>
                <enumeratedValue>
                  <name>011</name>
                  <description>Alternative 3 (chip-specific).</description>
                  <value>#011</value>
                </enumeratedValue>
                <enumeratedValue>
                  <name>100</name>
                  <description>Alternative 4 (chip-specific).</description>
                  <value>#100</value>
                </enumeratedValue>
                <enumeratedValue>
                  <name>101</name>
                  <description>Alternative 5 (chip-specific).</description>
                  <value>#101</value>
                </enumeratedValue>
                <enumeratedValue>
                  <name>110</name>
                  <description>Alternative 6 (chip-specific).</description>
                  <value>#110</value>
                </enumeratedValue>
                <enumeratedValue>
                  <name>111</name>
                  <description>Alternative 7 (chip-specific).</description>
                  <value>#111</value>
                </enumeratedValue>
              </enumeratedValues>
            </field>
            <field>
              <name>IRQC</name>
              <description>Interrupt Configuration</description>
              <bitOffset>16</bitOffset>
              <bitWidth>4</bitWidth>
              <access>read-write</access>
              <enumeratedValues>
                <enumeratedValue>
                  <name>0000</name>
                  <description>Interrupt/DMA request disabled.</description>
                  <value>#0000</value>
                </enumeratedValue>
                <enumeratedValue>
                  <name>0001</name>
                  <description>DMA request on rising edge.</description>
                  <value>#0001</value>
                </enumeratedValue>
                <enumeratedValue>
                  <name>0010</name>
                  <description>DMA request on falling edge.</description>
                  <value>#0010</value>
                </enumeratedValue>
                <enumeratedValue>
                  <name>0011</name>
                  <description>DMA request on either edge.</description>
                  <value>#0011</value>
                </enumeratedValue>
                <enumeratedValue>
                  <name>1000</name>
                  <description>Interrupt when logic 0.</description>
                  <value>#1000</value>
                </enumeratedValue>
                <enumeratedValue>
                  <name>1001</name>
                  <description>Interrupt on rising-edge.</description>
                  <value>#1001</value>
                </enumeratedValue>
                <enumeratedValue>
                  <name>1010</name>
                  <description>Interrupt on falling-edge.</description>
                  <value>#1010</value>
                </enumeratedValue>
                <enumeratedValue>
                  <name>1011</name>
                  <description>Interrupt on either edge.</description>
                  <value>#1011</value>
                </enumeratedValue>
                <enumeratedValue>
                  <name>1100</name>
                  <description>Interrupt when logic 1.</description>
                  <value>#1100</value>
                </enumeratedValue>
              </enumeratedValues>
            </field>
            <field>
              <name>ISF</name>
              <description>Interrupt Status Flag</description>
              <bitOffset>24</bitOffset>
              <bitWidth>1</bitWidth>
              <access>read-write</access>
              <enumeratedValues>
                <enumeratedValue>
                  <name>0</name>
                  <description>Configured interrupt is not detected.</description>
                  <value>#0</value>
                </enumeratedValue>
                <enumeratedValue>
                  <name>1</name>
                  <description>Configured interrupt is detected. If the pin is configured to generate a DMA request, then the corresponding flag will be cleared automatically at the completion of the requested DMA transfer. Otherwise, the flag remains set until a logic 1 is written to the flag. If the pin is configured for a level sensitive interrupt and the pin remains asserted, then the flag is set again immediately after it is cleared.</description>
                  <value>#1</value>
                </enumeratedValue>
              </enumeratedValues>
            </field>
          </fields>
        </register>
        <register>
          <name>GPCLR</name>
          <description>Global Pin Control Low Register</description>
          <addressOffset>0x80</addressOffset>
          <size>32</size>
          <access>write-only</access>
          <resetValue>0</resetValue>
          <resetMask>0xFFFFFFFF</resetMask>
          <fields>
            <field>
              <name>GPWD</name>
              <description>Global Pin Write Data</description>
              <bitOffset>0</bitOffset>
              <bitWidth>16</bitWidth>
              <access>write-only</access>
            </field>
            <field>
              <name>GPWE</name>
              <description>Global Pin Write Enable</description>
              <bitOffset>16</bitOffset>
              <bitWidth>16</bitWidth>
              <access>write-only</access>
              <enumeratedValues>
                <enumeratedValue>
                  <name>0</name>
                  <description>Corresponding Pin Control Register is not updated with the value in GPWD.</description>
                  <value>#0</value>
                </enumeratedValue>
                <enumeratedValue>
                  <name>1</name>
                  <description>Corresponding Pin Control Register is updated with the value in GPWD.</description>
                  <value>#1</value>
                </enumeratedValue>
              </enumeratedValues>
            </field>
          </fields>
        </register>
        <register>
          <name>GPCHR</name>
          <description>Global Pin Control High Register</description>
          <addressOffset>0x84</addressOffset>
          <size>32</size>
          <access>write-only</access>
          <resetValue>0</resetValue>
          <resetMask>0xFFFFFFFF</resetMask>
          <fields>
            <field>
              <name>GPWD</name>
              <description>Global Pin Write Data</description>
              <bitOffset>0</bitOffset>
              <bitWidth>16</bitWidth>
              <access>write-only</access>
            </field>
            <field>
              <name>GPWE</name>
              <description>Global Pin Write Enable</description>
              <bitOffset>16</bitOffset>
              <bitWidth>16</bitWidth>
              <access>write-only</access>
              <enumeratedValues>
                <enumeratedValue>
                  <name>0</name>
                  <description>Corresponding Pin Control Register is not updated with the value in GPWD.</description>
                  <value>#0</value>
                </enumeratedValue>
                <enumeratedValue>
                  <name>1</name>
                  <description>Corresponding Pin Control Register is updated with the value in GPWD.</description>
                  <value>#1</value>
                </enumeratedValue>
              </enumeratedValues>
            </field>
          </fields>
        </register>
        <register>
          <name>ISFR</name>
          <description>Interrupt Status Flag Register</description>
          <addressOffset>0xA0</addressOffset>
          <size>32</size>
          <access>read-write</access>
          <resetValue>0</resetValue>
          <resetMask>0xFFFFFFFF</resetMask>
          <fields>
            <field>
              <name>ISF</name>
              <description>Interrupt Status Flag</description>
              <bitOffset>0</bitOffset>
              <bitWidth>32</bitWidth>
              <access>read-write</access>
              <enumeratedValues>
                <enumeratedValue>
                  <name>0</name>
                  <description>Configured interrupt is not detected.</description>
                  <value>#0</value>
                </enumeratedValue>
                <enumeratedValue>
                  <name>1</name>
                  <description>Configured interrupt is detected. If the pin is configured to generate a DMA request, then the corresponding flag will be cleared automatically at the completion of the requested DMA transfer. Otherwise, the flag remains set until a logic 1 is written to the flag. If the pin is configured for a level sensitive interrupt and the pin remains asserted, then the flag is set again immediately after it is cleared.</description>
                  <value>#1</value>
                </enumeratedValue>
              </enumeratedValues>
            </field>
          </fields>
        </register>
      </registers>
    </peripheral>
    <peripheral>
      <name>LCD</name>
      <description>Segment Liquid Crystal Display</description>
      <prependToName>LCD_</prependToName>
      <baseAddress>0x40053000</baseAddress>
      <addressBlock>
        <offset>0</offset>
        <size>0x60</size>
        <usage>registers</usage>
      </addressBlock>
      <interrupt>
        <name>LCD</name>
        <value>29</value>
      </interrupt>
      <registers>
        <register>
          <name>GCR</name>
          <description>LCD General Control Register</description>
          <addressOffset>0</addressOffset>
          <size>32</size>
          <access>read-write</access>
          <resetValue>0x8300003</resetValue>
          <resetMask>0xFFFFFFFF</resetMask>
          <fields>
            <field>
              <name>DUTY</name>
              <description>LCD duty select</description>
              <bitOffset>0</bitOffset>
              <bitWidth>3</bitWidth>
              <access>read-write</access>
              <enumeratedValues>
                <enumeratedValue>
                  <name>000</name>
                  <description>Use 1 BP (1/1 duty cycle).</description>
                  <value>#000</value>
                </enumeratedValue>
                <enumeratedValue>
                  <name>001</name>
                  <description>Use 2 BP (1/2 duty cycle).</description>
                  <value>#001</value>
                </enumeratedValue>
                <enumeratedValue>
                  <name>010</name>
                  <description>Use 3 BP (1/3 duty cycle).</description>
                  <value>#010</value>
                </enumeratedValue>
                <enumeratedValue>
                  <name>011</name>
                  <description>Use 4 BP (1/4 duty cycle). (Default)</description>
                  <value>#011</value>
                </enumeratedValue>
                <enumeratedValue>
                  <name>111</name>
                  <description>Use 8 BP (1/8 duty cycle).</description>
                  <value>#111</value>
                </enumeratedValue>
              </enumeratedValues>
            </field>
            <field>
              <name>LCLK</name>
              <description>LCD Clock Prescaler</description>
              <bitOffset>3</bitOffset>
              <bitWidth>3</bitWidth>
              <access>read-write</access>
            </field>
            <field>
              <name>SOURCE</name>
              <description>LCD Clock Source Select</description>
              <bitOffset>6</bitOffset>
              <bitWidth>1</bitWidth>
              <access>read-write</access>
              <enumeratedValues>
                <enumeratedValue>
                  <name>0</name>
                  <description>Selects the default clock as the LCD clock source.</description>
                  <value>#0</value>
                </enumeratedValue>
                <enumeratedValue>
                  <name>1</name>
                  <description>Selects output of the alternate clock source selection (see ALTSOURCE) as the LCD clock source.</description>
                  <value>#1</value>
                </enumeratedValue>
              </enumeratedValues>
            </field>
            <field>
              <name>LCDEN</name>
              <description>LCD Driver Enable</description>
              <bitOffset>7</bitOffset>
              <bitWidth>1</bitWidth>
              <access>read-write</access>
              <enumeratedValues>
                <enumeratedValue>
                  <name>0</name>
                  <description>All front plane and back plane pins are disabled. The LCD controller system is also disabled, and all LCD waveform generation clocks are stopped. V LL3 is connected to V DD internally. All LCD pins, LCD_Pn, enabled using the LCD Pin Enable register, output a low value.</description>
                  <value>#0</value>
                </enumeratedValue>
                <enumeratedValue>
                  <name>1</name>
                  <description>LCD controller driver system is enabled, and front plane and back plane waveforms are generated. All LCD pins, LCD_Pn, enabled if PAD_SAFE is clearusing the LCD Pin Enable register, output an LCD driver waveform. The back plane pins output an LCD driver back plane waveform based on the settings of DUTY[2:0]. Charge pump or resistor bias is enabled.</description>
                  <value>#1</value>
                </enumeratedValue>
              </enumeratedValues>
            </field>
            <field>
              <name>LCDSTP</name>
              <description>LCD Stop</description>
              <bitOffset>8</bitOffset>
              <bitWidth>1</bitWidth>
              <access>read-write</access>
              <enumeratedValues>
                <enumeratedValue>
                  <name>0</name>
                  <description>Allows the LCD driver, charge pump, resistor bias network, and voltage regulator to continue running during Stop mode.</description>
                  <value>#0</value>
                </enumeratedValue>
                <enumeratedValue>
                  <name>1</name>
                  <description>Disables the LCD driver, charge pump, resistor bias network, and voltage regulator when MCU enters Stop mode.</description>
                  <value>#1</value>
                </enumeratedValue>
              </enumeratedValues>
            </field>
            <field>
              <name>LCDDOZE</name>
              <description>LCD Doze enable</description>
              <bitOffset>9</bitOffset>
              <bitWidth>1</bitWidth>
              <access>read-write</access>
              <enumeratedValues>
                <enumeratedValue>
                  <name>0</name>
                  <description>Allows the LCD driver, charge pump, resistor bias network, and voltage regulator to continue running during Doze mode.</description>
                  <value>#0</value>
                </enumeratedValue>
                <enumeratedValue>
                  <name>1</name>
                  <description>Disables the LCD driver, charge pump, resistor bias network, and voltage regulator when MCU enters Doze mode.</description>
                  <value>#1</value>
                </enumeratedValue>
              </enumeratedValues>
            </field>
            <field>
              <name>FFR</name>
              <description>Fast Frame Rate Select</description>
              <bitOffset>10</bitOffset>
              <bitWidth>1</bitWidth>
              <access>read-write</access>
              <enumeratedValues>
                <enumeratedValue>
                  <name>0</name>
                  <description>Standard Frame Rate LCD Frame Freq: 23.3 (min) 73.1 (max)</description>
                  <value>#0</value>
                </enumeratedValue>
                <enumeratedValue>
                  <name>1</name>
                  <description>Fast Frame Rate (Standard Frame Rate x2) LCD Frame Freq: 46.6 (min) 146.2 (max)</description>
                  <value>#1</value>
                </enumeratedValue>
              </enumeratedValues>
            </field>
            <field>
              <name>ALTSOURCE</name>
              <description>Selects the alternate clock source</description>
              <bitOffset>11</bitOffset>
              <bitWidth>1</bitWidth>
              <access>read-write</access>
              <enumeratedValues>
                <enumeratedValue>
                  <name>0</name>
                  <description>Select Alternate Clock Source 1 (default)</description>
                  <value>#0</value>
                </enumeratedValue>
                <enumeratedValue>
                  <name>1</name>
                  <description>Select Alternate Clock Source 2</description>
                  <value>#1</value>
                </enumeratedValue>
              </enumeratedValues>
            </field>
            <field>
              <name>ALTDIV</name>
              <description>LCD AlternateClock Divider</description>
              <bitOffset>12</bitOffset>
              <bitWidth>2</bitWidth>
              <access>read-write</access>
              <enumeratedValues>
                <enumeratedValue>
                  <name>0</name>
                  <description>Divide factor = 1 (No divide)</description>
                  <value>#00</value>
                </enumeratedValue>
                <enumeratedValue>
                  <name>1</name>
                  <description>Divide factor = 8</description>
                  <value>#01</value>
                </enumeratedValue>
              </enumeratedValues>
            </field>
            <field>
              <name>FDCIEN</name>
              <description>LCD Fault Detection Complete Interrupt Enable</description>
              <bitOffset>14</bitOffset>
              <bitWidth>1</bitWidth>
              <access>read-write</access>
              <enumeratedValues>
                <enumeratedValue>
                  <name>0</name>
                  <description>No interrupt request is generated by this event.</description>
                  <value>#0</value>
                </enumeratedValue>
                <enumeratedValue>
                  <name>1</name>
                  <description>When a fault is detected and FDCF bit is set, this event causes an interrupt request.</description>
                  <value>#1</value>
                </enumeratedValue>
              </enumeratedValues>
            </field>
            <field>
              <name>PADSAFE</name>
              <description>Pad Safe State Enable</description>
              <bitOffset>15</bitOffset>
              <bitWidth>1</bitWidth>
              <access>read-write</access>
              <enumeratedValues>
                <enumeratedValue>
                  <name>0</name>
                  <description>LCD frontplane and backplane functions enabled according to other LCD control bits</description>
                  <value>#0</value>
                </enumeratedValue>
                <enumeratedValue>
                  <name>1</name>
                  <description>LCD frontplane and backplane functions disabled</description>
                  <value>#1</value>
                </enumeratedValue>
              </enumeratedValues>
            </field>
            <field>
              <name>VSUPPLY</name>
              <description>Voltage Supply Control</description>
              <bitOffset>17</bitOffset>
              <bitWidth>1</bitWidth>
              <access>read-write</access>
              <enumeratedValues>
                <enumeratedValue>
                  <name>0</name>
                  <description>Drive VLL3 internally from VDD</description>
                  <value>#0</value>
                </enumeratedValue>
                <enumeratedValue>
                  <name>1</name>
                  <description>Drive VLL3 externally from VDD or drive VLL internally from vIREG</description>
                  <value>#1</value>
                </enumeratedValue>
              </enumeratedValues>
            </field>
            <field>
              <name>LADJ</name>
              <description>Load Adjust</description>
              <bitOffset>20</bitOffset>
              <bitWidth>2</bitWidth>
              <access>read-write</access>
            </field>
            <field>
              <name>CPSEL</name>
              <description>Charge Pump or Resistor Bias Select</description>
              <bitOffset>23</bitOffset>
              <bitWidth>1</bitWidth>
              <access>read-write</access>
              <enumeratedValues>
                <enumeratedValue>
                  <name>0</name>
                  <description>LCD charge pump is disabled. Resistor network selected. (The internal 1/3-bias is forced.)</description>
                  <value>#0</value>
                </enumeratedValue>
                <enumeratedValue>
                  <name>1</name>
                  <description>LCD charge pump is selected. Resistor network disabled. (The internal 1/3-bias is forced.)</description>
                  <value>#1</value>
                </enumeratedValue>
              </enumeratedValues>
            </field>
            <field>
              <name>RVTRIM</name>
              <description>Regulated Voltage Trim</description>
              <bitOffset>24</bitOffset>
              <bitWidth>4</bitWidth>
              <access>read-write</access>
            </field>
            <field>
              <name>RVEN</name>
              <description>Regulated Voltage Enable</description>
              <bitOffset>31</bitOffset>
              <bitWidth>1</bitWidth>
              <access>read-write</access>
              <enumeratedValues>
                <enumeratedValue>
                  <name>0</name>
                  <description>Regulated voltage disabled.</description>
                  <value>#0</value>
                </enumeratedValue>
                <enumeratedValue>
                  <name>1</name>
                  <description>Regulated voltage enabled.</description>
                  <value>#1</value>
                </enumeratedValue>
              </enumeratedValues>
            </field>
          </fields>
        </register>
        <register>
          <name>AR</name>
          <description>LCD Auxiliary Register</description>
          <addressOffset>0x4</addressOffset>
          <size>32</size>
          <access>read-write</access>
          <resetValue>0</resetValue>
          <resetMask>0xFFFFFFFF</resetMask>
          <fields>
            <field>
              <name>BRATE</name>
              <description>Blink-rate configuration</description>
              <bitOffset>0</bitOffset>
              <bitWidth>3</bitWidth>
              <access>read-write</access>
            </field>
            <field>
              <name>BMODE</name>
              <description>Blink mode</description>
              <bitOffset>3</bitOffset>
              <bitWidth>1</bitWidth>
              <access>read-write</access>
              <enumeratedValues>
                <enumeratedValue>
                  <name>0</name>
                  <description>Display blank during the blink period.</description>
                  <value>#0</value>
                </enumeratedValue>
                <enumeratedValue>
                  <name>1</name>
                  <description>Display alternate display during blink period (Ignored if duty is 5 or greater).</description>
                  <value>#1</value>
                </enumeratedValue>
              </enumeratedValues>
            </field>
            <field>
              <name>BLANK</name>
              <description>Blank display mode</description>
              <bitOffset>5</bitOffset>
              <bitWidth>1</bitWidth>
              <access>read-write</access>
              <enumeratedValues>
                <enumeratedValue>
                  <name>0</name>
                  <description>Normal or alternate display mode.</description>
                  <value>#0</value>
                </enumeratedValue>
                <enumeratedValue>
                  <name>1</name>
                  <description>Blank display mode.</description>
                  <value>#1</value>
                </enumeratedValue>
              </enumeratedValues>
            </field>
            <field>
              <name>ALT</name>
              <description>Alternate display mode</description>
              <bitOffset>6</bitOffset>
              <bitWidth>1</bitWidth>
              <access>read-write</access>
              <enumeratedValues>
                <enumeratedValue>
                  <name>0</name>
                  <description>Normal display mode.</description>
                  <value>#0</value>
                </enumeratedValue>
                <enumeratedValue>
                  <name>1</name>
                  <description>Alternate display mode.</description>
                  <value>#1</value>
                </enumeratedValue>
              </enumeratedValues>
            </field>
            <field>
              <name>BLINK</name>
              <description>Blink command</description>
              <bitOffset>7</bitOffset>
              <bitWidth>1</bitWidth>
              <access>read-write</access>
              <enumeratedValues>
                <enumeratedValue>
                  <name>0</name>
                  <description>Disables blinking.</description>
                  <value>#0</value>
                </enumeratedValue>
                <enumeratedValue>
                  <name>1</name>
                  <description>Starts blinking at blinking frequency specified by LCD blink rate calculation.</description>
                  <value>#1</value>
                </enumeratedValue>
              </enumeratedValues>
            </field>
          </fields>
        </register>
        <register>
          <name>FDCR</name>
          <description>LCD Fault Detect Control Register</description>
          <addressOffset>0x8</addressOffset>
          <size>32</size>
          <access>read-write</access>
          <resetValue>0</resetValue>
          <resetMask>0xFFFFFFFF</resetMask>
          <fields>
            <field>
              <name>FDPINID</name>
              <description>Fault Detect Pin ID</description>
              <bitOffset>0</bitOffset>
              <bitWidth>6</bitWidth>
              <access>read-write</access>
              <enumeratedValues>
                <enumeratedValue>
                  <name>0</name>
                  <description>Fault detection for LCD_P0 pin.</description>
                  <value>#0</value>
                </enumeratedValue>
                <enumeratedValue>
                  <name>1</name>
                  <description>Fault detection for LCD_P1 pin.</description>
                  <value>#1</value>
                </enumeratedValue>
              </enumeratedValues>
            </field>
            <field>
              <name>FDBPEN</name>
              <description>Fault Detect Back Plane Enable</description>
              <bitOffset>6</bitOffset>
              <bitWidth>1</bitWidth>
              <access>read-write</access>
              <enumeratedValues>
                <enumeratedValue>
                  <name>0</name>
                  <description>Type of the selected pin under fault detect test is front plane.</description>
                  <value>#0</value>
                </enumeratedValue>
                <enumeratedValue>
                  <name>1</name>
                  <description>Type of the selected pin under fault detect test is back plane.</description>
                  <value>#1</value>
                </enumeratedValue>
              </enumeratedValues>
            </field>
            <field>
              <name>FDEN</name>
              <description>Fault Detect Enable</description>
              <bitOffset>7</bitOffset>
              <bitWidth>1</bitWidth>
              <access>read-write</access>
              <enumeratedValues>
                <enumeratedValue>
                  <name>0</name>
                  <description>Disable fault detection.</description>
                  <value>#0</value>
                </enumeratedValue>
                <enumeratedValue>
                  <name>1</name>
                  <description>Enable fault detection.</description>
                  <value>#1</value>
                </enumeratedValue>
              </enumeratedValues>
            </field>
            <field>
              <name>FDSWW</name>
              <description>Fault Detect Sample Window Width</description>
              <bitOffset>9</bitOffset>
              <bitWidth>3</bitWidth>
              <access>read-write</access>
              <enumeratedValues>
                <enumeratedValue>
                  <name>0</name>
                  <description>Sample window width is 4 sample clock cycles.</description>
                  <value>#000</value>
                </enumeratedValue>
                <enumeratedValue>
                  <name>1</name>
                  <description>Sample window width is 8 sample clock cycles.</description>
                  <value>#001</value>
                </enumeratedValue>
              </enumeratedValues>
            </field>
            <field>
              <name>FDPRS</name>
              <description>Fault Detect Clock Prescaler</description>
              <bitOffset>12</bitOffset>
              <bitWidth>3</bitWidth>
              <access>read-write</access>
              <enumeratedValues>
                <enumeratedValue>
                  <name>0</name>
                  <description>1/1 bus clock.</description>
                  <value>#000</value>
                </enumeratedValue>
                <enumeratedValue>
                  <name>1</name>
                  <description>1/2 bus clock.</description>
                  <value>#001</value>
                </enumeratedValue>
              </enumeratedValues>
            </field>
          </fields>
        </register>
        <register>
          <name>FDSR</name>
          <description>LCD Fault Detect Status Register</description>
          <addressOffset>0xC</addressOffset>
          <size>32</size>
          <access>read-write</access>
          <resetValue>0</resetValue>
          <resetMask>0xFFFFFFFF</resetMask>
          <fields>
            <field>
              <name>FDCNT</name>
              <description>Fault Detect Counter</description>
              <bitOffset>0</bitOffset>
              <bitWidth>8</bitWidth>
              <access>read-only</access>
              <enumeratedValues>
                <enumeratedValue>
                  <name>0</name>
                  <description>No &quot;one&quot; samples.</description>
                  <value>#0</value>
                </enumeratedValue>
                <enumeratedValue>
                  <name>1</name>
                  <description>1 &quot;one&quot; samples.</description>
                  <value>#1</value>
                </enumeratedValue>
              </enumeratedValues>
            </field>
            <field>
              <name>FDCF</name>
              <description>Fault Detection Complete Flag</description>
              <bitOffset>15</bitOffset>
              <bitWidth>1</bitWidth>
              <access>read-write</access>
              <enumeratedValues>
                <enumeratedValue>
                  <name>0</name>
                  <description>Fault detection is not completed.</description>
                  <value>#0</value>
                </enumeratedValue>
                <enumeratedValue>
                  <name>1</name>
                  <description>Fault detection is completed.</description>
                  <value>#1</value>
                </enumeratedValue>
              </enumeratedValues>
            </field>
          </fields>
        </register>
        <register>
          <dim>2</dim>
          <dimIncrement>0x4</dimIncrement>
          <dimIndex>L,H</dimIndex>
          <name>PEN%s</name>
          <description>LCD Pin Enable register</description>
          <addressOffset>0x10</addressOffset>
          <size>32</size>
          <access>read-write</access>
          <resetValue>0</resetValue>
          <resetMask>0xFFFFFFFF</resetMask>
          <fields>
            <field>
              <name>PEN</name>
              <description>LCD Pin Enable</description>
              <bitOffset>0</bitOffset>
              <bitWidth>32</bitWidth>
              <access>read-write</access>
              <enumeratedValues>
                <enumeratedValue>
                  <name>0</name>
                  <description>LCD operation disabled on LCD_Pn.</description>
                  <value>#0</value>
                </enumeratedValue>
                <enumeratedValue>
                  <name>1</name>
                  <description>LCD operation enabled on LCD_Pn.</description>
                  <value>#1</value>
                </enumeratedValue>
              </enumeratedValues>
            </field>
          </fields>
        </register>
        <register>
          <dim>2</dim>
          <dimIncrement>0x4</dimIncrement>
          <dimIndex>L,H</dimIndex>
          <name>BPEN%s</name>
          <description>LCD Back Plane Enable register</description>
          <addressOffset>0x18</addressOffset>
          <size>32</size>
          <access>read-write</access>
          <resetValue>0</resetValue>
          <resetMask>0xFFFFFFFF</resetMask>
          <fields>
            <field>
              <name>BPEN</name>
              <description>Back Plane Enable</description>
              <bitOffset>0</bitOffset>
              <bitWidth>32</bitWidth>
              <access>read-write</access>
              <enumeratedValues>
                <enumeratedValue>
                  <name>0</name>
                  <description>Front plane operation enabled on LCD_Pn.</description>
                  <value>#0</value>
                </enumeratedValue>
                <enumeratedValue>
                  <name>1</name>
                  <description>Back plane operation enabled on LCD_Pn.</description>
                  <value>#1</value>
                </enumeratedValue>
              </enumeratedValues>
            </field>
          </fields>
        </register>
        <register>
          <name>WF3TO0</name>
          <description>LCD Waveform register</description>
          <alternateGroup>LCD</alternateGroup>
          <addressOffset>0x20</addressOffset>
          <size>32</size>
          <access>read-write</access>
          <resetValue>0</resetValue>
          <resetMask>0xFFFFFFFF</resetMask>
          <fields>
            <field>
              <name>WF0</name>
              <description>Controls segments or phases connected to LCD_P0 as described above for WF3.</description>
              <bitOffset>0</bitOffset>
              <bitWidth>8</bitWidth>
              <access>read-write</access>
            </field>
            <field>
              <name>WF1</name>
              <description>Controls segments or phases connected to LCD_P1 as described above for WF3.</description>
              <bitOffset>8</bitOffset>
              <bitWidth>8</bitWidth>
              <access>read-write</access>
            </field>
            <field>
              <name>WF2</name>
              <description>Controls segments or phases connected to LCD_P2 as described above for WF3.</description>
              <bitOffset>16</bitOffset>
              <bitWidth>8</bitWidth>
              <access>read-write</access>
            </field>
            <field>
              <name>WF3</name>
              <description>Segment-on front plane operation - Each bit turns on or off the segments associated with LCD_P3 in the following pattern: HGFEDCBA (most significant bit controls segment H and least significant bit controls segment A)</description>
              <bitOffset>24</bitOffset>
              <bitWidth>8</bitWidth>
              <access>read-write</access>
            </field>
          </fields>
        </register>
        <register>
          <name>WF0</name>
          <description>LCD Waveform Register 0.</description>
          <alternateGroup>LCD</alternateGroup>
          <addressOffset>0x20</addressOffset>
          <size>8</size>
          <access>read-write</access>
          <resetValue>0</resetValue>
          <resetMask>0</resetMask>
          <fields>
            <field>
              <name>BPALCD0</name>
              <description>no description available</description>
              <bitOffset>0</bitOffset>
              <bitWidth>1</bitWidth>
              <access>read-write</access>
              <enumeratedValues>
                <enumeratedValue>
                  <name>0</name>
                  <description>LCD segment off or LCD backplane inactive for phase A</description>
                  <value>#0</value>
                </enumeratedValue>
                <enumeratedValue>
                  <name>1</name>
                  <description>LCD segment on or LCD backplane active for phase A</description>
                  <value>#1</value>
                </enumeratedValue>
              </enumeratedValues>
            </field>
            <field>
              <name>BPBLCD0</name>
              <description>no description available</description>
              <bitOffset>1</bitOffset>
              <bitWidth>1</bitWidth>
              <access>read-write</access>
              <enumeratedValues>
                <enumeratedValue>
                  <name>0</name>
                  <description>LCD segment off or LCD backplane inactive for phase B</description>
                  <value>#0</value>
                </enumeratedValue>
                <enumeratedValue>
                  <name>1</name>
                  <description>LCD segment on or LCD backplane active for phase B</description>
                  <value>#1</value>
                </enumeratedValue>
              </enumeratedValues>
            </field>
            <field>
              <name>BPCLCD0</name>
              <description>no description available</description>
              <bitOffset>2</bitOffset>
              <bitWidth>1</bitWidth>
              <access>read-write</access>
              <enumeratedValues>
                <enumeratedValue>
                  <name>0</name>
                  <description>LCD segment off or LCD backplane inactive for phase C</description>
                  <value>#0</value>
                </enumeratedValue>
                <enumeratedValue>
                  <name>1</name>
                  <description>LCD segment on or LCD backplane active for phase C</description>
                  <value>#1</value>
                </enumeratedValue>
              </enumeratedValues>
            </field>
            <field>
              <name>BPDLCD0</name>
              <description>no description available</description>
              <bitOffset>3</bitOffset>
              <bitWidth>1</bitWidth>
              <access>read-write</access>
              <enumeratedValues>
                <enumeratedValue>
                  <name>0</name>
                  <description>LCD segment off or LCD backplane inactive for phase D</description>
                  <value>#0</value>
                </enumeratedValue>
                <enumeratedValue>
                  <name>1</name>
                  <description>LCD segment on or LCD backplane active for phase D</description>
                  <value>#1</value>
                </enumeratedValue>
              </enumeratedValues>
            </field>
            <field>
              <name>BPELCD0</name>
              <description>no description available</description>
              <bitOffset>4</bitOffset>
              <bitWidth>1</bitWidth>
              <access>read-write</access>
              <enumeratedValues>
                <enumeratedValue>
                  <name>0</name>
                  <description>LCD segment off or LCD backplane inactive for phase E</description>
                  <value>#0</value>
                </enumeratedValue>
                <enumeratedValue>
                  <name>1</name>
                  <description>LCD segment on or LCD backplane active for phase E</description>
                  <value>#1</value>
                </enumeratedValue>
              </enumeratedValues>
            </field>
            <field>
              <name>BPFLCD0</name>
              <description>no description available</description>
              <bitOffset>5</bitOffset>
              <bitWidth>1</bitWidth>
              <access>read-write</access>
              <enumeratedValues>
                <enumeratedValue>
                  <name>0</name>
                  <description>LCD segment off or LCD backplane inactive for phase F</description>
                  <value>#0</value>
                </enumeratedValue>
                <enumeratedValue>
                  <name>1</name>
                  <description>LCD segment on or LCD backplane active for phase F</description>
                  <value>#1</value>
                </enumeratedValue>
              </enumeratedValues>
            </field>
            <field>
              <name>BPGLCD0</name>
              <description>no description available</description>
              <bitOffset>6</bitOffset>
              <bitWidth>1</bitWidth>
              <access>read-write</access>
              <enumeratedValues>
                <enumeratedValue>
                  <name>0</name>
                  <description>LCD segment off or LCD backplane inactive for phase G</description>
                  <value>#0</value>
                </enumeratedValue>
                <enumeratedValue>
                  <name>1</name>
                  <description>LCD segment on or LCD backplane active for phase G</description>
                  <value>#1</value>
                </enumeratedValue>
              </enumeratedValues>
            </field>
            <field>
              <name>BPHLCD0</name>
              <description>no description available</description>
              <bitOffset>7</bitOffset>
              <bitWidth>1</bitWidth>
              <access>read-write</access>
              <enumeratedValues>
                <enumeratedValue>
                  <name>0</name>
                  <description>LCD segment off or LCD backplane inactive for phase H</description>
                  <value>#0</value>
                </enumeratedValue>
                <enumeratedValue>
                  <name>1</name>
                  <description>LCD segment on or LCD backplane active for phase H</description>
                  <value>#1</value>
                </enumeratedValue>
              </enumeratedValues>
            </field>
          </fields>
        </register>
        <register>
          <name>WF1</name>
          <description>LCD Waveform Register 1.</description>
          <addressOffset>0x21</addressOffset>
          <size>8</size>
          <access>read-write</access>
          <resetValue>0</resetValue>
          <resetMask>0</resetMask>
          <fields>
            <field>
              <name>BPALCD1</name>
              <description>no description available</description>
              <bitOffset>0</bitOffset>
              <bitWidth>1</bitWidth>
              <access>read-write</access>
              <enumeratedValues>
                <enumeratedValue>
                  <name>0</name>
                  <description>LCD segment off or LCD backplane inactive for phase A</description>
                  <value>#0</value>
                </enumeratedValue>
                <enumeratedValue>
                  <name>1</name>
                  <description>LCD segment on or LCD backplane active for phase A</description>
                  <value>#1</value>
                </enumeratedValue>
              </enumeratedValues>
            </field>
            <field>
              <name>BPBLCD1</name>
              <description>no description available</description>
              <bitOffset>1</bitOffset>
              <bitWidth>1</bitWidth>
              <access>read-write</access>
              <enumeratedValues>
                <enumeratedValue>
                  <name>0</name>
                  <description>LCD segment off or LCD backplane inactive for phase B</description>
                  <value>#0</value>
                </enumeratedValue>
                <enumeratedValue>
                  <name>1</name>
                  <description>LCD segment on or LCD backplane active for phase B</description>
                  <value>#1</value>
                </enumeratedValue>
              </enumeratedValues>
            </field>
            <field>
              <name>BPCLCD1</name>
              <description>no description available</description>
              <bitOffset>2</bitOffset>
              <bitWidth>1</bitWidth>
              <access>read-write</access>
              <enumeratedValues>
                <enumeratedValue>
                  <name>0</name>
                  <description>LCD segment off or LCD backplane inactive for phase C</description>
                  <value>#0</value>
                </enumeratedValue>
                <enumeratedValue>
                  <name>1</name>
                  <description>LCD segment on or LCD backplane active for phase C</description>
                  <value>#1</value>
                </enumeratedValue>
              </enumeratedValues>
            </field>
            <field>
              <name>BPDLCD1</name>
              <description>no description available</description>
              <bitOffset>3</bitOffset>
              <bitWidth>1</bitWidth>
              <access>read-write</access>
              <enumeratedValues>
                <enumeratedValue>
                  <name>0</name>
                  <description>LCD segment off or LCD backplane inactive for phase D</description>
                  <value>#0</value>
                </enumeratedValue>
                <enumeratedValue>
                  <name>1</name>
                  <description>LCD segment on or LCD backplane active for phase D</description>
                  <value>#1</value>
                </enumeratedValue>
              </enumeratedValues>
            </field>
            <field>
              <name>BPELCD1</name>
              <description>no description available</description>
              <bitOffset>4</bitOffset>
              <bitWidth>1</bitWidth>
              <access>read-write</access>
              <enumeratedValues>
                <enumeratedValue>
                  <name>0</name>
                  <description>LCD segment off or LCD backplane inactive for phase E</description>
                  <value>#0</value>
                </enumeratedValue>
                <enumeratedValue>
                  <name>1</name>
                  <description>LCD segment on or LCD backplane active for phase E</description>
                  <value>#1</value>
                </enumeratedValue>
              </enumeratedValues>
            </field>
            <field>
              <name>BPFLCD1</name>
              <description>no description available</description>
              <bitOffset>5</bitOffset>
              <bitWidth>1</bitWidth>
              <access>read-write</access>
              <enumeratedValues>
                <enumeratedValue>
                  <name>0</name>
                  <description>LCD segment off or LCD backplane inactive for phase F</description>
                  <value>#0</value>
                </enumeratedValue>
                <enumeratedValue>
                  <name>1</name>
                  <description>LCD segment on or LCD backplane active for phase F</description>
                  <value>#1</value>
                </enumeratedValue>
              </enumeratedValues>
            </field>
            <field>
              <name>BPGLCD1</name>
              <description>no description available</description>
              <bitOffset>6</bitOffset>
              <bitWidth>1</bitWidth>
              <access>read-write</access>
              <enumeratedValues>
                <enumeratedValue>
                  <name>0</name>
                  <description>LCD segment off or LCD backplane inactive for phase G</description>
                  <value>#0</value>
                </enumeratedValue>
                <enumeratedValue>
                  <name>1</name>
                  <description>LCD segment on or LCD backplane active for phase G</description>
                  <value>#1</value>
                </enumeratedValue>
              </enumeratedValues>
            </field>
            <field>
              <name>BPHLCD1</name>
              <description>no description available</description>
              <bitOffset>7</bitOffset>
              <bitWidth>1</bitWidth>
              <access>read-write</access>
              <enumeratedValues>
                <enumeratedValue>
                  <name>0</name>
                  <description>LCD segment off or LCD backplane inactive for phase H</description>
                  <value>#0</value>
                </enumeratedValue>
                <enumeratedValue>
                  <name>1</name>
                  <description>LCD segment on or LCD backplane active for phase H</description>
                  <value>#1</value>
                </enumeratedValue>
              </enumeratedValues>
            </field>
          </fields>
        </register>
        <register>
          <name>WF2</name>
          <description>LCD Waveform Register 2.</description>
          <addressOffset>0x22</addressOffset>
          <size>8</size>
          <access>read-write</access>
          <resetValue>0</resetValue>
          <resetMask>0</resetMask>
          <fields>
            <field>
              <name>BPALCD2</name>
              <description>no description available</description>
              <bitOffset>0</bitOffset>
              <bitWidth>1</bitWidth>
              <access>read-write</access>
              <enumeratedValues>
                <enumeratedValue>
                  <name>0</name>
                  <description>LCD segment off or LCD backplane inactive for phase A</description>
                  <value>#0</value>
                </enumeratedValue>
                <enumeratedValue>
                  <name>1</name>
                  <description>LCD segment on or LCD backplane active for phase A</description>
                  <value>#1</value>
                </enumeratedValue>
              </enumeratedValues>
            </field>
            <field>
              <name>BPBLCD2</name>
              <description>no description available</description>
              <bitOffset>1</bitOffset>
              <bitWidth>1</bitWidth>
              <access>read-write</access>
              <enumeratedValues>
                <enumeratedValue>
                  <name>0</name>
                  <description>LCD segment off or LCD backplane inactive for phase B</description>
                  <value>#0</value>
                </enumeratedValue>
                <enumeratedValue>
                  <name>1</name>
                  <description>LCD segment on or LCD backplane active for phase B</description>
                  <value>#1</value>
                </enumeratedValue>
              </enumeratedValues>
            </field>
            <field>
              <name>BPCLCD2</name>
              <description>no description available</description>
              <bitOffset>2</bitOffset>
              <bitWidth>1</bitWidth>
              <access>read-write</access>
              <enumeratedValues>
                <enumeratedValue>
                  <name>0</name>
                  <description>LCD segment off or LCD backplane inactive for phase C</description>
                  <value>#0</value>
                </enumeratedValue>
                <enumeratedValue>
                  <name>1</name>
                  <description>LCD segment on or LCD backplane active for phase C</description>
                  <value>#1</value>
                </enumeratedValue>
              </enumeratedValues>
            </field>
            <field>
              <name>BPDLCD2</name>
              <description>no description available</description>
              <bitOffset>3</bitOffset>
              <bitWidth>1</bitWidth>
              <access>read-write</access>
              <enumeratedValues>
                <enumeratedValue>
                  <name>0</name>
                  <description>LCD segment off or LCD backplane inactive for phase D</description>
                  <value>#0</value>
                </enumeratedValue>
                <enumeratedValue>
                  <name>1</name>
                  <description>LCD segment on or LCD backplane active for phase D</description>
                  <value>#1</value>
                </enumeratedValue>
              </enumeratedValues>
            </field>
            <field>
              <name>BPELCD2</name>
              <description>no description available</description>
              <bitOffset>4</bitOffset>
              <bitWidth>1</bitWidth>
              <access>read-write</access>
              <enumeratedValues>
                <enumeratedValue>
                  <name>0</name>
                  <description>LCD segment off or LCD backplane inactive for phase E</description>
                  <value>#0</value>
                </enumeratedValue>
                <enumeratedValue>
                  <name>1</name>
                  <description>LCD segment on or LCD backplane active for phase E</description>
                  <value>#1</value>
                </enumeratedValue>
              </enumeratedValues>
            </field>
            <field>
              <name>BPFLCD2</name>
              <description>no description available</description>
              <bitOffset>5</bitOffset>
              <bitWidth>1</bitWidth>
              <access>read-write</access>
              <enumeratedValues>
                <enumeratedValue>
                  <name>0</name>
                  <description>LCD segment off or LCD backplane inactive for phase F</description>
                  <value>#0</value>
                </enumeratedValue>
                <enumeratedValue>
                  <name>1</name>
                  <description>LCD segment on or LCD backplane active for phase F</description>
                  <value>#1</value>
                </enumeratedValue>
              </enumeratedValues>
            </field>
            <field>
              <name>BPGLCD2</name>
              <description>no description available</description>
              <bitOffset>6</bitOffset>
              <bitWidth>1</bitWidth>
              <access>read-write</access>
              <enumeratedValues>
                <enumeratedValue>
                  <name>0</name>
                  <description>LCD segment off or LCD backplane inactive for phase G</description>
                  <value>#0</value>
                </enumeratedValue>
                <enumeratedValue>
                  <name>1</name>
                  <description>LCD segment on or LCD backplane active for phase G</description>
                  <value>#1</value>
                </enumeratedValue>
              </enumeratedValues>
            </field>
            <field>
              <name>BPHLCD2</name>
              <description>no description available</description>
              <bitOffset>7</bitOffset>
              <bitWidth>1</bitWidth>
              <access>read-write</access>
              <enumeratedValues>
                <enumeratedValue>
                  <name>0</name>
                  <description>LCD segment off or LCD backplane inactive for phase H</description>
                  <value>#0</value>
                </enumeratedValue>
                <enumeratedValue>
                  <name>1</name>
                  <description>LCD segment on or LCD backplane active for phase H</description>
                  <value>#1</value>
                </enumeratedValue>
              </enumeratedValues>
            </field>
          </fields>
        </register>
        <register>
          <name>WF3</name>
          <description>LCD Waveform Register 3.</description>
          <addressOffset>0x23</addressOffset>
          <size>8</size>
          <access>read-write</access>
          <resetValue>0</resetValue>
          <resetMask>0</resetMask>
          <fields>
            <field>
              <name>BPALCD3</name>
              <description>no description available</description>
              <bitOffset>0</bitOffset>
              <bitWidth>1</bitWidth>
              <access>read-write</access>
              <enumeratedValues>
                <enumeratedValue>
                  <name>0</name>
                  <description>LCD segment off or LCD backplane inactive for phase A</description>
                  <value>#0</value>
                </enumeratedValue>
                <enumeratedValue>
                  <name>1</name>
                  <description>LCD segment on or LCD backplane active for phase A</description>
                  <value>#1</value>
                </enumeratedValue>
              </enumeratedValues>
            </field>
            <field>
              <name>BPBLCD3</name>
              <description>no description available</description>
              <bitOffset>1</bitOffset>
              <bitWidth>1</bitWidth>
              <access>read-write</access>
              <enumeratedValues>
                <enumeratedValue>
                  <name>0</name>
                  <description>LCD segment off or LCD backplane inactive for phase B</description>
                  <value>#0</value>
                </enumeratedValue>
                <enumeratedValue>
                  <name>1</name>
                  <description>LCD segment on or LCD backplane active for phase B</description>
                  <value>#1</value>
                </enumeratedValue>
              </enumeratedValues>
            </field>
            <field>
              <name>BPCLCD3</name>
              <description>no description available</description>
              <bitOffset>2</bitOffset>
              <bitWidth>1</bitWidth>
              <access>read-write</access>
              <enumeratedValues>
                <enumeratedValue>
                  <name>0</name>
                  <description>LCD segment off or LCD backplane inactive for phase C</description>
                  <value>#0</value>
                </enumeratedValue>
                <enumeratedValue>
                  <name>1</name>
                  <description>LCD segment on or LCD backplane active for phase C</description>
                  <value>#1</value>
                </enumeratedValue>
              </enumeratedValues>
            </field>
            <field>
              <name>BPDLCD3</name>
              <description>no description available</description>
              <bitOffset>3</bitOffset>
              <bitWidth>1</bitWidth>
              <access>read-write</access>
              <enumeratedValues>
                <enumeratedValue>
                  <name>0</name>
                  <description>LCD segment off or LCD backplane inactive for phase D</description>
                  <value>#0</value>
                </enumeratedValue>
                <enumeratedValue>
                  <name>1</name>
                  <description>LCD segment on or LCD backplane active for phase D</description>
                  <value>#1</value>
                </enumeratedValue>
              </enumeratedValues>
            </field>
            <field>
              <name>BPELCD3</name>
              <description>no description available</description>
              <bitOffset>4</bitOffset>
              <bitWidth>1</bitWidth>
              <access>read-write</access>
              <enumeratedValues>
                <enumeratedValue>
                  <name>0</name>
                  <description>LCD segment off or LCD backplane inactive for phase E</description>
                  <value>#0</value>
                </enumeratedValue>
                <enumeratedValue>
                  <name>1</name>
                  <description>LCD segment on or LCD backplane active for phase E</description>
                  <value>#1</value>
                </enumeratedValue>
              </enumeratedValues>
            </field>
            <field>
              <name>BPFLCD3</name>
              <description>no description available</description>
              <bitOffset>5</bitOffset>
              <bitWidth>1</bitWidth>
              <access>read-write</access>
              <enumeratedValues>
                <enumeratedValue>
                  <name>0</name>
                  <description>LCD segment off or LCD backplane inactive for phase F</description>
                  <value>#0</value>
                </enumeratedValue>
                <enumeratedValue>
                  <name>1</name>
                  <description>LCD segment on or LCD backplane active for phase F</description>
                  <value>#1</value>
                </enumeratedValue>
              </enumeratedValues>
            </field>
            <field>
              <name>BPGLCD3</name>
              <description>no description available</description>
              <bitOffset>6</bitOffset>
              <bitWidth>1</bitWidth>
              <access>read-write</access>
              <enumeratedValues>
                <enumeratedValue>
                  <name>0</name>
                  <description>LCD segment off or LCD backplane inactive for phase G</description>
                  <value>#0</value>
                </enumeratedValue>
                <enumeratedValue>
                  <name>1</name>
                  <description>LCD segment on or LCD backplane active for phase G</description>
                  <value>#1</value>
                </enumeratedValue>
              </enumeratedValues>
            </field>
            <field>
              <name>BPHLCD3</name>
              <description>no description available</description>
              <bitOffset>7</bitOffset>
              <bitWidth>1</bitWidth>
              <access>read-write</access>
              <enumeratedValues>
                <enumeratedValue>
                  <name>0</name>
                  <description>LCD segment off or LCD backplane inactive for phase H</description>
                  <value>#0</value>
                </enumeratedValue>
                <enumeratedValue>
                  <name>1</name>
                  <description>LCD segment on or LCD backplane active for phase H</description>
                  <value>#1</value>
                </enumeratedValue>
              </enumeratedValues>
            </field>
          </fields>
        </register>
        <register>
          <name>WF7TO4</name>
          <description>LCD Waveform register</description>
          <alternateGroup>LCD</alternateGroup>
          <addressOffset>0x24</addressOffset>
          <size>32</size>
          <access>read-write</access>
          <resetValue>0</resetValue>
          <resetMask>0xFFFFFFFF</resetMask>
          <fields>
            <field>
              <name>WF4</name>
              <description>Controls segments or phases connected to LCD_P4 as described above for WF3TO0[WF3].</description>
              <bitOffset>0</bitOffset>
              <bitWidth>8</bitWidth>
              <access>read-write</access>
            </field>
            <field>
              <name>WF5</name>
              <description>Controls segments or phases connected to LCD_P5 as described above for WF3TO0[WF3].</description>
              <bitOffset>8</bitOffset>
              <bitWidth>8</bitWidth>
              <access>read-write</access>
            </field>
            <field>
              <name>WF6</name>
              <description>Controls segments or phases connected to LCD_P6 as described above for WF3TO0[WF3].</description>
              <bitOffset>16</bitOffset>
              <bitWidth>8</bitWidth>
              <access>read-write</access>
            </field>
            <field>
              <name>WF7</name>
              <description>Controls segments or phases connected to LCD_P7 as described above for WF3TO0[WF3].</description>
              <bitOffset>24</bitOffset>
              <bitWidth>8</bitWidth>
              <access>read-write</access>
            </field>
          </fields>
        </register>
        <register>
          <name>WF4</name>
          <description>LCD Waveform Register 4.</description>
          <alternateGroup>LCD</alternateGroup>
          <addressOffset>0x24</addressOffset>
          <size>8</size>
          <access>read-write</access>
          <resetValue>0</resetValue>
          <resetMask>0</resetMask>
          <fields>
            <field>
              <name>BPALCD4</name>
              <description>no description available</description>
              <bitOffset>0</bitOffset>
              <bitWidth>1</bitWidth>
              <access>read-write</access>
              <enumeratedValues>
                <enumeratedValue>
                  <name>0</name>
                  <description>LCD segment off or LCD backplane inactive for phase A</description>
                  <value>#0</value>
                </enumeratedValue>
                <enumeratedValue>
                  <name>1</name>
                  <description>LCD segment on or LCD backplane active for phase A</description>
                  <value>#1</value>
                </enumeratedValue>
              </enumeratedValues>
            </field>
            <field>
              <name>BPBLCD4</name>
              <description>no description available</description>
              <bitOffset>1</bitOffset>
              <bitWidth>1</bitWidth>
              <access>read-write</access>
              <enumeratedValues>
                <enumeratedValue>
                  <name>0</name>
                  <description>LCD segment off or LCD backplane inactive for phase B</description>
                  <value>#0</value>
                </enumeratedValue>
                <enumeratedValue>
                  <name>1</name>
                  <description>LCD segment on or LCD backplane active for phase B</description>
                  <value>#1</value>
                </enumeratedValue>
              </enumeratedValues>
            </field>
            <field>
              <name>BPCLCD4</name>
              <description>no description available</description>
              <bitOffset>2</bitOffset>
              <bitWidth>1</bitWidth>
              <access>read-write</access>
              <enumeratedValues>
                <enumeratedValue>
                  <name>0</name>
                  <description>LCD segment off or LCD backplane inactive for phase C</description>
                  <value>#0</value>
                </enumeratedValue>
                <enumeratedValue>
                  <name>1</name>
                  <description>LCD segment on or LCD backplane active for phase C</description>
                  <value>#1</value>
                </enumeratedValue>
              </enumeratedValues>
            </field>
            <field>
              <name>BPDLCD4</name>
              <description>no description available</description>
              <bitOffset>3</bitOffset>
              <bitWidth>1</bitWidth>
              <access>read-write</access>
              <enumeratedValues>
                <enumeratedValue>
                  <name>0</name>
                  <description>LCD segment off or LCD backplane inactive for phase D</description>
                  <value>#0</value>
                </enumeratedValue>
                <enumeratedValue>
                  <name>1</name>
                  <description>LCD segment on or LCD backplane active for phase D</description>
                  <value>#1</value>
                </enumeratedValue>
              </enumeratedValues>
            </field>
            <field>
              <name>BPELCD4</name>
              <description>no description available</description>
              <bitOffset>4</bitOffset>
              <bitWidth>1</bitWidth>
              <access>read-write</access>
              <enumeratedValues>
                <enumeratedValue>
                  <name>0</name>
                  <description>LCD segment off or LCD backplane inactive for phase E</description>
                  <value>#0</value>
                </enumeratedValue>
                <enumeratedValue>
                  <name>1</name>
                  <description>LCD segment on or LCD backplane active for phase E</description>
                  <value>#1</value>
                </enumeratedValue>
              </enumeratedValues>
            </field>
            <field>
              <name>BPFLCD4</name>
              <description>no description available</description>
              <bitOffset>5</bitOffset>
              <bitWidth>1</bitWidth>
              <access>read-write</access>
              <enumeratedValues>
                <enumeratedValue>
                  <name>0</name>
                  <description>LCD segment off or LCD backplane inactive for phase F</description>
                  <value>#0</value>
                </enumeratedValue>
                <enumeratedValue>
                  <name>1</name>
                  <description>LCD segment on or LCD backplane active for phase F</description>
                  <value>#1</value>
                </enumeratedValue>
              </enumeratedValues>
            </field>
            <field>
              <name>BPGLCD4</name>
              <description>no description available</description>
              <bitOffset>6</bitOffset>
              <bitWidth>1</bitWidth>
              <access>read-write</access>
              <enumeratedValues>
                <enumeratedValue>
                  <name>0</name>
                  <description>LCD segment off or LCD backplane inactive for phase G</description>
                  <value>#0</value>
                </enumeratedValue>
                <enumeratedValue>
                  <name>1</name>
                  <description>LCD segment on or LCD backplane active for phase G</description>
                  <value>#1</value>
                </enumeratedValue>
              </enumeratedValues>
            </field>
            <field>
              <name>BPHLCD4</name>
              <description>no description available</description>
              <bitOffset>7</bitOffset>
              <bitWidth>1</bitWidth>
              <access>read-write</access>
              <enumeratedValues>
                <enumeratedValue>
                  <name>0</name>
                  <description>LCD segment off or LCD backplane inactive for phase H</description>
                  <value>#0</value>
                </enumeratedValue>
                <enumeratedValue>
                  <name>1</name>
                  <description>LCD segment on or LCD backplane active for phase H</description>
                  <value>#1</value>
                </enumeratedValue>
              </enumeratedValues>
            </field>
          </fields>
        </register>
        <register>
          <name>WF5</name>
          <description>LCD Waveform Register 5.</description>
          <addressOffset>0x25</addressOffset>
          <size>8</size>
          <access>read-write</access>
          <resetValue>0</resetValue>
          <resetMask>0</resetMask>
          <fields>
            <field>
              <name>BPALCD5</name>
              <description>no description available</description>
              <bitOffset>0</bitOffset>
              <bitWidth>1</bitWidth>
              <access>read-write</access>
              <enumeratedValues>
                <enumeratedValue>
                  <name>0</name>
                  <description>LCD segment off or LCD backplane inactive for phase A</description>
                  <value>#0</value>
                </enumeratedValue>
                <enumeratedValue>
                  <name>1</name>
                  <description>LCD segment on or LCD backplane active for phase A</description>
                  <value>#1</value>
                </enumeratedValue>
              </enumeratedValues>
            </field>
            <field>
              <name>BPBLCD5</name>
              <description>no description available</description>
              <bitOffset>1</bitOffset>
              <bitWidth>1</bitWidth>
              <access>read-write</access>
              <enumeratedValues>
                <enumeratedValue>
                  <name>0</name>
                  <description>LCD segment off or LCD backplane inactive for phase B</description>
                  <value>#0</value>
                </enumeratedValue>
                <enumeratedValue>
                  <name>1</name>
                  <description>LCD segment on or LCD backplane active for phase B</description>
                  <value>#1</value>
                </enumeratedValue>
              </enumeratedValues>
            </field>
            <field>
              <name>BPCLCD5</name>
              <description>no description available</description>
              <bitOffset>2</bitOffset>
              <bitWidth>1</bitWidth>
              <access>read-write</access>
              <enumeratedValues>
                <enumeratedValue>
                  <name>0</name>
                  <description>LCD segment off or LCD backplane inactive for phase C</description>
                  <value>#0</value>
                </enumeratedValue>
                <enumeratedValue>
                  <name>1</name>
                  <description>LCD segment on or LCD backplane active for phase C</description>
                  <value>#1</value>
                </enumeratedValue>
              </enumeratedValues>
            </field>
            <field>
              <name>BPDLCD5</name>
              <description>no description available</description>
              <bitOffset>3</bitOffset>
              <bitWidth>1</bitWidth>
              <access>read-write</access>
              <enumeratedValues>
                <enumeratedValue>
                  <name>0</name>
                  <description>LCD segment off or LCD backplane inactive for phase D</description>
                  <value>#0</value>
                </enumeratedValue>
                <enumeratedValue>
                  <name>1</name>
                  <description>LCD segment on or LCD backplane active for phase D</description>
                  <value>#1</value>
                </enumeratedValue>
              </enumeratedValues>
            </field>
            <field>
              <name>BPELCD5</name>
              <description>no description available</description>
              <bitOffset>4</bitOffset>
              <bitWidth>1</bitWidth>
              <access>read-write</access>
              <enumeratedValues>
                <enumeratedValue>
                  <name>0</name>
                  <description>LCD segment off or LCD backplane inactive for phase E</description>
                  <value>#0</value>
                </enumeratedValue>
                <enumeratedValue>
                  <name>1</name>
                  <description>LCD segment on or LCD backplane active for phase E</description>
                  <value>#1</value>
                </enumeratedValue>
              </enumeratedValues>
            </field>
            <field>
              <name>BPFLCD5</name>
              <description>no description available</description>
              <bitOffset>5</bitOffset>
              <bitWidth>1</bitWidth>
              <access>read-write</access>
              <enumeratedValues>
                <enumeratedValue>
                  <name>0</name>
                  <description>LCD segment off or LCD backplane inactive for phase F</description>
                  <value>#0</value>
                </enumeratedValue>
                <enumeratedValue>
                  <name>1</name>
                  <description>LCD segment on or LCD backplane active for phase F</description>
                  <value>#1</value>
                </enumeratedValue>
              </enumeratedValues>
            </field>
            <field>
              <name>BPGLCD5</name>
              <description>no description available</description>
              <bitOffset>6</bitOffset>
              <bitWidth>1</bitWidth>
              <access>read-write</access>
              <enumeratedValues>
                <enumeratedValue>
                  <name>0</name>
                  <description>LCD segment off or LCD backplane inactive for phase G</description>
                  <value>#0</value>
                </enumeratedValue>
                <enumeratedValue>
                  <name>1</name>
                  <description>LCD segment on or LCD backplane active for phase G</description>
                  <value>#1</value>
                </enumeratedValue>
              </enumeratedValues>
            </field>
            <field>
              <name>BPHLCD5</name>
              <description>no description available</description>
              <bitOffset>7</bitOffset>
              <bitWidth>1</bitWidth>
              <access>read-write</access>
              <enumeratedValues>
                <enumeratedValue>
                  <name>0</name>
                  <description>LCD segment off or LCD backplane inactive for phase H</description>
                  <value>#0</value>
                </enumeratedValue>
                <enumeratedValue>
                  <name>1</name>
                  <description>LCD segment on or LCD backplane active for phase H</description>
                  <value>#1</value>
                </enumeratedValue>
              </enumeratedValues>
            </field>
          </fields>
        </register>
        <register>
          <name>WF6</name>
          <description>LCD Waveform Register 6.</description>
          <addressOffset>0x26</addressOffset>
          <size>8</size>
          <access>read-write</access>
          <resetValue>0</resetValue>
          <resetMask>0</resetMask>
          <fields>
            <field>
              <name>BPALCD6</name>
              <description>no description available</description>
              <bitOffset>0</bitOffset>
              <bitWidth>1</bitWidth>
              <access>read-write</access>
              <enumeratedValues>
                <enumeratedValue>
                  <name>0</name>
                  <description>LCD segment off or LCD backplane inactive for phase A</description>
                  <value>#0</value>
                </enumeratedValue>
                <enumeratedValue>
                  <name>1</name>
                  <description>LCD segment on or LCD backplane active for phase A</description>
                  <value>#1</value>
                </enumeratedValue>
              </enumeratedValues>
            </field>
            <field>
              <name>BPBLCD6</name>
              <description>no description available</description>
              <bitOffset>1</bitOffset>
              <bitWidth>1</bitWidth>
              <access>read-write</access>
              <enumeratedValues>
                <enumeratedValue>
                  <name>0</name>
                  <description>LCD segment off or LCD backplane inactive for phase B</description>
                  <value>#0</value>
                </enumeratedValue>
                <enumeratedValue>
                  <name>1</name>
                  <description>LCD segment on or LCD backplane active for phase B</description>
                  <value>#1</value>
                </enumeratedValue>
              </enumeratedValues>
            </field>
            <field>
              <name>BPCLCD6</name>
              <description>no description available</description>
              <bitOffset>2</bitOffset>
              <bitWidth>1</bitWidth>
              <access>read-write</access>
              <enumeratedValues>
                <enumeratedValue>
                  <name>0</name>
                  <description>LCD segment off or LCD backplane inactive for phase C</description>
                  <value>#0</value>
                </enumeratedValue>
                <enumeratedValue>
                  <name>1</name>
                  <description>LCD segment on or LCD backplane active for phase C</description>
                  <value>#1</value>
                </enumeratedValue>
              </enumeratedValues>
            </field>
            <field>
              <name>BPDLCD6</name>
              <description>no description available</description>
              <bitOffset>3</bitOffset>
              <bitWidth>1</bitWidth>
              <access>read-write</access>
              <enumeratedValues>
                <enumeratedValue>
                  <name>0</name>
                  <description>LCD segment off or LCD backplane inactive for phase D</description>
                  <value>#0</value>
                </enumeratedValue>
                <enumeratedValue>
                  <name>1</name>
                  <description>LCD segment on or LCD backplane active for phase D</description>
                  <value>#1</value>
                </enumeratedValue>
              </enumeratedValues>
            </field>
            <field>
              <name>BPELCD6</name>
              <description>no description available</description>
              <bitOffset>4</bitOffset>
              <bitWidth>1</bitWidth>
              <access>read-write</access>
              <enumeratedValues>
                <enumeratedValue>
                  <name>0</name>
                  <description>LCD segment off or LCD backplane inactive for phase E</description>
                  <value>#0</value>
                </enumeratedValue>
                <enumeratedValue>
                  <name>1</name>
                  <description>LCD segment on or LCD backplane active for phase E</description>
                  <value>#1</value>
                </enumeratedValue>
              </enumeratedValues>
            </field>
            <field>
              <name>BPFLCD6</name>
              <description>no description available</description>
              <bitOffset>5</bitOffset>
              <bitWidth>1</bitWidth>
              <access>read-write</access>
              <enumeratedValues>
                <enumeratedValue>
                  <name>0</name>
                  <description>LCD segment off or LCD backplane inactive for phase F</description>
                  <value>#0</value>
                </enumeratedValue>
                <enumeratedValue>
                  <name>1</name>
                  <description>LCD segment on or LCD backplane active for phase F</description>
                  <value>#1</value>
                </enumeratedValue>
              </enumeratedValues>
            </field>
            <field>
              <name>BPGLCD6</name>
              <description>no description available</description>
              <bitOffset>6</bitOffset>
              <bitWidth>1</bitWidth>
              <access>read-write</access>
              <enumeratedValues>
                <enumeratedValue>
                  <name>0</name>
                  <description>LCD segment off or LCD backplane inactive for phase G</description>
                  <value>#0</value>
                </enumeratedValue>
                <enumeratedValue>
                  <name>1</name>
                  <description>LCD segment on or LCD backplane active for phase G</description>
                  <value>#1</value>
                </enumeratedValue>
              </enumeratedValues>
            </field>
            <field>
              <name>BPHLCD6</name>
              <description>no description available</description>
              <bitOffset>7</bitOffset>
              <bitWidth>1</bitWidth>
              <access>read-write</access>
              <enumeratedValues>
                <enumeratedValue>
                  <name>0</name>
                  <description>LCD segment off or LCD backplane inactive for phase H</description>
                  <value>#0</value>
                </enumeratedValue>
                <enumeratedValue>
                  <name>1</name>
                  <description>LCD segment on or LCD backplane active for phase H</description>
                  <value>#1</value>
                </enumeratedValue>
              </enumeratedValues>
            </field>
          </fields>
        </register>
        <register>
          <name>WF7</name>
          <description>LCD Waveform Register 7.</description>
          <addressOffset>0x27</addressOffset>
          <size>8</size>
          <access>read-write</access>
          <resetValue>0</resetValue>
          <resetMask>0</resetMask>
          <fields>
            <field>
              <name>BPALCD7</name>
              <description>no description available</description>
              <bitOffset>0</bitOffset>
              <bitWidth>1</bitWidth>
              <access>read-write</access>
              <enumeratedValues>
                <enumeratedValue>
                  <name>0</name>
                  <description>LCD segment off or LCD backplane inactive for phase A</description>
                  <value>#0</value>
                </enumeratedValue>
                <enumeratedValue>
                  <name>1</name>
                  <description>LCD segment on or LCD backplane active for phase A</description>
                  <value>#1</value>
                </enumeratedValue>
              </enumeratedValues>
            </field>
            <field>
              <name>BPBLCD7</name>
              <description>no description available</description>
              <bitOffset>1</bitOffset>
              <bitWidth>1</bitWidth>
              <access>read-write</access>
              <enumeratedValues>
                <enumeratedValue>
                  <name>0</name>
                  <description>LCD segment off or LCD backplane inactive for phase B</description>
                  <value>#0</value>
                </enumeratedValue>
                <enumeratedValue>
                  <name>1</name>
                  <description>LCD segment on or LCD backplane active for phase B</description>
                  <value>#1</value>
                </enumeratedValue>
              </enumeratedValues>
            </field>
            <field>
              <name>BPCLCD7</name>
              <description>no description available</description>
              <bitOffset>2</bitOffset>
              <bitWidth>1</bitWidth>
              <access>read-write</access>
              <enumeratedValues>
                <enumeratedValue>
                  <name>0</name>
                  <description>LCD segment off or LCD backplane inactive for phase C</description>
                  <value>#0</value>
                </enumeratedValue>
                <enumeratedValue>
                  <name>1</name>
                  <description>LCD segment on or LCD backplane active for phase C</description>
                  <value>#1</value>
                </enumeratedValue>
              </enumeratedValues>
            </field>
            <field>
              <name>BPDLCD7</name>
              <description>no description available</description>
              <bitOffset>3</bitOffset>
              <bitWidth>1</bitWidth>
              <access>read-write</access>
              <enumeratedValues>
                <enumeratedValue>
                  <name>0</name>
                  <description>LCD segment off or LCD backplane inactive for phase D</description>
                  <value>#0</value>
                </enumeratedValue>
                <enumeratedValue>
                  <name>1</name>
                  <description>LCD segment on or LCD backplane active for phase D</description>
                  <value>#1</value>
                </enumeratedValue>
              </enumeratedValues>
            </field>
            <field>
              <name>BPELCD7</name>
              <description>no description available</description>
              <bitOffset>4</bitOffset>
              <bitWidth>1</bitWidth>
              <access>read-write</access>
              <enumeratedValues>
                <enumeratedValue>
                  <name>0</name>
                  <description>LCD segment off or LCD backplane inactive for phase E</description>
                  <value>#0</value>
                </enumeratedValue>
                <enumeratedValue>
                  <name>1</name>
                  <description>LCD segment on or LCD backplane active for phase E</description>
                  <value>#1</value>
                </enumeratedValue>
              </enumeratedValues>
            </field>
            <field>
              <name>BPFLCD7</name>
              <description>no description available</description>
              <bitOffset>5</bitOffset>
              <bitWidth>1</bitWidth>
              <access>read-write</access>
              <enumeratedValues>
                <enumeratedValue>
                  <name>0</name>
                  <description>LCD segment off or LCD backplane inactive for phase F</description>
                  <value>#0</value>
                </enumeratedValue>
                <enumeratedValue>
                  <name>1</name>
                  <description>LCD segment on or LCD backplane active for phase F</description>
                  <value>#1</value>
                </enumeratedValue>
              </enumeratedValues>
            </field>
            <field>
              <name>BPGLCD7</name>
              <description>no description available</description>
              <bitOffset>6</bitOffset>
              <bitWidth>1</bitWidth>
              <access>read-write</access>
              <enumeratedValues>
                <enumeratedValue>
                  <name>0</name>
                  <description>LCD segment off or LCD backplane inactive for phase G</description>
                  <value>#0</value>
                </enumeratedValue>
                <enumeratedValue>
                  <name>1</name>
                  <description>LCD segment on or LCD backplane active for phase G</description>
                  <value>#1</value>
                </enumeratedValue>
              </enumeratedValues>
            </field>
            <field>
              <name>BPHLCD7</name>
              <description>no description available</description>
              <bitOffset>7</bitOffset>
              <bitWidth>1</bitWidth>
              <access>read-write</access>
              <enumeratedValues>
                <enumeratedValue>
                  <name>0</name>
                  <description>LCD segment off or LCD backplane inactive for phase H</description>
                  <value>#0</value>
                </enumeratedValue>
                <enumeratedValue>
                  <name>1</name>
                  <description>LCD segment on or LCD backplane active for phase H</description>
                  <value>#1</value>
                </enumeratedValue>
              </enumeratedValues>
            </field>
          </fields>
        </register>
        <register>
          <name>WF11TO8</name>
          <description>LCD Waveform register</description>
          <alternateGroup>LCD</alternateGroup>
          <addressOffset>0x28</addressOffset>
          <size>32</size>
          <access>read-write</access>
          <resetValue>0</resetValue>
          <resetMask>0xFFFFFFFF</resetMask>
          <fields>
            <field>
              <name>WF8</name>
              <description>Controls segments or phases connected to LCD_P8 as described above for WF3TO0[WF3].</description>
              <bitOffset>0</bitOffset>
              <bitWidth>8</bitWidth>
              <access>read-write</access>
            </field>
            <field>
              <name>WF9</name>
              <description>Controls segments or phases connected to LCD_P9 as described above for WF3TO0[WF3].</description>
              <bitOffset>8</bitOffset>
              <bitWidth>8</bitWidth>
              <access>read-write</access>
            </field>
            <field>
              <name>WF10</name>
              <description>Controls segments or phases connected to LCD_P10 as described above for WF3TO0[WF3].</description>
              <bitOffset>16</bitOffset>
              <bitWidth>8</bitWidth>
              <access>read-write</access>
            </field>
            <field>
              <name>WF11</name>
              <description>Controls segments or phases connected to LCD_P11 as described above for WF3TO0[WF3].</description>
              <bitOffset>24</bitOffset>
              <bitWidth>8</bitWidth>
              <access>read-write</access>
            </field>
          </fields>
        </register>
        <register>
          <name>WF8</name>
          <description>LCD Waveform Register 8.</description>
          <alternateGroup>LCD</alternateGroup>
          <addressOffset>0x28</addressOffset>
          <size>8</size>
          <access>read-write</access>
          <resetValue>0</resetValue>
          <resetMask>0</resetMask>
          <fields>
            <field>
              <name>BPALCD8</name>
              <description>no description available</description>
              <bitOffset>0</bitOffset>
              <bitWidth>1</bitWidth>
              <access>read-write</access>
              <enumeratedValues>
                <enumeratedValue>
                  <name>0</name>
                  <description>LCD segment off or LCD backplane inactive for phase A</description>
                  <value>#0</value>
                </enumeratedValue>
                <enumeratedValue>
                  <name>1</name>
                  <description>LCD segment on or LCD backplane active for phase A</description>
                  <value>#1</value>
                </enumeratedValue>
              </enumeratedValues>
            </field>
            <field>
              <name>BPBLCD8</name>
              <description>no description available</description>
              <bitOffset>1</bitOffset>
              <bitWidth>1</bitWidth>
              <access>read-write</access>
              <enumeratedValues>
                <enumeratedValue>
                  <name>0</name>
                  <description>LCD segment off or LCD backplane inactive for phase B</description>
                  <value>#0</value>
                </enumeratedValue>
                <enumeratedValue>
                  <name>1</name>
                  <description>LCD segment on or LCD backplane active for phase B</description>
                  <value>#1</value>
                </enumeratedValue>
              </enumeratedValues>
            </field>
            <field>
              <name>BPCLCD8</name>
              <description>no description available</description>
              <bitOffset>2</bitOffset>
              <bitWidth>1</bitWidth>
              <access>read-write</access>
              <enumeratedValues>
                <enumeratedValue>
                  <name>0</name>
                  <description>LCD segment off or LCD backplane inactive for phase C</description>
                  <value>#0</value>
                </enumeratedValue>
                <enumeratedValue>
                  <name>1</name>
                  <description>LCD segment on or LCD backplane active for phase C</description>
                  <value>#1</value>
                </enumeratedValue>
              </enumeratedValues>
            </field>
            <field>
              <name>BPDLCD8</name>
              <description>no description available</description>
              <bitOffset>3</bitOffset>
              <bitWidth>1</bitWidth>
              <access>read-write</access>
              <enumeratedValues>
                <enumeratedValue>
                  <name>0</name>
                  <description>LCD segment off or LCD backplane inactive for phase D</description>
                  <value>#0</value>
                </enumeratedValue>
                <enumeratedValue>
                  <name>1</name>
                  <description>LCD segment on or LCD backplane active for phase D</description>
                  <value>#1</value>
                </enumeratedValue>
              </enumeratedValues>
            </field>
            <field>
              <name>BPELCD8</name>
              <description>no description available</description>
              <bitOffset>4</bitOffset>
              <bitWidth>1</bitWidth>
              <access>read-write</access>
              <enumeratedValues>
                <enumeratedValue>
                  <name>0</name>
                  <description>LCD segment off or LCD backplane inactive for phase E</description>
                  <value>#0</value>
                </enumeratedValue>
                <enumeratedValue>
                  <name>1</name>
                  <description>LCD segment on or LCD backplane active for phase E</description>
                  <value>#1</value>
                </enumeratedValue>
              </enumeratedValues>
            </field>
            <field>
              <name>BPFLCD8</name>
              <description>no description available</description>
              <bitOffset>5</bitOffset>
              <bitWidth>1</bitWidth>
              <access>read-write</access>
              <enumeratedValues>
                <enumeratedValue>
                  <name>0</name>
                  <description>LCD segment off or LCD backplane inactive for phase F</description>
                  <value>#0</value>
                </enumeratedValue>
                <enumeratedValue>
                  <name>1</name>
                  <description>LCD segment on or LCD backplane active for phase F</description>
                  <value>#1</value>
                </enumeratedValue>
              </enumeratedValues>
            </field>
            <field>
              <name>BPGLCD8</name>
              <description>no description available</description>
              <bitOffset>6</bitOffset>
              <bitWidth>1</bitWidth>
              <access>read-write</access>
              <enumeratedValues>
                <enumeratedValue>
                  <name>0</name>
                  <description>LCD segment off or LCD backplane inactive for phase G</description>
                  <value>#0</value>
                </enumeratedValue>
                <enumeratedValue>
                  <name>1</name>
                  <description>LCD segment on or LCD backplane active for phase G</description>
                  <value>#1</value>
                </enumeratedValue>
              </enumeratedValues>
            </field>
            <field>
              <name>BPHLCD8</name>
              <description>no description available</description>
              <bitOffset>7</bitOffset>
              <bitWidth>1</bitWidth>
              <access>read-write</access>
              <enumeratedValues>
                <enumeratedValue>
                  <name>0</name>
                  <description>LCD segment off or LCD backplane inactive for phase H</description>
                  <value>#0</value>
                </enumeratedValue>
                <enumeratedValue>
                  <name>1</name>
                  <description>LCD segment on or LCD backplane active for phase H</description>
                  <value>#1</value>
                </enumeratedValue>
              </enumeratedValues>
            </field>
          </fields>
        </register>
        <register>
          <name>WF9</name>
          <description>LCD Waveform Register 9.</description>
          <addressOffset>0x29</addressOffset>
          <size>8</size>
          <access>read-write</access>
          <resetValue>0</resetValue>
          <resetMask>0</resetMask>
          <fields>
            <field>
              <name>BPALCD9</name>
              <description>no description available</description>
              <bitOffset>0</bitOffset>
              <bitWidth>1</bitWidth>
              <access>read-write</access>
              <enumeratedValues>
                <enumeratedValue>
                  <name>0</name>
                  <description>LCD segment off or LCD backplane inactive for phase A</description>
                  <value>#0</value>
                </enumeratedValue>
                <enumeratedValue>
                  <name>1</name>
                  <description>LCD segment on or LCD backplane active for phase A</description>
                  <value>#1</value>
                </enumeratedValue>
              </enumeratedValues>
            </field>
            <field>
              <name>BPBLCD9</name>
              <description>no description available</description>
              <bitOffset>1</bitOffset>
              <bitWidth>1</bitWidth>
              <access>read-write</access>
              <enumeratedValues>
                <enumeratedValue>
                  <name>0</name>
                  <description>LCD segment off or LCD backplane inactive for phase B</description>
                  <value>#0</value>
                </enumeratedValue>
                <enumeratedValue>
                  <name>1</name>
                  <description>LCD segment on or LCD backplane active for phase B</description>
                  <value>#1</value>
                </enumeratedValue>
              </enumeratedValues>
            </field>
            <field>
              <name>BPCLCD9</name>
              <description>no description available</description>
              <bitOffset>2</bitOffset>
              <bitWidth>1</bitWidth>
              <access>read-write</access>
              <enumeratedValues>
                <enumeratedValue>
                  <name>0</name>
                  <description>LCD segment off or LCD backplane inactive for phase C</description>
                  <value>#0</value>
                </enumeratedValue>
                <enumeratedValue>
                  <name>1</name>
                  <description>LCD segment on or LCD backplane active for phase C</description>
                  <value>#1</value>
                </enumeratedValue>
              </enumeratedValues>
            </field>
            <field>
              <name>BPDLCD9</name>
              <description>no description available</description>
              <bitOffset>3</bitOffset>
              <bitWidth>1</bitWidth>
              <access>read-write</access>
              <enumeratedValues>
                <enumeratedValue>
                  <name>0</name>
                  <description>LCD segment off or LCD backplane inactive for phase D</description>
                  <value>#0</value>
                </enumeratedValue>
                <enumeratedValue>
                  <name>1</name>
                  <description>LCD segment on or LCD backplane active for phase D</description>
                  <value>#1</value>
                </enumeratedValue>
              </enumeratedValues>
            </field>
            <field>
              <name>BPELCD9</name>
              <description>no description available</description>
              <bitOffset>4</bitOffset>
              <bitWidth>1</bitWidth>
              <access>read-write</access>
              <enumeratedValues>
                <enumeratedValue>
                  <name>0</name>
                  <description>LCD segment off or LCD backplane inactive for phase E</description>
                  <value>#0</value>
                </enumeratedValue>
                <enumeratedValue>
                  <name>1</name>
                  <description>LCD segment on or LCD backplane active for phase E</description>
                  <value>#1</value>
                </enumeratedValue>
              </enumeratedValues>
            </field>
            <field>
              <name>BPFLCD9</name>
              <description>no description available</description>
              <bitOffset>5</bitOffset>
              <bitWidth>1</bitWidth>
              <access>read-write</access>
              <enumeratedValues>
                <enumeratedValue>
                  <name>0</name>
                  <description>LCD segment off or LCD backplane inactive for phase F</description>
                  <value>#0</value>
                </enumeratedValue>
                <enumeratedValue>
                  <name>1</name>
                  <description>LCD segment on or LCD backplane active for phase F</description>
                  <value>#1</value>
                </enumeratedValue>
              </enumeratedValues>
            </field>
            <field>
              <name>BPGLCD9</name>
              <description>no description available</description>
              <bitOffset>6</bitOffset>
              <bitWidth>1</bitWidth>
              <access>read-write</access>
              <enumeratedValues>
                <enumeratedValue>
                  <name>0</name>
                  <description>LCD segment off or LCD backplane inactive for phase G</description>
                  <value>#0</value>
                </enumeratedValue>
                <enumeratedValue>
                  <name>1</name>
                  <description>LCD segment on or LCD backplane active for phase G</description>
                  <value>#1</value>
                </enumeratedValue>
              </enumeratedValues>
            </field>
            <field>
              <name>BPHLCD9</name>
              <description>no description available</description>
              <bitOffset>7</bitOffset>
              <bitWidth>1</bitWidth>
              <access>read-write</access>
              <enumeratedValues>
                <enumeratedValue>
                  <name>0</name>
                  <description>LCD segment off or LCD backplane inactive for phase H</description>
                  <value>#0</value>
                </enumeratedValue>
                <enumeratedValue>
                  <name>1</name>
                  <description>LCD segment on or LCD backplane active for phase H</description>
                  <value>#1</value>
                </enumeratedValue>
              </enumeratedValues>
            </field>
          </fields>
        </register>
        <register>
          <name>WF10</name>
          <description>LCD Waveform Register 10.</description>
          <addressOffset>0x2A</addressOffset>
          <size>8</size>
          <access>read-write</access>
          <resetValue>0</resetValue>
          <resetMask>0</resetMask>
          <fields>
            <field>
              <name>BPALCD10</name>
              <description>no description available</description>
              <bitOffset>0</bitOffset>
              <bitWidth>1</bitWidth>
              <access>read-write</access>
              <enumeratedValues>
                <enumeratedValue>
                  <name>0</name>
                  <description>LCD segment off or LCD backplane inactive for phase A</description>
                  <value>#0</value>
                </enumeratedValue>
                <enumeratedValue>
                  <name>1</name>
                  <description>LCD segment on or LCD backplane active for phase A</description>
                  <value>#1</value>
                </enumeratedValue>
              </enumeratedValues>
            </field>
            <field>
              <name>BPBLCD10</name>
              <description>no description available</description>
              <bitOffset>1</bitOffset>
              <bitWidth>1</bitWidth>
              <access>read-write</access>
              <enumeratedValues>
                <enumeratedValue>
                  <name>0</name>
                  <description>LCD segment off or LCD backplane inactive for phase B</description>
                  <value>#0</value>
                </enumeratedValue>
                <enumeratedValue>
                  <name>1</name>
                  <description>LCD segment on or LCD backplane active for phase B</description>
                  <value>#1</value>
                </enumeratedValue>
              </enumeratedValues>
            </field>
            <field>
              <name>BPCLCD10</name>
              <description>no description available</description>
              <bitOffset>2</bitOffset>
              <bitWidth>1</bitWidth>
              <access>read-write</access>
              <enumeratedValues>
                <enumeratedValue>
                  <name>0</name>
                  <description>LCD segment off or LCD backplane inactive for phase C</description>
                  <value>#0</value>
                </enumeratedValue>
                <enumeratedValue>
                  <name>1</name>
                  <description>LCD segment on or LCD backplane active for phase C</description>
                  <value>#1</value>
                </enumeratedValue>
              </enumeratedValues>
            </field>
            <field>
              <name>BPDLCD10</name>
              <description>no description available</description>
              <bitOffset>3</bitOffset>
              <bitWidth>1</bitWidth>
              <access>read-write</access>
              <enumeratedValues>
                <enumeratedValue>
                  <name>0</name>
                  <description>LCD segment off or LCD backplane inactive for phase D</description>
                  <value>#0</value>
                </enumeratedValue>
                <enumeratedValue>
                  <name>1</name>
                  <description>LCD segment on or LCD backplane active for phase D</description>
                  <value>#1</value>
                </enumeratedValue>
              </enumeratedValues>
            </field>
            <field>
              <name>BPELCD10</name>
              <description>no description available</description>
              <bitOffset>4</bitOffset>
              <bitWidth>1</bitWidth>
              <access>read-write</access>
              <enumeratedValues>
                <enumeratedValue>
                  <name>0</name>
                  <description>LCD segment off or LCD backplane inactive for phase E</description>
                  <value>#0</value>
                </enumeratedValue>
                <enumeratedValue>
                  <name>1</name>
                  <description>LCD segment on or LCD backplane active for phase E</description>
                  <value>#1</value>
                </enumeratedValue>
              </enumeratedValues>
            </field>
            <field>
              <name>BPFLCD10</name>
              <description>no description available</description>
              <bitOffset>5</bitOffset>
              <bitWidth>1</bitWidth>
              <access>read-write</access>
              <enumeratedValues>
                <enumeratedValue>
                  <name>0</name>
                  <description>LCD segment off or LCD backplane inactive for phase F</description>
                  <value>#0</value>
                </enumeratedValue>
                <enumeratedValue>
                  <name>1</name>
                  <description>LCD segment on or LCD backplane active for phase F</description>
                  <value>#1</value>
                </enumeratedValue>
              </enumeratedValues>
            </field>
            <field>
              <name>BPGLCD10</name>
              <description>no description available</description>
              <bitOffset>6</bitOffset>
              <bitWidth>1</bitWidth>
              <access>read-write</access>
              <enumeratedValues>
                <enumeratedValue>
                  <name>0</name>
                  <description>LCD segment off or LCD backplane inactive for phase G</description>
                  <value>#0</value>
                </enumeratedValue>
                <enumeratedValue>
                  <name>1</name>
                  <description>LCD segment on or LCD backplane active for phase G</description>
                  <value>#1</value>
                </enumeratedValue>
              </enumeratedValues>
            </field>
            <field>
              <name>BPHLCD10</name>
              <description>no description available</description>
              <bitOffset>7</bitOffset>
              <bitWidth>1</bitWidth>
              <access>read-write</access>
              <enumeratedValues>
                <enumeratedValue>
                  <name>0</name>
                  <description>LCD segment off or LCD backplane inactive for phase H</description>
                  <value>#0</value>
                </enumeratedValue>
                <enumeratedValue>
                  <name>1</name>
                  <description>LCD segment on or LCD backplane active for phase H</description>
                  <value>#1</value>
                </enumeratedValue>
              </enumeratedValues>
            </field>
          </fields>
        </register>
        <register>
          <name>WF11</name>
          <description>LCD Waveform Register 11.</description>
          <addressOffset>0x2B</addressOffset>
          <size>8</size>
          <access>read-write</access>
          <resetValue>0</resetValue>
          <resetMask>0</resetMask>
          <fields>
            <field>
              <name>BPALCD11</name>
              <description>no description available</description>
              <bitOffset>0</bitOffset>
              <bitWidth>1</bitWidth>
              <access>read-write</access>
              <enumeratedValues>
                <enumeratedValue>
                  <name>0</name>
                  <description>LCD segment off or LCD backplane inactive for phase A</description>
                  <value>#0</value>
                </enumeratedValue>
                <enumeratedValue>
                  <name>1</name>
                  <description>LCD segment on or LCD backplane active for phase A</description>
                  <value>#1</value>
                </enumeratedValue>
              </enumeratedValues>
            </field>
            <field>
              <name>BPBLCD11</name>
              <description>no description available</description>
              <bitOffset>1</bitOffset>
              <bitWidth>1</bitWidth>
              <access>read-write</access>
              <enumeratedValues>
                <enumeratedValue>
                  <name>0</name>
                  <description>LCD segment off or LCD backplane inactive for phase B</description>
                  <value>#0</value>
                </enumeratedValue>
                <enumeratedValue>
                  <name>1</name>
                  <description>LCD segment on or LCD backplane active for phase B</description>
                  <value>#1</value>
                </enumeratedValue>
              </enumeratedValues>
            </field>
            <field>
              <name>BPCLCD11</name>
              <description>no description available</description>
              <bitOffset>2</bitOffset>
              <bitWidth>1</bitWidth>
              <access>read-write</access>
              <enumeratedValues>
                <enumeratedValue>
                  <name>0</name>
                  <description>LCD segment off or LCD backplane inactive for phase C</description>
                  <value>#0</value>
                </enumeratedValue>
                <enumeratedValue>
                  <name>1</name>
                  <description>LCD segment on or LCD backplane active for phase C</description>
                  <value>#1</value>
                </enumeratedValue>
              </enumeratedValues>
            </field>
            <field>
              <name>BPDLCD11</name>
              <description>no description available</description>
              <bitOffset>3</bitOffset>
              <bitWidth>1</bitWidth>
              <access>read-write</access>
              <enumeratedValues>
                <enumeratedValue>
                  <name>0</name>
                  <description>LCD segment off or LCD backplane inactive for phase D</description>
                  <value>#0</value>
                </enumeratedValue>
                <enumeratedValue>
                  <name>1</name>
                  <description>LCD segment on or LCD backplane active for phase D</description>
                  <value>#1</value>
                </enumeratedValue>
              </enumeratedValues>
            </field>
            <field>
              <name>BPELCD11</name>
              <description>no description available</description>
              <bitOffset>4</bitOffset>
              <bitWidth>1</bitWidth>
              <access>read-write</access>
              <enumeratedValues>
                <enumeratedValue>
                  <name>0</name>
                  <description>LCD segment off or LCD backplane inactive for phase E</description>
                  <value>#0</value>
                </enumeratedValue>
                <enumeratedValue>
                  <name>1</name>
                  <description>LCD segment on or LCD backplane active for phase E</description>
                  <value>#1</value>
                </enumeratedValue>
              </enumeratedValues>
            </field>
            <field>
              <name>BPFLCD11</name>
              <description>no description available</description>
              <bitOffset>5</bitOffset>
              <bitWidth>1</bitWidth>
              <access>read-write</access>
              <enumeratedValues>
                <enumeratedValue>
                  <name>0</name>
                  <description>LCD segment off or LCD backplane inactive for phase F</description>
                  <value>#0</value>
                </enumeratedValue>
                <enumeratedValue>
                  <name>1</name>
                  <description>LCD segment on or LCD backplane active for phase F</description>
                  <value>#1</value>
                </enumeratedValue>
              </enumeratedValues>
            </field>
            <field>
              <name>BPGLCD11</name>
              <description>no description available</description>
              <bitOffset>6</bitOffset>
              <bitWidth>1</bitWidth>
              <access>read-write</access>
              <enumeratedValues>
                <enumeratedValue>
                  <name>0</name>
                  <description>LCD segment off or LCD backplane inactive for phase G</description>
                  <value>#0</value>
                </enumeratedValue>
                <enumeratedValue>
                  <name>1</name>
                  <description>LCD segment on or LCD backplane active for phase G</description>
                  <value>#1</value>
                </enumeratedValue>
              </enumeratedValues>
            </field>
            <field>
              <name>BPHLCD11</name>
              <description>no description available</description>
              <bitOffset>7</bitOffset>
              <bitWidth>1</bitWidth>
              <access>read-write</access>
              <enumeratedValues>
                <enumeratedValue>
                  <name>0</name>
                  <description>LCD segment off or LCD backplane inactive for phase H</description>
                  <value>#0</value>
                </enumeratedValue>
                <enumeratedValue>
                  <name>1</name>
                  <description>LCD segment on or LCD backplane active for phase H</description>
                  <value>#1</value>
                </enumeratedValue>
              </enumeratedValues>
            </field>
          </fields>
        </register>
        <register>
          <name>WF15TO12</name>
          <description>LCD Waveform register</description>
          <alternateGroup>LCD</alternateGroup>
          <addressOffset>0x2C</addressOffset>
          <size>32</size>
          <access>read-write</access>
          <resetValue>0</resetValue>
          <resetMask>0xFFFFFFFF</resetMask>
          <fields>
            <field>
              <name>WF12</name>
              <description>Controls segments or phases connected to LCD_P12 as described above for WF3TO0[WF3].</description>
              <bitOffset>0</bitOffset>
              <bitWidth>8</bitWidth>
              <access>read-write</access>
            </field>
            <field>
              <name>WF13</name>
              <description>Controls segments or phases connected to LCD_P13 as described above for WF3TO0[WF3].</description>
              <bitOffset>8</bitOffset>
              <bitWidth>8</bitWidth>
              <access>read-write</access>
            </field>
            <field>
              <name>WF14</name>
              <description>Controls segments or phases connected to LCD_P14 as described above for WF3TO0[WF3].</description>
              <bitOffset>16</bitOffset>
              <bitWidth>8</bitWidth>
              <access>read-write</access>
            </field>
            <field>
              <name>WF15</name>
              <description>Controls segments or phases connected to LCD_P15 as described above for WF3TO0[WF3].</description>
              <bitOffset>24</bitOffset>
              <bitWidth>8</bitWidth>
              <access>read-write</access>
            </field>
          </fields>
        </register>
        <register>
          <name>WF12</name>
          <description>LCD Waveform Register 12.</description>
          <alternateGroup>LCD</alternateGroup>
          <addressOffset>0x2C</addressOffset>
          <size>8</size>
          <access>read-write</access>
          <resetValue>0</resetValue>
          <resetMask>0</resetMask>
          <fields>
            <field>
              <name>BPALCD12</name>
              <description>no description available</description>
              <bitOffset>0</bitOffset>
              <bitWidth>1</bitWidth>
              <access>read-write</access>
              <enumeratedValues>
                <enumeratedValue>
                  <name>0</name>
                  <description>LCD segment off or LCD backplane inactive for phase A</description>
                  <value>#0</value>
                </enumeratedValue>
                <enumeratedValue>
                  <name>1</name>
                  <description>LCD segment on or LCD backplane active for phase A</description>
                  <value>#1</value>
                </enumeratedValue>
              </enumeratedValues>
            </field>
            <field>
              <name>BPBLCD12</name>
              <description>no description available</description>
              <bitOffset>1</bitOffset>
              <bitWidth>1</bitWidth>
              <access>read-write</access>
              <enumeratedValues>
                <enumeratedValue>
                  <name>0</name>
                  <description>LCD segment off or LCD backplane inactive for phase B</description>
                  <value>#0</value>
                </enumeratedValue>
                <enumeratedValue>
                  <name>1</name>
                  <description>LCD segment on or LCD backplane active for phase B</description>
                  <value>#1</value>
                </enumeratedValue>
              </enumeratedValues>
            </field>
            <field>
              <name>BPCLCD12</name>
              <description>no description available</description>
              <bitOffset>2</bitOffset>
              <bitWidth>1</bitWidth>
              <access>read-write</access>
              <enumeratedValues>
                <enumeratedValue>
                  <name>0</name>
                  <description>LCD segment off or LCD backplane inactive for phase C</description>
                  <value>#0</value>
                </enumeratedValue>
                <enumeratedValue>
                  <name>1</name>
                  <description>LCD segment on or LCD backplane active for phase C</description>
                  <value>#1</value>
                </enumeratedValue>
              </enumeratedValues>
            </field>
            <field>
              <name>BPDLCD12</name>
              <description>no description available</description>
              <bitOffset>3</bitOffset>
              <bitWidth>1</bitWidth>
              <access>read-write</access>
              <enumeratedValues>
                <enumeratedValue>
                  <name>0</name>
                  <description>LCD segment off or LCD backplane inactive for phase D</description>
                  <value>#0</value>
                </enumeratedValue>
                <enumeratedValue>
                  <name>1</name>
                  <description>LCD segment on or LCD backplane active for phase D</description>
                  <value>#1</value>
                </enumeratedValue>
              </enumeratedValues>
            </field>
            <field>
              <name>BPELCD12</name>
              <description>no description available</description>
              <bitOffset>4</bitOffset>
              <bitWidth>1</bitWidth>
              <access>read-write</access>
              <enumeratedValues>
                <enumeratedValue>
                  <name>0</name>
                  <description>LCD segment off or LCD backplane inactive for phase E</description>
                  <value>#0</value>
                </enumeratedValue>
                <enumeratedValue>
                  <name>1</name>
                  <description>LCD segment on or LCD backplane active for phase E</description>
                  <value>#1</value>
                </enumeratedValue>
              </enumeratedValues>
            </field>
            <field>
              <name>BPFLCD12</name>
              <description>no description available</description>
              <bitOffset>5</bitOffset>
              <bitWidth>1</bitWidth>
              <access>read-write</access>
              <enumeratedValues>
                <enumeratedValue>
                  <name>0</name>
                  <description>LCD segment off or LCD backplane inactive for phase F</description>
                  <value>#0</value>
                </enumeratedValue>
                <enumeratedValue>
                  <name>1</name>
                  <description>LCD segment on or LCD backplane active for phase F</description>
                  <value>#1</value>
                </enumeratedValue>
              </enumeratedValues>
            </field>
            <field>
              <name>BPGLCD12</name>
              <description>no description available</description>
              <bitOffset>6</bitOffset>
              <bitWidth>1</bitWidth>
              <access>read-write</access>
              <enumeratedValues>
                <enumeratedValue>
                  <name>0</name>
                  <description>LCD segment off or LCD backplane inactive for phase G</description>
                  <value>#0</value>
                </enumeratedValue>
                <enumeratedValue>
                  <name>1</name>
                  <description>LCD segment on or LCD backplane active for phase G</description>
                  <value>#1</value>
                </enumeratedValue>
              </enumeratedValues>
            </field>
            <field>
              <name>BPHLCD12</name>
              <description>no description available</description>
              <bitOffset>7</bitOffset>
              <bitWidth>1</bitWidth>
              <access>read-write</access>
              <enumeratedValues>
                <enumeratedValue>
                  <name>0</name>
                  <description>LCD segment off or LCD backplane inactive for phase H</description>
                  <value>#0</value>
                </enumeratedValue>
                <enumeratedValue>
                  <name>1</name>
                  <description>LCD segment on or LCD backplane active for phase H</description>
                  <value>#1</value>
                </enumeratedValue>
              </enumeratedValues>
            </field>
          </fields>
        </register>
        <register>
          <name>WF13</name>
          <description>LCD Waveform Register 13.</description>
          <addressOffset>0x2D</addressOffset>
          <size>8</size>
          <access>read-write</access>
          <resetValue>0</resetValue>
          <resetMask>0</resetMask>
          <fields>
            <field>
              <name>BPALCD13</name>
              <description>no description available</description>
              <bitOffset>0</bitOffset>
              <bitWidth>1</bitWidth>
              <access>read-write</access>
              <enumeratedValues>
                <enumeratedValue>
                  <name>0</name>
                  <description>LCD segment off or LCD backplane inactive for phase A</description>
                  <value>#0</value>
                </enumeratedValue>
                <enumeratedValue>
                  <name>1</name>
                  <description>LCD segment on or LCD backplane active for phase A</description>
                  <value>#1</value>
                </enumeratedValue>
              </enumeratedValues>
            </field>
            <field>
              <name>BPBLCD13</name>
              <description>no description available</description>
              <bitOffset>1</bitOffset>
              <bitWidth>1</bitWidth>
              <access>read-write</access>
              <enumeratedValues>
                <enumeratedValue>
                  <name>0</name>
                  <description>LCD segment off or LCD backplane inactive for phase B</description>
                  <value>#0</value>
                </enumeratedValue>
                <enumeratedValue>
                  <name>1</name>
                  <description>LCD segment on or LCD backplane active for phase B</description>
                  <value>#1</value>
                </enumeratedValue>
              </enumeratedValues>
            </field>
            <field>
              <name>BPCLCD13</name>
              <description>no description available</description>
              <bitOffset>2</bitOffset>
              <bitWidth>1</bitWidth>
              <access>read-write</access>
              <enumeratedValues>
                <enumeratedValue>
                  <name>0</name>
                  <description>LCD segment off or LCD backplane inactive for phase C</description>
                  <value>#0</value>
                </enumeratedValue>
                <enumeratedValue>
                  <name>1</name>
                  <description>LCD segment on or LCD backplane active for phase C</description>
                  <value>#1</value>
                </enumeratedValue>
              </enumeratedValues>
            </field>
            <field>
              <name>BPDLCD13</name>
              <description>no description available</description>
              <bitOffset>3</bitOffset>
              <bitWidth>1</bitWidth>
              <access>read-write</access>
              <enumeratedValues>
                <enumeratedValue>
                  <name>0</name>
                  <description>LCD segment off or LCD backplane inactive for phase D</description>
                  <value>#0</value>
                </enumeratedValue>
                <enumeratedValue>
                  <name>1</name>
                  <description>LCD segment on or LCD backplane active for phase D</description>
                  <value>#1</value>
                </enumeratedValue>
              </enumeratedValues>
            </field>
            <field>
              <name>BPELCD13</name>
              <description>no description available</description>
              <bitOffset>4</bitOffset>
              <bitWidth>1</bitWidth>
              <access>read-write</access>
              <enumeratedValues>
                <enumeratedValue>
                  <name>0</name>
                  <description>LCD segment off or LCD backplane inactive for phase E</description>
                  <value>#0</value>
                </enumeratedValue>
                <enumeratedValue>
                  <name>1</name>
                  <description>LCD segment on or LCD backplane active for phase E</description>
                  <value>#1</value>
                </enumeratedValue>
              </enumeratedValues>
            </field>
            <field>
              <name>BPFLCD13</name>
              <description>no description available</description>
              <bitOffset>5</bitOffset>
              <bitWidth>1</bitWidth>
              <access>read-write</access>
              <enumeratedValues>
                <enumeratedValue>
                  <name>0</name>
                  <description>LCD segment off or LCD backplane inactive for phase F</description>
                  <value>#0</value>
                </enumeratedValue>
                <enumeratedValue>
                  <name>1</name>
                  <description>LCD segment on or LCD backplane active for phase F</description>
                  <value>#1</value>
                </enumeratedValue>
              </enumeratedValues>
            </field>
            <field>
              <name>BPGLCD13</name>
              <description>no description available</description>
              <bitOffset>6</bitOffset>
              <bitWidth>1</bitWidth>
              <access>read-write</access>
              <enumeratedValues>
                <enumeratedValue>
                  <name>0</name>
                  <description>LCD segment off or LCD backplane inactive for phase G</description>
                  <value>#0</value>
                </enumeratedValue>
                <enumeratedValue>
                  <name>1</name>
                  <description>LCD segment on or LCD backplane active for phase G</description>
                  <value>#1</value>
                </enumeratedValue>
              </enumeratedValues>
            </field>
            <field>
              <name>BPHLCD13</name>
              <description>no description available</description>
              <bitOffset>7</bitOffset>
              <bitWidth>1</bitWidth>
              <access>read-write</access>
              <enumeratedValues>
                <enumeratedValue>
                  <name>0</name>
                  <description>LCD segment off or LCD backplane inactive for phase H</description>
                  <value>#0</value>
                </enumeratedValue>
                <enumeratedValue>
                  <name>1</name>
                  <description>LCD segment on or LCD backplane active for phase H</description>
                  <value>#1</value>
                </enumeratedValue>
              </enumeratedValues>
            </field>
          </fields>
        </register>
        <register>
          <name>WF14</name>
          <description>LCD Waveform Register 14.</description>
          <addressOffset>0x2E</addressOffset>
          <size>8</size>
          <access>read-write</access>
          <resetValue>0</resetValue>
          <resetMask>0</resetMask>
          <fields>
            <field>
              <name>BPALCD14</name>
              <description>no description available</description>
              <bitOffset>0</bitOffset>
              <bitWidth>1</bitWidth>
              <access>read-write</access>
              <enumeratedValues>
                <enumeratedValue>
                  <name>0</name>
                  <description>LCD segment off or LCD backplane inactive for phase A</description>
                  <value>#0</value>
                </enumeratedValue>
                <enumeratedValue>
                  <name>1</name>
                  <description>LCD segment on or LCD backplane active for phase A</description>
                  <value>#1</value>
                </enumeratedValue>
              </enumeratedValues>
            </field>
            <field>
              <name>BPBLCD14</name>
              <description>no description available</description>
              <bitOffset>1</bitOffset>
              <bitWidth>1</bitWidth>
              <access>read-write</access>
              <enumeratedValues>
                <enumeratedValue>
                  <name>0</name>
                  <description>LCD segment off or LCD backplane inactive for phase B</description>
                  <value>#0</value>
                </enumeratedValue>
                <enumeratedValue>
                  <name>1</name>
                  <description>LCD segment on or LCD backplane active for phase B</description>
                  <value>#1</value>
                </enumeratedValue>
              </enumeratedValues>
            </field>
            <field>
              <name>BPCLCD14</name>
              <description>no description available</description>
              <bitOffset>2</bitOffset>
              <bitWidth>1</bitWidth>
              <access>read-write</access>
              <enumeratedValues>
                <enumeratedValue>
                  <name>0</name>
                  <description>LCD segment off or LCD backplane inactive for phase C</description>
                  <value>#0</value>
                </enumeratedValue>
                <enumeratedValue>
                  <name>1</name>
                  <description>LCD segment on or LCD backplane active for phase C</description>
                  <value>#1</value>
                </enumeratedValue>
              </enumeratedValues>
            </field>
            <field>
              <name>BPDLCD14</name>
              <description>no description available</description>
              <bitOffset>3</bitOffset>
              <bitWidth>1</bitWidth>
              <access>read-write</access>
              <enumeratedValues>
                <enumeratedValue>
                  <name>0</name>
                  <description>LCD segment off or LCD backplane inactive for phase D</description>
                  <value>#0</value>
                </enumeratedValue>
                <enumeratedValue>
                  <name>1</name>
                  <description>LCD segment on or LCD backplane active for phase D</description>
                  <value>#1</value>
                </enumeratedValue>
              </enumeratedValues>
            </field>
            <field>
              <name>BPELCD14</name>
              <description>no description available</description>
              <bitOffset>4</bitOffset>
              <bitWidth>1</bitWidth>
              <access>read-write</access>
              <enumeratedValues>
                <enumeratedValue>
                  <name>0</name>
                  <description>LCD segment off or LCD backplane inactive for phase E</description>
                  <value>#0</value>
                </enumeratedValue>
                <enumeratedValue>
                  <name>1</name>
                  <description>LCD segment on or LCD backplane active for phase E</description>
                  <value>#1</value>
                </enumeratedValue>
              </enumeratedValues>
            </field>
            <field>
              <name>BPFLCD14</name>
              <description>no description available</description>
              <bitOffset>5</bitOffset>
              <bitWidth>1</bitWidth>
              <access>read-write</access>
              <enumeratedValues>
                <enumeratedValue>
                  <name>0</name>
                  <description>LCD segment off or LCD backplane inactive for phase F</description>
                  <value>#0</value>
                </enumeratedValue>
                <enumeratedValue>
                  <name>1</name>
                  <description>LCD segment on or LCD backplane active for phase F</description>
                  <value>#1</value>
                </enumeratedValue>
              </enumeratedValues>
            </field>
            <field>
              <name>BPGLCD14</name>
              <description>no description available</description>
              <bitOffset>6</bitOffset>
              <bitWidth>1</bitWidth>
              <access>read-write</access>
              <enumeratedValues>
                <enumeratedValue>
                  <name>0</name>
                  <description>LCD segment off or LCD backplane inactive for phase G</description>
                  <value>#0</value>
                </enumeratedValue>
                <enumeratedValue>
                  <name>1</name>
                  <description>LCD segment on or LCD backplane active for phase G</description>
                  <value>#1</value>
                </enumeratedValue>
              </enumeratedValues>
            </field>
            <field>
              <name>BPHLCD14</name>
              <description>no description available</description>
              <bitOffset>7</bitOffset>
              <bitWidth>1</bitWidth>
              <access>read-write</access>
              <enumeratedValues>
                <enumeratedValue>
                  <name>0</name>
                  <description>LCD segment off or LCD backplane inactive for phase H</description>
                  <value>#0</value>
                </enumeratedValue>
                <enumeratedValue>
                  <name>1</name>
                  <description>LCD segment on or LCD backplane active for phase H</description>
                  <value>#1</value>
                </enumeratedValue>
              </enumeratedValues>
            </field>
          </fields>
        </register>
        <register>
          <name>WF15</name>
          <description>LCD Waveform Register 15.</description>
          <addressOffset>0x2F</addressOffset>
          <size>8</size>
          <access>read-write</access>
          <resetValue>0</resetValue>
          <resetMask>0</resetMask>
          <fields>
            <field>
              <name>BPALCD15</name>
              <description>no description available</description>
              <bitOffset>0</bitOffset>
              <bitWidth>1</bitWidth>
              <access>read-write</access>
              <enumeratedValues>
                <enumeratedValue>
                  <name>0</name>
                  <description>LCD segment off or LCD backplane inactive for phase A</description>
                  <value>#0</value>
                </enumeratedValue>
                <enumeratedValue>
                  <name>1</name>
                  <description>LCD segment on or LCD backplane active for phase A</description>
                  <value>#1</value>
                </enumeratedValue>
              </enumeratedValues>
            </field>
            <field>
              <name>BPBLCD15</name>
              <description>no description available</description>
              <bitOffset>1</bitOffset>
              <bitWidth>1</bitWidth>
              <access>read-write</access>
              <enumeratedValues>
                <enumeratedValue>
                  <name>0</name>
                  <description>LCD segment off or LCD backplane inactive for phase B</description>
                  <value>#0</value>
                </enumeratedValue>
                <enumeratedValue>
                  <name>1</name>
                  <description>LCD segment on or LCD backplane active for phase B</description>
                  <value>#1</value>
                </enumeratedValue>
              </enumeratedValues>
            </field>
            <field>
              <name>BPCLCD15</name>
              <description>no description available</description>
              <bitOffset>2</bitOffset>
              <bitWidth>1</bitWidth>
              <access>read-write</access>
              <enumeratedValues>
                <enumeratedValue>
                  <name>0</name>
                  <description>LCD segment off or LCD backplane inactive for phase C</description>
                  <value>#0</value>
                </enumeratedValue>
                <enumeratedValue>
                  <name>1</name>
                  <description>LCD segment on or LCD backplane active for phase C</description>
                  <value>#1</value>
                </enumeratedValue>
              </enumeratedValues>
            </field>
            <field>
              <name>BPDLCD15</name>
              <description>no description available</description>
              <bitOffset>3</bitOffset>
              <bitWidth>1</bitWidth>
              <access>read-write</access>
              <enumeratedValues>
                <enumeratedValue>
                  <name>0</name>
                  <description>LCD segment off or LCD backplane inactive for phase D</description>
                  <value>#0</value>
                </enumeratedValue>
                <enumeratedValue>
                  <name>1</name>
                  <description>LCD segment on or LCD backplane active for phase D</description>
                  <value>#1</value>
                </enumeratedValue>
              </enumeratedValues>
            </field>
            <field>
              <name>BPELCD15</name>
              <description>no description available</description>
              <bitOffset>4</bitOffset>
              <bitWidth>1</bitWidth>
              <access>read-write</access>
              <enumeratedValues>
                <enumeratedValue>
                  <name>0</name>
                  <description>LCD segment off or LCD backplane inactive for phase E</description>
                  <value>#0</value>
                </enumeratedValue>
                <enumeratedValue>
                  <name>1</name>
                  <description>LCD segment on or LCD backplane active for phase E</description>
                  <value>#1</value>
                </enumeratedValue>
              </enumeratedValues>
            </field>
            <field>
              <name>BPFLCD15</name>
              <description>no description available</description>
              <bitOffset>5</bitOffset>
              <bitWidth>1</bitWidth>
              <access>read-write</access>
              <enumeratedValues>
                <enumeratedValue>
                  <name>0</name>
                  <description>LCD segment off or LCD backplane inactive for phase F</description>
                  <value>#0</value>
                </enumeratedValue>
                <enumeratedValue>
                  <name>1</name>
                  <description>LCD segment on or LCD backplane active for phase F</description>
                  <value>#1</value>
                </enumeratedValue>
              </enumeratedValues>
            </field>
            <field>
              <name>BPGLCD15</name>
              <description>no description available</description>
              <bitOffset>6</bitOffset>
              <bitWidth>1</bitWidth>
              <access>read-write</access>
              <enumeratedValues>
                <enumeratedValue>
                  <name>0</name>
                  <description>LCD segment off or LCD backplane inactive for phase G</description>
                  <value>#0</value>
                </enumeratedValue>
                <enumeratedValue>
                  <name>1</name>
                  <description>LCD segment on or LCD backplane active for phase G</description>
                  <value>#1</value>
                </enumeratedValue>
              </enumeratedValues>
            </field>
            <field>
              <name>BPHLCD15</name>
              <description>no description available</description>
              <bitOffset>7</bitOffset>
              <bitWidth>1</bitWidth>
              <access>read-write</access>
              <enumeratedValues>
                <enumeratedValue>
                  <name>0</name>
                  <description>LCD segment off or LCD backplane inactive for phase H</description>
                  <value>#0</value>
                </enumeratedValue>
                <enumeratedValue>
                  <name>1</name>
                  <description>LCD segment on or LCD backplane active for phase H</description>
                  <value>#1</value>
                </enumeratedValue>
              </enumeratedValues>
            </field>
          </fields>
        </register>
        <register>
          <name>WF19TO16</name>
          <description>LCD Waveform register</description>
          <alternateGroup>LCD</alternateGroup>
          <addressOffset>0x30</addressOffset>
          <size>32</size>
          <access>read-write</access>
          <resetValue>0</resetValue>
          <resetMask>0xFFFFFFFF</resetMask>
          <fields>
            <field>
              <name>WF16</name>
              <description>Controls segments or phases connected to LCD_P16 as described above for WF3TO0[WF3].</description>
              <bitOffset>0</bitOffset>
              <bitWidth>8</bitWidth>
              <access>read-write</access>
            </field>
            <field>
              <name>WF17</name>
              <description>Controls segments or phases connected to LCD_P17 as described above for WF3TO0[WF3].</description>
              <bitOffset>8</bitOffset>
              <bitWidth>8</bitWidth>
              <access>read-write</access>
            </field>
            <field>
              <name>WF18</name>
              <description>Controls segments or phases connected to LCD_P18 as described above for WF3TO0[WF3].</description>
              <bitOffset>16</bitOffset>
              <bitWidth>8</bitWidth>
              <access>read-write</access>
            </field>
            <field>
              <name>WF19</name>
              <description>Controls segments or phases connected to LCD_P19 as described above for WF3TO0[WF3].</description>
              <bitOffset>24</bitOffset>
              <bitWidth>8</bitWidth>
              <access>read-write</access>
            </field>
          </fields>
        </register>
        <register>
          <name>WF16</name>
          <description>LCD Waveform Register 16.</description>
          <alternateGroup>LCD</alternateGroup>
          <addressOffset>0x30</addressOffset>
          <size>8</size>
          <access>read-write</access>
          <resetValue>0</resetValue>
          <resetMask>0</resetMask>
          <fields>
            <field>
              <name>BPALCD16</name>
              <description>no description available</description>
              <bitOffset>0</bitOffset>
              <bitWidth>1</bitWidth>
              <access>read-write</access>
              <enumeratedValues>
                <enumeratedValue>
                  <name>0</name>
                  <description>LCD segment off or LCD backplane inactive for phase A</description>
                  <value>#0</value>
                </enumeratedValue>
                <enumeratedValue>
                  <name>1</name>
                  <description>LCD segment on or LCD backplane active for phase A</description>
                  <value>#1</value>
                </enumeratedValue>
              </enumeratedValues>
            </field>
            <field>
              <name>BPBLCD16</name>
              <description>no description available</description>
              <bitOffset>1</bitOffset>
              <bitWidth>1</bitWidth>
              <access>read-write</access>
              <enumeratedValues>
                <enumeratedValue>
                  <name>0</name>
                  <description>LCD segment off or LCD backplane inactive for phase B</description>
                  <value>#0</value>
                </enumeratedValue>
                <enumeratedValue>
                  <name>1</name>
                  <description>LCD segment on or LCD backplane active for phase B</description>
                  <value>#1</value>
                </enumeratedValue>
              </enumeratedValues>
            </field>
            <field>
              <name>BPCLCD16</name>
              <description>no description available</description>
              <bitOffset>2</bitOffset>
              <bitWidth>1</bitWidth>
              <access>read-write</access>
              <enumeratedValues>
                <enumeratedValue>
                  <name>0</name>
                  <description>LCD segment off or LCD backplane inactive for phase C</description>
                  <value>#0</value>
                </enumeratedValue>
                <enumeratedValue>
                  <name>1</name>
                  <description>LCD segment on or LCD backplane active for phase C</description>
                  <value>#1</value>
                </enumeratedValue>
              </enumeratedValues>
            </field>
            <field>
              <name>BPDLCD16</name>
              <description>no description available</description>
              <bitOffset>3</bitOffset>
              <bitWidth>1</bitWidth>
              <access>read-write</access>
              <enumeratedValues>
                <enumeratedValue>
                  <name>0</name>
                  <description>LCD segment off or LCD backplane inactive for phase D</description>
                  <value>#0</value>
                </enumeratedValue>
                <enumeratedValue>
                  <name>1</name>
                  <description>LCD segment on or LCD backplane active for phase D</description>
                  <value>#1</value>
                </enumeratedValue>
              </enumeratedValues>
            </field>
            <field>
              <name>BPELCD16</name>
              <description>no description available</description>
              <bitOffset>4</bitOffset>
              <bitWidth>1</bitWidth>
              <access>read-write</access>
              <enumeratedValues>
                <enumeratedValue>
                  <name>0</name>
                  <description>LCD segment off or LCD backplane inactive for phase E</description>
                  <value>#0</value>
                </enumeratedValue>
                <enumeratedValue>
                  <name>1</name>
                  <description>LCD segment on or LCD backplane active for phase E</description>
                  <value>#1</value>
                </enumeratedValue>
              </enumeratedValues>
            </field>
            <field>
              <name>BPFLCD16</name>
              <description>no description available</description>
              <bitOffset>5</bitOffset>
              <bitWidth>1</bitWidth>
              <access>read-write</access>
              <enumeratedValues>
                <enumeratedValue>
                  <name>0</name>
                  <description>LCD segment off or LCD backplane inactive for phase F</description>
                  <value>#0</value>
                </enumeratedValue>
                <enumeratedValue>
                  <name>1</name>
                  <description>LCD segment on or LCD backplane active for phase F</description>
                  <value>#1</value>
                </enumeratedValue>
              </enumeratedValues>
            </field>
            <field>
              <name>BPGLCD16</name>
              <description>no description available</description>
              <bitOffset>6</bitOffset>
              <bitWidth>1</bitWidth>
              <access>read-write</access>
              <enumeratedValues>
                <enumeratedValue>
                  <name>0</name>
                  <description>LCD segment off or LCD backplane inactive for phase G</description>
                  <value>#0</value>
                </enumeratedValue>
                <enumeratedValue>
                  <name>1</name>
                  <description>LCD segment on or LCD backplane active for phase G</description>
                  <value>#1</value>
                </enumeratedValue>
              </enumeratedValues>
            </field>
            <field>
              <name>BPHLCD16</name>
              <description>no description available</description>
              <bitOffset>7</bitOffset>
              <bitWidth>1</bitWidth>
              <access>read-write</access>
              <enumeratedValues>
                <enumeratedValue>
                  <name>0</name>
                  <description>LCD segment off or LCD backplane inactive for phase H</description>
                  <value>#0</value>
                </enumeratedValue>
                <enumeratedValue>
                  <name>1</name>
                  <description>LCD segment on or LCD backplane active for phase H</description>
                  <value>#1</value>
                </enumeratedValue>
              </enumeratedValues>
            </field>
          </fields>
        </register>
        <register>
          <name>WF17</name>
          <description>LCD Waveform Register 17.</description>
          <addressOffset>0x31</addressOffset>
          <size>8</size>
          <access>read-write</access>
          <resetValue>0</resetValue>
          <resetMask>0</resetMask>
          <fields>
            <field>
              <name>BPALCD17</name>
              <description>no description available</description>
              <bitOffset>0</bitOffset>
              <bitWidth>1</bitWidth>
              <access>read-write</access>
              <enumeratedValues>
                <enumeratedValue>
                  <name>0</name>
                  <description>LCD segment off or LCD backplane inactive for phase A</description>
                  <value>#0</value>
                </enumeratedValue>
                <enumeratedValue>
                  <name>1</name>
                  <description>LCD segment on or LCD backplane active for phase A</description>
                  <value>#1</value>
                </enumeratedValue>
              </enumeratedValues>
            </field>
            <field>
              <name>BPBLCD17</name>
              <description>no description available</description>
              <bitOffset>1</bitOffset>
              <bitWidth>1</bitWidth>
              <access>read-write</access>
              <enumeratedValues>
                <enumeratedValue>
                  <name>0</name>
                  <description>LCD segment off or LCD backplane inactive for phase B</description>
                  <value>#0</value>
                </enumeratedValue>
                <enumeratedValue>
                  <name>1</name>
                  <description>LCD segment on or LCD backplane active for phase B</description>
                  <value>#1</value>
                </enumeratedValue>
              </enumeratedValues>
            </field>
            <field>
              <name>BPCLCD17</name>
              <description>no description available</description>
              <bitOffset>2</bitOffset>
              <bitWidth>1</bitWidth>
              <access>read-write</access>
              <enumeratedValues>
                <enumeratedValue>
                  <name>0</name>
                  <description>LCD segment off or LCD backplane inactive for phase C</description>
                  <value>#0</value>
                </enumeratedValue>
                <enumeratedValue>
                  <name>1</name>
                  <description>LCD segment on or LCD backplane active for phase C</description>
                  <value>#1</value>
                </enumeratedValue>
              </enumeratedValues>
            </field>
            <field>
              <name>BPDLCD17</name>
              <description>no description available</description>
              <bitOffset>3</bitOffset>
              <bitWidth>1</bitWidth>
              <access>read-write</access>
              <enumeratedValues>
                <enumeratedValue>
                  <name>0</name>
                  <description>LCD segment off or LCD backplane inactive for phase D</description>
                  <value>#0</value>
                </enumeratedValue>
                <enumeratedValue>
                  <name>1</name>
                  <description>LCD segment on or LCD backplane active for phase D</description>
                  <value>#1</value>
                </enumeratedValue>
              </enumeratedValues>
            </field>
            <field>
              <name>BPELCD17</name>
              <description>no description available</description>
              <bitOffset>4</bitOffset>
              <bitWidth>1</bitWidth>
              <access>read-write</access>
              <enumeratedValues>
                <enumeratedValue>
                  <name>0</name>
                  <description>LCD segment off or LCD backplane inactive for phase E</description>
                  <value>#0</value>
                </enumeratedValue>
                <enumeratedValue>
                  <name>1</name>
                  <description>LCD segment on or LCD backplane active for phase E</description>
                  <value>#1</value>
                </enumeratedValue>
              </enumeratedValues>
            </field>
            <field>
              <name>BPFLCD17</name>
              <description>no description available</description>
              <bitOffset>5</bitOffset>
              <bitWidth>1</bitWidth>
              <access>read-write</access>
              <enumeratedValues>
                <enumeratedValue>
                  <name>0</name>
                  <description>LCD segment off or LCD backplane inactive for phase F</description>
                  <value>#0</value>
                </enumeratedValue>
                <enumeratedValue>
                  <name>1</name>
                  <description>LCD segment on or LCD backplane active for phase F</description>
                  <value>#1</value>
                </enumeratedValue>
              </enumeratedValues>
            </field>
            <field>
              <name>BPGLCD17</name>
              <description>no description available</description>
              <bitOffset>6</bitOffset>
              <bitWidth>1</bitWidth>
              <access>read-write</access>
              <enumeratedValues>
                <enumeratedValue>
                  <name>0</name>
                  <description>LCD segment off or LCD backplane inactive for phase G</description>
                  <value>#0</value>
                </enumeratedValue>
                <enumeratedValue>
                  <name>1</name>
                  <description>LCD segment on or LCD backplane active for phase G</description>
                  <value>#1</value>
                </enumeratedValue>
              </enumeratedValues>
            </field>
            <field>
              <name>BPHLCD17</name>
              <description>no description available</description>
              <bitOffset>7</bitOffset>
              <bitWidth>1</bitWidth>
              <access>read-write</access>
              <enumeratedValues>
                <enumeratedValue>
                  <name>0</name>
                  <description>LCD segment off or LCD backplane inactive for phase H</description>
                  <value>#0</value>
                </enumeratedValue>
                <enumeratedValue>
                  <name>1</name>
                  <description>LCD segment on or LCD backplane active for phase H</description>
                  <value>#1</value>
                </enumeratedValue>
              </enumeratedValues>
            </field>
          </fields>
        </register>
        <register>
          <name>WF18</name>
          <description>LCD Waveform Register 18.</description>
          <addressOffset>0x32</addressOffset>
          <size>8</size>
          <access>read-write</access>
          <resetValue>0</resetValue>
          <resetMask>0</resetMask>
          <fields>
            <field>
              <name>BPALCD18</name>
              <description>no description available</description>
              <bitOffset>0</bitOffset>
              <bitWidth>1</bitWidth>
              <access>read-write</access>
              <enumeratedValues>
                <enumeratedValue>
                  <name>0</name>
                  <description>LCD segment off or LCD backplane inactive for phase A</description>
                  <value>#0</value>
                </enumeratedValue>
                <enumeratedValue>
                  <name>1</name>
                  <description>LCD segment on or LCD backplane active for phase A</description>
                  <value>#1</value>
                </enumeratedValue>
              </enumeratedValues>
            </field>
            <field>
              <name>BPBLCD18</name>
              <description>no description available</description>
              <bitOffset>1</bitOffset>
              <bitWidth>1</bitWidth>
              <access>read-write</access>
              <enumeratedValues>
                <enumeratedValue>
                  <name>0</name>
                  <description>LCD segment off or LCD backplane inactive for phase B</description>
                  <value>#0</value>
                </enumeratedValue>
                <enumeratedValue>
                  <name>1</name>
                  <description>LCD segment on or LCD backplane active for phase B</description>
                  <value>#1</value>
                </enumeratedValue>
              </enumeratedValues>
            </field>
            <field>
              <name>BPCLCD18</name>
              <description>no description available</description>
              <bitOffset>2</bitOffset>
              <bitWidth>1</bitWidth>
              <access>read-write</access>
              <enumeratedValues>
                <enumeratedValue>
                  <name>0</name>
                  <description>LCD segment off or LCD backplane inactive for phase C</description>
                  <value>#0</value>
                </enumeratedValue>
                <enumeratedValue>
                  <name>1</name>
                  <description>LCD segment on or LCD backplane active for phase C</description>
                  <value>#1</value>
                </enumeratedValue>
              </enumeratedValues>
            </field>
            <field>
              <name>BPDLCD18</name>
              <description>no description available</description>
              <bitOffset>3</bitOffset>
              <bitWidth>1</bitWidth>
              <access>read-write</access>
              <enumeratedValues>
                <enumeratedValue>
                  <name>0</name>
                  <description>LCD segment off or LCD backplane inactive for phase D</description>
                  <value>#0</value>
                </enumeratedValue>
                <enumeratedValue>
                  <name>1</name>
                  <description>LCD segment on or LCD backplane active for phase D</description>
                  <value>#1</value>
                </enumeratedValue>
              </enumeratedValues>
            </field>
            <field>
              <name>BPELCD18</name>
              <description>no description available</description>
              <bitOffset>4</bitOffset>
              <bitWidth>1</bitWidth>
              <access>read-write</access>
              <enumeratedValues>
                <enumeratedValue>
                  <name>0</name>
                  <description>LCD segment off or LCD backplane inactive for phase E</description>
                  <value>#0</value>
                </enumeratedValue>
                <enumeratedValue>
                  <name>1</name>
                  <description>LCD segment on or LCD backplane active for phase E</description>
                  <value>#1</value>
                </enumeratedValue>
              </enumeratedValues>
            </field>
            <field>
              <name>BPFLCD18</name>
              <description>no description available</description>
              <bitOffset>5</bitOffset>
              <bitWidth>1</bitWidth>
              <access>read-write</access>
              <enumeratedValues>
                <enumeratedValue>
                  <name>0</name>
                  <description>LCD segment off or LCD backplane inactive for phase F</description>
                  <value>#0</value>
                </enumeratedValue>
                <enumeratedValue>
                  <name>1</name>
                  <description>LCD segment on or LCD backplane active for phase F</description>
                  <value>#1</value>
                </enumeratedValue>
              </enumeratedValues>
            </field>
            <field>
              <name>BPGLCD18</name>
              <description>no description available</description>
              <bitOffset>6</bitOffset>
              <bitWidth>1</bitWidth>
              <access>read-write</access>
              <enumeratedValues>
                <enumeratedValue>
                  <name>0</name>
                  <description>LCD segment off or LCD backplane inactive for phase G</description>
                  <value>#0</value>
                </enumeratedValue>
                <enumeratedValue>
                  <name>1</name>
                  <description>LCD segment on or LCD backplane active for phase G</description>
                  <value>#1</value>
                </enumeratedValue>
              </enumeratedValues>
            </field>
            <field>
              <name>BPHLCD18</name>
              <description>no description available</description>
              <bitOffset>7</bitOffset>
              <bitWidth>1</bitWidth>
              <access>read-write</access>
              <enumeratedValues>
                <enumeratedValue>
                  <name>0</name>
                  <description>LCD segment off or LCD backplane inactive for phase H</description>
                  <value>#0</value>
                </enumeratedValue>
                <enumeratedValue>
                  <name>1</name>
                  <description>LCD segment on or LCD backplane active for phase H</description>
                  <value>#1</value>
                </enumeratedValue>
              </enumeratedValues>
            </field>
          </fields>
        </register>
        <register>
          <name>WF19</name>
          <description>LCD Waveform Register 19.</description>
          <addressOffset>0x33</addressOffset>
          <size>8</size>
          <access>read-write</access>
          <resetValue>0</resetValue>
          <resetMask>0</resetMask>
          <fields>
            <field>
              <name>BPALCD19</name>
              <description>no description available</description>
              <bitOffset>0</bitOffset>
              <bitWidth>1</bitWidth>
              <access>read-write</access>
              <enumeratedValues>
                <enumeratedValue>
                  <name>0</name>
                  <description>LCD segment off or LCD backplane inactive for phase A</description>
                  <value>#0</value>
                </enumeratedValue>
                <enumeratedValue>
                  <name>1</name>
                  <description>LCD segment on or LCD backplane active for phase A</description>
                  <value>#1</value>
                </enumeratedValue>
              </enumeratedValues>
            </field>
            <field>
              <name>BPBLCD19</name>
              <description>no description available</description>
              <bitOffset>1</bitOffset>
              <bitWidth>1</bitWidth>
              <access>read-write</access>
              <enumeratedValues>
                <enumeratedValue>
                  <name>0</name>
                  <description>LCD segment off or LCD backplane inactive for phase B</description>
                  <value>#0</value>
                </enumeratedValue>
                <enumeratedValue>
                  <name>1</name>
                  <description>LCD segment on or LCD backplane active for phase B</description>
                  <value>#1</value>
                </enumeratedValue>
              </enumeratedValues>
            </field>
            <field>
              <name>BPCLCD19</name>
              <description>no description available</description>
              <bitOffset>2</bitOffset>
              <bitWidth>1</bitWidth>
              <access>read-write</access>
              <enumeratedValues>
                <enumeratedValue>
                  <name>0</name>
                  <description>LCD segment off or LCD backplane inactive for phase C</description>
                  <value>#0</value>
                </enumeratedValue>
                <enumeratedValue>
                  <name>1</name>
                  <description>LCD segment on or LCD backplane active for phase C</description>
                  <value>#1</value>
                </enumeratedValue>
              </enumeratedValues>
            </field>
            <field>
              <name>BPDLCD19</name>
              <description>no description available</description>
              <bitOffset>3</bitOffset>
              <bitWidth>1</bitWidth>
              <access>read-write</access>
              <enumeratedValues>
                <enumeratedValue>
                  <name>0</name>
                  <description>LCD segment off or LCD backplane inactive for phase D</description>
                  <value>#0</value>
                </enumeratedValue>
                <enumeratedValue>
                  <name>1</name>
                  <description>LCD segment on or LCD backplane active for phase D</description>
                  <value>#1</value>
                </enumeratedValue>
              </enumeratedValues>
            </field>
            <field>
              <name>BPELCD19</name>
              <description>no description available</description>
              <bitOffset>4</bitOffset>
              <bitWidth>1</bitWidth>
              <access>read-write</access>
              <enumeratedValues>
                <enumeratedValue>
                  <name>0</name>
                  <description>LCD segment off or LCD backplane inactive for phase E</description>
                  <value>#0</value>
                </enumeratedValue>
                <enumeratedValue>
                  <name>1</name>
                  <description>LCD segment on or LCD backplane active for phase E</description>
                  <value>#1</value>
                </enumeratedValue>
              </enumeratedValues>
            </field>
            <field>
              <name>BPFLCD19</name>
              <description>no description available</description>
              <bitOffset>5</bitOffset>
              <bitWidth>1</bitWidth>
              <access>read-write</access>
              <enumeratedValues>
                <enumeratedValue>
                  <name>0</name>
                  <description>LCD segment off or LCD backplane inactive for phase F</description>
                  <value>#0</value>
                </enumeratedValue>
                <enumeratedValue>
                  <name>1</name>
                  <description>LCD segment on or LCD backplane active for phase F</description>
                  <value>#1</value>
                </enumeratedValue>
              </enumeratedValues>
            </field>
            <field>
              <name>BPGLCD19</name>
              <description>no description available</description>
              <bitOffset>6</bitOffset>
              <bitWidth>1</bitWidth>
              <access>read-write</access>
              <enumeratedValues>
                <enumeratedValue>
                  <name>0</name>
                  <description>LCD segment off or LCD backplane inactive for phase G</description>
                  <value>#0</value>
                </enumeratedValue>
                <enumeratedValue>
                  <name>1</name>
                  <description>LCD segment on or LCD backplane active for phase G</description>
                  <value>#1</value>
                </enumeratedValue>
              </enumeratedValues>
            </field>
            <field>
              <name>BPHLCD19</name>
              <description>no description available</description>
              <bitOffset>7</bitOffset>
              <bitWidth>1</bitWidth>
              <access>read-write</access>
              <enumeratedValues>
                <enumeratedValue>
                  <name>0</name>
                  <description>LCD segment off or LCD backplane inactive for phase H</description>
                  <value>#0</value>
                </enumeratedValue>
                <enumeratedValue>
                  <name>1</name>
                  <description>LCD segment on or LCD backplane active for phase H</description>
                  <value>#1</value>
                </enumeratedValue>
              </enumeratedValues>
            </field>
          </fields>
        </register>
        <register>
          <name>WF23TO20</name>
          <description>LCD Waveform register</description>
          <alternateGroup>LCD</alternateGroup>
          <addressOffset>0x34</addressOffset>
          <size>32</size>
          <access>read-write</access>
          <resetValue>0</resetValue>
          <resetMask>0xFFFFFFFF</resetMask>
          <fields>
            <field>
              <name>WF20</name>
              <description>Controls segments or phases connected to LCD_P20 as described above for WF3TO0[WF3].</description>
              <bitOffset>0</bitOffset>
              <bitWidth>8</bitWidth>
              <access>read-write</access>
            </field>
            <field>
              <name>WF21</name>
              <description>Controls segments or phases connected to LCD_P21 as described above for WF3TO0[WF3].</description>
              <bitOffset>8</bitOffset>
              <bitWidth>8</bitWidth>
              <access>read-write</access>
            </field>
            <field>
              <name>WF22</name>
              <description>Controls segments or phases connected to LCD_P22 as described above for WF3TO0[WF3].</description>
              <bitOffset>16</bitOffset>
              <bitWidth>8</bitWidth>
              <access>read-write</access>
            </field>
            <field>
              <name>WF23</name>
              <description>Controls segments or phases connected to LCD_P23 as described above for WF3TO0[WF3].</description>
              <bitOffset>24</bitOffset>
              <bitWidth>8</bitWidth>
              <access>read-write</access>
            </field>
          </fields>
        </register>
        <register>
          <name>WF20</name>
          <description>LCD Waveform Register 20.</description>
          <alternateGroup>LCD</alternateGroup>
          <addressOffset>0x34</addressOffset>
          <size>8</size>
          <access>read-write</access>
          <resetValue>0</resetValue>
          <resetMask>0</resetMask>
          <fields>
            <field>
              <name>BPALCD20</name>
              <description>no description available</description>
              <bitOffset>0</bitOffset>
              <bitWidth>1</bitWidth>
              <access>read-write</access>
              <enumeratedValues>
                <enumeratedValue>
                  <name>0</name>
                  <description>LCD segment off or LCD backplane inactive for phase A</description>
                  <value>#0</value>
                </enumeratedValue>
                <enumeratedValue>
                  <name>1</name>
                  <description>LCD segment on or LCD backplane active for phase A</description>
                  <value>#1</value>
                </enumeratedValue>
              </enumeratedValues>
            </field>
            <field>
              <name>BPBLCD20</name>
              <description>no description available</description>
              <bitOffset>1</bitOffset>
              <bitWidth>1</bitWidth>
              <access>read-write</access>
              <enumeratedValues>
                <enumeratedValue>
                  <name>0</name>
                  <description>LCD segment off or LCD backplane inactive for phase B</description>
                  <value>#0</value>
                </enumeratedValue>
                <enumeratedValue>
                  <name>1</name>
                  <description>LCD segment on or LCD backplane active for phase B</description>
                  <value>#1</value>
                </enumeratedValue>
              </enumeratedValues>
            </field>
            <field>
              <name>BPCLCD20</name>
              <description>no description available</description>
              <bitOffset>2</bitOffset>
              <bitWidth>1</bitWidth>
              <access>read-write</access>
              <enumeratedValues>
                <enumeratedValue>
                  <name>0</name>
                  <description>LCD segment off or LCD backplane inactive for phase C</description>
                  <value>#0</value>
                </enumeratedValue>
                <enumeratedValue>
                  <name>1</name>
                  <description>LCD segment on or LCD backplane active for phase C</description>
                  <value>#1</value>
                </enumeratedValue>
              </enumeratedValues>
            </field>
            <field>
              <name>BPDLCD20</name>
              <description>no description available</description>
              <bitOffset>3</bitOffset>
              <bitWidth>1</bitWidth>
              <access>read-write</access>
              <enumeratedValues>
                <enumeratedValue>
                  <name>0</name>
                  <description>LCD segment off or LCD backplane inactive for phase D</description>
                  <value>#0</value>
                </enumeratedValue>
                <enumeratedValue>
                  <name>1</name>
                  <description>LCD segment on or LCD backplane active for phase D</description>
                  <value>#1</value>
                </enumeratedValue>
              </enumeratedValues>
            </field>
            <field>
              <name>BPELCD20</name>
              <description>no description available</description>
              <bitOffset>4</bitOffset>
              <bitWidth>1</bitWidth>
              <access>read-write</access>
              <enumeratedValues>
                <enumeratedValue>
                  <name>0</name>
                  <description>LCD segment off or LCD backplane inactive for phase E</description>
                  <value>#0</value>
                </enumeratedValue>
                <enumeratedValue>
                  <name>1</name>
                  <description>LCD segment on or LCD backplane active for phase E</description>
                  <value>#1</value>
                </enumeratedValue>
              </enumeratedValues>
            </field>
            <field>
              <name>BPFLCD20</name>
              <description>no description available</description>
              <bitOffset>5</bitOffset>
              <bitWidth>1</bitWidth>
              <access>read-write</access>
              <enumeratedValues>
                <enumeratedValue>
                  <name>0</name>
                  <description>LCD segment off or LCD backplane inactive for phase F</description>
                  <value>#0</value>
                </enumeratedValue>
                <enumeratedValue>
                  <name>1</name>
                  <description>LCD segment on or LCD backplane active for phase F</description>
                  <value>#1</value>
                </enumeratedValue>
              </enumeratedValues>
            </field>
            <field>
              <name>BPGLCD20</name>
              <description>no description available</description>
              <bitOffset>6</bitOffset>
              <bitWidth>1</bitWidth>
              <access>read-write</access>
              <enumeratedValues>
                <enumeratedValue>
                  <name>0</name>
                  <description>LCD segment off or LCD backplane inactive for phase G</description>
                  <value>#0</value>
                </enumeratedValue>
                <enumeratedValue>
                  <name>1</name>
                  <description>LCD segment on or LCD backplane active for phase G</description>
                  <value>#1</value>
                </enumeratedValue>
              </enumeratedValues>
            </field>
            <field>
              <name>BPHLCD20</name>
              <description>no description available</description>
              <bitOffset>7</bitOffset>
              <bitWidth>1</bitWidth>
              <access>read-write</access>
              <enumeratedValues>
                <enumeratedValue>
                  <name>0</name>
                  <description>LCD segment off or LCD backplane inactive for phase H</description>
                  <value>#0</value>
                </enumeratedValue>
                <enumeratedValue>
                  <name>1</name>
                  <description>LCD segment on or LCD backplane active for phase H</description>
                  <value>#1</value>
                </enumeratedValue>
              </enumeratedValues>
            </field>
          </fields>
        </register>
        <register>
          <name>WF21</name>
          <description>LCD Waveform Register 21.</description>
          <addressOffset>0x35</addressOffset>
          <size>8</size>
          <access>read-write</access>
          <resetValue>0</resetValue>
          <resetMask>0</resetMask>
          <fields>
            <field>
              <name>BPALCD21</name>
              <description>no description available</description>
              <bitOffset>0</bitOffset>
              <bitWidth>1</bitWidth>
              <access>read-write</access>
              <enumeratedValues>
                <enumeratedValue>
                  <name>0</name>
                  <description>LCD segment off or LCD backplane inactive for phase A</description>
                  <value>#0</value>
                </enumeratedValue>
                <enumeratedValue>
                  <name>1</name>
                  <description>LCD segment on or LCD backplane active for phase A</description>
                  <value>#1</value>
                </enumeratedValue>
              </enumeratedValues>
            </field>
            <field>
              <name>BPBLCD21</name>
              <description>no description available</description>
              <bitOffset>1</bitOffset>
              <bitWidth>1</bitWidth>
              <access>read-write</access>
              <enumeratedValues>
                <enumeratedValue>
                  <name>0</name>
                  <description>LCD segment off or LCD backplane inactive for phase B</description>
                  <value>#0</value>
                </enumeratedValue>
                <enumeratedValue>
                  <name>1</name>
                  <description>LCD segment on or LCD backplane active for phase B</description>
                  <value>#1</value>
                </enumeratedValue>
              </enumeratedValues>
            </field>
            <field>
              <name>BPCLCD21</name>
              <description>no description available</description>
              <bitOffset>2</bitOffset>
              <bitWidth>1</bitWidth>
              <access>read-write</access>
              <enumeratedValues>
                <enumeratedValue>
                  <name>0</name>
                  <description>LCD segment off or LCD backplane inactive for phase C</description>
                  <value>#0</value>
                </enumeratedValue>
                <enumeratedValue>
                  <name>1</name>
                  <description>LCD segment on or LCD backplane active for phase C</description>
                  <value>#1</value>
                </enumeratedValue>
              </enumeratedValues>
            </field>
            <field>
              <name>BPDLCD21</name>
              <description>no description available</description>
              <bitOffset>3</bitOffset>
              <bitWidth>1</bitWidth>
              <access>read-write</access>
              <enumeratedValues>
                <enumeratedValue>
                  <name>0</name>
                  <description>LCD segment off or LCD backplane inactive for phase D</description>
                  <value>#0</value>
                </enumeratedValue>
                <enumeratedValue>
                  <name>1</name>
                  <description>LCD segment on or LCD backplane active for phase D</description>
                  <value>#1</value>
                </enumeratedValue>
              </enumeratedValues>
            </field>
            <field>
              <name>BPELCD21</name>
              <description>no description available</description>
              <bitOffset>4</bitOffset>
              <bitWidth>1</bitWidth>
              <access>read-write</access>
              <enumeratedValues>
                <enumeratedValue>
                  <name>0</name>
                  <description>LCD segment off or LCD backplane inactive for phase E</description>
                  <value>#0</value>
                </enumeratedValue>
                <enumeratedValue>
                  <name>1</name>
                  <description>LCD segment on or LCD backplane active for phase E</description>
                  <value>#1</value>
                </enumeratedValue>
              </enumeratedValues>
            </field>
            <field>
              <name>BPFLCD21</name>
              <description>no description available</description>
              <bitOffset>5</bitOffset>
              <bitWidth>1</bitWidth>
              <access>read-write</access>
              <enumeratedValues>
                <enumeratedValue>
                  <name>0</name>
                  <description>LCD segment off or LCD backplane inactive for phase F</description>
                  <value>#0</value>
                </enumeratedValue>
                <enumeratedValue>
                  <name>1</name>
                  <description>LCD segment on or LCD backplane active for phase F</description>
                  <value>#1</value>
                </enumeratedValue>
              </enumeratedValues>
            </field>
            <field>
              <name>BPGLCD21</name>
              <description>no description available</description>
              <bitOffset>6</bitOffset>
              <bitWidth>1</bitWidth>
              <access>read-write</access>
              <enumeratedValues>
                <enumeratedValue>
                  <name>0</name>
                  <description>LCD segment off or LCD backplane inactive for phase G</description>
                  <value>#0</value>
                </enumeratedValue>
                <enumeratedValue>
                  <name>1</name>
                  <description>LCD segment on or LCD backplane active for phase G</description>
                  <value>#1</value>
                </enumeratedValue>
              </enumeratedValues>
            </field>
            <field>
              <name>BPHLCD21</name>
              <description>no description available</description>
              <bitOffset>7</bitOffset>
              <bitWidth>1</bitWidth>
              <access>read-write</access>
              <enumeratedValues>
                <enumeratedValue>
                  <name>0</name>
                  <description>LCD segment off or LCD backplane inactive for phase H</description>
                  <value>#0</value>
                </enumeratedValue>
                <enumeratedValue>
                  <name>1</name>
                  <description>LCD segment on or LCD backplane active for phase H</description>
                  <value>#1</value>
                </enumeratedValue>
              </enumeratedValues>
            </field>
          </fields>
        </register>
        <register>
          <name>WF22</name>
          <description>LCD Waveform Register 22.</description>
          <addressOffset>0x36</addressOffset>
          <size>8</size>
          <access>read-write</access>
          <resetValue>0</resetValue>
          <resetMask>0</resetMask>
          <fields>
            <field>
              <name>BPALCD22</name>
              <description>no description available</description>
              <bitOffset>0</bitOffset>
              <bitWidth>1</bitWidth>
              <access>read-write</access>
              <enumeratedValues>
                <enumeratedValue>
                  <name>0</name>
                  <description>LCD segment off or LCD backplane inactive for phase A</description>
                  <value>#0</value>
                </enumeratedValue>
                <enumeratedValue>
                  <name>1</name>
                  <description>LCD segment on or LCD backplane active for phase A</description>
                  <value>#1</value>
                </enumeratedValue>
              </enumeratedValues>
            </field>
            <field>
              <name>BPBLCD22</name>
              <description>no description available</description>
              <bitOffset>1</bitOffset>
              <bitWidth>1</bitWidth>
              <access>read-write</access>
              <enumeratedValues>
                <enumeratedValue>
                  <name>0</name>
                  <description>LCD segment off or LCD backplane inactive for phase B</description>
                  <value>#0</value>
                </enumeratedValue>
                <enumeratedValue>
                  <name>1</name>
                  <description>LCD segment on or LCD backplane active for phase B</description>
                  <value>#1</value>
                </enumeratedValue>
              </enumeratedValues>
            </field>
            <field>
              <name>BPCLCD22</name>
              <description>no description available</description>
              <bitOffset>2</bitOffset>
              <bitWidth>1</bitWidth>
              <access>read-write</access>
              <enumeratedValues>
                <enumeratedValue>
                  <name>0</name>
                  <description>LCD segment off or LCD backplane inactive for phase C</description>
                  <value>#0</value>
                </enumeratedValue>
                <enumeratedValue>
                  <name>1</name>
                  <description>LCD segment on or LCD backplane active for phase C</description>
                  <value>#1</value>
                </enumeratedValue>
              </enumeratedValues>
            </field>
            <field>
              <name>BPDLCD22</name>
              <description>no description available</description>
              <bitOffset>3</bitOffset>
              <bitWidth>1</bitWidth>
              <access>read-write</access>
              <enumeratedValues>
                <enumeratedValue>
                  <name>0</name>
                  <description>LCD segment off or LCD backplane inactive for phase D</description>
                  <value>#0</value>
                </enumeratedValue>
                <enumeratedValue>
                  <name>1</name>
                  <description>LCD segment on or LCD backplane active for phase D</description>
                  <value>#1</value>
                </enumeratedValue>
              </enumeratedValues>
            </field>
            <field>
              <name>BPELCD22</name>
              <description>no description available</description>
              <bitOffset>4</bitOffset>
              <bitWidth>1</bitWidth>
              <access>read-write</access>
              <enumeratedValues>
                <enumeratedValue>
                  <name>0</name>
                  <description>LCD segment off or LCD backplane inactive for phase E</description>
                  <value>#0</value>
                </enumeratedValue>
                <enumeratedValue>
                  <name>1</name>
                  <description>LCD segment on or LCD backplane active for phase E</description>
                  <value>#1</value>
                </enumeratedValue>
              </enumeratedValues>
            </field>
            <field>
              <name>BPFLCD22</name>
              <description>no description available</description>
              <bitOffset>5</bitOffset>
              <bitWidth>1</bitWidth>
              <access>read-write</access>
              <enumeratedValues>
                <enumeratedValue>
                  <name>0</name>
                  <description>LCD segment off or LCD backplane inactive for phase F</description>
                  <value>#0</value>
                </enumeratedValue>
                <enumeratedValue>
                  <name>1</name>
                  <description>LCD segment on or LCD backplane active for phase F</description>
                  <value>#1</value>
                </enumeratedValue>
              </enumeratedValues>
            </field>
            <field>
              <name>BPGLCD22</name>
              <description>no description available</description>
              <bitOffset>6</bitOffset>
              <bitWidth>1</bitWidth>
              <access>read-write</access>
              <enumeratedValues>
                <enumeratedValue>
                  <name>0</name>
                  <description>LCD segment off or LCD backplane inactive for phase G</description>
                  <value>#0</value>
                </enumeratedValue>
                <enumeratedValue>
                  <name>1</name>
                  <description>LCD segment on or LCD backplane active for phase G</description>
                  <value>#1</value>
                </enumeratedValue>
              </enumeratedValues>
            </field>
            <field>
              <name>BPHLCD22</name>
              <description>no description available</description>
              <bitOffset>7</bitOffset>
              <bitWidth>1</bitWidth>
              <access>read-write</access>
              <enumeratedValues>
                <enumeratedValue>
                  <name>0</name>
                  <description>LCD segment off or LCD backplane inactive for phase H</description>
                  <value>#0</value>
                </enumeratedValue>
                <enumeratedValue>
                  <name>1</name>
                  <description>LCD segment on or LCD backplane active for phase H</description>
                  <value>#1</value>
                </enumeratedValue>
              </enumeratedValues>
            </field>
          </fields>
        </register>
        <register>
          <name>WF23</name>
          <description>LCD Waveform Register 23.</description>
          <addressOffset>0x37</addressOffset>
          <size>8</size>
          <access>read-write</access>
          <resetValue>0</resetValue>
          <resetMask>0</resetMask>
          <fields>
            <field>
              <name>BPALCD23</name>
              <description>no description available</description>
              <bitOffset>0</bitOffset>
              <bitWidth>1</bitWidth>
              <access>read-write</access>
              <enumeratedValues>
                <enumeratedValue>
                  <name>0</name>
                  <description>LCD segment off or LCD backplane inactive for phase A</description>
                  <value>#0</value>
                </enumeratedValue>
                <enumeratedValue>
                  <name>1</name>
                  <description>LCD segment on or LCD backplane active for phase A</description>
                  <value>#1</value>
                </enumeratedValue>
              </enumeratedValues>
            </field>
            <field>
              <name>BPBLCD23</name>
              <description>no description available</description>
              <bitOffset>1</bitOffset>
              <bitWidth>1</bitWidth>
              <access>read-write</access>
              <enumeratedValues>
                <enumeratedValue>
                  <name>0</name>
                  <description>LCD segment off or LCD backplane inactive for phase B</description>
                  <value>#0</value>
                </enumeratedValue>
                <enumeratedValue>
                  <name>1</name>
                  <description>LCD segment on or LCD backplane active for phase B</description>
                  <value>#1</value>
                </enumeratedValue>
              </enumeratedValues>
            </field>
            <field>
              <name>BPCLCD23</name>
              <description>no description available</description>
              <bitOffset>2</bitOffset>
              <bitWidth>1</bitWidth>
              <access>read-write</access>
              <enumeratedValues>
                <enumeratedValue>
                  <name>0</name>
                  <description>LCD segment off or LCD backplane inactive for phase C</description>
                  <value>#0</value>
                </enumeratedValue>
                <enumeratedValue>
                  <name>1</name>
                  <description>LCD segment on or LCD backplane active for phase C</description>
                  <value>#1</value>
                </enumeratedValue>
              </enumeratedValues>
            </field>
            <field>
              <name>BPDLCD23</name>
              <description>no description available</description>
              <bitOffset>3</bitOffset>
              <bitWidth>1</bitWidth>
              <access>read-write</access>
              <enumeratedValues>
                <enumeratedValue>
                  <name>0</name>
                  <description>LCD segment off or LCD backplane inactive for phase D</description>
                  <value>#0</value>
                </enumeratedValue>
                <enumeratedValue>
                  <name>1</name>
                  <description>LCD segment on or LCD backplane active for phase D</description>
                  <value>#1</value>
                </enumeratedValue>
              </enumeratedValues>
            </field>
            <field>
              <name>BPELCD23</name>
              <description>no description available</description>
              <bitOffset>4</bitOffset>
              <bitWidth>1</bitWidth>
              <access>read-write</access>
              <enumeratedValues>
                <enumeratedValue>
                  <name>0</name>
                  <description>LCD segment off or LCD backplane inactive for phase E</description>
                  <value>#0</value>
                </enumeratedValue>
                <enumeratedValue>
                  <name>1</name>
                  <description>LCD segment on or LCD backplane active for phase E</description>
                  <value>#1</value>
                </enumeratedValue>
              </enumeratedValues>
            </field>
            <field>
              <name>BPFLCD23</name>
              <description>no description available</description>
              <bitOffset>5</bitOffset>
              <bitWidth>1</bitWidth>
              <access>read-write</access>
              <enumeratedValues>
                <enumeratedValue>
                  <name>0</name>
                  <description>LCD segment off or LCD backplane inactive for phase F</description>
                  <value>#0</value>
                </enumeratedValue>
                <enumeratedValue>
                  <name>1</name>
                  <description>LCD segment on or LCD backplane active for phase F</description>
                  <value>#1</value>
                </enumeratedValue>
              </enumeratedValues>
            </field>
            <field>
              <name>BPGLCD23</name>
              <description>no description available</description>
              <bitOffset>6</bitOffset>
              <bitWidth>1</bitWidth>
              <access>read-write</access>
              <enumeratedValues>
                <enumeratedValue>
                  <name>0</name>
                  <description>LCD segment off or LCD backplane inactive for phase G</description>
                  <value>#0</value>
                </enumeratedValue>
                <enumeratedValue>
                  <name>1</name>
                  <description>LCD segment on or LCD backplane active for phase G</description>
                  <value>#1</value>
                </enumeratedValue>
              </enumeratedValues>
            </field>
            <field>
              <name>BPHLCD23</name>
              <description>no description available</description>
              <bitOffset>7</bitOffset>
              <bitWidth>1</bitWidth>
              <access>read-write</access>
              <enumeratedValues>
                <enumeratedValue>
                  <name>0</name>
                  <description>LCD segment off or LCD backplane inactive for phase H</description>
                  <value>#0</value>
                </enumeratedValue>
                <enumeratedValue>
                  <name>1</name>
                  <description>LCD segment on or LCD backplane active for phase H</description>
                  <value>#1</value>
                </enumeratedValue>
              </enumeratedValues>
            </field>
          </fields>
        </register>
        <register>
          <name>WF27TO24</name>
          <description>LCD Waveform register</description>
          <alternateGroup>LCD</alternateGroup>
          <addressOffset>0x38</addressOffset>
          <size>32</size>
          <access>read-write</access>
          <resetValue>0</resetValue>
          <resetMask>0xFFFFFFFF</resetMask>
          <fields>
            <field>
              <name>WF24</name>
              <description>Controls segments or phases connected to LCD_P24 as described above for WF3TO0[WF3].</description>
              <bitOffset>0</bitOffset>
              <bitWidth>8</bitWidth>
              <access>read-write</access>
            </field>
            <field>
              <name>WF25</name>
              <description>Controls segments or phases connected to LCD_P25 as described above for WF3TO0[WF3].</description>
              <bitOffset>8</bitOffset>
              <bitWidth>8</bitWidth>
              <access>read-write</access>
            </field>
            <field>
              <name>WF26</name>
              <description>Controls segments or phases connected to LCD_P26 as described above for WF3TO0[WF3].</description>
              <bitOffset>16</bitOffset>
              <bitWidth>8</bitWidth>
              <access>read-write</access>
            </field>
            <field>
              <name>WF27</name>
              <description>Controls segments or phases connected to LCD_P27 as described above for WF3TO0[WF3].</description>
              <bitOffset>24</bitOffset>
              <bitWidth>8</bitWidth>
              <access>read-write</access>
            </field>
          </fields>
        </register>
        <register>
          <name>WF24</name>
          <description>LCD Waveform Register 24.</description>
          <alternateGroup>LCD</alternateGroup>
          <addressOffset>0x38</addressOffset>
          <size>8</size>
          <access>read-write</access>
          <resetValue>0</resetValue>
          <resetMask>0</resetMask>
          <fields>
            <field>
              <name>BPALCD24</name>
              <description>no description available</description>
              <bitOffset>0</bitOffset>
              <bitWidth>1</bitWidth>
              <access>read-write</access>
              <enumeratedValues>
                <enumeratedValue>
                  <name>0</name>
                  <description>LCD segment off or LCD backplane inactive for phase A</description>
                  <value>#0</value>
                </enumeratedValue>
                <enumeratedValue>
                  <name>1</name>
                  <description>LCD segment on or LCD backplane active for phase A</description>
                  <value>#1</value>
                </enumeratedValue>
              </enumeratedValues>
            </field>
            <field>
              <name>BPBLCD24</name>
              <description>no description available</description>
              <bitOffset>1</bitOffset>
              <bitWidth>1</bitWidth>
              <access>read-write</access>
              <enumeratedValues>
                <enumeratedValue>
                  <name>0</name>
                  <description>LCD segment off or LCD backplane inactive for phase B</description>
                  <value>#0</value>
                </enumeratedValue>
                <enumeratedValue>
                  <name>1</name>
                  <description>LCD segment on or LCD backplane active for phase B</description>
                  <value>#1</value>
                </enumeratedValue>
              </enumeratedValues>
            </field>
            <field>
              <name>BPCLCD24</name>
              <description>no description available</description>
              <bitOffset>2</bitOffset>
              <bitWidth>1</bitWidth>
              <access>read-write</access>
              <enumeratedValues>
                <enumeratedValue>
                  <name>0</name>
                  <description>LCD segment off or LCD backplane inactive for phase C</description>
                  <value>#0</value>
                </enumeratedValue>
                <enumeratedValue>
                  <name>1</name>
                  <description>LCD segment on or LCD backplane active for phase C</description>
                  <value>#1</value>
                </enumeratedValue>
              </enumeratedValues>
            </field>
            <field>
              <name>BPDLCD24</name>
              <description>no description available</description>
              <bitOffset>3</bitOffset>
              <bitWidth>1</bitWidth>
              <access>read-write</access>
              <enumeratedValues>
                <enumeratedValue>
                  <name>0</name>
                  <description>LCD segment off or LCD backplane inactive for phase D</description>
                  <value>#0</value>
                </enumeratedValue>
                <enumeratedValue>
                  <name>1</name>
                  <description>LCD segment on or LCD backplane active for phase D</description>
                  <value>#1</value>
                </enumeratedValue>
              </enumeratedValues>
            </field>
            <field>
              <name>BPELCD24</name>
              <description>no description available</description>
              <bitOffset>4</bitOffset>
              <bitWidth>1</bitWidth>
              <access>read-write</access>
              <enumeratedValues>
                <enumeratedValue>
                  <name>0</name>
                  <description>LCD segment off or LCD backplane inactive for phase E</description>
                  <value>#0</value>
                </enumeratedValue>
                <enumeratedValue>
                  <name>1</name>
                  <description>LCD segment on or LCD backplane active for phase E</description>
                  <value>#1</value>
                </enumeratedValue>
              </enumeratedValues>
            </field>
            <field>
              <name>BPFLCD24</name>
              <description>no description available</description>
              <bitOffset>5</bitOffset>
              <bitWidth>1</bitWidth>
              <access>read-write</access>
              <enumeratedValues>
                <enumeratedValue>
                  <name>0</name>
                  <description>LCD segment off or LCD backplane inactive for phase F</description>
                  <value>#0</value>
                </enumeratedValue>
                <enumeratedValue>
                  <name>1</name>
                  <description>LCD segment on or LCD backplane active for phase F</description>
                  <value>#1</value>
                </enumeratedValue>
              </enumeratedValues>
            </field>
            <field>
              <name>BPGLCD24</name>
              <description>no description available</description>
              <bitOffset>6</bitOffset>
              <bitWidth>1</bitWidth>
              <access>read-write</access>
              <enumeratedValues>
                <enumeratedValue>
                  <name>0</name>
                  <description>LCD segment off or LCD backplane inactive for phase G</description>
                  <value>#0</value>
                </enumeratedValue>
                <enumeratedValue>
                  <name>1</name>
                  <description>LCD segment on or LCD backplane active for phase G</description>
                  <value>#1</value>
                </enumeratedValue>
              </enumeratedValues>
            </field>
            <field>
              <name>BPHLCD24</name>
              <description>no description available</description>
              <bitOffset>7</bitOffset>
              <bitWidth>1</bitWidth>
              <access>read-write</access>
              <enumeratedValues>
                <enumeratedValue>
                  <name>0</name>
                  <description>LCD segment off or LCD backplane inactive for phase H</description>
                  <value>#0</value>
                </enumeratedValue>
                <enumeratedValue>
                  <name>1</name>
                  <description>LCD segment on or LCD backplane active for phase H</description>
                  <value>#1</value>
                </enumeratedValue>
              </enumeratedValues>
            </field>
          </fields>
        </register>
        <register>
          <name>WF25</name>
          <description>LCD Waveform Register 25.</description>
          <addressOffset>0x39</addressOffset>
          <size>8</size>
          <access>read-write</access>
          <resetValue>0</resetValue>
          <resetMask>0</resetMask>
          <fields>
            <field>
              <name>BPALCD25</name>
              <description>no description available</description>
              <bitOffset>0</bitOffset>
              <bitWidth>1</bitWidth>
              <access>read-write</access>
              <enumeratedValues>
                <enumeratedValue>
                  <name>0</name>
                  <description>LCD segment off or LCD backplane inactive for phase A</description>
                  <value>#0</value>
                </enumeratedValue>
                <enumeratedValue>
                  <name>1</name>
                  <description>LCD segment on or LCD backplane active for phase A</description>
                  <value>#1</value>
                </enumeratedValue>
              </enumeratedValues>
            </field>
            <field>
              <name>BPBLCD25</name>
              <description>no description available</description>
              <bitOffset>1</bitOffset>
              <bitWidth>1</bitWidth>
              <access>read-write</access>
              <enumeratedValues>
                <enumeratedValue>
                  <name>0</name>
                  <description>LCD segment off or LCD backplane inactive for phase B</description>
                  <value>#0</value>
                </enumeratedValue>
                <enumeratedValue>
                  <name>1</name>
                  <description>LCD segment on or LCD backplane active for phase B</description>
                  <value>#1</value>
                </enumeratedValue>
              </enumeratedValues>
            </field>
            <field>
              <name>BPCLCD25</name>
              <description>no description available</description>
              <bitOffset>2</bitOffset>
              <bitWidth>1</bitWidth>
              <access>read-write</access>
              <enumeratedValues>
                <enumeratedValue>
                  <name>0</name>
                  <description>LCD segment off or LCD backplane inactive for phase C</description>
                  <value>#0</value>
                </enumeratedValue>
                <enumeratedValue>
                  <name>1</name>
                  <description>LCD segment on or LCD backplane active for phase C</description>
                  <value>#1</value>
                </enumeratedValue>
              </enumeratedValues>
            </field>
            <field>
              <name>BPDLCD25</name>
              <description>no description available</description>
              <bitOffset>3</bitOffset>
              <bitWidth>1</bitWidth>
              <access>read-write</access>
              <enumeratedValues>
                <enumeratedValue>
                  <name>0</name>
                  <description>LCD segment off or LCD backplane inactive for phase D</description>
                  <value>#0</value>
                </enumeratedValue>
                <enumeratedValue>
                  <name>1</name>
                  <description>LCD segment on or LCD backplane active for phase D</description>
                  <value>#1</value>
                </enumeratedValue>
              </enumeratedValues>
            </field>
            <field>
              <name>BPELCD25</name>
              <description>no description available</description>
              <bitOffset>4</bitOffset>
              <bitWidth>1</bitWidth>
              <access>read-write</access>
              <enumeratedValues>
                <enumeratedValue>
                  <name>0</name>
                  <description>LCD segment off or LCD backplane inactive for phase E</description>
                  <value>#0</value>
                </enumeratedValue>
                <enumeratedValue>
                  <name>1</name>
                  <description>LCD segment on or LCD backplane active for phase E</description>
                  <value>#1</value>
                </enumeratedValue>
              </enumeratedValues>
            </field>
            <field>
              <name>BPFLCD25</name>
              <description>no description available</description>
              <bitOffset>5</bitOffset>
              <bitWidth>1</bitWidth>
              <access>read-write</access>
              <enumeratedValues>
                <enumeratedValue>
                  <name>0</name>
                  <description>LCD segment off or LCD backplane inactive for phase F</description>
                  <value>#0</value>
                </enumeratedValue>
                <enumeratedValue>
                  <name>1</name>
                  <description>LCD segment on or LCD backplane active for phase F</description>
                  <value>#1</value>
                </enumeratedValue>
              </enumeratedValues>
            </field>
            <field>
              <name>BPGLCD25</name>
              <description>no description available</description>
              <bitOffset>6</bitOffset>
              <bitWidth>1</bitWidth>
              <access>read-write</access>
              <enumeratedValues>
                <enumeratedValue>
                  <name>0</name>
                  <description>LCD segment off or LCD backplane inactive for phase G</description>
                  <value>#0</value>
                </enumeratedValue>
                <enumeratedValue>
                  <name>1</name>
                  <description>LCD segment on or LCD backplane active for phase G</description>
                  <value>#1</value>
                </enumeratedValue>
              </enumeratedValues>
            </field>
            <field>
              <name>BPHLCD25</name>
              <description>no description available</description>
              <bitOffset>7</bitOffset>
              <bitWidth>1</bitWidth>
              <access>read-write</access>
              <enumeratedValues>
                <enumeratedValue>
                  <name>0</name>
                  <description>LCD segment off or LCD backplane inactive for phase H</description>
                  <value>#0</value>
                </enumeratedValue>
                <enumeratedValue>
                  <name>1</name>
                  <description>LCD segment on or LCD backplane active for phase H</description>
                  <value>#1</value>
                </enumeratedValue>
              </enumeratedValues>
            </field>
          </fields>
        </register>
        <register>
          <name>WF26</name>
          <description>LCD Waveform Register 26.</description>
          <addressOffset>0x3A</addressOffset>
          <size>8</size>
          <access>read-write</access>
          <resetValue>0</resetValue>
          <resetMask>0</resetMask>
          <fields>
            <field>
              <name>BPALCD26</name>
              <description>no description available</description>
              <bitOffset>0</bitOffset>
              <bitWidth>1</bitWidth>
              <access>read-write</access>
              <enumeratedValues>
                <enumeratedValue>
                  <name>0</name>
                  <description>LCD segment off or LCD backplane inactive for phase A</description>
                  <value>#0</value>
                </enumeratedValue>
                <enumeratedValue>
                  <name>1</name>
                  <description>LCD segment on or LCD backplane active for phase A</description>
                  <value>#1</value>
                </enumeratedValue>
              </enumeratedValues>
            </field>
            <field>
              <name>BPBLCD26</name>
              <description>no description available</description>
              <bitOffset>1</bitOffset>
              <bitWidth>1</bitWidth>
              <access>read-write</access>
              <enumeratedValues>
                <enumeratedValue>
                  <name>0</name>
                  <description>LCD segment off or LCD backplane inactive for phase B</description>
                  <value>#0</value>
                </enumeratedValue>
                <enumeratedValue>
                  <name>1</name>
                  <description>LCD segment on or LCD backplane active for phase B</description>
                  <value>#1</value>
                </enumeratedValue>
              </enumeratedValues>
            </field>
            <field>
              <name>BPCLCD26</name>
              <description>no description available</description>
              <bitOffset>2</bitOffset>
              <bitWidth>1</bitWidth>
              <access>read-write</access>
              <enumeratedValues>
                <enumeratedValue>
                  <name>0</name>
                  <description>LCD segment off or LCD backplane inactive for phase C</description>
                  <value>#0</value>
                </enumeratedValue>
                <enumeratedValue>
                  <name>1</name>
                  <description>LCD segment on or LCD backplane active for phase C</description>
                  <value>#1</value>
                </enumeratedValue>
              </enumeratedValues>
            </field>
            <field>
              <name>BPDLCD26</name>
              <description>no description available</description>
              <bitOffset>3</bitOffset>
              <bitWidth>1</bitWidth>
              <access>read-write</access>
              <enumeratedValues>
                <enumeratedValue>
                  <name>0</name>
                  <description>LCD segment off or LCD backplane inactive for phase D</description>
                  <value>#0</value>
                </enumeratedValue>
                <enumeratedValue>
                  <name>1</name>
                  <description>LCD segment on or LCD backplane active for phase D</description>
                  <value>#1</value>
                </enumeratedValue>
              </enumeratedValues>
            </field>
            <field>
              <name>BPELCD26</name>
              <description>no description available</description>
              <bitOffset>4</bitOffset>
              <bitWidth>1</bitWidth>
              <access>read-write</access>
              <enumeratedValues>
                <enumeratedValue>
                  <name>0</name>
                  <description>LCD segment off or LCD backplane inactive for phase E</description>
                  <value>#0</value>
                </enumeratedValue>
                <enumeratedValue>
                  <name>1</name>
                  <description>LCD segment on or LCD backplane active for phase E</description>
                  <value>#1</value>
                </enumeratedValue>
              </enumeratedValues>
            </field>
            <field>
              <name>BPFLCD26</name>
              <description>no description available</description>
              <bitOffset>5</bitOffset>
              <bitWidth>1</bitWidth>
              <access>read-write</access>
              <enumeratedValues>
                <enumeratedValue>
                  <name>0</name>
                  <description>LCD segment off or LCD backplane inactive for phase F</description>
                  <value>#0</value>
                </enumeratedValue>
                <enumeratedValue>
                  <name>1</name>
                  <description>LCD segment on or LCD backplane active for phase F</description>
                  <value>#1</value>
                </enumeratedValue>
              </enumeratedValues>
            </field>
            <field>
              <name>BPGLCD26</name>
              <description>no description available</description>
              <bitOffset>6</bitOffset>
              <bitWidth>1</bitWidth>
              <access>read-write</access>
              <enumeratedValues>
                <enumeratedValue>
                  <name>0</name>
                  <description>LCD segment off or LCD backplane inactive for phase G</description>
                  <value>#0</value>
                </enumeratedValue>
                <enumeratedValue>
                  <name>1</name>
                  <description>LCD segment on or LCD backplane active for phase G</description>
                  <value>#1</value>
                </enumeratedValue>
              </enumeratedValues>
            </field>
            <field>
              <name>BPHLCD26</name>
              <description>no description available</description>
              <bitOffset>7</bitOffset>
              <bitWidth>1</bitWidth>
              <access>read-write</access>
              <enumeratedValues>
                <enumeratedValue>
                  <name>0</name>
                  <description>LCD segment off or LCD backplane inactive for phase H</description>
                  <value>#0</value>
                </enumeratedValue>
                <enumeratedValue>
                  <name>1</name>
                  <description>LCD segment on or LCD backplane active for phase H</description>
                  <value>#1</value>
                </enumeratedValue>
              </enumeratedValues>
            </field>
          </fields>
        </register>
        <register>
          <name>WF27</name>
          <description>LCD Waveform Register 27.</description>
          <addressOffset>0x3B</addressOffset>
          <size>8</size>
          <access>read-write</access>
          <resetValue>0</resetValue>
          <resetMask>0</resetMask>
          <fields>
            <field>
              <name>BPALCD27</name>
              <description>no description available</description>
              <bitOffset>0</bitOffset>
              <bitWidth>1</bitWidth>
              <access>read-write</access>
              <enumeratedValues>
                <enumeratedValue>
                  <name>0</name>
                  <description>LCD segment off or LCD backplane inactive for phase A</description>
                  <value>#0</value>
                </enumeratedValue>
                <enumeratedValue>
                  <name>1</name>
                  <description>LCD segment on or LCD backplane active for phase A</description>
                  <value>#1</value>
                </enumeratedValue>
              </enumeratedValues>
            </field>
            <field>
              <name>BPBLCD27</name>
              <description>no description available</description>
              <bitOffset>1</bitOffset>
              <bitWidth>1</bitWidth>
              <access>read-write</access>
              <enumeratedValues>
                <enumeratedValue>
                  <name>0</name>
                  <description>LCD segment off or LCD backplane inactive for phase B</description>
                  <value>#0</value>
                </enumeratedValue>
                <enumeratedValue>
                  <name>1</name>
                  <description>LCD segment on or LCD backplane active for phase B</description>
                  <value>#1</value>
                </enumeratedValue>
              </enumeratedValues>
            </field>
            <field>
              <name>BPCLCD27</name>
              <description>no description available</description>
              <bitOffset>2</bitOffset>
              <bitWidth>1</bitWidth>
              <access>read-write</access>
              <enumeratedValues>
                <enumeratedValue>
                  <name>0</name>
                  <description>LCD segment off or LCD backplane inactive for phase C</description>
                  <value>#0</value>
                </enumeratedValue>
                <enumeratedValue>
                  <name>1</name>
                  <description>LCD segment on or LCD backplane active for phase C</description>
                  <value>#1</value>
                </enumeratedValue>
              </enumeratedValues>
            </field>
            <field>
              <name>BPDLCD27</name>
              <description>no description available</description>
              <bitOffset>3</bitOffset>
              <bitWidth>1</bitWidth>
              <access>read-write</access>
              <enumeratedValues>
                <enumeratedValue>
                  <name>0</name>
                  <description>LCD segment off or LCD backplane inactive for phase D</description>
                  <value>#0</value>
                </enumeratedValue>
                <enumeratedValue>
                  <name>1</name>
                  <description>LCD segment on or LCD backplane active for phase D</description>
                  <value>#1</value>
                </enumeratedValue>
              </enumeratedValues>
            </field>
            <field>
              <name>BPELCD27</name>
              <description>no description available</description>
              <bitOffset>4</bitOffset>
              <bitWidth>1</bitWidth>
              <access>read-write</access>
              <enumeratedValues>
                <enumeratedValue>
                  <name>0</name>
                  <description>LCD segment off or LCD backplane inactive for phase E</description>
                  <value>#0</value>
                </enumeratedValue>
                <enumeratedValue>
                  <name>1</name>
                  <description>LCD segment on or LCD backplane active for phase E</description>
                  <value>#1</value>
                </enumeratedValue>
              </enumeratedValues>
            </field>
            <field>
              <name>BPFLCD27</name>
              <description>no description available</description>
              <bitOffset>5</bitOffset>
              <bitWidth>1</bitWidth>
              <access>read-write</access>
              <enumeratedValues>
                <enumeratedValue>
                  <name>0</name>
                  <description>LCD segment off or LCD backplane inactive for phase F</description>
                  <value>#0</value>
                </enumeratedValue>
                <enumeratedValue>
                  <name>1</name>
                  <description>LCD segment on or LCD backplane active for phase F</description>
                  <value>#1</value>
                </enumeratedValue>
              </enumeratedValues>
            </field>
            <field>
              <name>BPGLCD27</name>
              <description>no description available</description>
              <bitOffset>6</bitOffset>
              <bitWidth>1</bitWidth>
              <access>read-write</access>
              <enumeratedValues>
                <enumeratedValue>
                  <name>0</name>
                  <description>LCD segment off or LCD backplane inactive for phase G</description>
                  <value>#0</value>
                </enumeratedValue>
                <enumeratedValue>
                  <name>1</name>
                  <description>LCD segment on or LCD backplane active for phase G</description>
                  <value>#1</value>
                </enumeratedValue>
              </enumeratedValues>
            </field>
            <field>
              <name>BPHLCD27</name>
              <description>no description available</description>
              <bitOffset>7</bitOffset>
              <bitWidth>1</bitWidth>
              <access>read-write</access>
              <enumeratedValues>
                <enumeratedValue>
                  <name>0</name>
                  <description>LCD segment off or LCD backplane inactive for phase H</description>
                  <value>#0</value>
                </enumeratedValue>
                <enumeratedValue>
                  <name>1</name>
                  <description>LCD segment on or LCD backplane active for phase H</description>
                  <value>#1</value>
                </enumeratedValue>
              </enumeratedValues>
            </field>
          </fields>
        </register>
        <register>
          <name>WF31TO28</name>
          <description>LCD Waveform register</description>
          <alternateGroup>LCD</alternateGroup>
          <addressOffset>0x3C</addressOffset>
          <size>32</size>
          <access>read-write</access>
          <resetValue>0</resetValue>
          <resetMask>0xFFFFFFFF</resetMask>
          <fields>
            <field>
              <name>WF28</name>
              <description>Controls segments or phases connected to LCD_P28 as described above for WF3TO0[WF3].</description>
              <bitOffset>0</bitOffset>
              <bitWidth>8</bitWidth>
              <access>read-write</access>
            </field>
            <field>
              <name>WF29</name>
              <description>Controls segments or phases connected to LCD_P29 as described above for WF3TO0[WF3].</description>
              <bitOffset>8</bitOffset>
              <bitWidth>8</bitWidth>
              <access>read-write</access>
            </field>
            <field>
              <name>WF30</name>
              <description>Controls segments or phases connected to LCD_P30 as described above for WF3TO0[WF3].</description>
              <bitOffset>16</bitOffset>
              <bitWidth>8</bitWidth>
              <access>read-write</access>
            </field>
            <field>
              <name>WF31</name>
              <description>Controls segments or phases connected to LCD_P31 as described above for WF3TO0[WF3].</description>
              <bitOffset>24</bitOffset>
              <bitWidth>8</bitWidth>
              <access>read-write</access>
            </field>
          </fields>
        </register>
        <register>
          <name>WF28</name>
          <description>LCD Waveform Register 28.</description>
          <alternateGroup>LCD</alternateGroup>
          <addressOffset>0x3C</addressOffset>
          <size>8</size>
          <access>read-write</access>
          <resetValue>0</resetValue>
          <resetMask>0</resetMask>
          <fields>
            <field>
              <name>BPALCD28</name>
              <description>no description available</description>
              <bitOffset>0</bitOffset>
              <bitWidth>1</bitWidth>
              <access>read-write</access>
              <enumeratedValues>
                <enumeratedValue>
                  <name>0</name>
                  <description>LCD segment off or LCD backplane inactive for phase A</description>
                  <value>#0</value>
                </enumeratedValue>
                <enumeratedValue>
                  <name>1</name>
                  <description>LCD segment on or LCD backplane active for phase A</description>
                  <value>#1</value>
                </enumeratedValue>
              </enumeratedValues>
            </field>
            <field>
              <name>BPBLCD28</name>
              <description>no description available</description>
              <bitOffset>1</bitOffset>
              <bitWidth>1</bitWidth>
              <access>read-write</access>
              <enumeratedValues>
                <enumeratedValue>
                  <name>0</name>
                  <description>LCD segment off or LCD backplane inactive for phase B</description>
                  <value>#0</value>
                </enumeratedValue>
                <enumeratedValue>
                  <name>1</name>
                  <description>LCD segment on or LCD backplane active for phase B</description>
                  <value>#1</value>
                </enumeratedValue>
              </enumeratedValues>
            </field>
            <field>
              <name>BPCLCD28</name>
              <description>no description available</description>
              <bitOffset>2</bitOffset>
              <bitWidth>1</bitWidth>
              <access>read-write</access>
              <enumeratedValues>
                <enumeratedValue>
                  <name>0</name>
                  <description>LCD segment off or LCD backplane inactive for phase C</description>
                  <value>#0</value>
                </enumeratedValue>
                <enumeratedValue>
                  <name>1</name>
                  <description>LCD segment on or LCD backplane active for phase C</description>
                  <value>#1</value>
                </enumeratedValue>
              </enumeratedValues>
            </field>
            <field>
              <name>BPDLCD28</name>
              <description>no description available</description>
              <bitOffset>3</bitOffset>
              <bitWidth>1</bitWidth>
              <access>read-write</access>
              <enumeratedValues>
                <enumeratedValue>
                  <name>0</name>
                  <description>LCD segment off or LCD backplane inactive for phase D</description>
                  <value>#0</value>
                </enumeratedValue>
                <enumeratedValue>
                  <name>1</name>
                  <description>LCD segment on or LCD backplane active for phase D</description>
                  <value>#1</value>
                </enumeratedValue>
              </enumeratedValues>
            </field>
            <field>
              <name>BPELCD28</name>
              <description>no description available</description>
              <bitOffset>4</bitOffset>
              <bitWidth>1</bitWidth>
              <access>read-write</access>
              <enumeratedValues>
                <enumeratedValue>
                  <name>0</name>
                  <description>LCD segment off or LCD backplane inactive for phase E</description>
                  <value>#0</value>
                </enumeratedValue>
                <enumeratedValue>
                  <name>1</name>
                  <description>LCD segment on or LCD backplane active for phase E</description>
                  <value>#1</value>
                </enumeratedValue>
              </enumeratedValues>
            </field>
            <field>
              <name>BPFLCD28</name>
              <description>no description available</description>
              <bitOffset>5</bitOffset>
              <bitWidth>1</bitWidth>
              <access>read-write</access>
              <enumeratedValues>
                <enumeratedValue>
                  <name>0</name>
                  <description>LCD segment off or LCD backplane inactive for phase F</description>
                  <value>#0</value>
                </enumeratedValue>
                <enumeratedValue>
                  <name>1</name>
                  <description>LCD segment on or LCD backplane active for phase F</description>
                  <value>#1</value>
                </enumeratedValue>
              </enumeratedValues>
            </field>
            <field>
              <name>BPGLCD28</name>
              <description>no description available</description>
              <bitOffset>6</bitOffset>
              <bitWidth>1</bitWidth>
              <access>read-write</access>
              <enumeratedValues>
                <enumeratedValue>
                  <name>0</name>
                  <description>LCD segment off or LCD backplane inactive for phase G</description>
                  <value>#0</value>
                </enumeratedValue>
                <enumeratedValue>
                  <name>1</name>
                  <description>LCD segment on or LCD backplane active for phase G</description>
                  <value>#1</value>
                </enumeratedValue>
              </enumeratedValues>
            </field>
            <field>
              <name>BPHLCD28</name>
              <description>no description available</description>
              <bitOffset>7</bitOffset>
              <bitWidth>1</bitWidth>
              <access>read-write</access>
              <enumeratedValues>
                <enumeratedValue>
                  <name>0</name>
                  <description>LCD segment off or LCD backplane inactive for phase H</description>
                  <value>#0</value>
                </enumeratedValue>
                <enumeratedValue>
                  <name>1</name>
                  <description>LCD segment on or LCD backplane active for phase H</description>
                  <value>#1</value>
                </enumeratedValue>
              </enumeratedValues>
            </field>
          </fields>
        </register>
        <register>
          <name>WF29</name>
          <description>LCD Waveform Register 29.</description>
          <addressOffset>0x3D</addressOffset>
          <size>8</size>
          <access>read-write</access>
          <resetValue>0</resetValue>
          <resetMask>0</resetMask>
          <fields>
            <field>
              <name>BPALCD29</name>
              <description>no description available</description>
              <bitOffset>0</bitOffset>
              <bitWidth>1</bitWidth>
              <access>read-write</access>
              <enumeratedValues>
                <enumeratedValue>
                  <name>0</name>
                  <description>LCD segment off or LCD backplane inactive for phase A</description>
                  <value>#0</value>
                </enumeratedValue>
                <enumeratedValue>
                  <name>1</name>
                  <description>LCD segment on or LCD backplane active for phase A</description>
                  <value>#1</value>
                </enumeratedValue>
              </enumeratedValues>
            </field>
            <field>
              <name>BPBLCD29</name>
              <description>no description available</description>
              <bitOffset>1</bitOffset>
              <bitWidth>1</bitWidth>
              <access>read-write</access>
              <enumeratedValues>
                <enumeratedValue>
                  <name>0</name>
                  <description>LCD segment off or LCD backplane inactive for phase B</description>
                  <value>#0</value>
                </enumeratedValue>
                <enumeratedValue>
                  <name>1</name>
                  <description>LCD segment on or LCD backplane active for phase B</description>
                  <value>#1</value>
                </enumeratedValue>
              </enumeratedValues>
            </field>
            <field>
              <name>BPCLCD29</name>
              <description>no description available</description>
              <bitOffset>2</bitOffset>
              <bitWidth>1</bitWidth>
              <access>read-write</access>
              <enumeratedValues>
                <enumeratedValue>
                  <name>0</name>
                  <description>LCD segment off or LCD backplane inactive for phase C</description>
                  <value>#0</value>
                </enumeratedValue>
                <enumeratedValue>
                  <name>1</name>
                  <description>LCD segment on or LCD backplane active for phase C</description>
                  <value>#1</value>
                </enumeratedValue>
              </enumeratedValues>
            </field>
            <field>
              <name>BPDLCD29</name>
              <description>no description available</description>
              <bitOffset>3</bitOffset>
              <bitWidth>1</bitWidth>
              <access>read-write</access>
              <enumeratedValues>
                <enumeratedValue>
                  <name>0</name>
                  <description>LCD segment off or LCD backplane inactive for phase D</description>
                  <value>#0</value>
                </enumeratedValue>
                <enumeratedValue>
                  <name>1</name>
                  <description>LCD segment on or LCD backplane active for phase D</description>
                  <value>#1</value>
                </enumeratedValue>
              </enumeratedValues>
            </field>
            <field>
              <name>BPELCD29</name>
              <description>no description available</description>
              <bitOffset>4</bitOffset>
              <bitWidth>1</bitWidth>
              <access>read-write</access>
              <enumeratedValues>
                <enumeratedValue>
                  <name>0</name>
                  <description>LCD segment off or LCD backplane inactive for phase E</description>
                  <value>#0</value>
                </enumeratedValue>
                <enumeratedValue>
                  <name>1</name>
                  <description>LCD segment on or LCD backplane active for phase E</description>
                  <value>#1</value>
                </enumeratedValue>
              </enumeratedValues>
            </field>
            <field>
              <name>BPFLCD29</name>
              <description>no description available</description>
              <bitOffset>5</bitOffset>
              <bitWidth>1</bitWidth>
              <access>read-write</access>
              <enumeratedValues>
                <enumeratedValue>
                  <name>0</name>
                  <description>LCD segment off or LCD backplane inactive for phase F</description>
                  <value>#0</value>
                </enumeratedValue>
                <enumeratedValue>
                  <name>1</name>
                  <description>LCD segment on or LCD backplane active for phase F</description>
                  <value>#1</value>
                </enumeratedValue>
              </enumeratedValues>
            </field>
            <field>
              <name>BPGLCD29</name>
              <description>no description available</description>
              <bitOffset>6</bitOffset>
              <bitWidth>1</bitWidth>
              <access>read-write</access>
              <enumeratedValues>
                <enumeratedValue>
                  <name>0</name>
                  <description>LCD segment off or LCD backplane inactive for phase G</description>
                  <value>#0</value>
                </enumeratedValue>
                <enumeratedValue>
                  <name>1</name>
                  <description>LCD segment on or LCD backplane active for phase G</description>
                  <value>#1</value>
                </enumeratedValue>
              </enumeratedValues>
            </field>
            <field>
              <name>BPHLCD29</name>
              <description>no description available</description>
              <bitOffset>7</bitOffset>
              <bitWidth>1</bitWidth>
              <access>read-write</access>
              <enumeratedValues>
                <enumeratedValue>
                  <name>0</name>
                  <description>LCD segment off or LCD backplane inactive for phase H</description>
                  <value>#0</value>
                </enumeratedValue>
                <enumeratedValue>
                  <name>1</name>
                  <description>LCD segment on or LCD backplane active for phase H</description>
                  <value>#1</value>
                </enumeratedValue>
              </enumeratedValues>
            </field>
          </fields>
        </register>
        <register>
          <name>WF30</name>
          <description>LCD Waveform Register 30.</description>
          <addressOffset>0x3E</addressOffset>
          <size>8</size>
          <access>read-write</access>
          <resetValue>0</resetValue>
          <resetMask>0</resetMask>
          <fields>
            <field>
              <name>BPALCD30</name>
              <description>no description available</description>
              <bitOffset>0</bitOffset>
              <bitWidth>1</bitWidth>
              <access>read-write</access>
              <enumeratedValues>
                <enumeratedValue>
                  <name>0</name>
                  <description>LCD segment off or LCD backplane inactive for phase A</description>
                  <value>#0</value>
                </enumeratedValue>
                <enumeratedValue>
                  <name>1</name>
                  <description>LCD segment on or LCD backplane active for phase A</description>
                  <value>#1</value>
                </enumeratedValue>
              </enumeratedValues>
            </field>
            <field>
              <name>BPBLCD30</name>
              <description>no description available</description>
              <bitOffset>1</bitOffset>
              <bitWidth>1</bitWidth>
              <access>read-write</access>
              <enumeratedValues>
                <enumeratedValue>
                  <name>0</name>
                  <description>LCD segment off or LCD backplane inactive for phase B</description>
                  <value>#0</value>
                </enumeratedValue>
                <enumeratedValue>
                  <name>1</name>
                  <description>LCD segment on or LCD backplane active for phase B</description>
                  <value>#1</value>
                </enumeratedValue>
              </enumeratedValues>
            </field>
            <field>
              <name>BPCLCD30</name>
              <description>no description available</description>
              <bitOffset>2</bitOffset>
              <bitWidth>1</bitWidth>
              <access>read-write</access>
              <enumeratedValues>
                <enumeratedValue>
                  <name>0</name>
                  <description>LCD segment off or LCD backplane inactive for phase C</description>
                  <value>#0</value>
                </enumeratedValue>
                <enumeratedValue>
                  <name>1</name>
                  <description>LCD segment on or LCD backplane active for phase C</description>
                  <value>#1</value>
                </enumeratedValue>
              </enumeratedValues>
            </field>
            <field>
              <name>BPDLCD30</name>
              <description>no description available</description>
              <bitOffset>3</bitOffset>
              <bitWidth>1</bitWidth>
              <access>read-write</access>
              <enumeratedValues>
                <enumeratedValue>
                  <name>0</name>
                  <description>LCD segment off or LCD backplane inactive for phase D</description>
                  <value>#0</value>
                </enumeratedValue>
                <enumeratedValue>
                  <name>1</name>
                  <description>LCD segment on or LCD backplane active for phase D</description>
                  <value>#1</value>
                </enumeratedValue>
              </enumeratedValues>
            </field>
            <field>
              <name>BPELCD30</name>
              <description>no description available</description>
              <bitOffset>4</bitOffset>
              <bitWidth>1</bitWidth>
              <access>read-write</access>
              <enumeratedValues>
                <enumeratedValue>
                  <name>0</name>
                  <description>LCD segment off or LCD backplane inactive for phase E</description>
                  <value>#0</value>
                </enumeratedValue>
                <enumeratedValue>
                  <name>1</name>
                  <description>LCD segment on or LCD backplane active for phase E</description>
                  <value>#1</value>
                </enumeratedValue>
              </enumeratedValues>
            </field>
            <field>
              <name>BPFLCD30</name>
              <description>no description available</description>
              <bitOffset>5</bitOffset>
              <bitWidth>1</bitWidth>
              <access>read-write</access>
              <enumeratedValues>
                <enumeratedValue>
                  <name>0</name>
                  <description>LCD segment off or LCD backplane inactive for phase F</description>
                  <value>#0</value>
                </enumeratedValue>
                <enumeratedValue>
                  <name>1</name>
                  <description>LCD segment on or LCD backplane active for phase F</description>
                  <value>#1</value>
                </enumeratedValue>
              </enumeratedValues>
            </field>
            <field>
              <name>BPGLCD30</name>
              <description>no description available</description>
              <bitOffset>6</bitOffset>
              <bitWidth>1</bitWidth>
              <access>read-write</access>
              <enumeratedValues>
                <enumeratedValue>
                  <name>0</name>
                  <description>LCD segment off or LCD backplane inactive for phase G</description>
                  <value>#0</value>
                </enumeratedValue>
                <enumeratedValue>
                  <name>1</name>
                  <description>LCD segment on or LCD backplane active for phase G</description>
                  <value>#1</value>
                </enumeratedValue>
              </enumeratedValues>
            </field>
            <field>
              <name>BPHLCD30</name>
              <description>no description available</description>
              <bitOffset>7</bitOffset>
              <bitWidth>1</bitWidth>
              <access>read-write</access>
              <enumeratedValues>
                <enumeratedValue>
                  <name>0</name>
                  <description>LCD segment off or LCD backplane inactive for phase H</description>
                  <value>#0</value>
                </enumeratedValue>
                <enumeratedValue>
                  <name>1</name>
                  <description>LCD segment on or LCD backplane active for phase H</description>
                  <value>#1</value>
                </enumeratedValue>
              </enumeratedValues>
            </field>
          </fields>
        </register>
        <register>
          <name>WF31</name>
          <description>LCD Waveform Register 31.</description>
          <addressOffset>0x3F</addressOffset>
          <size>8</size>
          <access>read-write</access>
          <resetValue>0</resetValue>
          <resetMask>0</resetMask>
          <fields>
            <field>
              <name>BPALCD31</name>
              <description>no description available</description>
              <bitOffset>0</bitOffset>
              <bitWidth>1</bitWidth>
              <access>read-write</access>
              <enumeratedValues>
                <enumeratedValue>
                  <name>0</name>
                  <description>LCD segment off or LCD backplane inactive for phase A</description>
                  <value>#0</value>
                </enumeratedValue>
                <enumeratedValue>
                  <name>1</name>
                  <description>LCD segment on or LCD backplane active for phase A</description>
                  <value>#1</value>
                </enumeratedValue>
              </enumeratedValues>
            </field>
            <field>
              <name>BPBLCD31</name>
              <description>no description available</description>
              <bitOffset>1</bitOffset>
              <bitWidth>1</bitWidth>
              <access>read-write</access>
              <enumeratedValues>
                <enumeratedValue>
                  <name>0</name>
                  <description>LCD segment off or LCD backplane inactive for phase B</description>
                  <value>#0</value>
                </enumeratedValue>
                <enumeratedValue>
                  <name>1</name>
                  <description>LCD segment on or LCD backplane active for phase B</description>
                  <value>#1</value>
                </enumeratedValue>
              </enumeratedValues>
            </field>
            <field>
              <name>BPCLCD31</name>
              <description>no description available</description>
              <bitOffset>2</bitOffset>
              <bitWidth>1</bitWidth>
              <access>read-write</access>
              <enumeratedValues>
                <enumeratedValue>
                  <name>0</name>
                  <description>LCD segment off or LCD backplane inactive for phase C</description>
                  <value>#0</value>
                </enumeratedValue>
                <enumeratedValue>
                  <name>1</name>
                  <description>LCD segment on or LCD backplane active for phase C</description>
                  <value>#1</value>
                </enumeratedValue>
              </enumeratedValues>
            </field>
            <field>
              <name>BPDLCD31</name>
              <description>no description available</description>
              <bitOffset>3</bitOffset>
              <bitWidth>1</bitWidth>
              <access>read-write</access>
              <enumeratedValues>
                <enumeratedValue>
                  <name>0</name>
                  <description>LCD segment off or LCD backplane inactive for phase D</description>
                  <value>#0</value>
                </enumeratedValue>
                <enumeratedValue>
                  <name>1</name>
                  <description>LCD segment on or LCD backplane active for phase D</description>
                  <value>#1</value>
                </enumeratedValue>
              </enumeratedValues>
            </field>
            <field>
              <name>BPELCD31</name>
              <description>no description available</description>
              <bitOffset>4</bitOffset>
              <bitWidth>1</bitWidth>
              <access>read-write</access>
              <enumeratedValues>
                <enumeratedValue>
                  <name>0</name>
                  <description>LCD segment off or LCD backplane inactive for phase E</description>
                  <value>#0</value>
                </enumeratedValue>
                <enumeratedValue>
                  <name>1</name>
                  <description>LCD segment on or LCD backplane active for phase E</description>
                  <value>#1</value>
                </enumeratedValue>
              </enumeratedValues>
            </field>
            <field>
              <name>BPFLCD31</name>
              <description>no description available</description>
              <bitOffset>5</bitOffset>
              <bitWidth>1</bitWidth>
              <access>read-write</access>
              <enumeratedValues>
                <enumeratedValue>
                  <name>0</name>
                  <description>LCD segment off or LCD backplane inactive for phase F</description>
                  <value>#0</value>
                </enumeratedValue>
                <enumeratedValue>
                  <name>1</name>
                  <description>LCD segment on or LCD backplane active for phase F</description>
                  <value>#1</value>
                </enumeratedValue>
              </enumeratedValues>
            </field>
            <field>
              <name>BPGLCD31</name>
              <description>no description available</description>
              <bitOffset>6</bitOffset>
              <bitWidth>1</bitWidth>
              <access>read-write</access>
              <enumeratedValues>
                <enumeratedValue>
                  <name>0</name>
                  <description>LCD segment off or LCD backplane inactive for phase G</description>
                  <value>#0</value>
                </enumeratedValue>
                <enumeratedValue>
                  <name>1</name>
                  <description>LCD segment on or LCD backplane active for phase G</description>
                  <value>#1</value>
                </enumeratedValue>
              </enumeratedValues>
            </field>
            <field>
              <name>BPHLCD31</name>
              <description>no description available</description>
              <bitOffset>7</bitOffset>
              <bitWidth>1</bitWidth>
              <access>read-write</access>
              <enumeratedValues>
                <enumeratedValue>
                  <name>0</name>
                  <description>LCD segment off or LCD backplane inactive for phase H</description>
                  <value>#0</value>
                </enumeratedValue>
                <enumeratedValue>
                  <name>1</name>
                  <description>LCD segment on or LCD backplane active for phase H</description>
                  <value>#1</value>
                </enumeratedValue>
              </enumeratedValues>
            </field>
          </fields>
        </register>
        <register>
          <name>WF35TO32</name>
          <description>LCD Waveform register</description>
          <alternateGroup>LCD</alternateGroup>
          <addressOffset>0x40</addressOffset>
          <size>32</size>
          <access>read-write</access>
          <resetValue>0</resetValue>
          <resetMask>0xFFFFFFFF</resetMask>
          <fields>
            <field>
              <name>WF32</name>
              <description>Controls segments or phases connected to LCD_P32 as described above for WF3TO0[WF3].</description>
              <bitOffset>0</bitOffset>
              <bitWidth>8</bitWidth>
              <access>read-write</access>
            </field>
            <field>
              <name>WF33</name>
              <description>Controls segments or phases connected to LCD_P33 as described above for WF3TO0[WF3].</description>
              <bitOffset>8</bitOffset>
              <bitWidth>8</bitWidth>
              <access>read-write</access>
            </field>
            <field>
              <name>WF34</name>
              <description>Controls segments or phases connected to LCD_P34 as described above for WF3TO0[WF3].</description>
              <bitOffset>16</bitOffset>
              <bitWidth>8</bitWidth>
              <access>read-write</access>
            </field>
            <field>
              <name>WF35</name>
              <description>Controls segments or phases connected to LCD_P35 as described above for WF3TO0[WF3].</description>
              <bitOffset>24</bitOffset>
              <bitWidth>8</bitWidth>
              <access>read-write</access>
            </field>
          </fields>
        </register>
        <register>
          <name>WF32</name>
          <description>LCD Waveform Register 32.</description>
          <alternateGroup>LCD</alternateGroup>
          <addressOffset>0x40</addressOffset>
          <size>8</size>
          <access>read-write</access>
          <resetValue>0</resetValue>
          <resetMask>0</resetMask>
          <fields>
            <field>
              <name>BPALCD32</name>
              <description>no description available</description>
              <bitOffset>0</bitOffset>
              <bitWidth>1</bitWidth>
              <access>read-write</access>
              <enumeratedValues>
                <enumeratedValue>
                  <name>0</name>
                  <description>LCD segment off or LCD backplane inactive for phase A</description>
                  <value>#0</value>
                </enumeratedValue>
                <enumeratedValue>
                  <name>1</name>
                  <description>LCD segment on or LCD backplane active for phase A</description>
                  <value>#1</value>
                </enumeratedValue>
              </enumeratedValues>
            </field>
            <field>
              <name>BPBLCD32</name>
              <description>no description available</description>
              <bitOffset>1</bitOffset>
              <bitWidth>1</bitWidth>
              <access>read-write</access>
              <enumeratedValues>
                <enumeratedValue>
                  <name>0</name>
                  <description>LCD segment off or LCD backplane inactive for phase B</description>
                  <value>#0</value>
                </enumeratedValue>
                <enumeratedValue>
                  <name>1</name>
                  <description>LCD segment on or LCD backplane active for phase B</description>
                  <value>#1</value>
                </enumeratedValue>
              </enumeratedValues>
            </field>
            <field>
              <name>BPCLCD32</name>
              <description>no description available</description>
              <bitOffset>2</bitOffset>
              <bitWidth>1</bitWidth>
              <access>read-write</access>
              <enumeratedValues>
                <enumeratedValue>
                  <name>0</name>
                  <description>LCD segment off or LCD backplane inactive for phase C</description>
                  <value>#0</value>
                </enumeratedValue>
                <enumeratedValue>
                  <name>1</name>
                  <description>LCD segment on or LCD backplane active for phase C</description>
                  <value>#1</value>
                </enumeratedValue>
              </enumeratedValues>
            </field>
            <field>
              <name>BPDLCD32</name>
              <description>no description available</description>
              <bitOffset>3</bitOffset>
              <bitWidth>1</bitWidth>
              <access>read-write</access>
              <enumeratedValues>
                <enumeratedValue>
                  <name>0</name>
                  <description>LCD segment off or LCD backplane inactive for phase D</description>
                  <value>#0</value>
                </enumeratedValue>
                <enumeratedValue>
                  <name>1</name>
                  <description>LCD segment on or LCD backplane active for phase D</description>
                  <value>#1</value>
                </enumeratedValue>
              </enumeratedValues>
            </field>
            <field>
              <name>BPELCD32</name>
              <description>no description available</description>
              <bitOffset>4</bitOffset>
              <bitWidth>1</bitWidth>
              <access>read-write</access>
              <enumeratedValues>
                <enumeratedValue>
                  <name>0</name>
                  <description>LCD segment off or LCD backplane inactive for phase E</description>
                  <value>#0</value>
                </enumeratedValue>
                <enumeratedValue>
                  <name>1</name>
                  <description>LCD segment on or LCD backplane active for phase E</description>
                  <value>#1</value>
                </enumeratedValue>
              </enumeratedValues>
            </field>
            <field>
              <name>BPFLCD32</name>
              <description>no description available</description>
              <bitOffset>5</bitOffset>
              <bitWidth>1</bitWidth>
              <access>read-write</access>
              <enumeratedValues>
                <enumeratedValue>
                  <name>0</name>
                  <description>LCD segment off or LCD backplane inactive for phase F</description>
                  <value>#0</value>
                </enumeratedValue>
                <enumeratedValue>
                  <name>1</name>
                  <description>LCD segment on or LCD backplane active for phase F</description>
                  <value>#1</value>
                </enumeratedValue>
              </enumeratedValues>
            </field>
            <field>
              <name>BPGLCD32</name>
              <description>no description available</description>
              <bitOffset>6</bitOffset>
              <bitWidth>1</bitWidth>
              <access>read-write</access>
              <enumeratedValues>
                <enumeratedValue>
                  <name>0</name>
                  <description>LCD segment off or LCD backplane inactive for phase G</description>
                  <value>#0</value>
                </enumeratedValue>
                <enumeratedValue>
                  <name>1</name>
                  <description>LCD segment on or LCD backplane active for phase G</description>
                  <value>#1</value>
                </enumeratedValue>
              </enumeratedValues>
            </field>
            <field>
              <name>BPHLCD32</name>
              <description>no description available</description>
              <bitOffset>7</bitOffset>
              <bitWidth>1</bitWidth>
              <access>read-write</access>
              <enumeratedValues>
                <enumeratedValue>
                  <name>0</name>
                  <description>LCD segment off or LCD backplane inactive for phase H</description>
                  <value>#0</value>
                </enumeratedValue>
                <enumeratedValue>
                  <name>1</name>
                  <description>LCD segment on or LCD backplane active for phase H</description>
                  <value>#1</value>
                </enumeratedValue>
              </enumeratedValues>
            </field>
          </fields>
        </register>
        <register>
          <name>WF33</name>
          <description>LCD Waveform Register 33.</description>
          <addressOffset>0x41</addressOffset>
          <size>8</size>
          <access>read-write</access>
          <resetValue>0</resetValue>
          <resetMask>0</resetMask>
          <fields>
            <field>
              <name>BPALCD33</name>
              <description>no description available</description>
              <bitOffset>0</bitOffset>
              <bitWidth>1</bitWidth>
              <access>read-write</access>
              <enumeratedValues>
                <enumeratedValue>
                  <name>0</name>
                  <description>LCD segment off or LCD backplane inactive for phase A</description>
                  <value>#0</value>
                </enumeratedValue>
                <enumeratedValue>
                  <name>1</name>
                  <description>LCD segment on or LCD backplane active for phase A</description>
                  <value>#1</value>
                </enumeratedValue>
              </enumeratedValues>
            </field>
            <field>
              <name>BPBLCD33</name>
              <description>no description available</description>
              <bitOffset>1</bitOffset>
              <bitWidth>1</bitWidth>
              <access>read-write</access>
              <enumeratedValues>
                <enumeratedValue>
                  <name>0</name>
                  <description>LCD segment off or LCD backplane inactive for phase B</description>
                  <value>#0</value>
                </enumeratedValue>
                <enumeratedValue>
                  <name>1</name>
                  <description>LCD segment on or LCD backplane active for phase B</description>
                  <value>#1</value>
                </enumeratedValue>
              </enumeratedValues>
            </field>
            <field>
              <name>BPCLCD33</name>
              <description>no description available</description>
              <bitOffset>2</bitOffset>
              <bitWidth>1</bitWidth>
              <access>read-write</access>
              <enumeratedValues>
                <enumeratedValue>
                  <name>0</name>
                  <description>LCD segment off or LCD backplane inactive for phase C</description>
                  <value>#0</value>
                </enumeratedValue>
                <enumeratedValue>
                  <name>1</name>
                  <description>LCD segment on or LCD backplane active for phase C</description>
                  <value>#1</value>
                </enumeratedValue>
              </enumeratedValues>
            </field>
            <field>
              <name>BPDLCD33</name>
              <description>no description available</description>
              <bitOffset>3</bitOffset>
              <bitWidth>1</bitWidth>
              <access>read-write</access>
              <enumeratedValues>
                <enumeratedValue>
                  <name>0</name>
                  <description>LCD segment off or LCD backplane inactive for phase D</description>
                  <value>#0</value>
                </enumeratedValue>
                <enumeratedValue>
                  <name>1</name>
                  <description>LCD segment on or LCD backplane active for phase D</description>
                  <value>#1</value>
                </enumeratedValue>
              </enumeratedValues>
            </field>
            <field>
              <name>BPELCD33</name>
              <description>no description available</description>
              <bitOffset>4</bitOffset>
              <bitWidth>1</bitWidth>
              <access>read-write</access>
              <enumeratedValues>
                <enumeratedValue>
                  <name>0</name>
                  <description>LCD segment off or LCD backplane inactive for phase E</description>
                  <value>#0</value>
                </enumeratedValue>
                <enumeratedValue>
                  <name>1</name>
                  <description>LCD segment on or LCD backplane active for phase E</description>
                  <value>#1</value>
                </enumeratedValue>
              </enumeratedValues>
            </field>
            <field>
              <name>BPFLCD33</name>
              <description>no description available</description>
              <bitOffset>5</bitOffset>
              <bitWidth>1</bitWidth>
              <access>read-write</access>
              <enumeratedValues>
                <enumeratedValue>
                  <name>0</name>
                  <description>LCD segment off or LCD backplane inactive for phase F</description>
                  <value>#0</value>
                </enumeratedValue>
                <enumeratedValue>
                  <name>1</name>
                  <description>LCD segment on or LCD backplane active for phase F</description>
                  <value>#1</value>
                </enumeratedValue>
              </enumeratedValues>
            </field>
            <field>
              <name>BPGLCD33</name>
              <description>no description available</description>
              <bitOffset>6</bitOffset>
              <bitWidth>1</bitWidth>
              <access>read-write</access>
              <enumeratedValues>
                <enumeratedValue>
                  <name>0</name>
                  <description>LCD segment off or LCD backplane inactive for phase G</description>
                  <value>#0</value>
                </enumeratedValue>
                <enumeratedValue>
                  <name>1</name>
                  <description>LCD segment on or LCD backplane active for phase G</description>
                  <value>#1</value>
                </enumeratedValue>
              </enumeratedValues>
            </field>
            <field>
              <name>BPHLCD33</name>
              <description>no description available</description>
              <bitOffset>7</bitOffset>
              <bitWidth>1</bitWidth>
              <access>read-write</access>
              <enumeratedValues>
                <enumeratedValue>
                  <name>0</name>
                  <description>LCD segment off or LCD backplane inactive for phase H</description>
                  <value>#0</value>
                </enumeratedValue>
                <enumeratedValue>
                  <name>1</name>
                  <description>LCD segment on or LCD backplane active for phase H</description>
                  <value>#1</value>
                </enumeratedValue>
              </enumeratedValues>
            </field>
          </fields>
        </register>
        <register>
          <name>WF34</name>
          <description>LCD Waveform Register 34.</description>
          <addressOffset>0x42</addressOffset>
          <size>8</size>
          <access>read-write</access>
          <resetValue>0</resetValue>
          <resetMask>0</resetMask>
          <fields>
            <field>
              <name>BPALCD34</name>
              <description>no description available</description>
              <bitOffset>0</bitOffset>
              <bitWidth>1</bitWidth>
              <access>read-write</access>
              <enumeratedValues>
                <enumeratedValue>
                  <name>0</name>
                  <description>LCD segment off or LCD backplane inactive for phase A</description>
                  <value>#0</value>
                </enumeratedValue>
                <enumeratedValue>
                  <name>1</name>
                  <description>LCD segment on or LCD backplane active for phase A</description>
                  <value>#1</value>
                </enumeratedValue>
              </enumeratedValues>
            </field>
            <field>
              <name>BPBLCD34</name>
              <description>no description available</description>
              <bitOffset>1</bitOffset>
              <bitWidth>1</bitWidth>
              <access>read-write</access>
              <enumeratedValues>
                <enumeratedValue>
                  <name>0</name>
                  <description>LCD segment off or LCD backplane inactive for phase B</description>
                  <value>#0</value>
                </enumeratedValue>
                <enumeratedValue>
                  <name>1</name>
                  <description>LCD segment on or LCD backplane active for phase B</description>
                  <value>#1</value>
                </enumeratedValue>
              </enumeratedValues>
            </field>
            <field>
              <name>BPCLCD34</name>
              <description>no description available</description>
              <bitOffset>2</bitOffset>
              <bitWidth>1</bitWidth>
              <access>read-write</access>
              <enumeratedValues>
                <enumeratedValue>
                  <name>0</name>
                  <description>LCD segment off or LCD backplane inactive for phase C</description>
                  <value>#0</value>
                </enumeratedValue>
                <enumeratedValue>
                  <name>1</name>
                  <description>LCD segment on or LCD backplane active for phase C</description>
                  <value>#1</value>
                </enumeratedValue>
              </enumeratedValues>
            </field>
            <field>
              <name>BPDLCD34</name>
              <description>no description available</description>
              <bitOffset>3</bitOffset>
              <bitWidth>1</bitWidth>
              <access>read-write</access>
              <enumeratedValues>
                <enumeratedValue>
                  <name>0</name>
                  <description>LCD segment off or LCD backplane inactive for phase D</description>
                  <value>#0</value>
                </enumeratedValue>
                <enumeratedValue>
                  <name>1</name>
                  <description>LCD segment on or LCD backplane active for phase D</description>
                  <value>#1</value>
                </enumeratedValue>
              </enumeratedValues>
            </field>
            <field>
              <name>BPELCD34</name>
              <description>no description available</description>
              <bitOffset>4</bitOffset>
              <bitWidth>1</bitWidth>
              <access>read-write</access>
              <enumeratedValues>
                <enumeratedValue>
                  <name>0</name>
                  <description>LCD segment off or LCD backplane inactive for phase E</description>
                  <value>#0</value>
                </enumeratedValue>
                <enumeratedValue>
                  <name>1</name>
                  <description>LCD segment on or LCD backplane active for phase E</description>
                  <value>#1</value>
                </enumeratedValue>
              </enumeratedValues>
            </field>
            <field>
              <name>BPFLCD34</name>
              <description>no description available</description>
              <bitOffset>5</bitOffset>
              <bitWidth>1</bitWidth>
              <access>read-write</access>
              <enumeratedValues>
                <enumeratedValue>
                  <name>0</name>
                  <description>LCD segment off or LCD backplane inactive for phase F</description>
                  <value>#0</value>
                </enumeratedValue>
                <enumeratedValue>
                  <name>1</name>
                  <description>LCD segment on or LCD backplane active for phase F</description>
                  <value>#1</value>
                </enumeratedValue>
              </enumeratedValues>
            </field>
            <field>
              <name>BPGLCD34</name>
              <description>no description available</description>
              <bitOffset>6</bitOffset>
              <bitWidth>1</bitWidth>
              <access>read-write</access>
              <enumeratedValues>
                <enumeratedValue>
                  <name>0</name>
                  <description>LCD segment off or LCD backplane inactive for phase G</description>
                  <value>#0</value>
                </enumeratedValue>
                <enumeratedValue>
                  <name>1</name>
                  <description>LCD segment on or LCD backplane active for phase G</description>
                  <value>#1</value>
                </enumeratedValue>
              </enumeratedValues>
            </field>
            <field>
              <name>BPHLCD34</name>
              <description>no description available</description>
              <bitOffset>7</bitOffset>
              <bitWidth>1</bitWidth>
              <access>read-write</access>
              <enumeratedValues>
                <enumeratedValue>
                  <name>0</name>
                  <description>LCD segment off or LCD backplane inactive for phase H</description>
                  <value>#0</value>
                </enumeratedValue>
                <enumeratedValue>
                  <name>1</name>
                  <description>LCD segment on or LCD backplane active for phase H</description>
                  <value>#1</value>
                </enumeratedValue>
              </enumeratedValues>
            </field>
          </fields>
        </register>
        <register>
          <name>WF35</name>
          <description>LCD Waveform Register 35.</description>
          <addressOffset>0x43</addressOffset>
          <size>8</size>
          <access>read-write</access>
          <resetValue>0</resetValue>
          <resetMask>0</resetMask>
          <fields>
            <field>
              <name>BPALCD35</name>
              <description>no description available</description>
              <bitOffset>0</bitOffset>
              <bitWidth>1</bitWidth>
              <access>read-write</access>
              <enumeratedValues>
                <enumeratedValue>
                  <name>0</name>
                  <description>LCD segment off or LCD backplane inactive for phase A</description>
                  <value>#0</value>
                </enumeratedValue>
                <enumeratedValue>
                  <name>1</name>
                  <description>LCD segment on or LCD backplane active for phase A</description>
                  <value>#1</value>
                </enumeratedValue>
              </enumeratedValues>
            </field>
            <field>
              <name>BPBLCD35</name>
              <description>no description available</description>
              <bitOffset>1</bitOffset>
              <bitWidth>1</bitWidth>
              <access>read-write</access>
              <enumeratedValues>
                <enumeratedValue>
                  <name>0</name>
                  <description>LCD segment off or LCD backplane inactive for phase B</description>
                  <value>#0</value>
                </enumeratedValue>
                <enumeratedValue>
                  <name>1</name>
                  <description>LCD segment on or LCD backplane active for phase B</description>
                  <value>#1</value>
                </enumeratedValue>
              </enumeratedValues>
            </field>
            <field>
              <name>BPCLCD35</name>
              <description>no description available</description>
              <bitOffset>2</bitOffset>
              <bitWidth>1</bitWidth>
              <access>read-write</access>
              <enumeratedValues>
                <enumeratedValue>
                  <name>0</name>
                  <description>LCD segment off or LCD backplane inactive for phase C</description>
                  <value>#0</value>
                </enumeratedValue>
                <enumeratedValue>
                  <name>1</name>
                  <description>LCD segment on or LCD backplane active for phase C</description>
                  <value>#1</value>
                </enumeratedValue>
              </enumeratedValues>
            </field>
            <field>
              <name>BPDLCD35</name>
              <description>no description available</description>
              <bitOffset>3</bitOffset>
              <bitWidth>1</bitWidth>
              <access>read-write</access>
              <enumeratedValues>
                <enumeratedValue>
                  <name>0</name>
                  <description>LCD segment off or LCD backplane inactive for phase D</description>
                  <value>#0</value>
                </enumeratedValue>
                <enumeratedValue>
                  <name>1</name>
                  <description>LCD segment on or LCD backplane active for phase D</description>
                  <value>#1</value>
                </enumeratedValue>
              </enumeratedValues>
            </field>
            <field>
              <name>BPELCD35</name>
              <description>no description available</description>
              <bitOffset>4</bitOffset>
              <bitWidth>1</bitWidth>
              <access>read-write</access>
              <enumeratedValues>
                <enumeratedValue>
                  <name>0</name>
                  <description>LCD segment off or LCD backplane inactive for phase E</description>
                  <value>#0</value>
                </enumeratedValue>
                <enumeratedValue>
                  <name>1</name>
                  <description>LCD segment on or LCD backplane active for phase E</description>
                  <value>#1</value>
                </enumeratedValue>
              </enumeratedValues>
            </field>
            <field>
              <name>BPFLCD35</name>
              <description>no description available</description>
              <bitOffset>5</bitOffset>
              <bitWidth>1</bitWidth>
              <access>read-write</access>
              <enumeratedValues>
                <enumeratedValue>
                  <name>0</name>
                  <description>LCD segment off or LCD backplane inactive for phase F</description>
                  <value>#0</value>
                </enumeratedValue>
                <enumeratedValue>
                  <name>1</name>
                  <description>LCD segment on or LCD backplane active for phase F</description>
                  <value>#1</value>
                </enumeratedValue>
              </enumeratedValues>
            </field>
            <field>
              <name>BPGLCD35</name>
              <description>no description available</description>
              <bitOffset>6</bitOffset>
              <bitWidth>1</bitWidth>
              <access>read-write</access>
              <enumeratedValues>
                <enumeratedValue>
                  <name>0</name>
                  <description>LCD segment off or LCD backplane inactive for phase G</description>
                  <value>#0</value>
                </enumeratedValue>
                <enumeratedValue>
                  <name>1</name>
                  <description>LCD segment on or LCD backplane active for phase G</description>
                  <value>#1</value>
                </enumeratedValue>
              </enumeratedValues>
            </field>
            <field>
              <name>BPHLCD35</name>
              <description>no description available</description>
              <bitOffset>7</bitOffset>
              <bitWidth>1</bitWidth>
              <access>read-write</access>
              <enumeratedValues>
                <enumeratedValue>
                  <name>0</name>
                  <description>LCD segment off or LCD backplane inactive for phase H</description>
                  <value>#0</value>
                </enumeratedValue>
                <enumeratedValue>
                  <name>1</name>
                  <description>LCD segment on or LCD backplane active for phase H</description>
                  <value>#1</value>
                </enumeratedValue>
              </enumeratedValues>
            </field>
          </fields>
        </register>
        <register>
          <name>WF39TO36</name>
          <description>LCD Waveform register</description>
          <alternateGroup>LCD</alternateGroup>
          <addressOffset>0x44</addressOffset>
          <size>32</size>
          <access>read-write</access>
          <resetValue>0</resetValue>
          <resetMask>0xFFFFFFFF</resetMask>
          <fields>
            <field>
              <name>WF36</name>
              <description>Controls segments or phases connected to LCD_P36 as described above for WF3TO0[WF3].</description>
              <bitOffset>0</bitOffset>
              <bitWidth>8</bitWidth>
              <access>read-write</access>
            </field>
            <field>
              <name>WF37</name>
              <description>Controls segments or phases connected to LCD_P37 as described above for WF3TO0[WF3].</description>
              <bitOffset>8</bitOffset>
              <bitWidth>8</bitWidth>
              <access>read-write</access>
            </field>
            <field>
              <name>WF38</name>
              <description>Controls segments or phases connected to LCD_P38 as described above for WF3TO0[WF3].</description>
              <bitOffset>16</bitOffset>
              <bitWidth>8</bitWidth>
              <access>read-write</access>
            </field>
            <field>
              <name>WF39</name>
              <description>Controls segments or phases connected to LCD_P39 as described above for WF3TO0[WF3].</description>
              <bitOffset>24</bitOffset>
              <bitWidth>8</bitWidth>
              <access>read-write</access>
            </field>
          </fields>
        </register>
        <register>
          <name>WF36</name>
          <description>LCD Waveform Register 36.</description>
          <alternateGroup>LCD</alternateGroup>
          <addressOffset>0x44</addressOffset>
          <size>8</size>
          <access>read-write</access>
          <resetValue>0</resetValue>
          <resetMask>0</resetMask>
          <fields>
            <field>
              <name>BPALCD36</name>
              <description>no description available</description>
              <bitOffset>0</bitOffset>
              <bitWidth>1</bitWidth>
              <access>read-write</access>
              <enumeratedValues>
                <enumeratedValue>
                  <name>0</name>
                  <description>LCD segment off or LCD backplane inactive for phase A</description>
                  <value>#0</value>
                </enumeratedValue>
                <enumeratedValue>
                  <name>1</name>
                  <description>LCD segment on or LCD backplane active for phase A</description>
                  <value>#1</value>
                </enumeratedValue>
              </enumeratedValues>
            </field>
            <field>
              <name>BPBLCD36</name>
              <description>no description available</description>
              <bitOffset>1</bitOffset>
              <bitWidth>1</bitWidth>
              <access>read-write</access>
              <enumeratedValues>
                <enumeratedValue>
                  <name>0</name>
                  <description>LCD segment off or LCD backplane inactive for phase B</description>
                  <value>#0</value>
                </enumeratedValue>
                <enumeratedValue>
                  <name>1</name>
                  <description>LCD segment on or LCD backplane active for phase B</description>
                  <value>#1</value>
                </enumeratedValue>
              </enumeratedValues>
            </field>
            <field>
              <name>BPCLCD36</name>
              <description>no description available</description>
              <bitOffset>2</bitOffset>
              <bitWidth>1</bitWidth>
              <access>read-write</access>
              <enumeratedValues>
                <enumeratedValue>
                  <name>0</name>
                  <description>LCD segment off or LCD backplane inactive for phase C</description>
                  <value>#0</value>
                </enumeratedValue>
                <enumeratedValue>
                  <name>1</name>
                  <description>LCD segment on or LCD backplane active for phase C</description>
                  <value>#1</value>
                </enumeratedValue>
              </enumeratedValues>
            </field>
            <field>
              <name>BPDLCD36</name>
              <description>no description available</description>
              <bitOffset>3</bitOffset>
              <bitWidth>1</bitWidth>
              <access>read-write</access>
              <enumeratedValues>
                <enumeratedValue>
                  <name>0</name>
                  <description>LCD segment off or LCD backplane inactive for phase D</description>
                  <value>#0</value>
                </enumeratedValue>
                <enumeratedValue>
                  <name>1</name>
                  <description>LCD segment on or LCD backplane active for phase D</description>
                  <value>#1</value>
                </enumeratedValue>
              </enumeratedValues>
            </field>
            <field>
              <name>BPELCD36</name>
              <description>no description available</description>
              <bitOffset>4</bitOffset>
              <bitWidth>1</bitWidth>
              <access>read-write</access>
              <enumeratedValues>
                <enumeratedValue>
                  <name>0</name>
                  <description>LCD segment off or LCD backplane inactive for phase E</description>
                  <value>#0</value>
                </enumeratedValue>
                <enumeratedValue>
                  <name>1</name>
                  <description>LCD segment on or LCD backplane active for phase E</description>
                  <value>#1</value>
                </enumeratedValue>
              </enumeratedValues>
            </field>
            <field>
              <name>BPFLCD36</name>
              <description>no description available</description>
              <bitOffset>5</bitOffset>
              <bitWidth>1</bitWidth>
              <access>read-write</access>
              <enumeratedValues>
                <enumeratedValue>
                  <name>0</name>
                  <description>LCD segment off or LCD backplane inactive for phase F</description>
                  <value>#0</value>
                </enumeratedValue>
                <enumeratedValue>
                  <name>1</name>
                  <description>LCD segment on or LCD backplane active for phase F</description>
                  <value>#1</value>
                </enumeratedValue>
              </enumeratedValues>
            </field>
            <field>
              <name>BPGLCD36</name>
              <description>no description available</description>
              <bitOffset>6</bitOffset>
              <bitWidth>1</bitWidth>
              <access>read-write</access>
              <enumeratedValues>
                <enumeratedValue>
                  <name>0</name>
                  <description>LCD segment off or LCD backplane inactive for phase G</description>
                  <value>#0</value>
                </enumeratedValue>
                <enumeratedValue>
                  <name>1</name>
                  <description>LCD segment on or LCD backplane active for phase G</description>
                  <value>#1</value>
                </enumeratedValue>
              </enumeratedValues>
            </field>
            <field>
              <name>BPHLCD36</name>
              <description>no description available</description>
              <bitOffset>7</bitOffset>
              <bitWidth>1</bitWidth>
              <access>read-write</access>
              <enumeratedValues>
                <enumeratedValue>
                  <name>0</name>
                  <description>LCD segment off or LCD backplane inactive for phase H</description>
                  <value>#0</value>
                </enumeratedValue>
                <enumeratedValue>
                  <name>1</name>
                  <description>LCD segment on or LCD backplane active for phase H</description>
                  <value>#1</value>
                </enumeratedValue>
              </enumeratedValues>
            </field>
          </fields>
        </register>
        <register>
          <name>WF37</name>
          <description>LCD Waveform Register 37.</description>
          <addressOffset>0x45</addressOffset>
          <size>8</size>
          <access>read-write</access>
          <resetValue>0</resetValue>
          <resetMask>0</resetMask>
          <fields>
            <field>
              <name>BPALCD37</name>
              <description>no description available</description>
              <bitOffset>0</bitOffset>
              <bitWidth>1</bitWidth>
              <access>read-write</access>
              <enumeratedValues>
                <enumeratedValue>
                  <name>0</name>
                  <description>LCD segment off or LCD backplane inactive for phase A</description>
                  <value>#0</value>
                </enumeratedValue>
                <enumeratedValue>
                  <name>1</name>
                  <description>LCD segment on or LCD backplane active for phase A</description>
                  <value>#1</value>
                </enumeratedValue>
              </enumeratedValues>
            </field>
            <field>
              <name>BPBLCD37</name>
              <description>no description available</description>
              <bitOffset>1</bitOffset>
              <bitWidth>1</bitWidth>
              <access>read-write</access>
              <enumeratedValues>
                <enumeratedValue>
                  <name>0</name>
                  <description>LCD segment off or LCD backplane inactive for phase B</description>
                  <value>#0</value>
                </enumeratedValue>
                <enumeratedValue>
                  <name>1</name>
                  <description>LCD segment on or LCD backplane active for phase B</description>
                  <value>#1</value>
                </enumeratedValue>
              </enumeratedValues>
            </field>
            <field>
              <name>BPCLCD37</name>
              <description>no description available</description>
              <bitOffset>2</bitOffset>
              <bitWidth>1</bitWidth>
              <access>read-write</access>
              <enumeratedValues>
                <enumeratedValue>
                  <name>0</name>
                  <description>LCD segment off or LCD backplane inactive for phase C</description>
                  <value>#0</value>
                </enumeratedValue>
                <enumeratedValue>
                  <name>1</name>
                  <description>LCD segment on or LCD backplane active for phase C</description>
                  <value>#1</value>
                </enumeratedValue>
              </enumeratedValues>
            </field>
            <field>
              <name>BPDLCD37</name>
              <description>no description available</description>
              <bitOffset>3</bitOffset>
              <bitWidth>1</bitWidth>
              <access>read-write</access>
              <enumeratedValues>
                <enumeratedValue>
                  <name>0</name>
                  <description>LCD segment off or LCD backplane inactive for phase D</description>
                  <value>#0</value>
                </enumeratedValue>
                <enumeratedValue>
                  <name>1</name>
                  <description>LCD segment on or LCD backplane active for phase D</description>
                  <value>#1</value>
                </enumeratedValue>
              </enumeratedValues>
            </field>
            <field>
              <name>BPELCD37</name>
              <description>no description available</description>
              <bitOffset>4</bitOffset>
              <bitWidth>1</bitWidth>
              <access>read-write</access>
              <enumeratedValues>
                <enumeratedValue>
                  <name>0</name>
                  <description>LCD segment off or LCD backplane inactive for phase E</description>
                  <value>#0</value>
                </enumeratedValue>
                <enumeratedValue>
                  <name>1</name>
                  <description>LCD segment on or LCD backplane active for phase E</description>
                  <value>#1</value>
                </enumeratedValue>
              </enumeratedValues>
            </field>
            <field>
              <name>BPFLCD37</name>
              <description>no description available</description>
              <bitOffset>5</bitOffset>
              <bitWidth>1</bitWidth>
              <access>read-write</access>
              <enumeratedValues>
                <enumeratedValue>
                  <name>0</name>
                  <description>LCD segment off or LCD backplane inactive for phase F</description>
                  <value>#0</value>
                </enumeratedValue>
                <enumeratedValue>
                  <name>1</name>
                  <description>LCD segment on or LCD backplane active for phase F</description>
                  <value>#1</value>
                </enumeratedValue>
              </enumeratedValues>
            </field>
            <field>
              <name>BPGLCD37</name>
              <description>no description available</description>
              <bitOffset>6</bitOffset>
              <bitWidth>1</bitWidth>
              <access>read-write</access>
              <enumeratedValues>
                <enumeratedValue>
                  <name>0</name>
                  <description>LCD segment off or LCD backplane inactive for phase G</description>
                  <value>#0</value>
                </enumeratedValue>
                <enumeratedValue>
                  <name>1</name>
                  <description>LCD segment on or LCD backplane active for phase G</description>
                  <value>#1</value>
                </enumeratedValue>
              </enumeratedValues>
            </field>
            <field>
              <name>BPHLCD37</name>
              <description>no description available</description>
              <bitOffset>7</bitOffset>
              <bitWidth>1</bitWidth>
              <access>read-write</access>
              <enumeratedValues>
                <enumeratedValue>
                  <name>0</name>
                  <description>LCD segment off or LCD backplane inactive for phase H</description>
                  <value>#0</value>
                </enumeratedValue>
                <enumeratedValue>
                  <name>1</name>
                  <description>LCD segment on or LCD backplane active for phase H</description>
                  <value>#1</value>
                </enumeratedValue>
              </enumeratedValues>
            </field>
          </fields>
        </register>
        <register>
          <name>WF38</name>
          <description>LCD Waveform Register 38.</description>
          <addressOffset>0x46</addressOffset>
          <size>8</size>
          <access>read-write</access>
          <resetValue>0</resetValue>
          <resetMask>0</resetMask>
          <fields>
            <field>
              <name>BPALCD38</name>
              <description>no description available</description>
              <bitOffset>0</bitOffset>
              <bitWidth>1</bitWidth>
              <access>read-write</access>
              <enumeratedValues>
                <enumeratedValue>
                  <name>0</name>
                  <description>LCD segment off or LCD backplane inactive for phase A</description>
                  <value>#0</value>
                </enumeratedValue>
                <enumeratedValue>
                  <name>1</name>
                  <description>LCD segment on or LCD backplane active for phase A</description>
                  <value>#1</value>
                </enumeratedValue>
              </enumeratedValues>
            </field>
            <field>
              <name>BPBLCD38</name>
              <description>no description available</description>
              <bitOffset>1</bitOffset>
              <bitWidth>1</bitWidth>
              <access>read-write</access>
              <enumeratedValues>
                <enumeratedValue>
                  <name>0</name>
                  <description>LCD segment off or LCD backplane inactive for phase B</description>
                  <value>#0</value>
                </enumeratedValue>
                <enumeratedValue>
                  <name>1</name>
                  <description>LCD segment on or LCD backplane active for phase B</description>
                  <value>#1</value>
                </enumeratedValue>
              </enumeratedValues>
            </field>
            <field>
              <name>BPCLCD38</name>
              <description>no description available</description>
              <bitOffset>2</bitOffset>
              <bitWidth>1</bitWidth>
              <access>read-write</access>
              <enumeratedValues>
                <enumeratedValue>
                  <name>0</name>
                  <description>LCD segment off or LCD backplane inactive for phase C</description>
                  <value>#0</value>
                </enumeratedValue>
                <enumeratedValue>
                  <name>1</name>
                  <description>LCD segment on or LCD backplane active for phase C</description>
                  <value>#1</value>
                </enumeratedValue>
              </enumeratedValues>
            </field>
            <field>
              <name>BPDLCD38</name>
              <description>no description available</description>
              <bitOffset>3</bitOffset>
              <bitWidth>1</bitWidth>
              <access>read-write</access>
              <enumeratedValues>
                <enumeratedValue>
                  <name>0</name>
                  <description>LCD segment off or LCD backplane inactive for phase D</description>
                  <value>#0</value>
                </enumeratedValue>
                <enumeratedValue>
                  <name>1</name>
                  <description>LCD segment on or LCD backplane active for phase D</description>
                  <value>#1</value>
                </enumeratedValue>
              </enumeratedValues>
            </field>
            <field>
              <name>BPELCD38</name>
              <description>no description available</description>
              <bitOffset>4</bitOffset>
              <bitWidth>1</bitWidth>
              <access>read-write</access>
              <enumeratedValues>
                <enumeratedValue>
                  <name>0</name>
                  <description>LCD segment off or LCD backplane inactive for phase E</description>
                  <value>#0</value>
                </enumeratedValue>
                <enumeratedValue>
                  <name>1</name>
                  <description>LCD segment on or LCD backplane active for phase E</description>
                  <value>#1</value>
                </enumeratedValue>
              </enumeratedValues>
            </field>
            <field>
              <name>BPFLCD38</name>
              <description>no description available</description>
              <bitOffset>5</bitOffset>
              <bitWidth>1</bitWidth>
              <access>read-write</access>
              <enumeratedValues>
                <enumeratedValue>
                  <name>0</name>
                  <description>LCD segment off or LCD backplane inactive for phase F</description>
                  <value>#0</value>
                </enumeratedValue>
                <enumeratedValue>
                  <name>1</name>
                  <description>LCD segment on or LCD backplane active for phase F</description>
                  <value>#1</value>
                </enumeratedValue>
              </enumeratedValues>
            </field>
            <field>
              <name>BPGLCD38</name>
              <description>no description available</description>
              <bitOffset>6</bitOffset>
              <bitWidth>1</bitWidth>
              <access>read-write</access>
              <enumeratedValues>
                <enumeratedValue>
                  <name>0</name>
                  <description>LCD segment off or LCD backplane inactive for phase G</description>
                  <value>#0</value>
                </enumeratedValue>
                <enumeratedValue>
                  <name>1</name>
                  <description>LCD segment on or LCD backplane active for phase G</description>
                  <value>#1</value>
                </enumeratedValue>
              </enumeratedValues>
            </field>
            <field>
              <name>BPHLCD38</name>
              <description>no description available</description>
              <bitOffset>7</bitOffset>
              <bitWidth>1</bitWidth>
              <access>read-write</access>
              <enumeratedValues>
                <enumeratedValue>
                  <name>0</name>
                  <description>LCD segment off or LCD backplane inactive for phase H</description>
                  <value>#0</value>
                </enumeratedValue>
                <enumeratedValue>
                  <name>1</name>
                  <description>LCD segment on or LCD backplane active for phase H</description>
                  <value>#1</value>
                </enumeratedValue>
              </enumeratedValues>
            </field>
          </fields>
        </register>
        <register>
          <name>WF39</name>
          <description>LCD Waveform Register 39.</description>
          <addressOffset>0x47</addressOffset>
          <size>8</size>
          <access>read-write</access>
          <resetValue>0</resetValue>
          <resetMask>0</resetMask>
          <fields>
            <field>
              <name>BPALCD39</name>
              <description>no description available</description>
              <bitOffset>0</bitOffset>
              <bitWidth>1</bitWidth>
              <access>read-write</access>
              <enumeratedValues>
                <enumeratedValue>
                  <name>0</name>
                  <description>LCD segment off or LCD backplane inactive for phase A</description>
                  <value>#0</value>
                </enumeratedValue>
                <enumeratedValue>
                  <name>1</name>
                  <description>LCD segment on or LCD backplane active for phase A</description>
                  <value>#1</value>
                </enumeratedValue>
              </enumeratedValues>
            </field>
            <field>
              <name>BPBLCD39</name>
              <description>no description available</description>
              <bitOffset>1</bitOffset>
              <bitWidth>1</bitWidth>
              <access>read-write</access>
              <enumeratedValues>
                <enumeratedValue>
                  <name>0</name>
                  <description>LCD segment off or LCD backplane inactive for phase B</description>
                  <value>#0</value>
                </enumeratedValue>
                <enumeratedValue>
                  <name>1</name>
                  <description>LCD segment on or LCD backplane active for phase B</description>
                  <value>#1</value>
                </enumeratedValue>
              </enumeratedValues>
            </field>
            <field>
              <name>BPCLCD39</name>
              <description>no description available</description>
              <bitOffset>2</bitOffset>
              <bitWidth>1</bitWidth>
              <access>read-write</access>
              <enumeratedValues>
                <enumeratedValue>
                  <name>0</name>
                  <description>LCD segment off or LCD backplane inactive for phase C</description>
                  <value>#0</value>
                </enumeratedValue>
                <enumeratedValue>
                  <name>1</name>
                  <description>LCD segment on or LCD backplane active for phase C</description>
                  <value>#1</value>
                </enumeratedValue>
              </enumeratedValues>
            </field>
            <field>
              <name>BPDLCD39</name>
              <description>no description available</description>
              <bitOffset>3</bitOffset>
              <bitWidth>1</bitWidth>
              <access>read-write</access>
              <enumeratedValues>
                <enumeratedValue>
                  <name>0</name>
                  <description>LCD segment off or LCD backplane inactive for phase D</description>
                  <value>#0</value>
                </enumeratedValue>
                <enumeratedValue>
                  <name>1</name>
                  <description>LCD segment on or LCD backplane active for phase D</description>
                  <value>#1</value>
                </enumeratedValue>
              </enumeratedValues>
            </field>
            <field>
              <name>BPELCD39</name>
              <description>no description available</description>
              <bitOffset>4</bitOffset>
              <bitWidth>1</bitWidth>
              <access>read-write</access>
              <enumeratedValues>
                <enumeratedValue>
                  <name>0</name>
                  <description>LCD segment off or LCD backplane inactive for phase E</description>
                  <value>#0</value>
                </enumeratedValue>
                <enumeratedValue>
                  <name>1</name>
                  <description>LCD segment on or LCD backplane active for phase E</description>
                  <value>#1</value>
                </enumeratedValue>
              </enumeratedValues>
            </field>
            <field>
              <name>BPFLCD39</name>
              <description>no description available</description>
              <bitOffset>5</bitOffset>
              <bitWidth>1</bitWidth>
              <access>read-write</access>
              <enumeratedValues>
                <enumeratedValue>
                  <name>0</name>
                  <description>LCD segment off or LCD backplane inactive for phase F</description>
                  <value>#0</value>
                </enumeratedValue>
                <enumeratedValue>
                  <name>1</name>
                  <description>LCD segment on or LCD backplane active for phase F</description>
                  <value>#1</value>
                </enumeratedValue>
              </enumeratedValues>
            </field>
            <field>
              <name>BPGLCD39</name>
              <description>no description available</description>
              <bitOffset>6</bitOffset>
              <bitWidth>1</bitWidth>
              <access>read-write</access>
              <enumeratedValues>
                <enumeratedValue>
                  <name>0</name>
                  <description>LCD segment off or LCD backplane inactive for phase G</description>
                  <value>#0</value>
                </enumeratedValue>
                <enumeratedValue>
                  <name>1</name>
                  <description>LCD segment on or LCD backplane active for phase G</description>
                  <value>#1</value>
                </enumeratedValue>
              </enumeratedValues>
            </field>
            <field>
              <name>BPHLCD39</name>
              <description>no description available</description>
              <bitOffset>7</bitOffset>
              <bitWidth>1</bitWidth>
              <access>read-write</access>
              <enumeratedValues>
                <enumeratedValue>
                  <name>0</name>
                  <description>LCD segment off or LCD backplane inactive for phase H</description>
                  <value>#0</value>
                </enumeratedValue>
                <enumeratedValue>
                  <name>1</name>
                  <description>LCD segment on or LCD backplane active for phase H</description>
                  <value>#1</value>
                </enumeratedValue>
              </enumeratedValues>
            </field>
          </fields>
        </register>
        <register>
          <name>WF43TO40</name>
          <description>LCD Waveform register</description>
          <alternateGroup>LCD</alternateGroup>
          <addressOffset>0x48</addressOffset>
          <size>32</size>
          <access>read-write</access>
          <resetValue>0</resetValue>
          <resetMask>0xFFFFFFFF</resetMask>
          <fields>
            <field>
              <name>WF40</name>
              <description>Controls segments or phases connected to LCD_P40 as described above for WF3TO0[WF3].</description>
              <bitOffset>0</bitOffset>
              <bitWidth>8</bitWidth>
              <access>read-write</access>
            </field>
            <field>
              <name>WF41</name>
              <description>Controls segments or phases connected to LCD_P41 as described above for WF3TO0[WF3].</description>
              <bitOffset>8</bitOffset>
              <bitWidth>8</bitWidth>
              <access>read-write</access>
            </field>
            <field>
              <name>WF42</name>
              <description>Controls segments or phases connected to LCD_P42 as described above for WF3TO0[WF3].</description>
              <bitOffset>16</bitOffset>
              <bitWidth>8</bitWidth>
              <access>read-write</access>
            </field>
            <field>
              <name>WF43</name>
              <description>Controls segments or phases connected to LCD_P43 as described above for WF3TO0[WF3].</description>
              <bitOffset>24</bitOffset>
              <bitWidth>8</bitWidth>
              <access>read-write</access>
            </field>
          </fields>
        </register>
        <register>
          <name>WF40</name>
          <description>LCD Waveform Register 40.</description>
          <alternateGroup>LCD</alternateGroup>
          <addressOffset>0x48</addressOffset>
          <size>8</size>
          <access>read-write</access>
          <resetValue>0</resetValue>
          <resetMask>0</resetMask>
          <fields>
            <field>
              <name>BPALCD40</name>
              <description>no description available</description>
              <bitOffset>0</bitOffset>
              <bitWidth>1</bitWidth>
              <access>read-write</access>
              <enumeratedValues>
                <enumeratedValue>
                  <name>0</name>
                  <description>LCD segment off or LCD backplane inactive for phase A</description>
                  <value>#0</value>
                </enumeratedValue>
                <enumeratedValue>
                  <name>1</name>
                  <description>LCD segment on or LCD backplane active for phase A</description>
                  <value>#1</value>
                </enumeratedValue>
              </enumeratedValues>
            </field>
            <field>
              <name>BPBLCD40</name>
              <description>no description available</description>
              <bitOffset>1</bitOffset>
              <bitWidth>1</bitWidth>
              <access>read-write</access>
              <enumeratedValues>
                <enumeratedValue>
                  <name>0</name>
                  <description>LCD segment off or LCD backplane inactive for phase B</description>
                  <value>#0</value>
                </enumeratedValue>
                <enumeratedValue>
                  <name>1</name>
                  <description>LCD segment on or LCD backplane active for phase B</description>
                  <value>#1</value>
                </enumeratedValue>
              </enumeratedValues>
            </field>
            <field>
              <name>BPCLCD40</name>
              <description>no description available</description>
              <bitOffset>2</bitOffset>
              <bitWidth>1</bitWidth>
              <access>read-write</access>
              <enumeratedValues>
                <enumeratedValue>
                  <name>0</name>
                  <description>LCD segment off or LCD backplane inactive for phase C</description>
                  <value>#0</value>
                </enumeratedValue>
                <enumeratedValue>
                  <name>1</name>
                  <description>LCD segment on or LCD backplane active for phase C</description>
                  <value>#1</value>
                </enumeratedValue>
              </enumeratedValues>
            </field>
            <field>
              <name>BPDLCD40</name>
              <description>no description available</description>
              <bitOffset>3</bitOffset>
              <bitWidth>1</bitWidth>
              <access>read-write</access>
              <enumeratedValues>
                <enumeratedValue>
                  <name>0</name>
                  <description>LCD segment off or LCD backplane inactive for phase D</description>
                  <value>#0</value>
                </enumeratedValue>
                <enumeratedValue>
                  <name>1</name>
                  <description>LCD segment on or LCD backplane active for phase D</description>
                  <value>#1</value>
                </enumeratedValue>
              </enumeratedValues>
            </field>
            <field>
              <name>BPELCD40</name>
              <description>no description available</description>
              <bitOffset>4</bitOffset>
              <bitWidth>1</bitWidth>
              <access>read-write</access>
              <enumeratedValues>
                <enumeratedValue>
                  <name>0</name>
                  <description>LCD segment off or LCD backplane inactive for phase E</description>
                  <value>#0</value>
                </enumeratedValue>
                <enumeratedValue>
                  <name>1</name>
                  <description>LCD segment on or LCD backplane active for phase E</description>
                  <value>#1</value>
                </enumeratedValue>
              </enumeratedValues>
            </field>
            <field>
              <name>BPFLCD40</name>
              <description>no description available</description>
              <bitOffset>5</bitOffset>
              <bitWidth>1</bitWidth>
              <access>read-write</access>
              <enumeratedValues>
                <enumeratedValue>
                  <name>0</name>
                  <description>LCD segment off or LCD backplane inactive for phase F</description>
                  <value>#0</value>
                </enumeratedValue>
                <enumeratedValue>
                  <name>1</name>
                  <description>LCD segment on or LCD backplane active for phase F</description>
                  <value>#1</value>
                </enumeratedValue>
              </enumeratedValues>
            </field>
            <field>
              <name>BPGLCD40</name>
              <description>no description available</description>
              <bitOffset>6</bitOffset>
              <bitWidth>1</bitWidth>
              <access>read-write</access>
              <enumeratedValues>
                <enumeratedValue>
                  <name>0</name>
                  <description>LCD segment off or LCD backplane inactive for phase G</description>
                  <value>#0</value>
                </enumeratedValue>
                <enumeratedValue>
                  <name>1</name>
                  <description>LCD segment on or LCD backplane active for phase G</description>
                  <value>#1</value>
                </enumeratedValue>
              </enumeratedValues>
            </field>
            <field>
              <name>BPHLCD40</name>
              <description>no description available</description>
              <bitOffset>7</bitOffset>
              <bitWidth>1</bitWidth>
              <access>read-write</access>
              <enumeratedValues>
                <enumeratedValue>
                  <name>0</name>
                  <description>LCD segment off or LCD backplane inactive for phase H</description>
                  <value>#0</value>
                </enumeratedValue>
                <enumeratedValue>
                  <name>1</name>
                  <description>LCD segment on or LCD backplane active for phase H</description>
                  <value>#1</value>
                </enumeratedValue>
              </enumeratedValues>
            </field>
          </fields>
        </register>
        <register>
          <name>WF41</name>
          <description>LCD Waveform Register 41.</description>
          <addressOffset>0x49</addressOffset>
          <size>8</size>
          <access>read-write</access>
          <resetValue>0</resetValue>
          <resetMask>0</resetMask>
          <fields>
            <field>
              <name>BPALCD41</name>
              <description>no description available</description>
              <bitOffset>0</bitOffset>
              <bitWidth>1</bitWidth>
              <access>read-write</access>
              <enumeratedValues>
                <enumeratedValue>
                  <name>0</name>
                  <description>LCD segment off or LCD backplane inactive for phase A</description>
                  <value>#0</value>
                </enumeratedValue>
                <enumeratedValue>
                  <name>1</name>
                  <description>LCD segment on or LCD backplane active for phase A</description>
                  <value>#1</value>
                </enumeratedValue>
              </enumeratedValues>
            </field>
            <field>
              <name>BPBLCD41</name>
              <description>no description available</description>
              <bitOffset>1</bitOffset>
              <bitWidth>1</bitWidth>
              <access>read-write</access>
              <enumeratedValues>
                <enumeratedValue>
                  <name>0</name>
                  <description>LCD segment off or LCD backplane inactive for phase B</description>
                  <value>#0</value>
                </enumeratedValue>
                <enumeratedValue>
                  <name>1</name>
                  <description>LCD segment on or LCD backplane active for phase B</description>
                  <value>#1</value>
                </enumeratedValue>
              </enumeratedValues>
            </field>
            <field>
              <name>BPCLCD41</name>
              <description>no description available</description>
              <bitOffset>2</bitOffset>
              <bitWidth>1</bitWidth>
              <access>read-write</access>
              <enumeratedValues>
                <enumeratedValue>
                  <name>0</name>
                  <description>LCD segment off or LCD backplane inactive for phase C</description>
                  <value>#0</value>
                </enumeratedValue>
                <enumeratedValue>
                  <name>1</name>
                  <description>LCD segment on or LCD backplane active for phase C</description>
                  <value>#1</value>
                </enumeratedValue>
              </enumeratedValues>
            </field>
            <field>
              <name>BPDLCD41</name>
              <description>no description available</description>
              <bitOffset>3</bitOffset>
              <bitWidth>1</bitWidth>
              <access>read-write</access>
              <enumeratedValues>
                <enumeratedValue>
                  <name>0</name>
                  <description>LCD segment off or LCD backplane inactive for phase D</description>
                  <value>#0</value>
                </enumeratedValue>
                <enumeratedValue>
                  <name>1</name>
                  <description>LCD segment on or LCD backplane active for phase D</description>
                  <value>#1</value>
                </enumeratedValue>
              </enumeratedValues>
            </field>
            <field>
              <name>BPELCD41</name>
              <description>no description available</description>
              <bitOffset>4</bitOffset>
              <bitWidth>1</bitWidth>
              <access>read-write</access>
              <enumeratedValues>
                <enumeratedValue>
                  <name>0</name>
                  <description>LCD segment off or LCD backplane inactive for phase E</description>
                  <value>#0</value>
                </enumeratedValue>
                <enumeratedValue>
                  <name>1</name>
                  <description>LCD segment on or LCD backplane active for phase E</description>
                  <value>#1</value>
                </enumeratedValue>
              </enumeratedValues>
            </field>
            <field>
              <name>BPFLCD41</name>
              <description>no description available</description>
              <bitOffset>5</bitOffset>
              <bitWidth>1</bitWidth>
              <access>read-write</access>
              <enumeratedValues>
                <enumeratedValue>
                  <name>0</name>
                  <description>LCD segment off or LCD backplane inactive for phase F</description>
                  <value>#0</value>
                </enumeratedValue>
                <enumeratedValue>
                  <name>1</name>
                  <description>LCD segment on or LCD backplane active for phase F</description>
                  <value>#1</value>
                </enumeratedValue>
              </enumeratedValues>
            </field>
            <field>
              <name>BPGLCD41</name>
              <description>no description available</description>
              <bitOffset>6</bitOffset>
              <bitWidth>1</bitWidth>
              <access>read-write</access>
              <enumeratedValues>
                <enumeratedValue>
                  <name>0</name>
                  <description>LCD segment off or LCD backplane inactive for phase G</description>
                  <value>#0</value>
                </enumeratedValue>
                <enumeratedValue>
                  <name>1</name>
                  <description>LCD segment on or LCD backplane active for phase G</description>
                  <value>#1</value>
                </enumeratedValue>
              </enumeratedValues>
            </field>
            <field>
              <name>BPHLCD41</name>
              <description>no description available</description>
              <bitOffset>7</bitOffset>
              <bitWidth>1</bitWidth>
              <access>read-write</access>
              <enumeratedValues>
                <enumeratedValue>
                  <name>0</name>
                  <description>LCD segment off or LCD backplane inactive for phase H</description>
                  <value>#0</value>
                </enumeratedValue>
                <enumeratedValue>
                  <name>1</name>
                  <description>LCD segment on or LCD backplane active for phase H</description>
                  <value>#1</value>
                </enumeratedValue>
              </enumeratedValues>
            </field>
          </fields>
        </register>
        <register>
          <name>WF42</name>
          <description>LCD Waveform Register 42.</description>
          <addressOffset>0x4A</addressOffset>
          <size>8</size>
          <access>read-write</access>
          <resetValue>0</resetValue>
          <resetMask>0</resetMask>
          <fields>
            <field>
              <name>BPALCD42</name>
              <description>no description available</description>
              <bitOffset>0</bitOffset>
              <bitWidth>1</bitWidth>
              <access>read-write</access>
              <enumeratedValues>
                <enumeratedValue>
                  <name>0</name>
                  <description>LCD segment off or LCD backplane inactive for phase A</description>
                  <value>#0</value>
                </enumeratedValue>
                <enumeratedValue>
                  <name>1</name>
                  <description>LCD segment on or LCD backplane active for phase A</description>
                  <value>#1</value>
                </enumeratedValue>
              </enumeratedValues>
            </field>
            <field>
              <name>BPBLCD42</name>
              <description>no description available</description>
              <bitOffset>1</bitOffset>
              <bitWidth>1</bitWidth>
              <access>read-write</access>
              <enumeratedValues>
                <enumeratedValue>
                  <name>0</name>
                  <description>LCD segment off or LCD backplane inactive for phase B</description>
                  <value>#0</value>
                </enumeratedValue>
                <enumeratedValue>
                  <name>1</name>
                  <description>LCD segment on or LCD backplane active for phase B</description>
                  <value>#1</value>
                </enumeratedValue>
              </enumeratedValues>
            </field>
            <field>
              <name>BPCLCD42</name>
              <description>no description available</description>
              <bitOffset>2</bitOffset>
              <bitWidth>1</bitWidth>
              <access>read-write</access>
              <enumeratedValues>
                <enumeratedValue>
                  <name>0</name>
                  <description>LCD segment off or LCD backplane inactive for phase C</description>
                  <value>#0</value>
                </enumeratedValue>
                <enumeratedValue>
                  <name>1</name>
                  <description>LCD segment on or LCD backplane active for phase C</description>
                  <value>#1</value>
                </enumeratedValue>
              </enumeratedValues>
            </field>
            <field>
              <name>BPDLCD42</name>
              <description>no description available</description>
              <bitOffset>3</bitOffset>
              <bitWidth>1</bitWidth>
              <access>read-write</access>
              <enumeratedValues>
                <enumeratedValue>
                  <name>0</name>
                  <description>LCD segment off or LCD backplane inactive for phase D</description>
                  <value>#0</value>
                </enumeratedValue>
                <enumeratedValue>
                  <name>1</name>
                  <description>LCD segment on or LCD backplane active for phase D</description>
                  <value>#1</value>
                </enumeratedValue>
              </enumeratedValues>
            </field>
            <field>
              <name>BPELCD42</name>
              <description>no description available</description>
              <bitOffset>4</bitOffset>
              <bitWidth>1</bitWidth>
              <access>read-write</access>
              <enumeratedValues>
                <enumeratedValue>
                  <name>0</name>
                  <description>LCD segment off or LCD backplane inactive for phase E</description>
                  <value>#0</value>
                </enumeratedValue>
                <enumeratedValue>
                  <name>1</name>
                  <description>LCD segment on or LCD backplane active for phase E</description>
                  <value>#1</value>
                </enumeratedValue>
              </enumeratedValues>
            </field>
            <field>
              <name>BPFLCD42</name>
              <description>no description available</description>
              <bitOffset>5</bitOffset>
              <bitWidth>1</bitWidth>
              <access>read-write</access>
              <enumeratedValues>
                <enumeratedValue>
                  <name>0</name>
                  <description>LCD segment off or LCD backplane inactive for phase F</description>
                  <value>#0</value>
                </enumeratedValue>
                <enumeratedValue>
                  <name>1</name>
                  <description>LCD segment on or LCD backplane active for phase F</description>
                  <value>#1</value>
                </enumeratedValue>
              </enumeratedValues>
            </field>
            <field>
              <name>BPGLCD42</name>
              <description>no description available</description>
              <bitOffset>6</bitOffset>
              <bitWidth>1</bitWidth>
              <access>read-write</access>
              <enumeratedValues>
                <enumeratedValue>
                  <name>0</name>
                  <description>LCD segment off or LCD backplane inactive for phase G</description>
                  <value>#0</value>
                </enumeratedValue>
                <enumeratedValue>
                  <name>1</name>
                  <description>LCD segment on or LCD backplane active for phase G</description>
                  <value>#1</value>
                </enumeratedValue>
              </enumeratedValues>
            </field>
            <field>
              <name>BPHLCD42</name>
              <description>no description available</description>
              <bitOffset>7</bitOffset>
              <bitWidth>1</bitWidth>
              <access>read-write</access>
              <enumeratedValues>
                <enumeratedValue>
                  <name>0</name>
                  <description>LCD segment off or LCD backplane inactive for phase H</description>
                  <value>#0</value>
                </enumeratedValue>
                <enumeratedValue>
                  <name>1</name>
                  <description>LCD segment on or LCD backplane active for phase H</description>
                  <value>#1</value>
                </enumeratedValue>
              </enumeratedValues>
            </field>
          </fields>
        </register>
        <register>
          <name>WF43</name>
          <description>LCD Waveform Register 43.</description>
          <addressOffset>0x4B</addressOffset>
          <size>8</size>
          <access>read-write</access>
          <resetValue>0</resetValue>
          <resetMask>0</resetMask>
          <fields>
            <field>
              <name>BPALCD43</name>
              <description>no description available</description>
              <bitOffset>0</bitOffset>
              <bitWidth>1</bitWidth>
              <access>read-write</access>
              <enumeratedValues>
                <enumeratedValue>
                  <name>0</name>
                  <description>LCD segment off or LCD backplane inactive for phase A</description>
                  <value>#0</value>
                </enumeratedValue>
                <enumeratedValue>
                  <name>1</name>
                  <description>LCD segment on or LCD backplane active for phase A</description>
                  <value>#1</value>
                </enumeratedValue>
              </enumeratedValues>
            </field>
            <field>
              <name>BPBLCD43</name>
              <description>no description available</description>
              <bitOffset>1</bitOffset>
              <bitWidth>1</bitWidth>
              <access>read-write</access>
              <enumeratedValues>
                <enumeratedValue>
                  <name>0</name>
                  <description>LCD segment off or LCD backplane inactive for phase B</description>
                  <value>#0</value>
                </enumeratedValue>
                <enumeratedValue>
                  <name>1</name>
                  <description>LCD segment on or LCD backplane active for phase B</description>
                  <value>#1</value>
                </enumeratedValue>
              </enumeratedValues>
            </field>
            <field>
              <name>BPCLCD43</name>
              <description>no description available</description>
              <bitOffset>2</bitOffset>
              <bitWidth>1</bitWidth>
              <access>read-write</access>
              <enumeratedValues>
                <enumeratedValue>
                  <name>0</name>
                  <description>LCD segment off or LCD backplane inactive for phase C</description>
                  <value>#0</value>
                </enumeratedValue>
                <enumeratedValue>
                  <name>1</name>
                  <description>LCD segment on or LCD backplane active for phase C</description>
                  <value>#1</value>
                </enumeratedValue>
              </enumeratedValues>
            </field>
            <field>
              <name>BPDLCD43</name>
              <description>no description available</description>
              <bitOffset>3</bitOffset>
              <bitWidth>1</bitWidth>
              <access>read-write</access>
              <enumeratedValues>
                <enumeratedValue>
                  <name>0</name>
                  <description>LCD segment off or LCD backplane inactive for phase D</description>
                  <value>#0</value>
                </enumeratedValue>
                <enumeratedValue>
                  <name>1</name>
                  <description>LCD segment on or LCD backplane active for phase D</description>
                  <value>#1</value>
                </enumeratedValue>
              </enumeratedValues>
            </field>
            <field>
              <name>BPELCD43</name>
              <description>no description available</description>
              <bitOffset>4</bitOffset>
              <bitWidth>1</bitWidth>
              <access>read-write</access>
              <enumeratedValues>
                <enumeratedValue>
                  <name>0</name>
                  <description>LCD segment off or LCD backplane inactive for phase E</description>
                  <value>#0</value>
                </enumeratedValue>
                <enumeratedValue>
                  <name>1</name>
                  <description>LCD segment on or LCD backplane active for phase E</description>
                  <value>#1</value>
                </enumeratedValue>
              </enumeratedValues>
            </field>
            <field>
              <name>BPFLCD43</name>
              <description>no description available</description>
              <bitOffset>5</bitOffset>
              <bitWidth>1</bitWidth>
              <access>read-write</access>
              <enumeratedValues>
                <enumeratedValue>
                  <name>0</name>
                  <description>LCD segment off or LCD backplane inactive for phase F</description>
                  <value>#0</value>
                </enumeratedValue>
                <enumeratedValue>
                  <name>1</name>
                  <description>LCD segment on or LCD backplane active for phase F</description>
                  <value>#1</value>
                </enumeratedValue>
              </enumeratedValues>
            </field>
            <field>
              <name>BPGLCD43</name>
              <description>no description available</description>
              <bitOffset>6</bitOffset>
              <bitWidth>1</bitWidth>
              <access>read-write</access>
              <enumeratedValues>
                <enumeratedValue>
                  <name>0</name>
                  <description>LCD segment off or LCD backplane inactive for phase G</description>
                  <value>#0</value>
                </enumeratedValue>
                <enumeratedValue>
                  <name>1</name>
                  <description>LCD segment on or LCD backplane active for phase G</description>
                  <value>#1</value>
                </enumeratedValue>
              </enumeratedValues>
            </field>
            <field>
              <name>BPHLCD43</name>
              <description>no description available</description>
              <bitOffset>7</bitOffset>
              <bitWidth>1</bitWidth>
              <access>read-write</access>
              <enumeratedValues>
                <enumeratedValue>
                  <name>0</name>
                  <description>LCD segment off or LCD backplane inactive for phase H</description>
                  <value>#0</value>
                </enumeratedValue>
                <enumeratedValue>
                  <name>1</name>
                  <description>LCD segment on or LCD backplane active for phase H</description>
                  <value>#1</value>
                </enumeratedValue>
              </enumeratedValues>
            </field>
          </fields>
        </register>
        <register>
          <name>WF47TO44</name>
          <description>LCD Waveform register</description>
          <alternateGroup>LCD</alternateGroup>
          <addressOffset>0x4C</addressOffset>
          <size>32</size>
          <access>read-write</access>
          <resetValue>0</resetValue>
          <resetMask>0xFFFFFFFF</resetMask>
          <fields>
            <field>
              <name>WF44</name>
              <description>Controls segments or phases connected to LCD_P44 as described above for WF3TO0[WF3].</description>
              <bitOffset>0</bitOffset>
              <bitWidth>8</bitWidth>
              <access>read-write</access>
            </field>
            <field>
              <name>WF45</name>
              <description>Controls segments or phases connected to LCD_P45 as described above for WF3TO0[WF3].</description>
              <bitOffset>8</bitOffset>
              <bitWidth>8</bitWidth>
              <access>read-write</access>
            </field>
            <field>
              <name>WF46</name>
              <description>Controls segments or phases connected to LCD_P46 as described above for WF3TO0[WF3].</description>
              <bitOffset>16</bitOffset>
              <bitWidth>8</bitWidth>
              <access>read-write</access>
            </field>
            <field>
              <name>WF47</name>
              <description>Controls segments or phases connected to LCD_P47 as described above for WF3TO0[WF3].</description>
              <bitOffset>24</bitOffset>
              <bitWidth>8</bitWidth>
              <access>read-write</access>
            </field>
          </fields>
        </register>
        <register>
          <name>WF44</name>
          <description>LCD Waveform Register 44.</description>
          <alternateGroup>LCD</alternateGroup>
          <addressOffset>0x4C</addressOffset>
          <size>8</size>
          <access>read-write</access>
          <resetValue>0</resetValue>
          <resetMask>0</resetMask>
          <fields>
            <field>
              <name>BPALCD44</name>
              <description>no description available</description>
              <bitOffset>0</bitOffset>
              <bitWidth>1</bitWidth>
              <access>read-write</access>
              <enumeratedValues>
                <enumeratedValue>
                  <name>0</name>
                  <description>LCD segment off or LCD backplane inactive for phase A</description>
                  <value>#0</value>
                </enumeratedValue>
                <enumeratedValue>
                  <name>1</name>
                  <description>LCD segment on or LCD backplane active for phase A</description>
                  <value>#1</value>
                </enumeratedValue>
              </enumeratedValues>
            </field>
            <field>
              <name>BPBLCD44</name>
              <description>no description available</description>
              <bitOffset>1</bitOffset>
              <bitWidth>1</bitWidth>
              <access>read-write</access>
              <enumeratedValues>
                <enumeratedValue>
                  <name>0</name>
                  <description>LCD segment off or LCD backplane inactive for phase B</description>
                  <value>#0</value>
                </enumeratedValue>
                <enumeratedValue>
                  <name>1</name>
                  <description>LCD segment on or LCD backplane active for phase B</description>
                  <value>#1</value>
                </enumeratedValue>
              </enumeratedValues>
            </field>
            <field>
              <name>BPCLCD44</name>
              <description>no description available</description>
              <bitOffset>2</bitOffset>
              <bitWidth>1</bitWidth>
              <access>read-write</access>
              <enumeratedValues>
                <enumeratedValue>
                  <name>0</name>
                  <description>LCD segment off or LCD backplane inactive for phase C</description>
                  <value>#0</value>
                </enumeratedValue>
                <enumeratedValue>
                  <name>1</name>
                  <description>LCD segment on or LCD backplane active for phase C</description>
                  <value>#1</value>
                </enumeratedValue>
              </enumeratedValues>
            </field>
            <field>
              <name>BPDLCD44</name>
              <description>no description available</description>
              <bitOffset>3</bitOffset>
              <bitWidth>1</bitWidth>
              <access>read-write</access>
              <enumeratedValues>
                <enumeratedValue>
                  <name>0</name>
                  <description>LCD segment off or LCD backplane inactive for phase D</description>
                  <value>#0</value>
                </enumeratedValue>
                <enumeratedValue>
                  <name>1</name>
                  <description>LCD segment on or LCD backplane active for phase D</description>
                  <value>#1</value>
                </enumeratedValue>
              </enumeratedValues>
            </field>
            <field>
              <name>BPELCD44</name>
              <description>no description available</description>
              <bitOffset>4</bitOffset>
              <bitWidth>1</bitWidth>
              <access>read-write</access>
              <enumeratedValues>
                <enumeratedValue>
                  <name>0</name>
                  <description>LCD segment off or LCD backplane inactive for phase E</description>
                  <value>#0</value>
                </enumeratedValue>
                <enumeratedValue>
                  <name>1</name>
                  <description>LCD segment on or LCD backplane active for phase E</description>
                  <value>#1</value>
                </enumeratedValue>
              </enumeratedValues>
            </field>
            <field>
              <name>BPFLCD44</name>
              <description>no description available</description>
              <bitOffset>5</bitOffset>
              <bitWidth>1</bitWidth>
              <access>read-write</access>
              <enumeratedValues>
                <enumeratedValue>
                  <name>0</name>
                  <description>LCD segment off or LCD backplane inactive for phase F</description>
                  <value>#0</value>
                </enumeratedValue>
                <enumeratedValue>
                  <name>1</name>
                  <description>LCD segment on or LCD backplane active for phase F</description>
                  <value>#1</value>
                </enumeratedValue>
              </enumeratedValues>
            </field>
            <field>
              <name>BPGLCD44</name>
              <description>no description available</description>
              <bitOffset>6</bitOffset>
              <bitWidth>1</bitWidth>
              <access>read-write</access>
              <enumeratedValues>
                <enumeratedValue>
                  <name>0</name>
                  <description>LCD segment off or LCD backplane inactive for phase G</description>
                  <value>#0</value>
                </enumeratedValue>
                <enumeratedValue>
                  <name>1</name>
                  <description>LCD segment on or LCD backplane active for phase G</description>
                  <value>#1</value>
                </enumeratedValue>
              </enumeratedValues>
            </field>
            <field>
              <name>BPHLCD44</name>
              <description>no description available</description>
              <bitOffset>7</bitOffset>
              <bitWidth>1</bitWidth>
              <access>read-write</access>
              <enumeratedValues>
                <enumeratedValue>
                  <name>0</name>
                  <description>LCD segment off or LCD backplane inactive for phase H</description>
                  <value>#0</value>
                </enumeratedValue>
                <enumeratedValue>
                  <name>1</name>
                  <description>LCD segment on or LCD backplane active for phase H</description>
                  <value>#1</value>
                </enumeratedValue>
              </enumeratedValues>
            </field>
          </fields>
        </register>
        <register>
          <name>WF45</name>
          <description>LCD Waveform Register 45.</description>
          <addressOffset>0x4D</addressOffset>
          <size>8</size>
          <access>read-write</access>
          <resetValue>0</resetValue>
          <resetMask>0</resetMask>
          <fields>
            <field>
              <name>BPALCD45</name>
              <description>no description available</description>
              <bitOffset>0</bitOffset>
              <bitWidth>1</bitWidth>
              <access>read-write</access>
              <enumeratedValues>
                <enumeratedValue>
                  <name>0</name>
                  <description>LCD segment off or LCD backplane inactive for phase A</description>
                  <value>#0</value>
                </enumeratedValue>
                <enumeratedValue>
                  <name>1</name>
                  <description>LCD segment on or LCD backplane active for phase A</description>
                  <value>#1</value>
                </enumeratedValue>
              </enumeratedValues>
            </field>
            <field>
              <name>BPBLCD45</name>
              <description>no description available</description>
              <bitOffset>1</bitOffset>
              <bitWidth>1</bitWidth>
              <access>read-write</access>
              <enumeratedValues>
                <enumeratedValue>
                  <name>0</name>
                  <description>LCD segment off or LCD backplane inactive for phase B</description>
                  <value>#0</value>
                </enumeratedValue>
                <enumeratedValue>
                  <name>1</name>
                  <description>LCD segment on or LCD backplane active for phase B</description>
                  <value>#1</value>
                </enumeratedValue>
              </enumeratedValues>
            </field>
            <field>
              <name>BPCLCD45</name>
              <description>no description available</description>
              <bitOffset>2</bitOffset>
              <bitWidth>1</bitWidth>
              <access>read-write</access>
              <enumeratedValues>
                <enumeratedValue>
                  <name>0</name>
                  <description>LCD segment off or LCD backplane inactive for phase C</description>
                  <value>#0</value>
                </enumeratedValue>
                <enumeratedValue>
                  <name>1</name>
                  <description>LCD segment on or LCD backplane active for phase C</description>
                  <value>#1</value>
                </enumeratedValue>
              </enumeratedValues>
            </field>
            <field>
              <name>BPDLCD45</name>
              <description>no description available</description>
              <bitOffset>3</bitOffset>
              <bitWidth>1</bitWidth>
              <access>read-write</access>
              <enumeratedValues>
                <enumeratedValue>
                  <name>0</name>
                  <description>LCD segment off or LCD backplane inactive for phase D</description>
                  <value>#0</value>
                </enumeratedValue>
                <enumeratedValue>
                  <name>1</name>
                  <description>LCD segment on or LCD backplane active for phase D</description>
                  <value>#1</value>
                </enumeratedValue>
              </enumeratedValues>
            </field>
            <field>
              <name>BPELCD45</name>
              <description>no description available</description>
              <bitOffset>4</bitOffset>
              <bitWidth>1</bitWidth>
              <access>read-write</access>
              <enumeratedValues>
                <enumeratedValue>
                  <name>0</name>
                  <description>LCD segment off or LCD backplane inactive for phase E</description>
                  <value>#0</value>
                </enumeratedValue>
                <enumeratedValue>
                  <name>1</name>
                  <description>LCD segment on or LCD backplane active for phase E</description>
                  <value>#1</value>
                </enumeratedValue>
              </enumeratedValues>
            </field>
            <field>
              <name>BPFLCD45</name>
              <description>no description available</description>
              <bitOffset>5</bitOffset>
              <bitWidth>1</bitWidth>
              <access>read-write</access>
              <enumeratedValues>
                <enumeratedValue>
                  <name>0</name>
                  <description>LCD segment off or LCD backplane inactive for phase F</description>
                  <value>#0</value>
                </enumeratedValue>
                <enumeratedValue>
                  <name>1</name>
                  <description>LCD segment on or LCD backplane active for phase F</description>
                  <value>#1</value>
                </enumeratedValue>
              </enumeratedValues>
            </field>
            <field>
              <name>BPGLCD45</name>
              <description>no description available</description>
              <bitOffset>6</bitOffset>
              <bitWidth>1</bitWidth>
              <access>read-write</access>
              <enumeratedValues>
                <enumeratedValue>
                  <name>0</name>
                  <description>LCD segment off or LCD backplane inactive for phase G</description>
                  <value>#0</value>
                </enumeratedValue>
                <enumeratedValue>
                  <name>1</name>
                  <description>LCD segment on or LCD backplane active for phase G</description>
                  <value>#1</value>
                </enumeratedValue>
              </enumeratedValues>
            </field>
            <field>
              <name>BPHLCD45</name>
              <description>no description available</description>
              <bitOffset>7</bitOffset>
              <bitWidth>1</bitWidth>
              <access>read-write</access>
              <enumeratedValues>
                <enumeratedValue>
                  <name>0</name>
                  <description>LCD segment off or LCD backplane inactive for phase H</description>
                  <value>#0</value>
                </enumeratedValue>
                <enumeratedValue>
                  <name>1</name>
                  <description>LCD segment on or LCD backplane active for phase H</description>
                  <value>#1</value>
                </enumeratedValue>
              </enumeratedValues>
            </field>
          </fields>
        </register>
        <register>
          <name>WF46</name>
          <description>LCD Waveform Register 46.</description>
          <addressOffset>0x4E</addressOffset>
          <size>8</size>
          <access>read-write</access>
          <resetValue>0</resetValue>
          <resetMask>0</resetMask>
          <fields>
            <field>
              <name>BPALCD46</name>
              <description>no description available</description>
              <bitOffset>0</bitOffset>
              <bitWidth>1</bitWidth>
              <access>read-write</access>
              <enumeratedValues>
                <enumeratedValue>
                  <name>0</name>
                  <description>LCD segment off or LCD backplane inactive for phase A</description>
                  <value>#0</value>
                </enumeratedValue>
                <enumeratedValue>
                  <name>1</name>
                  <description>LCD segment on or LCD backplane active for phase A</description>
                  <value>#1</value>
                </enumeratedValue>
              </enumeratedValues>
            </field>
            <field>
              <name>BPBLCD46</name>
              <description>no description available</description>
              <bitOffset>1</bitOffset>
              <bitWidth>1</bitWidth>
              <access>read-write</access>
              <enumeratedValues>
                <enumeratedValue>
                  <name>0</name>
                  <description>LCD segment off or LCD backplane inactive for phase B</description>
                  <value>#0</value>
                </enumeratedValue>
                <enumeratedValue>
                  <name>1</name>
                  <description>LCD segment on or LCD backplane active for phase B</description>
                  <value>#1</value>
                </enumeratedValue>
              </enumeratedValues>
            </field>
            <field>
              <name>BPCLCD46</name>
              <description>no description available</description>
              <bitOffset>2</bitOffset>
              <bitWidth>1</bitWidth>
              <access>read-write</access>
              <enumeratedValues>
                <enumeratedValue>
                  <name>0</name>
                  <description>LCD segment off or LCD backplane inactive for phase C</description>
                  <value>#0</value>
                </enumeratedValue>
                <enumeratedValue>
                  <name>1</name>
                  <description>LCD segment on or LCD backplane active for phase C</description>
                  <value>#1</value>
                </enumeratedValue>
              </enumeratedValues>
            </field>
            <field>
              <name>BPDLCD46</name>
              <description>no description available</description>
              <bitOffset>3</bitOffset>
              <bitWidth>1</bitWidth>
              <access>read-write</access>
              <enumeratedValues>
                <enumeratedValue>
                  <name>0</name>
                  <description>LCD segment off or LCD backplane inactive for phase D</description>
                  <value>#0</value>
                </enumeratedValue>
                <enumeratedValue>
                  <name>1</name>
                  <description>LCD segment on or LCD backplane active for phase D</description>
                  <value>#1</value>
                </enumeratedValue>
              </enumeratedValues>
            </field>
            <field>
              <name>BPELCD46</name>
              <description>no description available</description>
              <bitOffset>4</bitOffset>
              <bitWidth>1</bitWidth>
              <access>read-write</access>
              <enumeratedValues>
                <enumeratedValue>
                  <name>0</name>
                  <description>LCD segment off or LCD backplane inactive for phase E</description>
                  <value>#0</value>
                </enumeratedValue>
                <enumeratedValue>
                  <name>1</name>
                  <description>LCD segment on or LCD backplane active for phase E</description>
                  <value>#1</value>
                </enumeratedValue>
              </enumeratedValues>
            </field>
            <field>
              <name>BPFLCD46</name>
              <description>no description available</description>
              <bitOffset>5</bitOffset>
              <bitWidth>1</bitWidth>
              <access>read-write</access>
              <enumeratedValues>
                <enumeratedValue>
                  <name>0</name>
                  <description>LCD segment off or LCD backplane inactive for phase F</description>
                  <value>#0</value>
                </enumeratedValue>
                <enumeratedValue>
                  <name>1</name>
                  <description>LCD segment on or LCD backplane active for phase F</description>
                  <value>#1</value>
                </enumeratedValue>
              </enumeratedValues>
            </field>
            <field>
              <name>BPGLCD46</name>
              <description>no description available</description>
              <bitOffset>6</bitOffset>
              <bitWidth>1</bitWidth>
              <access>read-write</access>
              <enumeratedValues>
                <enumeratedValue>
                  <name>0</name>
                  <description>LCD segment off or LCD backplane inactive for phase G</description>
                  <value>#0</value>
                </enumeratedValue>
                <enumeratedValue>
                  <name>1</name>
                  <description>LCD segment on or LCD backplane active for phase G</description>
                  <value>#1</value>
                </enumeratedValue>
              </enumeratedValues>
            </field>
            <field>
              <name>BPHLCD46</name>
              <description>no description available</description>
              <bitOffset>7</bitOffset>
              <bitWidth>1</bitWidth>
              <access>read-write</access>
              <enumeratedValues>
                <enumeratedValue>
                  <name>0</name>
                  <description>LCD segment off or LCD backplane inactive for phase H</description>
                  <value>#0</value>
                </enumeratedValue>
                <enumeratedValue>
                  <name>1</name>
                  <description>LCD segment on or LCD backplane active for phase H</description>
                  <value>#1</value>
                </enumeratedValue>
              </enumeratedValues>
            </field>
          </fields>
        </register>
        <register>
          <name>WF47</name>
          <description>LCD Waveform Register 47.</description>
          <addressOffset>0x4F</addressOffset>
          <size>8</size>
          <access>read-write</access>
          <resetValue>0</resetValue>
          <resetMask>0</resetMask>
          <fields>
            <field>
              <name>BPALCD47</name>
              <description>no description available</description>
              <bitOffset>0</bitOffset>
              <bitWidth>1</bitWidth>
              <access>read-write</access>
              <enumeratedValues>
                <enumeratedValue>
                  <name>0</name>
                  <description>LCD segment off or LCD backplane inactive for phase A</description>
                  <value>#0</value>
                </enumeratedValue>
                <enumeratedValue>
                  <name>1</name>
                  <description>LCD segment on or LCD backplane active for phase A</description>
                  <value>#1</value>
                </enumeratedValue>
              </enumeratedValues>
            </field>
            <field>
              <name>BPBLCD47</name>
              <description>no description available</description>
              <bitOffset>1</bitOffset>
              <bitWidth>1</bitWidth>
              <access>read-write</access>
              <enumeratedValues>
                <enumeratedValue>
                  <name>0</name>
                  <description>LCD segment off or LCD backplane inactive for phase B</description>
                  <value>#0</value>
                </enumeratedValue>
                <enumeratedValue>
                  <name>1</name>
                  <description>LCD segment on or LCD backplane active for phase B</description>
                  <value>#1</value>
                </enumeratedValue>
              </enumeratedValues>
            </field>
            <field>
              <name>BPCLCD47</name>
              <description>no description available</description>
              <bitOffset>2</bitOffset>
              <bitWidth>1</bitWidth>
              <access>read-write</access>
              <enumeratedValues>
                <enumeratedValue>
                  <name>0</name>
                  <description>LCD segment off or LCD backplane inactive for phase C</description>
                  <value>#0</value>
                </enumeratedValue>
                <enumeratedValue>
                  <name>1</name>
                  <description>LCD segment on or LCD backplane active for phase C</description>
                  <value>#1</value>
                </enumeratedValue>
              </enumeratedValues>
            </field>
            <field>
              <name>BPDLCD47</name>
              <description>no description available</description>
              <bitOffset>3</bitOffset>
              <bitWidth>1</bitWidth>
              <access>read-write</access>
              <enumeratedValues>
                <enumeratedValue>
                  <name>0</name>
                  <description>LCD segment off or LCD backplane inactive for phase D</description>
                  <value>#0</value>
                </enumeratedValue>
                <enumeratedValue>
                  <name>1</name>
                  <description>LCD segment on or LCD backplane active for phase D</description>
                  <value>#1</value>
                </enumeratedValue>
              </enumeratedValues>
            </field>
            <field>
              <name>BPELCD47</name>
              <description>no description available</description>
              <bitOffset>4</bitOffset>
              <bitWidth>1</bitWidth>
              <access>read-write</access>
              <enumeratedValues>
                <enumeratedValue>
                  <name>0</name>
                  <description>LCD segment off or LCD backplane inactive for phase E</description>
                  <value>#0</value>
                </enumeratedValue>
                <enumeratedValue>
                  <name>1</name>
                  <description>LCD segment on or LCD backplane active for phase E</description>
                  <value>#1</value>
                </enumeratedValue>
              </enumeratedValues>
            </field>
            <field>
              <name>BPFLCD47</name>
              <description>no description available</description>
              <bitOffset>5</bitOffset>
              <bitWidth>1</bitWidth>
              <access>read-write</access>
              <enumeratedValues>
                <enumeratedValue>
                  <name>0</name>
                  <description>LCD segment off or LCD backplane inactive for phase F</description>
                  <value>#0</value>
                </enumeratedValue>
                <enumeratedValue>
                  <name>1</name>
                  <description>LCD segment on or LCD backplane active for phase F</description>
                  <value>#1</value>
                </enumeratedValue>
              </enumeratedValues>
            </field>
            <field>
              <name>BPGLCD47</name>
              <description>no description available</description>
              <bitOffset>6</bitOffset>
              <bitWidth>1</bitWidth>
              <access>read-write</access>
              <enumeratedValues>
                <enumeratedValue>
                  <name>0</name>
                  <description>LCD segment off or LCD backplane inactive for phase G</description>
                  <value>#0</value>
                </enumeratedValue>
                <enumeratedValue>
                  <name>1</name>
                  <description>LCD segment on or LCD backplane active for phase G</description>
                  <value>#1</value>
                </enumeratedValue>
              </enumeratedValues>
            </field>
            <field>
              <name>BPHLCD47</name>
              <description>no description available</description>
              <bitOffset>7</bitOffset>
              <bitWidth>1</bitWidth>
              <access>read-write</access>
              <enumeratedValues>
                <enumeratedValue>
                  <name>0</name>
                  <description>LCD segment off or LCD backplane inactive for phase H</description>
                  <value>#0</value>
                </enumeratedValue>
                <enumeratedValue>
                  <name>1</name>
                  <description>LCD segment on or LCD backplane active for phase H</description>
                  <value>#1</value>
                </enumeratedValue>
              </enumeratedValues>
            </field>
          </fields>
        </register>
        <register>
          <name>WF51TO48</name>
          <description>LCD Waveform register</description>
          <alternateGroup>LCD</alternateGroup>
          <addressOffset>0x50</addressOffset>
          <size>32</size>
          <access>read-write</access>
          <resetValue>0</resetValue>
          <resetMask>0xFFFFFFFF</resetMask>
          <fields>
            <field>
              <name>WF48</name>
              <description>Controls segments or phases connected to LCD_P48 as described above for WF3TO0[WF3].</description>
              <bitOffset>0</bitOffset>
              <bitWidth>8</bitWidth>
              <access>read-write</access>
            </field>
            <field>
              <name>WF49</name>
              <description>Controls segments or phases connected to LCD_P49 as described above for WF3TO0[WF3].</description>
              <bitOffset>8</bitOffset>
              <bitWidth>8</bitWidth>
              <access>read-write</access>
            </field>
            <field>
              <name>WF50</name>
              <description>Controls segments or phases connected to LCD_P50 as described above for WF3TO0[WF3].</description>
              <bitOffset>16</bitOffset>
              <bitWidth>8</bitWidth>
              <access>read-write</access>
            </field>
            <field>
              <name>WF51</name>
              <description>Controls segments or phases connected to LCD_P51 as described above for WF3TO0[WF3].</description>
              <bitOffset>24</bitOffset>
              <bitWidth>8</bitWidth>
              <access>read-write</access>
            </field>
          </fields>
        </register>
        <register>
          <name>WF48</name>
          <description>LCD Waveform Register 48.</description>
          <alternateGroup>LCD</alternateGroup>
          <addressOffset>0x50</addressOffset>
          <size>8</size>
          <access>read-write</access>
          <resetValue>0</resetValue>
          <resetMask>0</resetMask>
          <fields>
            <field>
              <name>BPALCD48</name>
              <description>no description available</description>
              <bitOffset>0</bitOffset>
              <bitWidth>1</bitWidth>
              <access>read-write</access>
              <enumeratedValues>
                <enumeratedValue>
                  <name>0</name>
                  <description>LCD segment off or LCD backplane inactive for phase A</description>
                  <value>#0</value>
                </enumeratedValue>
                <enumeratedValue>
                  <name>1</name>
                  <description>LCD segment on or LCD backplane active for phase A</description>
                  <value>#1</value>
                </enumeratedValue>
              </enumeratedValues>
            </field>
            <field>
              <name>BPBLCD48</name>
              <description>no description available</description>
              <bitOffset>1</bitOffset>
              <bitWidth>1</bitWidth>
              <access>read-write</access>
              <enumeratedValues>
                <enumeratedValue>
                  <name>0</name>
                  <description>LCD segment off or LCD backplane inactive for phase B</description>
                  <value>#0</value>
                </enumeratedValue>
                <enumeratedValue>
                  <name>1</name>
                  <description>LCD segment on or LCD backplane active for phase B</description>
                  <value>#1</value>
                </enumeratedValue>
              </enumeratedValues>
            </field>
            <field>
              <name>BPCLCD48</name>
              <description>no description available</description>
              <bitOffset>2</bitOffset>
              <bitWidth>1</bitWidth>
              <access>read-write</access>
              <enumeratedValues>
                <enumeratedValue>
                  <name>0</name>
                  <description>LCD segment off or LCD backplane inactive for phase C</description>
                  <value>#0</value>
                </enumeratedValue>
                <enumeratedValue>
                  <name>1</name>
                  <description>LCD segment on or LCD backplane active for phase C</description>
                  <value>#1</value>
                </enumeratedValue>
              </enumeratedValues>
            </field>
            <field>
              <name>BPDLCD48</name>
              <description>no description available</description>
              <bitOffset>3</bitOffset>
              <bitWidth>1</bitWidth>
              <access>read-write</access>
              <enumeratedValues>
                <enumeratedValue>
                  <name>0</name>
                  <description>LCD segment off or LCD backplane inactive for phase D</description>
                  <value>#0</value>
                </enumeratedValue>
                <enumeratedValue>
                  <name>1</name>
                  <description>LCD segment on or LCD backplane active for phase D</description>
                  <value>#1</value>
                </enumeratedValue>
              </enumeratedValues>
            </field>
            <field>
              <name>BPELCD48</name>
              <description>no description available</description>
              <bitOffset>4</bitOffset>
              <bitWidth>1</bitWidth>
              <access>read-write</access>
              <enumeratedValues>
                <enumeratedValue>
                  <name>0</name>
                  <description>LCD segment off or LCD backplane inactive for phase E</description>
                  <value>#0</value>
                </enumeratedValue>
                <enumeratedValue>
                  <name>1</name>
                  <description>LCD segment on or LCD backplane active for phase E</description>
                  <value>#1</value>
                </enumeratedValue>
              </enumeratedValues>
            </field>
            <field>
              <name>BPFLCD48</name>
              <description>no description available</description>
              <bitOffset>5</bitOffset>
              <bitWidth>1</bitWidth>
              <access>read-write</access>
              <enumeratedValues>
                <enumeratedValue>
                  <name>0</name>
                  <description>LCD segment off or LCD backplane inactive for phase F</description>
                  <value>#0</value>
                </enumeratedValue>
                <enumeratedValue>
                  <name>1</name>
                  <description>LCD segment on or LCD backplane active for phase F</description>
                  <value>#1</value>
                </enumeratedValue>
              </enumeratedValues>
            </field>
            <field>
              <name>BPGLCD48</name>
              <description>no description available</description>
              <bitOffset>6</bitOffset>
              <bitWidth>1</bitWidth>
              <access>read-write</access>
              <enumeratedValues>
                <enumeratedValue>
                  <name>0</name>
                  <description>LCD segment off or LCD backplane inactive for phase G</description>
                  <value>#0</value>
                </enumeratedValue>
                <enumeratedValue>
                  <name>1</name>
                  <description>LCD segment on or LCD backplane active for phase G</description>
                  <value>#1</value>
                </enumeratedValue>
              </enumeratedValues>
            </field>
            <field>
              <name>BPHLCD48</name>
              <description>no description available</description>
              <bitOffset>7</bitOffset>
              <bitWidth>1</bitWidth>
              <access>read-write</access>
              <enumeratedValues>
                <enumeratedValue>
                  <name>0</name>
                  <description>LCD segment off or LCD backplane inactive for phase H</description>
                  <value>#0</value>
                </enumeratedValue>
                <enumeratedValue>
                  <name>1</name>
                  <description>LCD segment on or LCD backplane active for phase H</description>
                  <value>#1</value>
                </enumeratedValue>
              </enumeratedValues>
            </field>
          </fields>
        </register>
        <register>
          <name>WF49</name>
          <description>LCD Waveform Register 49.</description>
          <addressOffset>0x51</addressOffset>
          <size>8</size>
          <access>read-write</access>
          <resetValue>0</resetValue>
          <resetMask>0</resetMask>
          <fields>
            <field>
              <name>BPALCD49</name>
              <description>no description available</description>
              <bitOffset>0</bitOffset>
              <bitWidth>1</bitWidth>
              <access>read-write</access>
              <enumeratedValues>
                <enumeratedValue>
                  <name>0</name>
                  <description>LCD segment off or LCD backplane inactive for phase A</description>
                  <value>#0</value>
                </enumeratedValue>
                <enumeratedValue>
                  <name>1</name>
                  <description>LCD segment on or LCD backplane active for phase A</description>
                  <value>#1</value>
                </enumeratedValue>
              </enumeratedValues>
            </field>
            <field>
              <name>BPBLCD49</name>
              <description>no description available</description>
              <bitOffset>1</bitOffset>
              <bitWidth>1</bitWidth>
              <access>read-write</access>
              <enumeratedValues>
                <enumeratedValue>
                  <name>0</name>
                  <description>LCD segment off or LCD backplane inactive for phase B</description>
                  <value>#0</value>
                </enumeratedValue>
                <enumeratedValue>
                  <name>1</name>
                  <description>LCD segment on or LCD backplane active for phase B</description>
                  <value>#1</value>
                </enumeratedValue>
              </enumeratedValues>
            </field>
            <field>
              <name>BPCLCD49</name>
              <description>no description available</description>
              <bitOffset>2</bitOffset>
              <bitWidth>1</bitWidth>
              <access>read-write</access>
              <enumeratedValues>
                <enumeratedValue>
                  <name>0</name>
                  <description>LCD segment off or LCD backplane inactive for phase C</description>
                  <value>#0</value>
                </enumeratedValue>
                <enumeratedValue>
                  <name>1</name>
                  <description>LCD segment on or LCD backplane active for phase C</description>
                  <value>#1</value>
                </enumeratedValue>
              </enumeratedValues>
            </field>
            <field>
              <name>BPDLCD49</name>
              <description>no description available</description>
              <bitOffset>3</bitOffset>
              <bitWidth>1</bitWidth>
              <access>read-write</access>
              <enumeratedValues>
                <enumeratedValue>
                  <name>0</name>
                  <description>LCD segment off or LCD backplane inactive for phase D</description>
                  <value>#0</value>
                </enumeratedValue>
                <enumeratedValue>
                  <name>1</name>
                  <description>LCD segment on or LCD backplane active for phase D</description>
                  <value>#1</value>
                </enumeratedValue>
              </enumeratedValues>
            </field>
            <field>
              <name>BPELCD49</name>
              <description>no description available</description>
              <bitOffset>4</bitOffset>
              <bitWidth>1</bitWidth>
              <access>read-write</access>
              <enumeratedValues>
                <enumeratedValue>
                  <name>0</name>
                  <description>LCD segment off or LCD backplane inactive for phase E</description>
                  <value>#0</value>
                </enumeratedValue>
                <enumeratedValue>
                  <name>1</name>
                  <description>LCD segment on or LCD backplane active for phase E</description>
                  <value>#1</value>
                </enumeratedValue>
              </enumeratedValues>
            </field>
            <field>
              <name>BPFLCD49</name>
              <description>no description available</description>
              <bitOffset>5</bitOffset>
              <bitWidth>1</bitWidth>
              <access>read-write</access>
              <enumeratedValues>
                <enumeratedValue>
                  <name>0</name>
                  <description>LCD segment off or LCD backplane inactive for phase F</description>
                  <value>#0</value>
                </enumeratedValue>
                <enumeratedValue>
                  <name>1</name>
                  <description>LCD segment on or LCD backplane active for phase F</description>
                  <value>#1</value>
                </enumeratedValue>
              </enumeratedValues>
            </field>
            <field>
              <name>BPGLCD49</name>
              <description>no description available</description>
              <bitOffset>6</bitOffset>
              <bitWidth>1</bitWidth>
              <access>read-write</access>
              <enumeratedValues>
                <enumeratedValue>
                  <name>0</name>
                  <description>LCD segment off or LCD backplane inactive for phase G</description>
                  <value>#0</value>
                </enumeratedValue>
                <enumeratedValue>
                  <name>1</name>
                  <description>LCD segment on or LCD backplane active for phase G</description>
                  <value>#1</value>
                </enumeratedValue>
              </enumeratedValues>
            </field>
            <field>
              <name>BPHLCD49</name>
              <description>no description available</description>
              <bitOffset>7</bitOffset>
              <bitWidth>1</bitWidth>
              <access>read-write</access>
              <enumeratedValues>
                <enumeratedValue>
                  <name>0</name>
                  <description>LCD segment off or LCD backplane inactive for phase H</description>
                  <value>#0</value>
                </enumeratedValue>
                <enumeratedValue>
                  <name>1</name>
                  <description>LCD segment on or LCD backplane active for phase H</description>
                  <value>#1</value>
                </enumeratedValue>
              </enumeratedValues>
            </field>
          </fields>
        </register>
        <register>
          <name>WF50</name>
          <description>LCD Waveform Register 50.</description>
          <addressOffset>0x52</addressOffset>
          <size>8</size>
          <access>read-write</access>
          <resetValue>0</resetValue>
          <resetMask>0</resetMask>
          <fields>
            <field>
              <name>BPALCD50</name>
              <description>no description available</description>
              <bitOffset>0</bitOffset>
              <bitWidth>1</bitWidth>
              <access>read-write</access>
              <enumeratedValues>
                <enumeratedValue>
                  <name>0</name>
                  <description>LCD segment off or LCD backplane inactive for phase A</description>
                  <value>#0</value>
                </enumeratedValue>
                <enumeratedValue>
                  <name>1</name>
                  <description>LCD segment on or LCD backplane active for phase A</description>
                  <value>#1</value>
                </enumeratedValue>
              </enumeratedValues>
            </field>
            <field>
              <name>BPBLCD50</name>
              <description>no description available</description>
              <bitOffset>1</bitOffset>
              <bitWidth>1</bitWidth>
              <access>read-write</access>
              <enumeratedValues>
                <enumeratedValue>
                  <name>0</name>
                  <description>LCD segment off or LCD backplane inactive for phase B</description>
                  <value>#0</value>
                </enumeratedValue>
                <enumeratedValue>
                  <name>1</name>
                  <description>LCD segment on or LCD backplane active for phase B</description>
                  <value>#1</value>
                </enumeratedValue>
              </enumeratedValues>
            </field>
            <field>
              <name>BPCLCD50</name>
              <description>no description available</description>
              <bitOffset>2</bitOffset>
              <bitWidth>1</bitWidth>
              <access>read-write</access>
              <enumeratedValues>
                <enumeratedValue>
                  <name>0</name>
                  <description>LCD segment off or LCD backplane inactive for phase C</description>
                  <value>#0</value>
                </enumeratedValue>
                <enumeratedValue>
                  <name>1</name>
                  <description>LCD segment on or LCD backplane active for phase C</description>
                  <value>#1</value>
                </enumeratedValue>
              </enumeratedValues>
            </field>
            <field>
              <name>BPDLCD50</name>
              <description>no description available</description>
              <bitOffset>3</bitOffset>
              <bitWidth>1</bitWidth>
              <access>read-write</access>
              <enumeratedValues>
                <enumeratedValue>
                  <name>0</name>
                  <description>LCD segment off or LCD backplane inactive for phase D</description>
                  <value>#0</value>
                </enumeratedValue>
                <enumeratedValue>
                  <name>1</name>
                  <description>LCD segment on or LCD backplane active for phase D</description>
                  <value>#1</value>
                </enumeratedValue>
              </enumeratedValues>
            </field>
            <field>
              <name>BPELCD50</name>
              <description>no description available</description>
              <bitOffset>4</bitOffset>
              <bitWidth>1</bitWidth>
              <access>read-write</access>
              <enumeratedValues>
                <enumeratedValue>
                  <name>0</name>
                  <description>LCD segment off or LCD backplane inactive for phase E</description>
                  <value>#0</value>
                </enumeratedValue>
                <enumeratedValue>
                  <name>1</name>
                  <description>LCD segment on or LCD backplane active for phase E</description>
                  <value>#1</value>
                </enumeratedValue>
              </enumeratedValues>
            </field>
            <field>
              <name>BPFLCD50</name>
              <description>no description available</description>
              <bitOffset>5</bitOffset>
              <bitWidth>1</bitWidth>
              <access>read-write</access>
              <enumeratedValues>
                <enumeratedValue>
                  <name>0</name>
                  <description>LCD segment off or LCD backplane inactive for phase F</description>
                  <value>#0</value>
                </enumeratedValue>
                <enumeratedValue>
                  <name>1</name>
                  <description>LCD segment on or LCD backplane active for phase F</description>
                  <value>#1</value>
                </enumeratedValue>
              </enumeratedValues>
            </field>
            <field>
              <name>BPGLCD50</name>
              <description>no description available</description>
              <bitOffset>6</bitOffset>
              <bitWidth>1</bitWidth>
              <access>read-write</access>
              <enumeratedValues>
                <enumeratedValue>
                  <name>0</name>
                  <description>LCD segment off or LCD backplane inactive for phase G</description>
                  <value>#0</value>
                </enumeratedValue>
                <enumeratedValue>
                  <name>1</name>
                  <description>LCD segment on or LCD backplane active for phase G</description>
                  <value>#1</value>
                </enumeratedValue>
              </enumeratedValues>
            </field>
            <field>
              <name>BPHLCD50</name>
              <description>no description available</description>
              <bitOffset>7</bitOffset>
              <bitWidth>1</bitWidth>
              <access>read-write</access>
              <enumeratedValues>
                <enumeratedValue>
                  <name>0</name>
                  <description>LCD segment off or LCD backplane inactive for phase H</description>
                  <value>#0</value>
                </enumeratedValue>
                <enumeratedValue>
                  <name>1</name>
                  <description>LCD segment on or LCD backplane active for phase H</description>
                  <value>#1</value>
                </enumeratedValue>
              </enumeratedValues>
            </field>
          </fields>
        </register>
        <register>
          <name>WF51</name>
          <description>LCD Waveform Register 51.</description>
          <addressOffset>0x53</addressOffset>
          <size>8</size>
          <access>read-write</access>
          <resetValue>0</resetValue>
          <resetMask>0</resetMask>
          <fields>
            <field>
              <name>BPALCD51</name>
              <description>no description available</description>
              <bitOffset>0</bitOffset>
              <bitWidth>1</bitWidth>
              <access>read-write</access>
              <enumeratedValues>
                <enumeratedValue>
                  <name>0</name>
                  <description>LCD segment off or LCD backplane inactive for phase A</description>
                  <value>#0</value>
                </enumeratedValue>
                <enumeratedValue>
                  <name>1</name>
                  <description>LCD segment on or LCD backplane active for phase A</description>
                  <value>#1</value>
                </enumeratedValue>
              </enumeratedValues>
            </field>
            <field>
              <name>BPBLCD51</name>
              <description>no description available</description>
              <bitOffset>1</bitOffset>
              <bitWidth>1</bitWidth>
              <access>read-write</access>
              <enumeratedValues>
                <enumeratedValue>
                  <name>0</name>
                  <description>LCD segment off or LCD backplane inactive for phase B</description>
                  <value>#0</value>
                </enumeratedValue>
                <enumeratedValue>
                  <name>1</name>
                  <description>LCD segment on or LCD backplane active for phase B</description>
                  <value>#1</value>
                </enumeratedValue>
              </enumeratedValues>
            </field>
            <field>
              <name>BPCLCD51</name>
              <description>no description available</description>
              <bitOffset>2</bitOffset>
              <bitWidth>1</bitWidth>
              <access>read-write</access>
              <enumeratedValues>
                <enumeratedValue>
                  <name>0</name>
                  <description>LCD segment off or LCD backplane inactive for phase C</description>
                  <value>#0</value>
                </enumeratedValue>
                <enumeratedValue>
                  <name>1</name>
                  <description>LCD segment on or LCD backplane active for phase C</description>
                  <value>#1</value>
                </enumeratedValue>
              </enumeratedValues>
            </field>
            <field>
              <name>BPDLCD51</name>
              <description>no description available</description>
              <bitOffset>3</bitOffset>
              <bitWidth>1</bitWidth>
              <access>read-write</access>
              <enumeratedValues>
                <enumeratedValue>
                  <name>0</name>
                  <description>LCD segment off or LCD backplane inactive for phase D</description>
                  <value>#0</value>
                </enumeratedValue>
                <enumeratedValue>
                  <name>1</name>
                  <description>LCD segment on or LCD backplane active for phase D</description>
                  <value>#1</value>
                </enumeratedValue>
              </enumeratedValues>
            </field>
            <field>
              <name>BPELCD51</name>
              <description>no description available</description>
              <bitOffset>4</bitOffset>
              <bitWidth>1</bitWidth>
              <access>read-write</access>
              <enumeratedValues>
                <enumeratedValue>
                  <name>0</name>
                  <description>LCD segment off or LCD backplane inactive for phase E</description>
                  <value>#0</value>
                </enumeratedValue>
                <enumeratedValue>
                  <name>1</name>
                  <description>LCD segment on or LCD backplane active for phase E</description>
                  <value>#1</value>
                </enumeratedValue>
              </enumeratedValues>
            </field>
            <field>
              <name>BPFLCD51</name>
              <description>no description available</description>
              <bitOffset>5</bitOffset>
              <bitWidth>1</bitWidth>
              <access>read-write</access>
              <enumeratedValues>
                <enumeratedValue>
                  <name>0</name>
                  <description>LCD segment off or LCD backplane inactive for phase F</description>
                  <value>#0</value>
                </enumeratedValue>
                <enumeratedValue>
                  <name>1</name>
                  <description>LCD segment on or LCD backplane active for phase F</description>
                  <value>#1</value>
                </enumeratedValue>
              </enumeratedValues>
            </field>
            <field>
              <name>BPGLCD51</name>
              <description>no description available</description>
              <bitOffset>6</bitOffset>
              <bitWidth>1</bitWidth>
              <access>read-write</access>
              <enumeratedValues>
                <enumeratedValue>
                  <name>0</name>
                  <description>LCD segment off or LCD backplane inactive for phase G</description>
                  <value>#0</value>
                </enumeratedValue>
                <enumeratedValue>
                  <name>1</name>
                  <description>LCD segment on or LCD backplane active for phase G</description>
                  <value>#1</value>
                </enumeratedValue>
              </enumeratedValues>
            </field>
            <field>
              <name>BPHLCD51</name>
              <description>no description available</description>
              <bitOffset>7</bitOffset>
              <bitWidth>1</bitWidth>
              <access>read-write</access>
              <enumeratedValues>
                <enumeratedValue>
                  <name>0</name>
                  <description>LCD segment off or LCD backplane inactive for phase H</description>
                  <value>#0</value>
                </enumeratedValue>
                <enumeratedValue>
                  <name>1</name>
                  <description>LCD segment on or LCD backplane active for phase H</description>
                  <value>#1</value>
                </enumeratedValue>
              </enumeratedValues>
            </field>
          </fields>
        </register>
        <register>
          <name>WF55TO52</name>
          <description>LCD Waveform register</description>
          <alternateGroup>LCD</alternateGroup>
          <addressOffset>0x54</addressOffset>
          <size>32</size>
          <access>read-write</access>
          <resetValue>0</resetValue>
          <resetMask>0xFFFFFFFF</resetMask>
          <fields>
            <field>
              <name>WF52</name>
              <description>Controls segments or phases connected to LCD_P52 as described above for WF3TO0[WF3].</description>
              <bitOffset>0</bitOffset>
              <bitWidth>8</bitWidth>
              <access>read-write</access>
            </field>
            <field>
              <name>WF53</name>
              <description>Controls segments or phases connected to LCD_P53 as described above for WF3TO0[WF3].</description>
              <bitOffset>8</bitOffset>
              <bitWidth>8</bitWidth>
              <access>read-write</access>
            </field>
            <field>
              <name>WF54</name>
              <description>Controls segments or phases connected to LCD_P54 as described above for WF3TO0[WF3].</description>
              <bitOffset>16</bitOffset>
              <bitWidth>8</bitWidth>
              <access>read-write</access>
            </field>
            <field>
              <name>WF55</name>
              <description>Controls segments or phases connected to LCD_P55 as described above for WF3TO0[WF3].</description>
              <bitOffset>24</bitOffset>
              <bitWidth>8</bitWidth>
              <access>read-write</access>
            </field>
          </fields>
        </register>
        <register>
          <name>WF52</name>
          <description>LCD Waveform Register 52.</description>
          <alternateGroup>LCD</alternateGroup>
          <addressOffset>0x54</addressOffset>
          <size>8</size>
          <access>read-write</access>
          <resetValue>0</resetValue>
          <resetMask>0</resetMask>
          <fields>
            <field>
              <name>BPALCD52</name>
              <description>no description available</description>
              <bitOffset>0</bitOffset>
              <bitWidth>1</bitWidth>
              <access>read-write</access>
              <enumeratedValues>
                <enumeratedValue>
                  <name>0</name>
                  <description>LCD segment off or LCD backplane inactive for phase A</description>
                  <value>#0</value>
                </enumeratedValue>
                <enumeratedValue>
                  <name>1</name>
                  <description>LCD segment on or LCD backplane active for phase A</description>
                  <value>#1</value>
                </enumeratedValue>
              </enumeratedValues>
            </field>
            <field>
              <name>BPBLCD52</name>
              <description>no description available</description>
              <bitOffset>1</bitOffset>
              <bitWidth>1</bitWidth>
              <access>read-write</access>
              <enumeratedValues>
                <enumeratedValue>
                  <name>0</name>
                  <description>LCD segment off or LCD backplane inactive for phase B</description>
                  <value>#0</value>
                </enumeratedValue>
                <enumeratedValue>
                  <name>1</name>
                  <description>LCD segment on or LCD backplane active for phase B</description>
                  <value>#1</value>
                </enumeratedValue>
              </enumeratedValues>
            </field>
            <field>
              <name>BPCLCD52</name>
              <description>no description available</description>
              <bitOffset>2</bitOffset>
              <bitWidth>1</bitWidth>
              <access>read-write</access>
              <enumeratedValues>
                <enumeratedValue>
                  <name>0</name>
                  <description>LCD segment off or LCD backplane inactive for phase C</description>
                  <value>#0</value>
                </enumeratedValue>
                <enumeratedValue>
                  <name>1</name>
                  <description>LCD segment on or LCD backplane active for phase C</description>
                  <value>#1</value>
                </enumeratedValue>
              </enumeratedValues>
            </field>
            <field>
              <name>BPDLCD52</name>
              <description>no description available</description>
              <bitOffset>3</bitOffset>
              <bitWidth>1</bitWidth>
              <access>read-write</access>
              <enumeratedValues>
                <enumeratedValue>
                  <name>0</name>
                  <description>LCD segment off or LCD backplane inactive for phase D</description>
                  <value>#0</value>
                </enumeratedValue>
                <enumeratedValue>
                  <name>1</name>
                  <description>LCD segment on or LCD backplane active for phase D</description>
                  <value>#1</value>
                </enumeratedValue>
              </enumeratedValues>
            </field>
            <field>
              <name>BPELCD52</name>
              <description>no description available</description>
              <bitOffset>4</bitOffset>
              <bitWidth>1</bitWidth>
              <access>read-write</access>
              <enumeratedValues>
                <enumeratedValue>
                  <name>0</name>
                  <description>LCD segment off or LCD backplane inactive for phase E</description>
                  <value>#0</value>
                </enumeratedValue>
                <enumeratedValue>
                  <name>1</name>
                  <description>LCD segment on or LCD backplane active for phase E</description>
                  <value>#1</value>
                </enumeratedValue>
              </enumeratedValues>
            </field>
            <field>
              <name>BPFLCD52</name>
              <description>no description available</description>
              <bitOffset>5</bitOffset>
              <bitWidth>1</bitWidth>
              <access>read-write</access>
              <enumeratedValues>
                <enumeratedValue>
                  <name>0</name>
                  <description>LCD segment off or LCD backplane inactive for phase F</description>
                  <value>#0</value>
                </enumeratedValue>
                <enumeratedValue>
                  <name>1</name>
                  <description>LCD segment on or LCD backplane active for phase F</description>
                  <value>#1</value>
                </enumeratedValue>
              </enumeratedValues>
            </field>
            <field>
              <name>BPGLCD52</name>
              <description>no description available</description>
              <bitOffset>6</bitOffset>
              <bitWidth>1</bitWidth>
              <access>read-write</access>
              <enumeratedValues>
                <enumeratedValue>
                  <name>0</name>
                  <description>LCD segment off or LCD backplane inactive for phase G</description>
                  <value>#0</value>
                </enumeratedValue>
                <enumeratedValue>
                  <name>1</name>
                  <description>LCD segment on or LCD backplane active for phase G</description>
                  <value>#1</value>
                </enumeratedValue>
              </enumeratedValues>
            </field>
            <field>
              <name>BPHLCD52</name>
              <description>no description available</description>
              <bitOffset>7</bitOffset>
              <bitWidth>1</bitWidth>
              <access>read-write</access>
              <enumeratedValues>
                <enumeratedValue>
                  <name>0</name>
                  <description>LCD segment off or LCD backplane inactive for phase H</description>
                  <value>#0</value>
                </enumeratedValue>
                <enumeratedValue>
                  <name>1</name>
                  <description>LCD segment on or LCD backplane active for phase H</description>
                  <value>#1</value>
                </enumeratedValue>
              </enumeratedValues>
            </field>
          </fields>
        </register>
        <register>
          <name>WF53</name>
          <description>LCD Waveform Register 53.</description>
          <addressOffset>0x55</addressOffset>
          <size>8</size>
          <access>read-write</access>
          <resetValue>0</resetValue>
          <resetMask>0</resetMask>
          <fields>
            <field>
              <name>BPALCD53</name>
              <description>no description available</description>
              <bitOffset>0</bitOffset>
              <bitWidth>1</bitWidth>
              <access>read-write</access>
              <enumeratedValues>
                <enumeratedValue>
                  <name>0</name>
                  <description>LCD segment off or LCD backplane inactive for phase A</description>
                  <value>#0</value>
                </enumeratedValue>
                <enumeratedValue>
                  <name>1</name>
                  <description>LCD segment on or LCD backplane active for phase A</description>
                  <value>#1</value>
                </enumeratedValue>
              </enumeratedValues>
            </field>
            <field>
              <name>BPBLCD53</name>
              <description>no description available</description>
              <bitOffset>1</bitOffset>
              <bitWidth>1</bitWidth>
              <access>read-write</access>
              <enumeratedValues>
                <enumeratedValue>
                  <name>0</name>
                  <description>LCD segment off or LCD backplane inactive for phase B</description>
                  <value>#0</value>
                </enumeratedValue>
                <enumeratedValue>
                  <name>1</name>
                  <description>LCD segment on or LCD backplane active for phase B</description>
                  <value>#1</value>
                </enumeratedValue>
              </enumeratedValues>
            </field>
            <field>
              <name>BPCLCD53</name>
              <description>no description available</description>
              <bitOffset>2</bitOffset>
              <bitWidth>1</bitWidth>
              <access>read-write</access>
              <enumeratedValues>
                <enumeratedValue>
                  <name>0</name>
                  <description>LCD segment off or LCD backplane inactive for phase C</description>
                  <value>#0</value>
                </enumeratedValue>
                <enumeratedValue>
                  <name>1</name>
                  <description>LCD segment on or LCD backplane active for phase C</description>
                  <value>#1</value>
                </enumeratedValue>
              </enumeratedValues>
            </field>
            <field>
              <name>BPDLCD53</name>
              <description>no description available</description>
              <bitOffset>3</bitOffset>
              <bitWidth>1</bitWidth>
              <access>read-write</access>
              <enumeratedValues>
                <enumeratedValue>
                  <name>0</name>
                  <description>LCD segment off or LCD backplane inactive for phase D</description>
                  <value>#0</value>
                </enumeratedValue>
                <enumeratedValue>
                  <name>1</name>
                  <description>LCD segment on or LCD backplane active for phase D</description>
                  <value>#1</value>
                </enumeratedValue>
              </enumeratedValues>
            </field>
            <field>
              <name>BPELCD53</name>
              <description>no description available</description>
              <bitOffset>4</bitOffset>
              <bitWidth>1</bitWidth>
              <access>read-write</access>
              <enumeratedValues>
                <enumeratedValue>
                  <name>0</name>
                  <description>LCD segment off or LCD backplane inactive for phase E</description>
                  <value>#0</value>
                </enumeratedValue>
                <enumeratedValue>
                  <name>1</name>
                  <description>LCD segment on or LCD backplane active for phase E</description>
                  <value>#1</value>
                </enumeratedValue>
              </enumeratedValues>
            </field>
            <field>
              <name>BPFLCD53</name>
              <description>no description available</description>
              <bitOffset>5</bitOffset>
              <bitWidth>1</bitWidth>
              <access>read-write</access>
              <enumeratedValues>
                <enumeratedValue>
                  <name>0</name>
                  <description>LCD segment off or LCD backplane inactive for phase F</description>
                  <value>#0</value>
                </enumeratedValue>
                <enumeratedValue>
                  <name>1</name>
                  <description>LCD segment on or LCD backplane active for phase F</description>
                  <value>#1</value>
                </enumeratedValue>
              </enumeratedValues>
            </field>
            <field>
              <name>BPGLCD53</name>
              <description>no description available</description>
              <bitOffset>6</bitOffset>
              <bitWidth>1</bitWidth>
              <access>read-write</access>
              <enumeratedValues>
                <enumeratedValue>
                  <name>0</name>
                  <description>LCD segment off or LCD backplane inactive for phase G</description>
                  <value>#0</value>
                </enumeratedValue>
                <enumeratedValue>
                  <name>1</name>
                  <description>LCD segment on or LCD backplane active for phase G</description>
                  <value>#1</value>
                </enumeratedValue>
              </enumeratedValues>
            </field>
            <field>
              <name>BPHLCD53</name>
              <description>no description available</description>
              <bitOffset>7</bitOffset>
              <bitWidth>1</bitWidth>
              <access>read-write</access>
              <enumeratedValues>
                <enumeratedValue>
                  <name>0</name>
                  <description>LCD segment off or LCD backplane inactive for phase H</description>
                  <value>#0</value>
                </enumeratedValue>
                <enumeratedValue>
                  <name>1</name>
                  <description>LCD segment on or LCD backplane active for phase H</description>
                  <value>#1</value>
                </enumeratedValue>
              </enumeratedValues>
            </field>
          </fields>
        </register>
        <register>
          <name>WF54</name>
          <description>LCD Waveform Register 54.</description>
          <addressOffset>0x56</addressOffset>
          <size>8</size>
          <access>read-write</access>
          <resetValue>0</resetValue>
          <resetMask>0</resetMask>
          <fields>
            <field>
              <name>BPALCD54</name>
              <description>no description available</description>
              <bitOffset>0</bitOffset>
              <bitWidth>1</bitWidth>
              <access>read-write</access>
              <enumeratedValues>
                <enumeratedValue>
                  <name>0</name>
                  <description>LCD segment off or LCD backplane inactive for phase A</description>
                  <value>#0</value>
                </enumeratedValue>
                <enumeratedValue>
                  <name>1</name>
                  <description>LCD segment on or LCD backplane active for phase A</description>
                  <value>#1</value>
                </enumeratedValue>
              </enumeratedValues>
            </field>
            <field>
              <name>BPBLCD54</name>
              <description>no description available</description>
              <bitOffset>1</bitOffset>
              <bitWidth>1</bitWidth>
              <access>read-write</access>
              <enumeratedValues>
                <enumeratedValue>
                  <name>0</name>
                  <description>LCD segment off or LCD backplane inactive for phase B</description>
                  <value>#0</value>
                </enumeratedValue>
                <enumeratedValue>
                  <name>1</name>
                  <description>LCD segment on or LCD backplane active for phase B</description>
                  <value>#1</value>
                </enumeratedValue>
              </enumeratedValues>
            </field>
            <field>
              <name>BPCLCD54</name>
              <description>no description available</description>
              <bitOffset>2</bitOffset>
              <bitWidth>1</bitWidth>
              <access>read-write</access>
              <enumeratedValues>
                <enumeratedValue>
                  <name>0</name>
                  <description>LCD segment off or LCD backplane inactive for phase C</description>
                  <value>#0</value>
                </enumeratedValue>
                <enumeratedValue>
                  <name>1</name>
                  <description>LCD segment on or LCD backplane active for phase C</description>
                  <value>#1</value>
                </enumeratedValue>
              </enumeratedValues>
            </field>
            <field>
              <name>BPDLCD54</name>
              <description>no description available</description>
              <bitOffset>3</bitOffset>
              <bitWidth>1</bitWidth>
              <access>read-write</access>
              <enumeratedValues>
                <enumeratedValue>
                  <name>0</name>
                  <description>LCD segment off or LCD backplane inactive for phase D</description>
                  <value>#0</value>
                </enumeratedValue>
                <enumeratedValue>
                  <name>1</name>
                  <description>LCD segment on or LCD backplane active for phase D</description>
                  <value>#1</value>
                </enumeratedValue>
              </enumeratedValues>
            </field>
            <field>
              <name>BPELCD54</name>
              <description>no description available</description>
              <bitOffset>4</bitOffset>
              <bitWidth>1</bitWidth>
              <access>read-write</access>
              <enumeratedValues>
                <enumeratedValue>
                  <name>0</name>
                  <description>LCD segment off or LCD backplane inactive for phase E</description>
                  <value>#0</value>
                </enumeratedValue>
                <enumeratedValue>
                  <name>1</name>
                  <description>LCD segment on or LCD backplane active for phase E</description>
                  <value>#1</value>
                </enumeratedValue>
              </enumeratedValues>
            </field>
            <field>
              <name>BPFLCD54</name>
              <description>no description available</description>
              <bitOffset>5</bitOffset>
              <bitWidth>1</bitWidth>
              <access>read-write</access>
              <enumeratedValues>
                <enumeratedValue>
                  <name>0</name>
                  <description>LCD segment off or LCD backplane inactive for phase F</description>
                  <value>#0</value>
                </enumeratedValue>
                <enumeratedValue>
                  <name>1</name>
                  <description>LCD segment on or LCD backplane active for phase F</description>
                  <value>#1</value>
                </enumeratedValue>
              </enumeratedValues>
            </field>
            <field>
              <name>BPGLCD54</name>
              <description>no description available</description>
              <bitOffset>6</bitOffset>
              <bitWidth>1</bitWidth>
              <access>read-write</access>
              <enumeratedValues>
                <enumeratedValue>
                  <name>0</name>
                  <description>LCD segment off or LCD backplane inactive for phase G</description>
                  <value>#0</value>
                </enumeratedValue>
                <enumeratedValue>
                  <name>1</name>
                  <description>LCD segment on or LCD backplane active for phase G</description>
                  <value>#1</value>
                </enumeratedValue>
              </enumeratedValues>
            </field>
            <field>
              <name>BPHLCD54</name>
              <description>no description available</description>
              <bitOffset>7</bitOffset>
              <bitWidth>1</bitWidth>
              <access>read-write</access>
              <enumeratedValues>
                <enumeratedValue>
                  <name>0</name>
                  <description>LCD segment off or LCD backplane inactive for phase H</description>
                  <value>#0</value>
                </enumeratedValue>
                <enumeratedValue>
                  <name>1</name>
                  <description>LCD segment on or LCD backplane active for phase H</description>
                  <value>#1</value>
                </enumeratedValue>
              </enumeratedValues>
            </field>
          </fields>
        </register>
        <register>
          <name>WF55</name>
          <description>LCD Waveform Register 55.</description>
          <addressOffset>0x57</addressOffset>
          <size>8</size>
          <access>read-write</access>
          <resetValue>0</resetValue>
          <resetMask>0</resetMask>
          <fields>
            <field>
              <name>BPALCD55</name>
              <description>no description available</description>
              <bitOffset>0</bitOffset>
              <bitWidth>1</bitWidth>
              <access>read-write</access>
              <enumeratedValues>
                <enumeratedValue>
                  <name>0</name>
                  <description>LCD segment off or LCD backplane inactive for phase A</description>
                  <value>#0</value>
                </enumeratedValue>
                <enumeratedValue>
                  <name>1</name>
                  <description>LCD segment on or LCD backplane active for phase A</description>
                  <value>#1</value>
                </enumeratedValue>
              </enumeratedValues>
            </field>
            <field>
              <name>BPBLCD55</name>
              <description>no description available</description>
              <bitOffset>1</bitOffset>
              <bitWidth>1</bitWidth>
              <access>read-write</access>
              <enumeratedValues>
                <enumeratedValue>
                  <name>0</name>
                  <description>LCD segment off or LCD backplane inactive for phase B</description>
                  <value>#0</value>
                </enumeratedValue>
                <enumeratedValue>
                  <name>1</name>
                  <description>LCD segment on or LCD backplane active for phase B</description>
                  <value>#1</value>
                </enumeratedValue>
              </enumeratedValues>
            </field>
            <field>
              <name>BPCLCD55</name>
              <description>no description available</description>
              <bitOffset>2</bitOffset>
              <bitWidth>1</bitWidth>
              <access>read-write</access>
              <enumeratedValues>
                <enumeratedValue>
                  <name>0</name>
                  <description>LCD segment off or LCD backplane inactive for phase C</description>
                  <value>#0</value>
                </enumeratedValue>
                <enumeratedValue>
                  <name>1</name>
                  <description>LCD segment on or LCD backplane active for phase C</description>
                  <value>#1</value>
                </enumeratedValue>
              </enumeratedValues>
            </field>
            <field>
              <name>BPDLCD55</name>
              <description>no description available</description>
              <bitOffset>3</bitOffset>
              <bitWidth>1</bitWidth>
              <access>read-write</access>
              <enumeratedValues>
                <enumeratedValue>
                  <name>0</name>
                  <description>LCD segment off or LCD backplane inactive for phase D</description>
                  <value>#0</value>
                </enumeratedValue>
                <enumeratedValue>
                  <name>1</name>
                  <description>LCD segment on or LCD backplane active for phase D</description>
                  <value>#1</value>
                </enumeratedValue>
              </enumeratedValues>
            </field>
            <field>
              <name>BPELCD55</name>
              <description>no description available</description>
              <bitOffset>4</bitOffset>
              <bitWidth>1</bitWidth>
              <access>read-write</access>
              <enumeratedValues>
                <enumeratedValue>
                  <name>0</name>
                  <description>LCD segment off or LCD backplane inactive for phase E</description>
                  <value>#0</value>
                </enumeratedValue>
                <enumeratedValue>
                  <name>1</name>
                  <description>LCD segment on or LCD backplane active for phase E</description>
                  <value>#1</value>
                </enumeratedValue>
              </enumeratedValues>
            </field>
            <field>
              <name>BPFLCD55</name>
              <description>no description available</description>
              <bitOffset>5</bitOffset>
              <bitWidth>1</bitWidth>
              <access>read-write</access>
              <enumeratedValues>
                <enumeratedValue>
                  <name>0</name>
                  <description>LCD segment off or LCD backplane inactive for phase F</description>
                  <value>#0</value>
                </enumeratedValue>
                <enumeratedValue>
                  <name>1</name>
                  <description>LCD segment on or LCD backplane active for phase F</description>
                  <value>#1</value>
                </enumeratedValue>
              </enumeratedValues>
            </field>
            <field>
              <name>BPGLCD55</name>
              <description>no description available</description>
              <bitOffset>6</bitOffset>
              <bitWidth>1</bitWidth>
              <access>read-write</access>
              <enumeratedValues>
                <enumeratedValue>
                  <name>0</name>
                  <description>LCD segment off or LCD backplane inactive for phase G</description>
                  <value>#0</value>
                </enumeratedValue>
                <enumeratedValue>
                  <name>1</name>
                  <description>LCD segment on or LCD backplane active for phase G</description>
                  <value>#1</value>
                </enumeratedValue>
              </enumeratedValues>
            </field>
            <field>
              <name>BPHLCD55</name>
              <description>no description available</description>
              <bitOffset>7</bitOffset>
              <bitWidth>1</bitWidth>
              <access>read-write</access>
              <enumeratedValues>
                <enumeratedValue>
                  <name>0</name>
                  <description>LCD segment off or LCD backplane inactive for phase H</description>
                  <value>#0</value>
                </enumeratedValue>
                <enumeratedValue>
                  <name>1</name>
                  <description>LCD segment on or LCD backplane active for phase H</description>
                  <value>#1</value>
                </enumeratedValue>
              </enumeratedValues>
            </field>
          </fields>
        </register>
        <register>
          <name>WF59TO56</name>
          <description>LCD Waveform register</description>
          <alternateGroup>LCD</alternateGroup>
          <addressOffset>0x58</addressOffset>
          <size>32</size>
          <access>read-write</access>
          <resetValue>0</resetValue>
          <resetMask>0xFFFFFFFF</resetMask>
          <fields>
            <field>
              <name>WF56</name>
              <description>Controls segments or phases connected to LCD_P56 as described above for WF3TO0[WF3].</description>
              <bitOffset>0</bitOffset>
              <bitWidth>8</bitWidth>
              <access>read-write</access>
            </field>
            <field>
              <name>WF57</name>
              <description>Controls segments or phases connected to LCD_P57 as described above for WF3TO0[WF3].</description>
              <bitOffset>8</bitOffset>
              <bitWidth>8</bitWidth>
              <access>read-write</access>
            </field>
            <field>
              <name>WF58</name>
              <description>Controls segments or phases connected to LCD_P58 as described above for WF3TO0[WF3].</description>
              <bitOffset>16</bitOffset>
              <bitWidth>8</bitWidth>
              <access>read-write</access>
            </field>
            <field>
              <name>WF59</name>
              <description>Controls segments or phases connected to LCD_P59 as described above for WF3TO0[WF3].</description>
              <bitOffset>24</bitOffset>
              <bitWidth>8</bitWidth>
              <access>read-write</access>
            </field>
          </fields>
        </register>
        <register>
          <name>WF56</name>
          <description>LCD Waveform Register 56.</description>
          <alternateGroup>LCD</alternateGroup>
          <addressOffset>0x58</addressOffset>
          <size>8</size>
          <access>read-write</access>
          <resetValue>0</resetValue>
          <resetMask>0</resetMask>
          <fields>
            <field>
              <name>BPALCD56</name>
              <description>no description available</description>
              <bitOffset>0</bitOffset>
              <bitWidth>1</bitWidth>
              <access>read-write</access>
              <enumeratedValues>
                <enumeratedValue>
                  <name>0</name>
                  <description>LCD segment off or LCD backplane inactive for phase A</description>
                  <value>#0</value>
                </enumeratedValue>
                <enumeratedValue>
                  <name>1</name>
                  <description>LCD segment on or LCD backplane active for phase A</description>
                  <value>#1</value>
                </enumeratedValue>
              </enumeratedValues>
            </field>
            <field>
              <name>BPBLCD56</name>
              <description>no description available</description>
              <bitOffset>1</bitOffset>
              <bitWidth>1</bitWidth>
              <access>read-write</access>
              <enumeratedValues>
                <enumeratedValue>
                  <name>0</name>
                  <description>LCD segment off or LCD backplane inactive for phase B</description>
                  <value>#0</value>
                </enumeratedValue>
                <enumeratedValue>
                  <name>1</name>
                  <description>LCD segment on or LCD backplane active for phase B</description>
                  <value>#1</value>
                </enumeratedValue>
              </enumeratedValues>
            </field>
            <field>
              <name>BPCLCD56</name>
              <description>no description available</description>
              <bitOffset>2</bitOffset>
              <bitWidth>1</bitWidth>
              <access>read-write</access>
              <enumeratedValues>
                <enumeratedValue>
                  <name>0</name>
                  <description>LCD segment off or LCD backplane inactive for phase C</description>
                  <value>#0</value>
                </enumeratedValue>
                <enumeratedValue>
                  <name>1</name>
                  <description>LCD segment on or LCD backplane active for phase C</description>
                  <value>#1</value>
                </enumeratedValue>
              </enumeratedValues>
            </field>
            <field>
              <name>BPDLCD56</name>
              <description>no description available</description>
              <bitOffset>3</bitOffset>
              <bitWidth>1</bitWidth>
              <access>read-write</access>
              <enumeratedValues>
                <enumeratedValue>
                  <name>0</name>
                  <description>LCD segment off or LCD backplane inactive for phase D</description>
                  <value>#0</value>
                </enumeratedValue>
                <enumeratedValue>
                  <name>1</name>
                  <description>LCD segment on or LCD backplane active for phase D</description>
                  <value>#1</value>
                </enumeratedValue>
              </enumeratedValues>
            </field>
            <field>
              <name>BPELCD56</name>
              <description>no description available</description>
              <bitOffset>4</bitOffset>
              <bitWidth>1</bitWidth>
              <access>read-write</access>
              <enumeratedValues>
                <enumeratedValue>
                  <name>0</name>
                  <description>LCD segment off or LCD backplane inactive for phase E</description>
                  <value>#0</value>
                </enumeratedValue>
                <enumeratedValue>
                  <name>1</name>
                  <description>LCD segment on or LCD backplane active for phase E</description>
                  <value>#1</value>
                </enumeratedValue>
              </enumeratedValues>
            </field>
            <field>
              <name>BPFLCD56</name>
              <description>no description available</description>
              <bitOffset>5</bitOffset>
              <bitWidth>1</bitWidth>
